VERSION 5.8 ;
BUSBITCHARS "[]" ;
DIVIDERCHAR "/" ;
UNITS
    DATABASE MICRONS 1000 ;
END UNITS

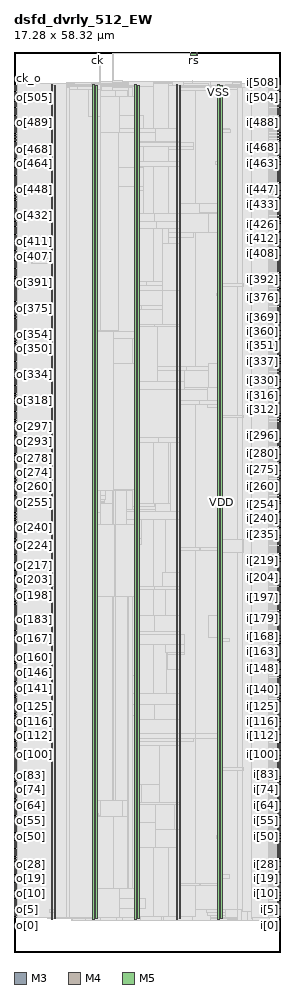
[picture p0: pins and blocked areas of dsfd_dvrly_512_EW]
MACRO dsfd_dvrly_512_EW
  FOREIGN dsfd_dvrly_512_EW 0 0 ;
  CLASS BLOCK ;
  SIZE 17.28 BY 58.32 ;
  PIN ck
    DIRECTION INPUT ;
    USE SIGNAL ;
    PORT
      LAYER M3 ;
        RECT  5.4 58.176 5.418 58.32 ;
    END
    PORT
      LAYER M3 ;
        RECT  5.4 57.595 5.418 58.188 ;
    END
  END ck
  PIN ck_o
    DIRECTION OUTPUT ;
    USE SIGNAL ;
    PORT
      LAYER M4 ;
        RECT  0 56.112 0.192 56.136 ;
    END
  END ck_o
  PIN i[0]
    DIRECTION INPUT ;
    USE SIGNAL ;
    PORT
      LAYER M4 ;
        RECT  17.088 2.208 17.28 2.232 ;
    END
  END i[0]
  PIN i[100]
    DIRECTION INPUT ;
    USE SIGNAL ;
    PORT
      LAYER M4 ;
        RECT  17.088 12.768 17.28 12.792 ;
    END
  END i[100]
  PIN i[101]
    DIRECTION INPUT ;
    USE SIGNAL ;
    PORT
      LAYER M4 ;
        RECT  17.088 12.864 17.28 12.888 ;
    END
  END i[101]
  PIN i[102]
    DIRECTION INPUT ;
    USE SIGNAL ;
    PORT
      LAYER M4 ;
        RECT  17.088 12.96 17.28 12.984 ;
    END
  END i[102]
  PIN i[103]
    DIRECTION INPUT ;
    USE SIGNAL ;
    PORT
      LAYER M4 ;
        RECT  17.088 13.104 17.28 13.128 ;
    END
  END i[103]
  PIN i[104]
    DIRECTION INPUT ;
    USE SIGNAL ;
    PORT
      LAYER M4 ;
        RECT  17.088 13.2 17.28 13.224 ;
    END
  END i[104]
  PIN i[105]
    DIRECTION INPUT ;
    USE SIGNAL ;
    PORT
      LAYER M4 ;
        RECT  17.088 13.296 17.28 13.32 ;
    END
  END i[105]
  PIN i[106]
    DIRECTION INPUT ;
    USE SIGNAL ;
    PORT
      LAYER M4 ;
        RECT  17.088 13.392 17.28 13.416 ;
    END
  END i[106]
  PIN i[107]
    DIRECTION INPUT ;
    USE SIGNAL ;
    PORT
      LAYER M4 ;
        RECT  17.088 13.488 17.28 13.512 ;
    END
  END i[107]
  PIN i[108]
    DIRECTION INPUT ;
    USE SIGNAL ;
    PORT
      LAYER M4 ;
        RECT  17.088 13.632 17.28 13.656 ;
    END
  END i[108]
  PIN i[109]
    DIRECTION INPUT ;
    USE SIGNAL ;
    PORT
      LAYER M4 ;
        RECT  17.088 13.728 17.28 13.752 ;
    END
  END i[109]
  PIN i[10]
    DIRECTION INPUT ;
    USE SIGNAL ;
    PORT
      LAYER M4 ;
        RECT  17.088 3.264 17.28 3.288 ;
    END
  END i[10]
  PIN i[110]
    DIRECTION INPUT ;
    USE SIGNAL ;
    PORT
      LAYER M4 ;
        RECT  17.088 13.824 17.28 13.848 ;
    END
  END i[110]
  PIN i[111]
    DIRECTION INPUT ;
    USE SIGNAL ;
    PORT
      LAYER M4 ;
        RECT  17.088 13.92 17.28 13.944 ;
    END
  END i[111]
  PIN i[112]
    DIRECTION INPUT ;
    USE SIGNAL ;
    PORT
      LAYER M4 ;
        RECT  17.088 14.016 17.28 14.04 ;
    END
  END i[112]
  PIN i[113]
    DIRECTION INPUT ;
    USE SIGNAL ;
    PORT
      LAYER M4 ;
        RECT  17.088 14.16 17.28 14.184 ;
    END
  END i[113]
  PIN i[114]
    DIRECTION INPUT ;
    USE SIGNAL ;
    PORT
      LAYER M4 ;
        RECT  17.088 14.256 17.28 14.28 ;
    END
  END i[114]
  PIN i[115]
    DIRECTION INPUT ;
    USE SIGNAL ;
    PORT
      LAYER M4 ;
        RECT  17.088 14.352 17.28 14.376 ;
    END
  END i[115]
  PIN i[116]
    DIRECTION INPUT ;
    USE SIGNAL ;
    PORT
      LAYER M4 ;
        RECT  17.088 14.448 17.28 14.472 ;
    END
  END i[116]
  PIN i[117]
    DIRECTION INPUT ;
    USE SIGNAL ;
    PORT
      LAYER M4 ;
        RECT  17.088 14.544 17.28 14.568 ;
    END
  END i[117]
  PIN i[118]
    DIRECTION INPUT ;
    USE SIGNAL ;
    PORT
      LAYER M4 ;
        RECT  17.088 14.688 17.28 14.712 ;
    END
  END i[118]
  PIN i[119]
    DIRECTION INPUT ;
    USE SIGNAL ;
    PORT
      LAYER M4 ;
        RECT  17.088 14.784 17.28 14.808 ;
    END
  END i[119]
  PIN i[11]
    DIRECTION INPUT ;
    USE SIGNAL ;
    PORT
      LAYER M4 ;
        RECT  17.088 3.408 17.28 3.432 ;
    END
  END i[11]
  PIN i[120]
    DIRECTION INPUT ;
    USE SIGNAL ;
    PORT
      LAYER M4 ;
        RECT  17.088 14.88 17.28 14.904 ;
    END
  END i[120]
  PIN i[121]
    DIRECTION INPUT ;
    USE SIGNAL ;
    PORT
      LAYER M4 ;
        RECT  17.088 14.976 17.28 15 ;
    END
  END i[121]
  PIN i[122]
    DIRECTION INPUT ;
    USE SIGNAL ;
    PORT
      LAYER M4 ;
        RECT  17.088 15.072 17.28 15.096 ;
    END
  END i[122]
  PIN i[123]
    DIRECTION INPUT ;
    USE SIGNAL ;
    PORT
      LAYER M4 ;
        RECT  17.088 15.216 17.28 15.24 ;
    END
  END i[123]
  PIN i[124]
    DIRECTION INPUT ;
    USE SIGNAL ;
    PORT
      LAYER M4 ;
        RECT  17.088 15.312 17.28 15.336 ;
    END
  END i[124]
  PIN i[125]
    DIRECTION INPUT ;
    USE SIGNAL ;
    PORT
      LAYER M4 ;
        RECT  17.088 15.408 17.28 15.432 ;
    END
  END i[125]
  PIN i[126]
    DIRECTION INPUT ;
    USE SIGNAL ;
    PORT
      LAYER M4 ;
        RECT  17.088 15.504 17.28 15.528 ;
    END
  END i[126]
  PIN i[127]
    DIRECTION INPUT ;
    USE SIGNAL ;
    PORT
      LAYER M4 ;
        RECT  17.088 15.6 17.28 15.624 ;
    END
  END i[127]
  PIN i[128]
    DIRECTION INPUT ;
    USE SIGNAL ;
    PORT
      LAYER M4 ;
        RECT  17.088 15.744 17.28 15.768 ;
    END
  END i[128]
  PIN i[129]
    DIRECTION INPUT ;
    USE SIGNAL ;
    PORT
      LAYER M4 ;
        RECT  17.088 15.84 17.28 15.864 ;
    END
  END i[129]
  PIN i[12]
    DIRECTION INPUT ;
    USE SIGNAL ;
    PORT
      LAYER M4 ;
        RECT  17.088 3.504 17.28 3.528 ;
    END
  END i[12]
  PIN i[130]
    DIRECTION INPUT ;
    USE SIGNAL ;
    PORT
      LAYER M4 ;
        RECT  17.088 15.936 17.28 15.96 ;
    END
  END i[130]
  PIN i[131]
    DIRECTION INPUT ;
    USE SIGNAL ;
    PORT
      LAYER M4 ;
        RECT  17.088 16.032 17.28 16.056 ;
    END
  END i[131]
  PIN i[132]
    DIRECTION INPUT ;
    USE SIGNAL ;
    PORT
      LAYER M4 ;
        RECT  17.088 16.128 17.28 16.152 ;
    END
  END i[132]
  PIN i[133]
    DIRECTION INPUT ;
    USE SIGNAL ;
    PORT
      LAYER M4 ;
        RECT  17.088 16.272 17.28 16.296 ;
    END
  END i[133]
  PIN i[134]
    DIRECTION INPUT ;
    USE SIGNAL ;
    PORT
      LAYER M4 ;
        RECT  17.088 16.368 17.28 16.392 ;
    END
  END i[134]
  PIN i[135]
    DIRECTION INPUT ;
    USE SIGNAL ;
    PORT
      LAYER M4 ;
        RECT  17.088 16.464 17.28 16.488 ;
    END
  END i[135]
  PIN i[136]
    DIRECTION INPUT ;
    USE SIGNAL ;
    PORT
      LAYER M4 ;
        RECT  17.088 16.56 17.28 16.584 ;
    END
  END i[136]
  PIN i[137]
    DIRECTION INPUT ;
    USE SIGNAL ;
    PORT
      LAYER M4 ;
        RECT  17.088 16.656 17.28 16.68 ;
    END
  END i[137]
  PIN i[138]
    DIRECTION INPUT ;
    USE SIGNAL ;
    PORT
      LAYER M4 ;
        RECT  17.088 16.8 17.28 16.824 ;
    END
  END i[138]
  PIN i[139]
    DIRECTION INPUT ;
    USE SIGNAL ;
    PORT
      LAYER M4 ;
        RECT  17.088 16.896 17.28 16.92 ;
    END
  END i[139]
  PIN i[13]
    DIRECTION INPUT ;
    USE SIGNAL ;
    PORT
      LAYER M4 ;
        RECT  17.088 3.6 17.28 3.624 ;
    END
  END i[13]
  PIN i[140]
    DIRECTION INPUT ;
    USE SIGNAL ;
    PORT
      LAYER M4 ;
        RECT  17.088 16.992 17.28 17.016 ;
    END
  END i[140]
  PIN i[141]
    DIRECTION INPUT ;
    USE SIGNAL ;
    PORT
      LAYER M4 ;
        RECT  17.088 17.088 17.28 17.112 ;
    END
  END i[141]
  PIN i[142]
    DIRECTION INPUT ;
    USE SIGNAL ;
    PORT
      LAYER M4 ;
        RECT  17.088 17.184 17.28 17.208 ;
    END
  END i[142]
  PIN i[143]
    DIRECTION INPUT ;
    USE SIGNAL ;
    PORT
      LAYER M4 ;
        RECT  17.088 17.328 17.28 17.352 ;
    END
  END i[143]
  PIN i[144]
    DIRECTION INPUT ;
    USE SIGNAL ;
    PORT
      LAYER M4 ;
        RECT  17.088 17.424 17.28 17.448 ;
    END
  END i[144]
  PIN i[145]
    DIRECTION INPUT ;
    USE SIGNAL ;
    PORT
      LAYER M4 ;
        RECT  17.088 17.52 17.28 17.544 ;
    END
  END i[145]
  PIN i[146]
    DIRECTION INPUT ;
    USE SIGNAL ;
    PORT
      LAYER M4 ;
        RECT  17.088 17.616 17.28 17.64 ;
    END
  END i[146]
  PIN i[147]
    DIRECTION INPUT ;
    USE SIGNAL ;
    PORT
      LAYER M4 ;
        RECT  17.088 17.712 17.28 17.736 ;
    END
  END i[147]
  PIN i[148]
    DIRECTION INPUT ;
    USE SIGNAL ;
    PORT
      LAYER M4 ;
        RECT  17.088 17.856 17.28 17.88 ;
    END
  END i[148]
  PIN i[149]
    DIRECTION INPUT ;
    USE SIGNAL ;
    PORT
      LAYER M4 ;
        RECT  17.088 17.952 17.28 17.976 ;
    END
  END i[149]
  PIN i[14]
    DIRECTION INPUT ;
    USE SIGNAL ;
    PORT
      LAYER M4 ;
        RECT  17.088 3.696 17.28 3.72 ;
    END
  END i[14]
  PIN i[150]
    DIRECTION INPUT ;
    USE SIGNAL ;
    PORT
      LAYER M4 ;
        RECT  17.088 18.048 17.28 18.072 ;
    END
  END i[150]
  PIN i[151]
    DIRECTION INPUT ;
    USE SIGNAL ;
    PORT
      LAYER M4 ;
        RECT  17.088 18.144 17.28 18.168 ;
    END
  END i[151]
  PIN i[152]
    DIRECTION INPUT ;
    USE SIGNAL ;
    PORT
      LAYER M4 ;
        RECT  17.088 18.24 17.28 18.264 ;
    END
  END i[152]
  PIN i[153]
    DIRECTION INPUT ;
    USE SIGNAL ;
    PORT
      LAYER M4 ;
        RECT  17.088 18.384 17.28 18.408 ;
    END
  END i[153]
  PIN i[154]
    DIRECTION INPUT ;
    USE SIGNAL ;
    PORT
      LAYER M4 ;
        RECT  17.088 18.48 17.28 18.504 ;
    END
  END i[154]
  PIN i[155]
    DIRECTION INPUT ;
    USE SIGNAL ;
    PORT
      LAYER M4 ;
        RECT  17.088 18.576 17.28 18.6 ;
    END
  END i[155]
  PIN i[156]
    DIRECTION INPUT ;
    USE SIGNAL ;
    PORT
      LAYER M4 ;
        RECT  17.088 18.672 17.28 18.696 ;
    END
  END i[156]
  PIN i[157]
    DIRECTION INPUT ;
    USE SIGNAL ;
    PORT
      LAYER M4 ;
        RECT  17.088 18.768 17.28 18.792 ;
    END
  END i[157]
  PIN i[158]
    DIRECTION INPUT ;
    USE SIGNAL ;
    PORT
      LAYER M4 ;
        RECT  17.088 18.912 17.28 18.936 ;
    END
  END i[158]
  PIN i[159]
    DIRECTION INPUT ;
    USE SIGNAL ;
    PORT
      LAYER M4 ;
        RECT  17.088 19.008 17.28 19.032 ;
    END
  END i[159]
  PIN i[15]
    DIRECTION INPUT ;
    USE SIGNAL ;
    PORT
      LAYER M4 ;
        RECT  17.088 3.792 17.28 3.816 ;
    END
  END i[15]
  PIN i[160]
    DIRECTION INPUT ;
    USE SIGNAL ;
    PORT
      LAYER M4 ;
        RECT  17.088 19.104 17.28 19.128 ;
    END
  END i[160]
  PIN i[161]
    DIRECTION INPUT ;
    USE SIGNAL ;
    PORT
      LAYER M4 ;
        RECT  17.088 19.2 17.28 19.224 ;
    END
  END i[161]
  PIN i[162]
    DIRECTION INPUT ;
    USE SIGNAL ;
    PORT
      LAYER M4 ;
        RECT  17.088 19.296 17.28 19.32 ;
    END
  END i[162]
  PIN i[163]
    DIRECTION INPUT ;
    USE SIGNAL ;
    PORT
      LAYER M4 ;
        RECT  17.088 19.44 17.28 19.464 ;
    END
  END i[163]
  PIN i[164]
    DIRECTION INPUT ;
    USE SIGNAL ;
    PORT
      LAYER M4 ;
        RECT  17.088 19.536 17.28 19.56 ;
    END
  END i[164]
  PIN i[165]
    DIRECTION INPUT ;
    USE SIGNAL ;
    PORT
      LAYER M4 ;
        RECT  17.088 19.632 17.28 19.656 ;
    END
  END i[165]
  PIN i[166]
    DIRECTION INPUT ;
    USE SIGNAL ;
    PORT
      LAYER M4 ;
        RECT  17.088 19.728 17.28 19.752 ;
    END
  END i[166]
  PIN i[167]
    DIRECTION INPUT ;
    USE SIGNAL ;
    PORT
      LAYER M4 ;
        RECT  17.088 19.824 17.28 19.848 ;
    END
  END i[167]
  PIN i[168]
    DIRECTION INPUT ;
    USE SIGNAL ;
    PORT
      LAYER M4 ;
        RECT  17.088 19.92 17.28 19.944 ;
    END
  END i[168]
  PIN i[169]
    DIRECTION INPUT ;
    USE SIGNAL ;
    PORT
      LAYER M4 ;
        RECT  17.088 20.064 17.28 20.088 ;
    END
  END i[169]
  PIN i[16]
    DIRECTION INPUT ;
    USE SIGNAL ;
    PORT
      LAYER M4 ;
        RECT  17.088 3.936 17.28 3.96 ;
    END
  END i[16]
  PIN i[170]
    DIRECTION INPUT ;
    USE SIGNAL ;
    PORT
      LAYER M4 ;
        RECT  17.088 20.16 17.28 20.184 ;
    END
  END i[170]
  PIN i[171]
    DIRECTION INPUT ;
    USE SIGNAL ;
    PORT
      LAYER M4 ;
        RECT  17.088 20.256 17.28 20.28 ;
    END
  END i[171]
  PIN i[172]
    DIRECTION INPUT ;
    USE SIGNAL ;
    PORT
      LAYER M4 ;
        RECT  17.088 20.352 17.28 20.376 ;
    END
  END i[172]
  PIN i[173]
    DIRECTION INPUT ;
    USE SIGNAL ;
    PORT
      LAYER M4 ;
        RECT  17.088 20.448 17.28 20.472 ;
    END
  END i[173]
  PIN i[174]
    DIRECTION INPUT ;
    USE SIGNAL ;
    PORT
      LAYER M4 ;
        RECT  17.088 20.592 17.28 20.616 ;
    END
  END i[174]
  PIN i[175]
    DIRECTION INPUT ;
    USE SIGNAL ;
    PORT
      LAYER M4 ;
        RECT  17.088 20.688 17.28 20.712 ;
    END
  END i[175]
  PIN i[176]
    DIRECTION INPUT ;
    USE SIGNAL ;
    PORT
      LAYER M4 ;
        RECT  17.088 20.784 17.28 20.808 ;
    END
  END i[176]
  PIN i[177]
    DIRECTION INPUT ;
    USE SIGNAL ;
    PORT
      LAYER M4 ;
        RECT  17.088 20.88 17.28 20.904 ;
    END
  END i[177]
  PIN i[178]
    DIRECTION INPUT ;
    USE SIGNAL ;
    PORT
      LAYER M4 ;
        RECT  17.088 20.976 17.28 21 ;
    END
  END i[178]
  PIN i[179]
    DIRECTION INPUT ;
    USE SIGNAL ;
    PORT
      LAYER M4 ;
        RECT  17.088 21.12 17.28 21.144 ;
    END
  END i[179]
  PIN i[17]
    DIRECTION INPUT ;
    USE SIGNAL ;
    PORT
      LAYER M4 ;
        RECT  17.088 4.032 17.28 4.056 ;
    END
  END i[17]
  PIN i[180]
    DIRECTION INPUT ;
    USE SIGNAL ;
    PORT
      LAYER M4 ;
        RECT  17.088 21.216 17.28 21.24 ;
    END
  END i[180]
  PIN i[181]
    DIRECTION INPUT ;
    USE SIGNAL ;
    PORT
      LAYER M4 ;
        RECT  17.088 21.312 17.28 21.336 ;
    END
  END i[181]
  PIN i[182]
    DIRECTION INPUT ;
    USE SIGNAL ;
    PORT
      LAYER M4 ;
        RECT  17.088 21.408 17.28 21.432 ;
    END
  END i[182]
  PIN i[183]
    DIRECTION INPUT ;
    USE SIGNAL ;
    PORT
      LAYER M4 ;
        RECT  17.088 21.504 17.28 21.528 ;
    END
  END i[183]
  PIN i[184]
    DIRECTION INPUT ;
    USE SIGNAL ;
    PORT
      LAYER M4 ;
        RECT  17.088 21.648 17.28 21.672 ;
    END
  END i[184]
  PIN i[185]
    DIRECTION INPUT ;
    USE SIGNAL ;
    PORT
      LAYER M4 ;
        RECT  17.088 21.744 17.28 21.768 ;
    END
  END i[185]
  PIN i[186]
    DIRECTION INPUT ;
    USE SIGNAL ;
    PORT
      LAYER M4 ;
        RECT  17.088 21.84 17.28 21.864 ;
    END
  END i[186]
  PIN i[187]
    DIRECTION INPUT ;
    USE SIGNAL ;
    PORT
      LAYER M4 ;
        RECT  17.088 21.936 17.28 21.96 ;
    END
  END i[187]
  PIN i[188]
    DIRECTION INPUT ;
    USE SIGNAL ;
    PORT
      LAYER M4 ;
        RECT  17.088 22.032 17.28 22.056 ;
    END
  END i[188]
  PIN i[189]
    DIRECTION INPUT ;
    USE SIGNAL ;
    PORT
      LAYER M4 ;
        RECT  17.088 22.176 17.28 22.2 ;
    END
  END i[189]
  PIN i[18]
    DIRECTION INPUT ;
    USE SIGNAL ;
    PORT
      LAYER M4 ;
        RECT  17.088 4.128 17.28 4.152 ;
    END
  END i[18]
  PIN i[190]
    DIRECTION INPUT ;
    USE SIGNAL ;
    PORT
      LAYER M4 ;
        RECT  17.088 22.272 17.28 22.296 ;
    END
  END i[190]
  PIN i[191]
    DIRECTION INPUT ;
    USE SIGNAL ;
    PORT
      LAYER M4 ;
        RECT  17.088 22.368 17.28 22.392 ;
    END
  END i[191]
  PIN i[192]
    DIRECTION INPUT ;
    USE SIGNAL ;
    PORT
      LAYER M4 ;
        RECT  17.088 22.464 17.28 22.488 ;
    END
  END i[192]
  PIN i[193]
    DIRECTION INPUT ;
    USE SIGNAL ;
    PORT
      LAYER M4 ;
        RECT  17.088 22.56 17.28 22.584 ;
    END
  END i[193]
  PIN i[194]
    DIRECTION INPUT ;
    USE SIGNAL ;
    PORT
      LAYER M4 ;
        RECT  17.088 22.704 17.28 22.728 ;
    END
  END i[194]
  PIN i[195]
    DIRECTION INPUT ;
    USE SIGNAL ;
    PORT
      LAYER M4 ;
        RECT  17.088 22.8 17.28 22.824 ;
    END
  END i[195]
  PIN i[196]
    DIRECTION INPUT ;
    USE SIGNAL ;
    PORT
      LAYER M4 ;
        RECT  17.088 22.896 17.28 22.92 ;
    END
  END i[196]
  PIN i[197]
    DIRECTION INPUT ;
    USE SIGNAL ;
    PORT
      LAYER M4 ;
        RECT  17.088 22.992 17.28 23.016 ;
    END
  END i[197]
  PIN i[198]
    DIRECTION INPUT ;
    USE SIGNAL ;
    PORT
      LAYER M4 ;
        RECT  17.088 23.088 17.28 23.112 ;
    END
  END i[198]
  PIN i[199]
    DIRECTION INPUT ;
    USE SIGNAL ;
    PORT
      LAYER M4 ;
        RECT  17.088 23.232 17.28 23.256 ;
    END
  END i[199]
  PIN i[19]
    DIRECTION INPUT ;
    USE SIGNAL ;
    PORT
      LAYER M4 ;
        RECT  17.088 4.224 17.28 4.248 ;
    END
  END i[19]
  PIN i[1]
    DIRECTION INPUT ;
    USE SIGNAL ;
    PORT
      LAYER M4 ;
        RECT  17.088 2.352 17.28 2.376 ;
    END
  END i[1]
  PIN i[200]
    DIRECTION INPUT ;
    USE SIGNAL ;
    PORT
      LAYER M4 ;
        RECT  17.088 23.328 17.28 23.352 ;
    END
  END i[200]
  PIN i[201]
    DIRECTION INPUT ;
    USE SIGNAL ;
    PORT
      LAYER M4 ;
        RECT  17.088 23.424 17.28 23.448 ;
    END
  END i[201]
  PIN i[202]
    DIRECTION INPUT ;
    USE SIGNAL ;
    PORT
      LAYER M4 ;
        RECT  17.088 23.52 17.28 23.544 ;
    END
  END i[202]
  PIN i[203]
    DIRECTION INPUT ;
    USE SIGNAL ;
    PORT
      LAYER M4 ;
        RECT  17.088 23.616 17.28 23.64 ;
    END
  END i[203]
  PIN i[204]
    DIRECTION INPUT ;
    USE SIGNAL ;
    PORT
      LAYER M4 ;
        RECT  17.088 23.76 17.28 23.784 ;
    END
  END i[204]
  PIN i[205]
    DIRECTION INPUT ;
    USE SIGNAL ;
    PORT
      LAYER M4 ;
        RECT  17.088 23.856 17.28 23.88 ;
    END
  END i[205]
  PIN i[206]
    DIRECTION INPUT ;
    USE SIGNAL ;
    PORT
      LAYER M4 ;
        RECT  17.088 23.952 17.28 23.976 ;
    END
  END i[206]
  PIN i[207]
    DIRECTION INPUT ;
    USE SIGNAL ;
    PORT
      LAYER M4 ;
        RECT  17.088 24.048 17.28 24.072 ;
    END
  END i[207]
  PIN i[208]
    DIRECTION INPUT ;
    USE SIGNAL ;
    PORT
      LAYER M4 ;
        RECT  17.088 24.144 17.28 24.168 ;
    END
  END i[208]
  PIN i[209]
    DIRECTION INPUT ;
    USE SIGNAL ;
    PORT
      LAYER M4 ;
        RECT  17.088 24.288 17.28 24.312 ;
    END
  END i[209]
  PIN i[20]
    DIRECTION INPUT ;
    USE SIGNAL ;
    PORT
      LAYER M4 ;
        RECT  17.088 4.32 17.28 4.344 ;
    END
  END i[20]
  PIN i[210]
    DIRECTION INPUT ;
    USE SIGNAL ;
    PORT
      LAYER M4 ;
        RECT  17.088 24.384 17.28 24.408 ;
    END
  END i[210]
  PIN i[211]
    DIRECTION INPUT ;
    USE SIGNAL ;
    PORT
      LAYER M4 ;
        RECT  17.088 24.48 17.28 24.504 ;
    END
  END i[211]
  PIN i[212]
    DIRECTION INPUT ;
    USE SIGNAL ;
    PORT
      LAYER M4 ;
        RECT  17.088 24.576 17.28 24.6 ;
    END
  END i[212]
  PIN i[213]
    DIRECTION INPUT ;
    USE SIGNAL ;
    PORT
      LAYER M4 ;
        RECT  17.088 24.672 17.28 24.696 ;
    END
  END i[213]
  PIN i[214]
    DIRECTION INPUT ;
    USE SIGNAL ;
    PORT
      LAYER M4 ;
        RECT  17.088 24.816 17.28 24.84 ;
    END
  END i[214]
  PIN i[215]
    DIRECTION INPUT ;
    USE SIGNAL ;
    PORT
      LAYER M4 ;
        RECT  17.088 24.912 17.28 24.936 ;
    END
  END i[215]
  PIN i[216]
    DIRECTION INPUT ;
    USE SIGNAL ;
    PORT
      LAYER M4 ;
        RECT  17.088 25.008 17.28 25.032 ;
    END
  END i[216]
  PIN i[217]
    DIRECTION INPUT ;
    USE SIGNAL ;
    PORT
      LAYER M4 ;
        RECT  17.088 25.104 17.28 25.128 ;
    END
  END i[217]
  PIN i[218]
    DIRECTION INPUT ;
    USE SIGNAL ;
    PORT
      LAYER M4 ;
        RECT  17.088 25.2 17.28 25.224 ;
    END
  END i[218]
  PIN i[219]
    DIRECTION INPUT ;
    USE SIGNAL ;
    PORT
      LAYER M4 ;
        RECT  17.088 25.344 17.28 25.368 ;
    END
  END i[219]
  PIN i[21]
    DIRECTION INPUT ;
    USE SIGNAL ;
    PORT
      LAYER M4 ;
        RECT  17.088 4.416 17.28 4.44 ;
    END
  END i[21]
  PIN i[220]
    DIRECTION INPUT ;
    USE SIGNAL ;
    PORT
      LAYER M4 ;
        RECT  17.088 25.44 17.28 25.464 ;
    END
  END i[220]
  PIN i[221]
    DIRECTION INPUT ;
    USE SIGNAL ;
    PORT
      LAYER M4 ;
        RECT  17.088 25.536 17.28 25.56 ;
    END
  END i[221]
  PIN i[222]
    DIRECTION INPUT ;
    USE SIGNAL ;
    PORT
      LAYER M4 ;
        RECT  17.088 25.632 17.28 25.656 ;
    END
  END i[222]
  PIN i[223]
    DIRECTION INPUT ;
    USE SIGNAL ;
    PORT
      LAYER M4 ;
        RECT  17.088 25.728 17.28 25.752 ;
    END
  END i[223]
  PIN i[224]
    DIRECTION INPUT ;
    USE SIGNAL ;
    PORT
      LAYER M4 ;
        RECT  17.088 25.872 17.28 25.896 ;
    END
  END i[224]
  PIN i[225]
    DIRECTION INPUT ;
    USE SIGNAL ;
    PORT
      LAYER M4 ;
        RECT  17.088 25.968 17.28 25.992 ;
    END
  END i[225]
  PIN i[226]
    DIRECTION INPUT ;
    USE SIGNAL ;
    PORT
      LAYER M4 ;
        RECT  17.088 26.064 17.28 26.088 ;
    END
  END i[226]
  PIN i[227]
    DIRECTION INPUT ;
    USE SIGNAL ;
    PORT
      LAYER M4 ;
        RECT  17.088 26.16 17.28 26.184 ;
    END
  END i[227]
  PIN i[228]
    DIRECTION INPUT ;
    USE SIGNAL ;
    PORT
      LAYER M4 ;
        RECT  17.088 26.256 17.28 26.28 ;
    END
  END i[228]
  PIN i[229]
    DIRECTION INPUT ;
    USE SIGNAL ;
    PORT
      LAYER M4 ;
        RECT  17.088 26.4 17.28 26.424 ;
    END
  END i[229]
  PIN i[22]
    DIRECTION INPUT ;
    USE SIGNAL ;
    PORT
      LAYER M4 ;
        RECT  17.088 4.56 17.28 4.584 ;
    END
  END i[22]
  PIN i[230]
    DIRECTION INPUT ;
    USE SIGNAL ;
    PORT
      LAYER M4 ;
        RECT  17.088 26.496 17.28 26.52 ;
    END
  END i[230]
  PIN i[231]
    DIRECTION INPUT ;
    USE SIGNAL ;
    PORT
      LAYER M4 ;
        RECT  17.088 26.592 17.28 26.616 ;
    END
  END i[231]
  PIN i[232]
    DIRECTION INPUT ;
    USE SIGNAL ;
    PORT
      LAYER M4 ;
        RECT  17.088 26.688 17.28 26.712 ;
    END
  END i[232]
  PIN i[233]
    DIRECTION INPUT ;
    USE SIGNAL ;
    PORT
      LAYER M4 ;
        RECT  17.088 26.784 17.28 26.808 ;
    END
  END i[233]
  PIN i[234]
    DIRECTION INPUT ;
    USE SIGNAL ;
    PORT
      LAYER M4 ;
        RECT  17.088 26.928 17.28 26.952 ;
    END
  END i[234]
  PIN i[235]
    DIRECTION INPUT ;
    USE SIGNAL ;
    PORT
      LAYER M4 ;
        RECT  17.088 27.024 17.28 27.048 ;
    END
  END i[235]
  PIN i[236]
    DIRECTION INPUT ;
    USE SIGNAL ;
    PORT
      LAYER M4 ;
        RECT  17.088 27.12 17.28 27.144 ;
    END
  END i[236]
  PIN i[237]
    DIRECTION INPUT ;
    USE SIGNAL ;
    PORT
      LAYER M4 ;
        RECT  17.088 27.216 17.28 27.24 ;
    END
  END i[237]
  PIN i[238]
    DIRECTION INPUT ;
    USE SIGNAL ;
    PORT
      LAYER M4 ;
        RECT  17.088 27.312 17.28 27.336 ;
    END
  END i[238]
  PIN i[239]
    DIRECTION INPUT ;
    USE SIGNAL ;
    PORT
      LAYER M4 ;
        RECT  17.088 27.408 17.28 27.432 ;
    END
  END i[239]
  PIN i[23]
    DIRECTION INPUT ;
    USE SIGNAL ;
    PORT
      LAYER M4 ;
        RECT  17.088 4.656 17.28 4.68 ;
    END
  END i[23]
  PIN i[240]
    DIRECTION INPUT ;
    USE SIGNAL ;
    PORT
      LAYER M4 ;
        RECT  17.088 27.552 17.28 27.576 ;
    END
  END i[240]
  PIN i[241]
    DIRECTION INPUT ;
    USE SIGNAL ;
    PORT
      LAYER M4 ;
        RECT  17.088 27.648 17.28 27.672 ;
    END
  END i[241]
  PIN i[242]
    DIRECTION INPUT ;
    USE SIGNAL ;
    PORT
      LAYER M4 ;
        RECT  17.088 27.744 17.28 27.768 ;
    END
  END i[242]
  PIN i[243]
    DIRECTION INPUT ;
    USE SIGNAL ;
    PORT
      LAYER M4 ;
        RECT  17.088 27.84 17.28 27.864 ;
    END
  END i[243]
  PIN i[244]
    DIRECTION INPUT ;
    USE SIGNAL ;
    PORT
      LAYER M4 ;
        RECT  17.088 27.936 17.28 27.96 ;
    END
  END i[244]
  PIN i[245]
    DIRECTION INPUT ;
    USE SIGNAL ;
    PORT
      LAYER M4 ;
        RECT  17.088 28.08 17.28 28.104 ;
    END
  END i[245]
  PIN i[246]
    DIRECTION INPUT ;
    USE SIGNAL ;
    PORT
      LAYER M4 ;
        RECT  17.088 28.176 17.28 28.2 ;
    END
  END i[246]
  PIN i[247]
    DIRECTION INPUT ;
    USE SIGNAL ;
    PORT
      LAYER M4 ;
        RECT  17.088 28.272 17.28 28.296 ;
    END
  END i[247]
  PIN i[248]
    DIRECTION INPUT ;
    USE SIGNAL ;
    PORT
      LAYER M4 ;
        RECT  17.088 28.368 17.28 28.392 ;
    END
  END i[248]
  PIN i[249]
    DIRECTION INPUT ;
    USE SIGNAL ;
    PORT
      LAYER M4 ;
        RECT  17.088 28.464 17.28 28.488 ;
    END
  END i[249]
  PIN i[24]
    DIRECTION INPUT ;
    USE SIGNAL ;
    PORT
      LAYER M4 ;
        RECT  17.088 4.752 17.28 4.776 ;
    END
  END i[24]
  PIN i[250]
    DIRECTION INPUT ;
    USE SIGNAL ;
    PORT
      LAYER M4 ;
        RECT  17.088 28.608 17.28 28.632 ;
    END
  END i[250]
  PIN i[251]
    DIRECTION INPUT ;
    USE SIGNAL ;
    PORT
      LAYER M4 ;
        RECT  17.088 28.704 17.28 28.728 ;
    END
  END i[251]
  PIN i[252]
    DIRECTION INPUT ;
    USE SIGNAL ;
    PORT
      LAYER M4 ;
        RECT  17.088 28.8 17.28 28.824 ;
    END
  END i[252]
  PIN i[253]
    DIRECTION INPUT ;
    USE SIGNAL ;
    PORT
      LAYER M4 ;
        RECT  17.088 28.896 17.28 28.92 ;
    END
  END i[253]
  PIN i[254]
    DIRECTION INPUT ;
    USE SIGNAL ;
    PORT
      LAYER M4 ;
        RECT  17.088 28.992 17.28 29.016 ;
    END
  END i[254]
  PIN i[255]
    DIRECTION INPUT ;
    USE SIGNAL ;
    PORT
      LAYER M4 ;
        RECT  17.088 29.136 17.28 29.16 ;
    END
  END i[255]
  PIN i[256]
    DIRECTION INPUT ;
    USE SIGNAL ;
    PORT
      LAYER M4 ;
        RECT  17.088 29.232 17.28 29.256 ;
    END
  END i[256]
  PIN i[257]
    DIRECTION INPUT ;
    USE SIGNAL ;
    PORT
      LAYER M4 ;
        RECT  17.088 29.328 17.28 29.352 ;
    END
  END i[257]
  PIN i[258]
    DIRECTION INPUT ;
    USE SIGNAL ;
    PORT
      LAYER M4 ;
        RECT  17.088 29.424 17.28 29.448 ;
    END
  END i[258]
  PIN i[259]
    DIRECTION INPUT ;
    USE SIGNAL ;
    PORT
      LAYER M4 ;
        RECT  17.088 29.52 17.28 29.544 ;
    END
  END i[259]
  PIN i[25]
    DIRECTION INPUT ;
    USE SIGNAL ;
    PORT
      LAYER M4 ;
        RECT  17.088 4.848 17.28 4.872 ;
    END
  END i[25]
  PIN i[260]
    DIRECTION INPUT ;
    USE SIGNAL ;
    PORT
      LAYER M4 ;
        RECT  17.088 29.664 17.28 29.688 ;
    END
  END i[260]
  PIN i[261]
    DIRECTION INPUT ;
    USE SIGNAL ;
    PORT
      LAYER M4 ;
        RECT  17.088 29.76 17.28 29.784 ;
    END
  END i[261]
  PIN i[262]
    DIRECTION INPUT ;
    USE SIGNAL ;
    PORT
      LAYER M4 ;
        RECT  17.088 29.856 17.28 29.88 ;
    END
  END i[262]
  PIN i[263]
    DIRECTION INPUT ;
    USE SIGNAL ;
    PORT
      LAYER M4 ;
        RECT  17.088 29.952 17.28 29.976 ;
    END
  END i[263]
  PIN i[264]
    DIRECTION INPUT ;
    USE SIGNAL ;
    PORT
      LAYER M4 ;
        RECT  17.088 30.048 17.28 30.072 ;
    END
  END i[264]
  PIN i[265]
    DIRECTION INPUT ;
    USE SIGNAL ;
    PORT
      LAYER M4 ;
        RECT  17.088 30.192 17.28 30.216 ;
    END
  END i[265]
  PIN i[266]
    DIRECTION INPUT ;
    USE SIGNAL ;
    PORT
      LAYER M4 ;
        RECT  17.088 30.288 17.28 30.312 ;
    END
  END i[266]
  PIN i[267]
    DIRECTION INPUT ;
    USE SIGNAL ;
    PORT
      LAYER M4 ;
        RECT  17.088 30.384 17.28 30.408 ;
    END
  END i[267]
  PIN i[268]
    DIRECTION INPUT ;
    USE SIGNAL ;
    PORT
      LAYER M4 ;
        RECT  17.088 30.48 17.28 30.504 ;
    END
  END i[268]
  PIN i[269]
    DIRECTION INPUT ;
    USE SIGNAL ;
    PORT
      LAYER M4 ;
        RECT  17.088 30.576 17.28 30.6 ;
    END
  END i[269]
  PIN i[26]
    DIRECTION INPUT ;
    USE SIGNAL ;
    PORT
      LAYER M4 ;
        RECT  17.088 4.944 17.28 4.968 ;
    END
  END i[26]
  PIN i[270]
    DIRECTION INPUT ;
    USE SIGNAL ;
    PORT
      LAYER M4 ;
        RECT  17.088 30.72 17.28 30.744 ;
    END
  END i[270]
  PIN i[271]
    DIRECTION INPUT ;
    USE SIGNAL ;
    PORT
      LAYER M4 ;
        RECT  17.088 30.816 17.28 30.84 ;
    END
  END i[271]
  PIN i[272]
    DIRECTION INPUT ;
    USE SIGNAL ;
    PORT
      LAYER M4 ;
        RECT  17.088 30.912 17.28 30.936 ;
    END
  END i[272]
  PIN i[273]
    DIRECTION INPUT ;
    USE SIGNAL ;
    PORT
      LAYER M4 ;
        RECT  17.088 31.008 17.28 31.032 ;
    END
  END i[273]
  PIN i[274]
    DIRECTION INPUT ;
    USE SIGNAL ;
    PORT
      LAYER M4 ;
        RECT  17.088 31.104 17.28 31.128 ;
    END
  END i[274]
  PIN i[275]
    DIRECTION INPUT ;
    USE SIGNAL ;
    PORT
      LAYER M4 ;
        RECT  17.088 31.248 17.28 31.272 ;
    END
  END i[275]
  PIN i[276]
    DIRECTION INPUT ;
    USE SIGNAL ;
    PORT
      LAYER M4 ;
        RECT  17.088 31.344 17.28 31.368 ;
    END
  END i[276]
  PIN i[277]
    DIRECTION INPUT ;
    USE SIGNAL ;
    PORT
      LAYER M4 ;
        RECT  17.088 31.44 17.28 31.464 ;
    END
  END i[277]
  PIN i[278]
    DIRECTION INPUT ;
    USE SIGNAL ;
    PORT
      LAYER M4 ;
        RECT  17.088 31.536 17.28 31.56 ;
    END
  END i[278]
  PIN i[279]
    DIRECTION INPUT ;
    USE SIGNAL ;
    PORT
      LAYER M4 ;
        RECT  17.088 31.632 17.28 31.656 ;
    END
  END i[279]
  PIN i[27]
    DIRECTION INPUT ;
    USE SIGNAL ;
    PORT
      LAYER M4 ;
        RECT  17.088 5.088 17.28 5.112 ;
    END
  END i[27]
  PIN i[280]
    DIRECTION INPUT ;
    USE SIGNAL ;
    PORT
      LAYER M4 ;
        RECT  17.088 31.776 17.28 31.8 ;
    END
  END i[280]
  PIN i[281]
    DIRECTION INPUT ;
    USE SIGNAL ;
    PORT
      LAYER M4 ;
        RECT  17.088 31.872 17.28 31.896 ;
    END
  END i[281]
  PIN i[282]
    DIRECTION INPUT ;
    USE SIGNAL ;
    PORT
      LAYER M4 ;
        RECT  17.088 31.968 17.28 31.992 ;
    END
  END i[282]
  PIN i[283]
    DIRECTION INPUT ;
    USE SIGNAL ;
    PORT
      LAYER M4 ;
        RECT  17.088 32.064 17.28 32.088 ;
    END
  END i[283]
  PIN i[284]
    DIRECTION INPUT ;
    USE SIGNAL ;
    PORT
      LAYER M4 ;
        RECT  17.088 32.16 17.28 32.184 ;
    END
  END i[284]
  PIN i[285]
    DIRECTION INPUT ;
    USE SIGNAL ;
    PORT
      LAYER M4 ;
        RECT  17.088 32.304 17.28 32.328 ;
    END
  END i[285]
  PIN i[286]
    DIRECTION INPUT ;
    USE SIGNAL ;
    PORT
      LAYER M4 ;
        RECT  17.088 32.4 17.28 32.424 ;
    END
  END i[286]
  PIN i[287]
    DIRECTION INPUT ;
    USE SIGNAL ;
    PORT
      LAYER M4 ;
        RECT  17.088 32.496 17.28 32.52 ;
    END
  END i[287]
  PIN i[288]
    DIRECTION INPUT ;
    USE SIGNAL ;
    PORT
      LAYER M4 ;
        RECT  17.088 32.592 17.28 32.616 ;
    END
  END i[288]
  PIN i[289]
    DIRECTION INPUT ;
    USE SIGNAL ;
    PORT
      LAYER M4 ;
        RECT  17.088 32.688 17.28 32.712 ;
    END
  END i[289]
  PIN i[28]
    DIRECTION INPUT ;
    USE SIGNAL ;
    PORT
      LAYER M4 ;
        RECT  17.088 5.184 17.28 5.208 ;
    END
  END i[28]
  PIN i[290]
    DIRECTION INPUT ;
    USE SIGNAL ;
    PORT
      LAYER M4 ;
        RECT  17.088 32.832 17.28 32.856 ;
    END
  END i[290]
  PIN i[291]
    DIRECTION INPUT ;
    USE SIGNAL ;
    PORT
      LAYER M4 ;
        RECT  17.088 32.928 17.28 32.952 ;
    END
  END i[291]
  PIN i[292]
    DIRECTION INPUT ;
    USE SIGNAL ;
    PORT
      LAYER M4 ;
        RECT  17.088 33.024 17.28 33.048 ;
    END
  END i[292]
  PIN i[293]
    DIRECTION INPUT ;
    USE SIGNAL ;
    PORT
      LAYER M4 ;
        RECT  17.088 33.12 17.28 33.144 ;
    END
  END i[293]
  PIN i[294]
    DIRECTION INPUT ;
    USE SIGNAL ;
    PORT
      LAYER M4 ;
        RECT  17.088 33.216 17.28 33.24 ;
    END
  END i[294]
  PIN i[295]
    DIRECTION INPUT ;
    USE SIGNAL ;
    PORT
      LAYER M4 ;
        RECT  17.088 33.36 17.28 33.384 ;
    END
  END i[295]
  PIN i[296]
    DIRECTION INPUT ;
    USE SIGNAL ;
    PORT
      LAYER M4 ;
        RECT  17.088 33.456 17.28 33.48 ;
    END
  END i[296]
  PIN i[297]
    DIRECTION INPUT ;
    USE SIGNAL ;
    PORT
      LAYER M4 ;
        RECT  17.088 33.552 17.28 33.576 ;
    END
  END i[297]
  PIN i[298]
    DIRECTION INPUT ;
    USE SIGNAL ;
    PORT
      LAYER M4 ;
        RECT  17.088 33.648 17.28 33.672 ;
    END
  END i[298]
  PIN i[299]
    DIRECTION INPUT ;
    USE SIGNAL ;
    PORT
      LAYER M4 ;
        RECT  17.088 33.744 17.28 33.768 ;
    END
  END i[299]
  PIN i[29]
    DIRECTION INPUT ;
    USE SIGNAL ;
    PORT
      LAYER M4 ;
        RECT  17.088 5.28 17.28 5.304 ;
    END
  END i[29]
  PIN i[2]
    DIRECTION INPUT ;
    USE SIGNAL ;
    PORT
      LAYER M4 ;
        RECT  17.088 2.448 17.28 2.472 ;
    END
  END i[2]
  PIN i[300]
    DIRECTION INPUT ;
    USE SIGNAL ;
    PORT
      LAYER M4 ;
        RECT  17.088 33.888 17.28 33.912 ;
    END
  END i[300]
  PIN i[301]
    DIRECTION INPUT ;
    USE SIGNAL ;
    PORT
      LAYER M4 ;
        RECT  17.088 33.984 17.28 34.008 ;
    END
  END i[301]
  PIN i[302]
    DIRECTION INPUT ;
    USE SIGNAL ;
    PORT
      LAYER M4 ;
        RECT  17.088 34.08 17.28 34.104 ;
    END
  END i[302]
  PIN i[303]
    DIRECTION INPUT ;
    USE SIGNAL ;
    PORT
      LAYER M4 ;
        RECT  17.088 34.176 17.28 34.2 ;
    END
  END i[303]
  PIN i[304]
    DIRECTION INPUT ;
    USE SIGNAL ;
    PORT
      LAYER M4 ;
        RECT  17.088 34.272 17.28 34.296 ;
    END
  END i[304]
  PIN i[305]
    DIRECTION INPUT ;
    USE SIGNAL ;
    PORT
      LAYER M4 ;
        RECT  17.088 34.416 17.28 34.44 ;
    END
  END i[305]
  PIN i[306]
    DIRECTION INPUT ;
    USE SIGNAL ;
    PORT
      LAYER M4 ;
        RECT  17.088 34.512 17.28 34.536 ;
    END
  END i[306]
  PIN i[307]
    DIRECTION INPUT ;
    USE SIGNAL ;
    PORT
      LAYER M4 ;
        RECT  17.088 34.608 17.28 34.632 ;
    END
  END i[307]
  PIN i[308]
    DIRECTION INPUT ;
    USE SIGNAL ;
    PORT
      LAYER M4 ;
        RECT  17.088 34.704 17.28 34.728 ;
    END
  END i[308]
  PIN i[309]
    DIRECTION INPUT ;
    USE SIGNAL ;
    PORT
      LAYER M4 ;
        RECT  17.088 34.8 17.28 34.824 ;
    END
  END i[309]
  PIN i[30]
    DIRECTION INPUT ;
    USE SIGNAL ;
    PORT
      LAYER M4 ;
        RECT  17.088 5.376 17.28 5.4 ;
    END
  END i[30]
  PIN i[310]
    DIRECTION INPUT ;
    USE SIGNAL ;
    PORT
      LAYER M4 ;
        RECT  17.088 34.944 17.28 34.968 ;
    END
  END i[310]
  PIN i[311]
    DIRECTION INPUT ;
    USE SIGNAL ;
    PORT
      LAYER M4 ;
        RECT  17.088 35.04 17.28 35.064 ;
    END
  END i[311]
  PIN i[312]
    DIRECTION INPUT ;
    USE SIGNAL ;
    PORT
      LAYER M4 ;
        RECT  17.088 35.136 17.28 35.16 ;
    END
  END i[312]
  PIN i[313]
    DIRECTION INPUT ;
    USE SIGNAL ;
    PORT
      LAYER M4 ;
        RECT  17.088 35.232 17.28 35.256 ;
    END
  END i[313]
  PIN i[314]
    DIRECTION INPUT ;
    USE SIGNAL ;
    PORT
      LAYER M4 ;
        RECT  17.088 35.328 17.28 35.352 ;
    END
  END i[314]
  PIN i[315]
    DIRECTION INPUT ;
    USE SIGNAL ;
    PORT
      LAYER M4 ;
        RECT  17.088 35.424 17.28 35.448 ;
    END
  END i[315]
  PIN i[316]
    DIRECTION INPUT ;
    USE SIGNAL ;
    PORT
      LAYER M4 ;
        RECT  17.088 35.568 17.28 35.592 ;
    END
  END i[316]
  PIN i[317]
    DIRECTION INPUT ;
    USE SIGNAL ;
    PORT
      LAYER M4 ;
        RECT  17.088 35.664 17.28 35.688 ;
    END
  END i[317]
  PIN i[318]
    DIRECTION INPUT ;
    USE SIGNAL ;
    PORT
      LAYER M4 ;
        RECT  17.088 35.76 17.28 35.784 ;
    END
  END i[318]
  PIN i[319]
    DIRECTION INPUT ;
    USE SIGNAL ;
    PORT
      LAYER M4 ;
        RECT  17.088 35.856 17.28 35.88 ;
    END
  END i[319]
  PIN i[31]
    DIRECTION INPUT ;
    USE SIGNAL ;
    PORT
      LAYER M4 ;
        RECT  17.088 5.472 17.28 5.496 ;
    END
  END i[31]
  PIN i[320]
    DIRECTION INPUT ;
    USE SIGNAL ;
    PORT
      LAYER M4 ;
        RECT  17.088 35.952 17.28 35.976 ;
    END
  END i[320]
  PIN i[321]
    DIRECTION INPUT ;
    USE SIGNAL ;
    PORT
      LAYER M4 ;
        RECT  17.088 36.096 17.28 36.12 ;
    END
  END i[321]
  PIN i[322]
    DIRECTION INPUT ;
    USE SIGNAL ;
    PORT
      LAYER M4 ;
        RECT  17.088 36.192 17.28 36.216 ;
    END
  END i[322]
  PIN i[323]
    DIRECTION INPUT ;
    USE SIGNAL ;
    PORT
      LAYER M4 ;
        RECT  17.088 36.288 17.28 36.312 ;
    END
  END i[323]
  PIN i[324]
    DIRECTION INPUT ;
    USE SIGNAL ;
    PORT
      LAYER M4 ;
        RECT  17.088 36.384 17.28 36.408 ;
    END
  END i[324]
  PIN i[325]
    DIRECTION INPUT ;
    USE SIGNAL ;
    PORT
      LAYER M4 ;
        RECT  17.088 36.48 17.28 36.504 ;
    END
  END i[325]
  PIN i[326]
    DIRECTION INPUT ;
    USE SIGNAL ;
    PORT
      LAYER M4 ;
        RECT  17.088 36.624 17.28 36.648 ;
    END
  END i[326]
  PIN i[327]
    DIRECTION INPUT ;
    USE SIGNAL ;
    PORT
      LAYER M4 ;
        RECT  17.088 36.72 17.28 36.744 ;
    END
  END i[327]
  PIN i[328]
    DIRECTION INPUT ;
    USE SIGNAL ;
    PORT
      LAYER M4 ;
        RECT  17.088 36.816 17.28 36.84 ;
    END
  END i[328]
  PIN i[329]
    DIRECTION INPUT ;
    USE SIGNAL ;
    PORT
      LAYER M4 ;
        RECT  17.088 36.912 17.28 36.936 ;
    END
  END i[329]
  PIN i[32]
    DIRECTION INPUT ;
    USE SIGNAL ;
    PORT
      LAYER M4 ;
        RECT  17.088 5.616 17.28 5.64 ;
    END
  END i[32]
  PIN i[330]
    DIRECTION INPUT ;
    USE SIGNAL ;
    PORT
      LAYER M4 ;
        RECT  17.088 37.008 17.28 37.032 ;
    END
  END i[330]
  PIN i[331]
    DIRECTION INPUT ;
    USE SIGNAL ;
    PORT
      LAYER M4 ;
        RECT  17.088 37.152 17.28 37.176 ;
    END
  END i[331]
  PIN i[332]
    DIRECTION INPUT ;
    USE SIGNAL ;
    PORT
      LAYER M4 ;
        RECT  17.088 37.248 17.28 37.272 ;
    END
  END i[332]
  PIN i[333]
    DIRECTION INPUT ;
    USE SIGNAL ;
    PORT
      LAYER M4 ;
        RECT  17.088 37.344 17.28 37.368 ;
    END
  END i[333]
  PIN i[334]
    DIRECTION INPUT ;
    USE SIGNAL ;
    PORT
      LAYER M4 ;
        RECT  17.088 37.44 17.28 37.464 ;
    END
  END i[334]
  PIN i[335]
    DIRECTION INPUT ;
    USE SIGNAL ;
    PORT
      LAYER M4 ;
        RECT  17.088 37.536 17.28 37.56 ;
    END
  END i[335]
  PIN i[336]
    DIRECTION INPUT ;
    USE SIGNAL ;
    PORT
      LAYER M4 ;
        RECT  17.088 37.68 17.28 37.704 ;
    END
  END i[336]
  PIN i[337]
    DIRECTION INPUT ;
    USE SIGNAL ;
    PORT
      LAYER M4 ;
        RECT  17.088 37.776 17.28 37.8 ;
    END
  END i[337]
  PIN i[338]
    DIRECTION INPUT ;
    USE SIGNAL ;
    PORT
      LAYER M4 ;
        RECT  17.088 37.872 17.28 37.896 ;
    END
  END i[338]
  PIN i[339]
    DIRECTION INPUT ;
    USE SIGNAL ;
    PORT
      LAYER M4 ;
        RECT  17.088 37.968 17.28 37.992 ;
    END
  END i[339]
  PIN i[33]
    DIRECTION INPUT ;
    USE SIGNAL ;
    PORT
      LAYER M4 ;
        RECT  17.088 5.712 17.28 5.736 ;
    END
  END i[33]
  PIN i[340]
    DIRECTION INPUT ;
    USE SIGNAL ;
    PORT
      LAYER M4 ;
        RECT  17.088 38.064 17.28 38.088 ;
    END
  END i[340]
  PIN i[341]
    DIRECTION INPUT ;
    USE SIGNAL ;
    PORT
      LAYER M4 ;
        RECT  17.088 38.208 17.28 38.232 ;
    END
  END i[341]
  PIN i[342]
    DIRECTION INPUT ;
    USE SIGNAL ;
    PORT
      LAYER M4 ;
        RECT  17.088 38.304 17.28 38.328 ;
    END
  END i[342]
  PIN i[343]
    DIRECTION INPUT ;
    USE SIGNAL ;
    PORT
      LAYER M4 ;
        RECT  17.088 38.4 17.28 38.424 ;
    END
  END i[343]
  PIN i[344]
    DIRECTION INPUT ;
    USE SIGNAL ;
    PORT
      LAYER M4 ;
        RECT  17.088 38.496 17.28 38.52 ;
    END
  END i[344]
  PIN i[345]
    DIRECTION INPUT ;
    USE SIGNAL ;
    PORT
      LAYER M4 ;
        RECT  17.088 38.592 17.28 38.616 ;
    END
  END i[345]
  PIN i[346]
    DIRECTION INPUT ;
    USE SIGNAL ;
    PORT
      LAYER M4 ;
        RECT  17.088 38.736 17.28 38.76 ;
    END
  END i[346]
  PIN i[347]
    DIRECTION INPUT ;
    USE SIGNAL ;
    PORT
      LAYER M4 ;
        RECT  17.088 38.832 17.28 38.856 ;
    END
  END i[347]
  PIN i[348]
    DIRECTION INPUT ;
    USE SIGNAL ;
    PORT
      LAYER M4 ;
        RECT  17.088 38.928 17.28 38.952 ;
    END
  END i[348]
  PIN i[349]
    DIRECTION INPUT ;
    USE SIGNAL ;
    PORT
      LAYER M4 ;
        RECT  17.088 39.024 17.28 39.048 ;
    END
  END i[349]
  PIN i[34]
    DIRECTION INPUT ;
    USE SIGNAL ;
    PORT
      LAYER M4 ;
        RECT  17.088 5.808 17.28 5.832 ;
    END
  END i[34]
  PIN i[350]
    DIRECTION INPUT ;
    USE SIGNAL ;
    PORT
      LAYER M4 ;
        RECT  17.088 39.12 17.28 39.144 ;
    END
  END i[350]
  PIN i[351]
    DIRECTION INPUT ;
    USE SIGNAL ;
    PORT
      LAYER M4 ;
        RECT  17.088 39.264 17.28 39.288 ;
    END
  END i[351]
  PIN i[352]
    DIRECTION INPUT ;
    USE SIGNAL ;
    PORT
      LAYER M4 ;
        RECT  17.088 39.36 17.28 39.384 ;
    END
  END i[352]
  PIN i[353]
    DIRECTION INPUT ;
    USE SIGNAL ;
    PORT
      LAYER M4 ;
        RECT  17.088 39.456 17.28 39.48 ;
    END
  END i[353]
  PIN i[354]
    DIRECTION INPUT ;
    USE SIGNAL ;
    PORT
      LAYER M4 ;
        RECT  17.088 39.552 17.28 39.576 ;
    END
  END i[354]
  PIN i[355]
    DIRECTION INPUT ;
    USE SIGNAL ;
    PORT
      LAYER M4 ;
        RECT  17.088 39.648 17.28 39.672 ;
    END
  END i[355]
  PIN i[356]
    DIRECTION INPUT ;
    USE SIGNAL ;
    PORT
      LAYER M4 ;
        RECT  17.088 39.792 17.28 39.816 ;
    END
  END i[356]
  PIN i[357]
    DIRECTION INPUT ;
    USE SIGNAL ;
    PORT
      LAYER M4 ;
        RECT  17.088 39.888 17.28 39.912 ;
    END
  END i[357]
  PIN i[358]
    DIRECTION INPUT ;
    USE SIGNAL ;
    PORT
      LAYER M4 ;
        RECT  17.088 39.984 17.28 40.008 ;
    END
  END i[358]
  PIN i[359]
    DIRECTION INPUT ;
    USE SIGNAL ;
    PORT
      LAYER M4 ;
        RECT  17.088 40.08 17.28 40.104 ;
    END
  END i[359]
  PIN i[35]
    DIRECTION INPUT ;
    USE SIGNAL ;
    PORT
      LAYER M4 ;
        RECT  17.088 5.904 17.28 5.928 ;
    END
  END i[35]
  PIN i[360]
    DIRECTION INPUT ;
    USE SIGNAL ;
    PORT
      LAYER M4 ;
        RECT  17.088 40.176 17.28 40.2 ;
    END
  END i[360]
  PIN i[361]
    DIRECTION INPUT ;
    USE SIGNAL ;
    PORT
      LAYER M4 ;
        RECT  17.088 40.32 17.28 40.344 ;
    END
  END i[361]
  PIN i[362]
    DIRECTION INPUT ;
    USE SIGNAL ;
    PORT
      LAYER M4 ;
        RECT  17.088 40.416 17.28 40.44 ;
    END
  END i[362]
  PIN i[363]
    DIRECTION INPUT ;
    USE SIGNAL ;
    PORT
      LAYER M4 ;
        RECT  17.088 40.512 17.28 40.536 ;
    END
  END i[363]
  PIN i[364]
    DIRECTION INPUT ;
    USE SIGNAL ;
    PORT
      LAYER M4 ;
        RECT  17.088 40.608 17.28 40.632 ;
    END
  END i[364]
  PIN i[365]
    DIRECTION INPUT ;
    USE SIGNAL ;
    PORT
      LAYER M4 ;
        RECT  17.088 40.704 17.28 40.728 ;
    END
  END i[365]
  PIN i[366]
    DIRECTION INPUT ;
    USE SIGNAL ;
    PORT
      LAYER M4 ;
        RECT  17.088 40.848 17.28 40.872 ;
    END
  END i[366]
  PIN i[367]
    DIRECTION INPUT ;
    USE SIGNAL ;
    PORT
      LAYER M4 ;
        RECT  17.088 40.944 17.28 40.968 ;
    END
  END i[367]
  PIN i[368]
    DIRECTION INPUT ;
    USE SIGNAL ;
    PORT
      LAYER M4 ;
        RECT  17.088 41.04 17.28 41.064 ;
    END
  END i[368]
  PIN i[369]
    DIRECTION INPUT ;
    USE SIGNAL ;
    PORT
      LAYER M4 ;
        RECT  17.088 41.136 17.28 41.16 ;
    END
  END i[369]
  PIN i[36]
    DIRECTION INPUT ;
    USE SIGNAL ;
    PORT
      LAYER M4 ;
        RECT  17.088 6 17.28 6.024 ;
    END
  END i[36]
  PIN i[370]
    DIRECTION INPUT ;
    USE SIGNAL ;
    PORT
      LAYER M4 ;
        RECT  17.088 41.232 17.28 41.256 ;
    END
  END i[370]
  PIN i[371]
    DIRECTION INPUT ;
    USE SIGNAL ;
    PORT
      LAYER M4 ;
        RECT  17.088 41.376 17.28 41.4 ;
    END
  END i[371]
  PIN i[372]
    DIRECTION INPUT ;
    USE SIGNAL ;
    PORT
      LAYER M4 ;
        RECT  17.088 41.472 17.28 41.496 ;
    END
  END i[372]
  PIN i[373]
    DIRECTION INPUT ;
    USE SIGNAL ;
    PORT
      LAYER M4 ;
        RECT  17.088 41.568 17.28 41.592 ;
    END
  END i[373]
  PIN i[374]
    DIRECTION INPUT ;
    USE SIGNAL ;
    PORT
      LAYER M4 ;
        RECT  17.088 41.664 17.28 41.688 ;
    END
  END i[374]
  PIN i[375]
    DIRECTION INPUT ;
    USE SIGNAL ;
    PORT
      LAYER M4 ;
        RECT  17.088 41.76 17.28 41.784 ;
    END
  END i[375]
  PIN i[376]
    DIRECTION INPUT ;
    USE SIGNAL ;
    PORT
      LAYER M4 ;
        RECT  17.088 41.904 17.28 41.928 ;
    END
  END i[376]
  PIN i[377]
    DIRECTION INPUT ;
    USE SIGNAL ;
    PORT
      LAYER M4 ;
        RECT  17.088 42 17.28 42.024 ;
    END
  END i[377]
  PIN i[378]
    DIRECTION INPUT ;
    USE SIGNAL ;
    PORT
      LAYER M4 ;
        RECT  17.088 42.096 17.28 42.12 ;
    END
  END i[378]
  PIN i[379]
    DIRECTION INPUT ;
    USE SIGNAL ;
    PORT
      LAYER M4 ;
        RECT  17.088 42.192 17.28 42.216 ;
    END
  END i[379]
  PIN i[37]
    DIRECTION INPUT ;
    USE SIGNAL ;
    PORT
      LAYER M4 ;
        RECT  17.088 6.144 17.28 6.168 ;
    END
  END i[37]
  PIN i[380]
    DIRECTION INPUT ;
    USE SIGNAL ;
    PORT
      LAYER M4 ;
        RECT  17.088 42.288 17.28 42.312 ;
    END
  END i[380]
  PIN i[381]
    DIRECTION INPUT ;
    USE SIGNAL ;
    PORT
      LAYER M4 ;
        RECT  17.088 42.432 17.28 42.456 ;
    END
  END i[381]
  PIN i[382]
    DIRECTION INPUT ;
    USE SIGNAL ;
    PORT
      LAYER M4 ;
        RECT  17.088 42.528 17.28 42.552 ;
    END
  END i[382]
  PIN i[383]
    DIRECTION INPUT ;
    USE SIGNAL ;
    PORT
      LAYER M4 ;
        RECT  17.088 42.624 17.28 42.648 ;
    END
  END i[383]
  PIN i[384]
    DIRECTION INPUT ;
    USE SIGNAL ;
    PORT
      LAYER M4 ;
        RECT  17.088 42.72 17.28 42.744 ;
    END
  END i[384]
  PIN i[385]
    DIRECTION INPUT ;
    USE SIGNAL ;
    PORT
      LAYER M4 ;
        RECT  17.088 42.816 17.28 42.84 ;
    END
  END i[385]
  PIN i[386]
    DIRECTION INPUT ;
    USE SIGNAL ;
    PORT
      LAYER M4 ;
        RECT  17.088 42.912 17.28 42.936 ;
    END
  END i[386]
  PIN i[387]
    DIRECTION INPUT ;
    USE SIGNAL ;
    PORT
      LAYER M4 ;
        RECT  17.088 43.056 17.28 43.08 ;
    END
  END i[387]
  PIN i[388]
    DIRECTION INPUT ;
    USE SIGNAL ;
    PORT
      LAYER M4 ;
        RECT  17.088 43.152 17.28 43.176 ;
    END
  END i[388]
  PIN i[389]
    DIRECTION INPUT ;
    USE SIGNAL ;
    PORT
      LAYER M4 ;
        RECT  17.088 43.248 17.28 43.272 ;
    END
  END i[389]
  PIN i[38]
    DIRECTION INPUT ;
    USE SIGNAL ;
    PORT
      LAYER M4 ;
        RECT  17.088 6.24 17.28 6.264 ;
    END
  END i[38]
  PIN i[390]
    DIRECTION INPUT ;
    USE SIGNAL ;
    PORT
      LAYER M4 ;
        RECT  17.088 43.344 17.28 43.368 ;
    END
  END i[390]
  PIN i[391]
    DIRECTION INPUT ;
    USE SIGNAL ;
    PORT
      LAYER M4 ;
        RECT  17.088 43.44 17.28 43.464 ;
    END
  END i[391]
  PIN i[392]
    DIRECTION INPUT ;
    USE SIGNAL ;
    PORT
      LAYER M4 ;
        RECT  17.088 43.584 17.28 43.608 ;
    END
  END i[392]
  PIN i[393]
    DIRECTION INPUT ;
    USE SIGNAL ;
    PORT
      LAYER M4 ;
        RECT  17.088 43.68 17.28 43.704 ;
    END
  END i[393]
  PIN i[394]
    DIRECTION INPUT ;
    USE SIGNAL ;
    PORT
      LAYER M4 ;
        RECT  17.088 43.776 17.28 43.8 ;
    END
  END i[394]
  PIN i[395]
    DIRECTION INPUT ;
    USE SIGNAL ;
    PORT
      LAYER M4 ;
        RECT  17.088 43.872 17.28 43.896 ;
    END
  END i[395]
  PIN i[396]
    DIRECTION INPUT ;
    USE SIGNAL ;
    PORT
      LAYER M4 ;
        RECT  17.088 43.968 17.28 43.992 ;
    END
  END i[396]
  PIN i[397]
    DIRECTION INPUT ;
    USE SIGNAL ;
    PORT
      LAYER M4 ;
        RECT  17.088 44.112 17.28 44.136 ;
    END
  END i[397]
  PIN i[398]
    DIRECTION INPUT ;
    USE SIGNAL ;
    PORT
      LAYER M4 ;
        RECT  17.088 44.208 17.28 44.232 ;
    END
  END i[398]
  PIN i[399]
    DIRECTION INPUT ;
    USE SIGNAL ;
    PORT
      LAYER M4 ;
        RECT  17.088 44.304 17.28 44.328 ;
    END
  END i[399]
  PIN i[39]
    DIRECTION INPUT ;
    USE SIGNAL ;
    PORT
      LAYER M4 ;
        RECT  17.088 6.336 17.28 6.36 ;
    END
  END i[39]
  PIN i[3]
    DIRECTION INPUT ;
    USE SIGNAL ;
    PORT
      LAYER M4 ;
        RECT  17.088 2.544 17.28 2.568 ;
    END
  END i[3]
  PIN i[400]
    DIRECTION INPUT ;
    USE SIGNAL ;
    PORT
      LAYER M4 ;
        RECT  17.088 44.4 17.28 44.424 ;
    END
  END i[400]
  PIN i[401]
    DIRECTION INPUT ;
    USE SIGNAL ;
    PORT
      LAYER M4 ;
        RECT  17.088 44.496 17.28 44.52 ;
    END
  END i[401]
  PIN i[402]
    DIRECTION INPUT ;
    USE SIGNAL ;
    PORT
      LAYER M4 ;
        RECT  17.088 44.64 17.28 44.664 ;
    END
  END i[402]
  PIN i[403]
    DIRECTION INPUT ;
    USE SIGNAL ;
    PORT
      LAYER M4 ;
        RECT  17.088 44.736 17.28 44.76 ;
    END
  END i[403]
  PIN i[404]
    DIRECTION INPUT ;
    USE SIGNAL ;
    PORT
      LAYER M4 ;
        RECT  17.088 44.832 17.28 44.856 ;
    END
  END i[404]
  PIN i[405]
    DIRECTION INPUT ;
    USE SIGNAL ;
    PORT
      LAYER M4 ;
        RECT  17.088 44.928 17.28 44.952 ;
    END
  END i[405]
  PIN i[406]
    DIRECTION INPUT ;
    USE SIGNAL ;
    PORT
      LAYER M4 ;
        RECT  17.088 45.024 17.28 45.048 ;
    END
  END i[406]
  PIN i[407]
    DIRECTION INPUT ;
    USE SIGNAL ;
    PORT
      LAYER M4 ;
        RECT  17.088 45.168 17.28 45.192 ;
    END
  END i[407]
  PIN i[408]
    DIRECTION INPUT ;
    USE SIGNAL ;
    PORT
      LAYER M4 ;
        RECT  17.088 45.264 17.28 45.288 ;
    END
  END i[408]
  PIN i[409]
    DIRECTION INPUT ;
    USE SIGNAL ;
    PORT
      LAYER M4 ;
        RECT  17.088 45.36 17.28 45.384 ;
    END
  END i[409]
  PIN i[40]
    DIRECTION INPUT ;
    USE SIGNAL ;
    PORT
      LAYER M4 ;
        RECT  17.088 6.432 17.28 6.456 ;
    END
  END i[40]
  PIN i[410]
    DIRECTION INPUT ;
    USE SIGNAL ;
    PORT
      LAYER M4 ;
        RECT  17.088 45.456 17.28 45.48 ;
    END
  END i[410]
  PIN i[411]
    DIRECTION INPUT ;
    USE SIGNAL ;
    PORT
      LAYER M4 ;
        RECT  17.088 45.552 17.28 45.576 ;
    END
  END i[411]
  PIN i[412]
    DIRECTION INPUT ;
    USE SIGNAL ;
    PORT
      LAYER M4 ;
        RECT  17.088 45.696 17.28 45.72 ;
    END
  END i[412]
  PIN i[413]
    DIRECTION INPUT ;
    USE SIGNAL ;
    PORT
      LAYER M4 ;
        RECT  17.088 45.792 17.28 45.816 ;
    END
  END i[413]
  PIN i[414]
    DIRECTION INPUT ;
    USE SIGNAL ;
    PORT
      LAYER M4 ;
        RECT  17.088 45.888 17.28 45.912 ;
    END
  END i[414]
  PIN i[415]
    DIRECTION INPUT ;
    USE SIGNAL ;
    PORT
      LAYER M4 ;
        RECT  17.088 45.984 17.28 46.008 ;
    END
  END i[415]
  PIN i[416]
    DIRECTION INPUT ;
    USE SIGNAL ;
    PORT
      LAYER M4 ;
        RECT  17.088 46.08 17.28 46.104 ;
    END
  END i[416]
  PIN i[417]
    DIRECTION INPUT ;
    USE SIGNAL ;
    PORT
      LAYER M4 ;
        RECT  17.088 46.224 17.28 46.248 ;
    END
  END i[417]
  PIN i[418]
    DIRECTION INPUT ;
    USE SIGNAL ;
    PORT
      LAYER M4 ;
        RECT  17.088 46.32 17.28 46.344 ;
    END
  END i[418]
  PIN i[419]
    DIRECTION INPUT ;
    USE SIGNAL ;
    PORT
      LAYER M4 ;
        RECT  17.088 46.416 17.28 46.44 ;
    END
  END i[419]
  PIN i[41]
    DIRECTION INPUT ;
    USE SIGNAL ;
    PORT
      LAYER M4 ;
        RECT  17.088 6.528 17.28 6.552 ;
    END
  END i[41]
  PIN i[420]
    DIRECTION INPUT ;
    USE SIGNAL ;
    PORT
      LAYER M4 ;
        RECT  17.088 46.512 17.28 46.536 ;
    END
  END i[420]
  PIN i[421]
    DIRECTION INPUT ;
    USE SIGNAL ;
    PORT
      LAYER M4 ;
        RECT  17.088 46.608 17.28 46.632 ;
    END
  END i[421]
  PIN i[422]
    DIRECTION INPUT ;
    USE SIGNAL ;
    PORT
      LAYER M4 ;
        RECT  17.088 46.752 17.28 46.776 ;
    END
  END i[422]
  PIN i[423]
    DIRECTION INPUT ;
    USE SIGNAL ;
    PORT
      LAYER M4 ;
        RECT  17.088 46.848 17.28 46.872 ;
    END
  END i[423]
  PIN i[424]
    DIRECTION INPUT ;
    USE SIGNAL ;
    PORT
      LAYER M4 ;
        RECT  17.088 46.944 17.28 46.968 ;
    END
  END i[424]
  PIN i[425]
    DIRECTION INPUT ;
    USE SIGNAL ;
    PORT
      LAYER M4 ;
        RECT  17.088 47.04 17.28 47.064 ;
    END
  END i[425]
  PIN i[426]
    DIRECTION INPUT ;
    USE SIGNAL ;
    PORT
      LAYER M4 ;
        RECT  17.088 47.136 17.28 47.16 ;
    END
  END i[426]
  PIN i[427]
    DIRECTION INPUT ;
    USE SIGNAL ;
    PORT
      LAYER M4 ;
        RECT  17.088 47.28 17.28 47.304 ;
    END
  END i[427]
  PIN i[428]
    DIRECTION INPUT ;
    USE SIGNAL ;
    PORT
      LAYER M4 ;
        RECT  17.088 47.376 17.28 47.4 ;
    END
  END i[428]
  PIN i[429]
    DIRECTION INPUT ;
    USE SIGNAL ;
    PORT
      LAYER M4 ;
        RECT  17.088 47.472 17.28 47.496 ;
    END
  END i[429]
  PIN i[42]
    DIRECTION INPUT ;
    USE SIGNAL ;
    PORT
      LAYER M4 ;
        RECT  17.088 6.672 17.28 6.696 ;
    END
  END i[42]
  PIN i[430]
    DIRECTION INPUT ;
    USE SIGNAL ;
    PORT
      LAYER M4 ;
        RECT  17.088 47.568 17.28 47.592 ;
    END
  END i[430]
  PIN i[431]
    DIRECTION INPUT ;
    USE SIGNAL ;
    PORT
      LAYER M4 ;
        RECT  17.088 47.664 17.28 47.688 ;
    END
  END i[431]
  PIN i[432]
    DIRECTION INPUT ;
    USE SIGNAL ;
    PORT
      LAYER M4 ;
        RECT  17.088 47.808 17.28 47.832 ;
    END
  END i[432]
  PIN i[433]
    DIRECTION INPUT ;
    USE SIGNAL ;
    PORT
      LAYER M4 ;
        RECT  17.088 47.904 17.28 47.928 ;
    END
  END i[433]
  PIN i[434]
    DIRECTION INPUT ;
    USE SIGNAL ;
    PORT
      LAYER M4 ;
        RECT  17.088 48 17.28 48.024 ;
    END
  END i[434]
  PIN i[435]
    DIRECTION INPUT ;
    USE SIGNAL ;
    PORT
      LAYER M4 ;
        RECT  17.088 48.096 17.28 48.12 ;
    END
  END i[435]
  PIN i[436]
    DIRECTION INPUT ;
    USE SIGNAL ;
    PORT
      LAYER M4 ;
        RECT  17.088 48.192 17.28 48.216 ;
    END
  END i[436]
  PIN i[437]
    DIRECTION INPUT ;
    USE SIGNAL ;
    PORT
      LAYER M4 ;
        RECT  17.088 48.336 17.28 48.36 ;
    END
  END i[437]
  PIN i[438]
    DIRECTION INPUT ;
    USE SIGNAL ;
    PORT
      LAYER M4 ;
        RECT  17.088 48.432 17.28 48.456 ;
    END
  END i[438]
  PIN i[439]
    DIRECTION INPUT ;
    USE SIGNAL ;
    PORT
      LAYER M4 ;
        RECT  17.088 48.528 17.28 48.552 ;
    END
  END i[439]
  PIN i[43]
    DIRECTION INPUT ;
    USE SIGNAL ;
    PORT
      LAYER M4 ;
        RECT  17.088 6.768 17.28 6.792 ;
    END
  END i[43]
  PIN i[440]
    DIRECTION INPUT ;
    USE SIGNAL ;
    PORT
      LAYER M4 ;
        RECT  17.088 48.624 17.28 48.648 ;
    END
  END i[440]
  PIN i[441]
    DIRECTION INPUT ;
    USE SIGNAL ;
    PORT
      LAYER M4 ;
        RECT  17.088 48.72 17.28 48.744 ;
    END
  END i[441]
  PIN i[442]
    DIRECTION INPUT ;
    USE SIGNAL ;
    PORT
      LAYER M4 ;
        RECT  17.088 48.864 17.28 48.888 ;
    END
  END i[442]
  PIN i[443]
    DIRECTION INPUT ;
    USE SIGNAL ;
    PORT
      LAYER M4 ;
        RECT  17.088 48.96 17.28 48.984 ;
    END
  END i[443]
  PIN i[444]
    DIRECTION INPUT ;
    USE SIGNAL ;
    PORT
      LAYER M4 ;
        RECT  17.088 49.056 17.28 49.08 ;
    END
  END i[444]
  PIN i[445]
    DIRECTION INPUT ;
    USE SIGNAL ;
    PORT
      LAYER M4 ;
        RECT  17.088 49.152 17.28 49.176 ;
    END
  END i[445]
  PIN i[446]
    DIRECTION INPUT ;
    USE SIGNAL ;
    PORT
      LAYER M4 ;
        RECT  17.088 49.248 17.28 49.272 ;
    END
  END i[446]
  PIN i[447]
    DIRECTION INPUT ;
    USE SIGNAL ;
    PORT
      LAYER M4 ;
        RECT  17.088 49.392 17.28 49.416 ;
    END
  END i[447]
  PIN i[448]
    DIRECTION INPUT ;
    USE SIGNAL ;
    PORT
      LAYER M4 ;
        RECT  17.088 49.488 17.28 49.512 ;
    END
  END i[448]
  PIN i[449]
    DIRECTION INPUT ;
    USE SIGNAL ;
    PORT
      LAYER M4 ;
        RECT  17.088 49.584 17.28 49.608 ;
    END
  END i[449]
  PIN i[44]
    DIRECTION INPUT ;
    USE SIGNAL ;
    PORT
      LAYER M4 ;
        RECT  17.088 6.864 17.28 6.888 ;
    END
  END i[44]
  PIN i[450]
    DIRECTION INPUT ;
    USE SIGNAL ;
    PORT
      LAYER M4 ;
        RECT  17.088 49.68 17.28 49.704 ;
    END
  END i[450]
  PIN i[451]
    DIRECTION INPUT ;
    USE SIGNAL ;
    PORT
      LAYER M4 ;
        RECT  17.088 49.776 17.28 49.8 ;
    END
  END i[451]
  PIN i[452]
    DIRECTION INPUT ;
    USE SIGNAL ;
    PORT
      LAYER M4 ;
        RECT  17.088 49.92 17.28 49.944 ;
    END
  END i[452]
  PIN i[453]
    DIRECTION INPUT ;
    USE SIGNAL ;
    PORT
      LAYER M4 ;
        RECT  17.088 50.016 17.28 50.04 ;
    END
  END i[453]
  PIN i[454]
    DIRECTION INPUT ;
    USE SIGNAL ;
    PORT
      LAYER M4 ;
        RECT  17.088 50.112 17.28 50.136 ;
    END
  END i[454]
  PIN i[455]
    DIRECTION INPUT ;
    USE SIGNAL ;
    PORT
      LAYER M4 ;
        RECT  17.088 50.208 17.28 50.232 ;
    END
  END i[455]
  PIN i[456]
    DIRECTION INPUT ;
    USE SIGNAL ;
    PORT
      LAYER M4 ;
        RECT  17.088 50.304 17.28 50.328 ;
    END
  END i[456]
  PIN i[457]
    DIRECTION INPUT ;
    USE SIGNAL ;
    PORT
      LAYER M4 ;
        RECT  17.088 50.4 17.28 50.424 ;
    END
  END i[457]
  PIN i[458]
    DIRECTION INPUT ;
    USE SIGNAL ;
    PORT
      LAYER M4 ;
        RECT  17.088 50.544 17.28 50.568 ;
    END
  END i[458]
  PIN i[459]
    DIRECTION INPUT ;
    USE SIGNAL ;
    PORT
      LAYER M4 ;
        RECT  17.088 50.64 17.28 50.664 ;
    END
  END i[459]
  PIN i[45]
    DIRECTION INPUT ;
    USE SIGNAL ;
    PORT
      LAYER M4 ;
        RECT  17.088 6.96 17.28 6.984 ;
    END
  END i[45]
  PIN i[460]
    DIRECTION INPUT ;
    USE SIGNAL ;
    PORT
      LAYER M4 ;
        RECT  17.088 50.736 17.28 50.76 ;
    END
  END i[460]
  PIN i[461]
    DIRECTION INPUT ;
    USE SIGNAL ;
    PORT
      LAYER M4 ;
        RECT  17.088 50.832 17.28 50.856 ;
    END
  END i[461]
  PIN i[462]
    DIRECTION INPUT ;
    USE SIGNAL ;
    PORT
      LAYER M4 ;
        RECT  17.088 50.928 17.28 50.952 ;
    END
  END i[462]
  PIN i[463]
    DIRECTION INPUT ;
    USE SIGNAL ;
    PORT
      LAYER M4 ;
        RECT  17.088 51.072 17.28 51.096 ;
    END
  END i[463]
  PIN i[464]
    DIRECTION INPUT ;
    USE SIGNAL ;
    PORT
      LAYER M4 ;
        RECT  17.088 51.168 17.28 51.192 ;
    END
  END i[464]
  PIN i[465]
    DIRECTION INPUT ;
    USE SIGNAL ;
    PORT
      LAYER M4 ;
        RECT  17.088 51.264 17.28 51.288 ;
    END
  END i[465]
  PIN i[466]
    DIRECTION INPUT ;
    USE SIGNAL ;
    PORT
      LAYER M4 ;
        RECT  17.088 51.36 17.28 51.384 ;
    END
  END i[466]
  PIN i[467]
    DIRECTION INPUT ;
    USE SIGNAL ;
    PORT
      LAYER M4 ;
        RECT  17.088 51.456 17.28 51.48 ;
    END
  END i[467]
  PIN i[468]
    DIRECTION INPUT ;
    USE SIGNAL ;
    PORT
      LAYER M4 ;
        RECT  17.088 51.6 17.28 51.624 ;
    END
  END i[468]
  PIN i[469]
    DIRECTION INPUT ;
    USE SIGNAL ;
    PORT
      LAYER M4 ;
        RECT  17.088 51.696 17.28 51.72 ;
    END
  END i[469]
  PIN i[46]
    DIRECTION INPUT ;
    USE SIGNAL ;
    PORT
      LAYER M4 ;
        RECT  17.088 7.056 17.28 7.08 ;
    END
  END i[46]
  PIN i[470]
    DIRECTION INPUT ;
    USE SIGNAL ;
    PORT
      LAYER M4 ;
        RECT  17.088 51.792 17.28 51.816 ;
    END
  END i[470]
  PIN i[471]
    DIRECTION INPUT ;
    USE SIGNAL ;
    PORT
      LAYER M4 ;
        RECT  17.088 51.888 17.28 51.912 ;
    END
  END i[471]
  PIN i[472]
    DIRECTION INPUT ;
    USE SIGNAL ;
    PORT
      LAYER M4 ;
        RECT  17.088 51.984 17.28 52.008 ;
    END
  END i[472]
  PIN i[473]
    DIRECTION INPUT ;
    USE SIGNAL ;
    PORT
      LAYER M4 ;
        RECT  17.088 52.128 17.28 52.152 ;
    END
  END i[473]
  PIN i[474]
    DIRECTION INPUT ;
    USE SIGNAL ;
    PORT
      LAYER M4 ;
        RECT  17.088 52.224 17.28 52.248 ;
    END
  END i[474]
  PIN i[475]
    DIRECTION INPUT ;
    USE SIGNAL ;
    PORT
      LAYER M4 ;
        RECT  17.088 52.32 17.28 52.344 ;
    END
  END i[475]
  PIN i[476]
    DIRECTION INPUT ;
    USE SIGNAL ;
    PORT
      LAYER M4 ;
        RECT  17.088 52.416 17.28 52.44 ;
    END
  END i[476]
  PIN i[477]
    DIRECTION INPUT ;
    USE SIGNAL ;
    PORT
      LAYER M4 ;
        RECT  17.088 52.512 17.28 52.536 ;
    END
  END i[477]
  PIN i[478]
    DIRECTION INPUT ;
    USE SIGNAL ;
    PORT
      LAYER M4 ;
        RECT  17.088 52.656 17.28 52.68 ;
    END
  END i[478]
  PIN i[479]
    DIRECTION INPUT ;
    USE SIGNAL ;
    PORT
      LAYER M4 ;
        RECT  17.088 52.752 17.28 52.776 ;
    END
  END i[479]
  PIN i[47]
    DIRECTION INPUT ;
    USE SIGNAL ;
    PORT
      LAYER M4 ;
        RECT  17.088 7.2 17.28 7.224 ;
    END
  END i[47]
  PIN i[480]
    DIRECTION INPUT ;
    USE SIGNAL ;
    PORT
      LAYER M4 ;
        RECT  17.088 52.848 17.28 52.872 ;
    END
  END i[480]
  PIN i[481]
    DIRECTION INPUT ;
    USE SIGNAL ;
    PORT
      LAYER M4 ;
        RECT  17.088 52.944 17.28 52.968 ;
    END
  END i[481]
  PIN i[482]
    DIRECTION INPUT ;
    USE SIGNAL ;
    PORT
      LAYER M4 ;
        RECT  17.088 53.04 17.28 53.064 ;
    END
  END i[482]
  PIN i[483]
    DIRECTION INPUT ;
    USE SIGNAL ;
    PORT
      LAYER M4 ;
        RECT  17.088 53.184 17.28 53.208 ;
    END
  END i[483]
  PIN i[484]
    DIRECTION INPUT ;
    USE SIGNAL ;
    PORT
      LAYER M4 ;
        RECT  17.088 53.28 17.28 53.304 ;
    END
  END i[484]
  PIN i[485]
    DIRECTION INPUT ;
    USE SIGNAL ;
    PORT
      LAYER M4 ;
        RECT  17.088 53.376 17.28 53.4 ;
    END
  END i[485]
  PIN i[486]
    DIRECTION INPUT ;
    USE SIGNAL ;
    PORT
      LAYER M4 ;
        RECT  17.088 53.472 17.28 53.496 ;
    END
  END i[486]
  PIN i[487]
    DIRECTION INPUT ;
    USE SIGNAL ;
    PORT
      LAYER M4 ;
        RECT  17.088 53.568 17.28 53.592 ;
    END
  END i[487]
  PIN i[488]
    DIRECTION INPUT ;
    USE SIGNAL ;
    PORT
      LAYER M4 ;
        RECT  17.088 53.712 17.28 53.736 ;
    END
  END i[488]
  PIN i[489]
    DIRECTION INPUT ;
    USE SIGNAL ;
    PORT
      LAYER M4 ;
        RECT  17.088 53.808 17.28 53.832 ;
    END
  END i[489]
  PIN i[48]
    DIRECTION INPUT ;
    USE SIGNAL ;
    PORT
      LAYER M4 ;
        RECT  17.088 7.296 17.28 7.32 ;
    END
  END i[48]
  PIN i[490]
    DIRECTION INPUT ;
    USE SIGNAL ;
    PORT
      LAYER M4 ;
        RECT  17.088 53.904 17.28 53.928 ;
    END
  END i[490]
  PIN i[491]
    DIRECTION INPUT ;
    USE SIGNAL ;
    PORT
      LAYER M4 ;
        RECT  17.088 54 17.28 54.024 ;
    END
  END i[491]
  PIN i[492]
    DIRECTION INPUT ;
    USE SIGNAL ;
    PORT
      LAYER M4 ;
        RECT  17.088 54.096 17.28 54.12 ;
    END
  END i[492]
  PIN i[493]
    DIRECTION INPUT ;
    USE SIGNAL ;
    PORT
      LAYER M4 ;
        RECT  17.088 54.24 17.28 54.264 ;
    END
  END i[493]
  PIN i[494]
    DIRECTION INPUT ;
    USE SIGNAL ;
    PORT
      LAYER M4 ;
        RECT  17.088 54.336 17.28 54.36 ;
    END
  END i[494]
  PIN i[495]
    DIRECTION INPUT ;
    USE SIGNAL ;
    PORT
      LAYER M4 ;
        RECT  17.088 54.432 17.28 54.456 ;
    END
  END i[495]
  PIN i[496]
    DIRECTION INPUT ;
    USE SIGNAL ;
    PORT
      LAYER M4 ;
        RECT  17.088 54.528 17.28 54.552 ;
    END
  END i[496]
  PIN i[497]
    DIRECTION INPUT ;
    USE SIGNAL ;
    PORT
      LAYER M4 ;
        RECT  17.088 54.624 17.28 54.648 ;
    END
  END i[497]
  PIN i[498]
    DIRECTION INPUT ;
    USE SIGNAL ;
    PORT
      LAYER M4 ;
        RECT  17.088 54.768 17.28 54.792 ;
    END
  END i[498]
  PIN i[499]
    DIRECTION INPUT ;
    USE SIGNAL ;
    PORT
      LAYER M4 ;
        RECT  17.088 54.864 17.28 54.888 ;
    END
  END i[499]
  PIN i[49]
    DIRECTION INPUT ;
    USE SIGNAL ;
    PORT
      LAYER M4 ;
        RECT  17.088 7.392 17.28 7.416 ;
    END
  END i[49]
  PIN i[4]
    DIRECTION INPUT ;
    USE SIGNAL ;
    PORT
      LAYER M4 ;
        RECT  17.088 2.64 17.28 2.664 ;
    END
  END i[4]
  PIN i[500]
    DIRECTION INPUT ;
    USE SIGNAL ;
    PORT
      LAYER M4 ;
        RECT  17.088 54.96 17.28 54.984 ;
    END
  END i[500]
  PIN i[501]
    DIRECTION INPUT ;
    USE SIGNAL ;
    PORT
      LAYER M4 ;
        RECT  17.088 55.056 17.28 55.08 ;
    END
  END i[501]
  PIN i[502]
    DIRECTION INPUT ;
    USE SIGNAL ;
    PORT
      LAYER M4 ;
        RECT  17.088 55.152 17.28 55.176 ;
    END
  END i[502]
  PIN i[503]
    DIRECTION INPUT ;
    USE SIGNAL ;
    PORT
      LAYER M4 ;
        RECT  17.088 55.296 17.28 55.32 ;
    END
  END i[503]
  PIN i[504]
    DIRECTION INPUT ;
    USE SIGNAL ;
    PORT
      LAYER M4 ;
        RECT  17.088 55.392 17.28 55.416 ;
    END
  END i[504]
  PIN i[505]
    DIRECTION INPUT ;
    USE SIGNAL ;
    PORT
      LAYER M4 ;
        RECT  17.088 55.488 17.28 55.512 ;
    END
  END i[505]
  PIN i[506]
    DIRECTION INPUT ;
    USE SIGNAL ;
    PORT
      LAYER M4 ;
        RECT  17.088 55.584 17.28 55.608 ;
    END
  END i[506]
  PIN i[507]
    DIRECTION INPUT ;
    USE SIGNAL ;
    PORT
      LAYER M4 ;
        RECT  17.088 55.68 17.28 55.704 ;
    END
  END i[507]
  PIN i[508]
    DIRECTION INPUT ;
    USE SIGNAL ;
    PORT
      LAYER M4 ;
        RECT  17.088 55.824 17.28 55.848 ;
    END
  END i[508]
  PIN i[509]
    DIRECTION INPUT ;
    USE SIGNAL ;
    PORT
      LAYER M4 ;
        RECT  17.088 55.92 17.28 55.944 ;
    END
  END i[509]
  PIN i[50]
    DIRECTION INPUT ;
    USE SIGNAL ;
    PORT
      LAYER M4 ;
        RECT  17.088 7.488 17.28 7.512 ;
    END
  END i[50]
  PIN i[510]
    DIRECTION INPUT ;
    USE SIGNAL ;
    PORT
      LAYER M4 ;
        RECT  17.088 56.016 17.28 56.04 ;
    END
  END i[510]
  PIN i[511]
    DIRECTION INPUT ;
    USE SIGNAL ;
    PORT
      LAYER M4 ;
        RECT  17.088 56.112 17.28 56.136 ;
    END
  END i[511]
  PIN i[51]
    DIRECTION INPUT ;
    USE SIGNAL ;
    PORT
      LAYER M4 ;
        RECT  17.088 7.584 17.28 7.608 ;
    END
  END i[51]
  PIN i[52]
    DIRECTION INPUT ;
    USE SIGNAL ;
    PORT
      LAYER M4 ;
        RECT  17.088 7.728 17.28 7.752 ;
    END
  END i[52]
  PIN i[53]
    DIRECTION INPUT ;
    USE SIGNAL ;
    PORT
      LAYER M4 ;
        RECT  17.088 7.824 17.28 7.848 ;
    END
  END i[53]
  PIN i[54]
    DIRECTION INPUT ;
    USE SIGNAL ;
    PORT
      LAYER M4 ;
        RECT  17.088 7.92 17.28 7.944 ;
    END
  END i[54]
  PIN i[55]
    DIRECTION INPUT ;
    USE SIGNAL ;
    PORT
      LAYER M4 ;
        RECT  17.088 8.016 17.28 8.04 ;
    END
  END i[55]
  PIN i[56]
    DIRECTION INPUT ;
    USE SIGNAL ;
    PORT
      LAYER M4 ;
        RECT  17.088 8.112 17.28 8.136 ;
    END
  END i[56]
  PIN i[57]
    DIRECTION INPUT ;
    USE SIGNAL ;
    PORT
      LAYER M4 ;
        RECT  17.088 8.256 17.28 8.28 ;
    END
  END i[57]
  PIN i[58]
    DIRECTION INPUT ;
    USE SIGNAL ;
    PORT
      LAYER M4 ;
        RECT  17.088 8.352 17.28 8.376 ;
    END
  END i[58]
  PIN i[59]
    DIRECTION INPUT ;
    USE SIGNAL ;
    PORT
      LAYER M4 ;
        RECT  17.088 8.448 17.28 8.472 ;
    END
  END i[59]
  PIN i[5]
    DIRECTION INPUT ;
    USE SIGNAL ;
    PORT
      LAYER M4 ;
        RECT  17.088 2.736 17.28 2.76 ;
    END
  END i[5]
  PIN i[60]
    DIRECTION INPUT ;
    USE SIGNAL ;
    PORT
      LAYER M4 ;
        RECT  17.088 8.544 17.28 8.568 ;
    END
  END i[60]
  PIN i[61]
    DIRECTION INPUT ;
    USE SIGNAL ;
    PORT
      LAYER M4 ;
        RECT  17.088 8.64 17.28 8.664 ;
    END
  END i[61]
  PIN i[62]
    DIRECTION INPUT ;
    USE SIGNAL ;
    PORT
      LAYER M4 ;
        RECT  17.088 8.784 17.28 8.808 ;
    END
  END i[62]
  PIN i[63]
    DIRECTION INPUT ;
    USE SIGNAL ;
    PORT
      LAYER M4 ;
        RECT  17.088 8.88 17.28 8.904 ;
    END
  END i[63]
  PIN i[64]
    DIRECTION INPUT ;
    USE SIGNAL ;
    PORT
      LAYER M4 ;
        RECT  17.088 8.976 17.28 9 ;
    END
  END i[64]
  PIN i[65]
    DIRECTION INPUT ;
    USE SIGNAL ;
    PORT
      LAYER M4 ;
        RECT  17.088 9.072 17.28 9.096 ;
    END
  END i[65]
  PIN i[66]
    DIRECTION INPUT ;
    USE SIGNAL ;
    PORT
      LAYER M4 ;
        RECT  17.088 9.168 17.28 9.192 ;
    END
  END i[66]
  PIN i[67]
    DIRECTION INPUT ;
    USE SIGNAL ;
    PORT
      LAYER M4 ;
        RECT  17.088 9.312 17.28 9.336 ;
    END
  END i[67]
  PIN i[68]
    DIRECTION INPUT ;
    USE SIGNAL ;
    PORT
      LAYER M4 ;
        RECT  17.088 9.408 17.28 9.432 ;
    END
  END i[68]
  PIN i[69]
    DIRECTION INPUT ;
    USE SIGNAL ;
    PORT
      LAYER M4 ;
        RECT  17.088 9.504 17.28 9.528 ;
    END
  END i[69]
  PIN i[6]
    DIRECTION INPUT ;
    USE SIGNAL ;
    PORT
      LAYER M4 ;
        RECT  17.088 2.88 17.28 2.904 ;
    END
  END i[6]
  PIN i[70]
    DIRECTION INPUT ;
    USE SIGNAL ;
    PORT
      LAYER M4 ;
        RECT  17.088 9.6 17.28 9.624 ;
    END
  END i[70]
  PIN i[71]
    DIRECTION INPUT ;
    USE SIGNAL ;
    PORT
      LAYER M4 ;
        RECT  17.088 9.696 17.28 9.72 ;
    END
  END i[71]
  PIN i[72]
    DIRECTION INPUT ;
    USE SIGNAL ;
    PORT
      LAYER M4 ;
        RECT  17.088 9.84 17.28 9.864 ;
    END
  END i[72]
  PIN i[73]
    DIRECTION INPUT ;
    USE SIGNAL ;
    PORT
      LAYER M4 ;
        RECT  17.088 9.936 17.28 9.96 ;
    END
  END i[73]
  PIN i[74]
    DIRECTION INPUT ;
    USE SIGNAL ;
    PORT
      LAYER M4 ;
        RECT  17.088 10.032 17.28 10.056 ;
    END
  END i[74]
  PIN i[75]
    DIRECTION INPUT ;
    USE SIGNAL ;
    PORT
      LAYER M4 ;
        RECT  17.088 10.128 17.28 10.152 ;
    END
  END i[75]
  PIN i[76]
    DIRECTION INPUT ;
    USE SIGNAL ;
    PORT
      LAYER M4 ;
        RECT  17.088 10.224 17.28 10.248 ;
    END
  END i[76]
  PIN i[77]
    DIRECTION INPUT ;
    USE SIGNAL ;
    PORT
      LAYER M4 ;
        RECT  17.088 10.368 17.28 10.392 ;
    END
  END i[77]
  PIN i[78]
    DIRECTION INPUT ;
    USE SIGNAL ;
    PORT
      LAYER M4 ;
        RECT  17.088 10.464 17.28 10.488 ;
    END
  END i[78]
  PIN i[79]
    DIRECTION INPUT ;
    USE SIGNAL ;
    PORT
      LAYER M4 ;
        RECT  17.088 10.56 17.28 10.584 ;
    END
  END i[79]
  PIN i[7]
    DIRECTION INPUT ;
    USE SIGNAL ;
    PORT
      LAYER M4 ;
        RECT  17.088 2.976 17.28 3 ;
    END
  END i[7]
  PIN i[80]
    DIRECTION INPUT ;
    USE SIGNAL ;
    PORT
      LAYER M4 ;
        RECT  17.088 10.656 17.28 10.68 ;
    END
  END i[80]
  PIN i[81]
    DIRECTION INPUT ;
    USE SIGNAL ;
    PORT
      LAYER M4 ;
        RECT  17.088 10.752 17.28 10.776 ;
    END
  END i[81]
  PIN i[82]
    DIRECTION INPUT ;
    USE SIGNAL ;
    PORT
      LAYER M4 ;
        RECT  17.088 10.896 17.28 10.92 ;
    END
  END i[82]
  PIN i[83]
    DIRECTION INPUT ;
    USE SIGNAL ;
    PORT
      LAYER M4 ;
        RECT  17.088 10.992 17.28 11.016 ;
    END
  END i[83]
  PIN i[84]
    DIRECTION INPUT ;
    USE SIGNAL ;
    PORT
      LAYER M4 ;
        RECT  17.088 11.088 17.28 11.112 ;
    END
  END i[84]
  PIN i[85]
    DIRECTION INPUT ;
    USE SIGNAL ;
    PORT
      LAYER M4 ;
        RECT  17.088 11.184 17.28 11.208 ;
    END
  END i[85]
  PIN i[86]
    DIRECTION INPUT ;
    USE SIGNAL ;
    PORT
      LAYER M4 ;
        RECT  17.088 11.28 17.28 11.304 ;
    END
  END i[86]
  PIN i[87]
    DIRECTION INPUT ;
    USE SIGNAL ;
    PORT
      LAYER M4 ;
        RECT  17.088 11.424 17.28 11.448 ;
    END
  END i[87]
  PIN i[88]
    DIRECTION INPUT ;
    USE SIGNAL ;
    PORT
      LAYER M4 ;
        RECT  17.088 11.52 17.28 11.544 ;
    END
  END i[88]
  PIN i[89]
    DIRECTION INPUT ;
    USE SIGNAL ;
    PORT
      LAYER M4 ;
        RECT  17.088 11.616 17.28 11.64 ;
    END
  END i[89]
  PIN i[8]
    DIRECTION INPUT ;
    USE SIGNAL ;
    PORT
      LAYER M4 ;
        RECT  17.088 3.072 17.28 3.096 ;
    END
  END i[8]
  PIN i[90]
    DIRECTION INPUT ;
    USE SIGNAL ;
    PORT
      LAYER M4 ;
        RECT  17.088 11.712 17.28 11.736 ;
    END
  END i[90]
  PIN i[91]
    DIRECTION INPUT ;
    USE SIGNAL ;
    PORT
      LAYER M4 ;
        RECT  17.088 11.808 17.28 11.832 ;
    END
  END i[91]
  PIN i[92]
    DIRECTION INPUT ;
    USE SIGNAL ;
    PORT
      LAYER M4 ;
        RECT  17.088 11.904 17.28 11.928 ;
    END
  END i[92]
  PIN i[93]
    DIRECTION INPUT ;
    USE SIGNAL ;
    PORT
      LAYER M4 ;
        RECT  17.088 12.048 17.28 12.072 ;
    END
  END i[93]
  PIN i[94]
    DIRECTION INPUT ;
    USE SIGNAL ;
    PORT
      LAYER M4 ;
        RECT  17.088 12.144 17.28 12.168 ;
    END
  END i[94]
  PIN i[95]
    DIRECTION INPUT ;
    USE SIGNAL ;
    PORT
      LAYER M4 ;
        RECT  17.088 12.24 17.28 12.264 ;
    END
  END i[95]
  PIN i[96]
    DIRECTION INPUT ;
    USE SIGNAL ;
    PORT
      LAYER M4 ;
        RECT  17.088 12.336 17.28 12.36 ;
    END
  END i[96]
  PIN i[97]
    DIRECTION INPUT ;
    USE SIGNAL ;
    PORT
      LAYER M4 ;
        RECT  17.088 12.432 17.28 12.456 ;
    END
  END i[97]
  PIN i[98]
    DIRECTION INPUT ;
    USE SIGNAL ;
    PORT
      LAYER M4 ;
        RECT  17.088 12.576 17.28 12.6 ;
    END
  END i[98]
  PIN i[99]
    DIRECTION INPUT ;
    USE SIGNAL ;
    PORT
      LAYER M4 ;
        RECT  17.088 12.672 17.28 12.696 ;
    END
  END i[99]
  PIN i[9]
    DIRECTION INPUT ;
    USE SIGNAL ;
    PORT
      LAYER M4 ;
        RECT  17.088 3.168 17.28 3.192 ;
    END
  END i[9]
  PIN o[0]
    DIRECTION OUTPUT ;
    USE SIGNAL ;
    PORT
      LAYER M4 ;
        RECT  0 2.208 0.192 2.232 ;
    END
  END o[0]
  PIN o[100]
    DIRECTION OUTPUT ;
    USE SIGNAL ;
    PORT
      LAYER M4 ;
        RECT  0 12.768 0.192 12.792 ;
    END
  END o[100]
  PIN o[101]
    DIRECTION OUTPUT ;
    USE SIGNAL ;
    PORT
      LAYER M4 ;
        RECT  0 12.864 0.192 12.888 ;
    END
  END o[101]
  PIN o[102]
    DIRECTION OUTPUT ;
    USE SIGNAL ;
    PORT
      LAYER M4 ;
        RECT  0 12.96 0.192 12.984 ;
    END
  END o[102]
  PIN o[103]
    DIRECTION OUTPUT ;
    USE SIGNAL ;
    PORT
      LAYER M4 ;
        RECT  0 13.056 0.192 13.08 ;
    END
  END o[103]
  PIN o[104]
    DIRECTION OUTPUT ;
    USE SIGNAL ;
    PORT
      LAYER M4 ;
        RECT  0 13.152 0.192 13.176 ;
    END
  END o[104]
  PIN o[105]
    DIRECTION OUTPUT ;
    USE SIGNAL ;
    PORT
      LAYER M4 ;
        RECT  0 13.296 0.192 13.32 ;
    END
  END o[105]
  PIN o[106]
    DIRECTION OUTPUT ;
    USE SIGNAL ;
    PORT
      LAYER M4 ;
        RECT  0 13.392 0.192 13.416 ;
    END
  END o[106]
  PIN o[107]
    DIRECTION OUTPUT ;
    USE SIGNAL ;
    PORT
      LAYER M4 ;
        RECT  0 13.488 0.192 13.512 ;
    END
  END o[107]
  PIN o[108]
    DIRECTION OUTPUT ;
    USE SIGNAL ;
    PORT
      LAYER M4 ;
        RECT  0 13.584 0.192 13.608 ;
    END
  END o[108]
  PIN o[109]
    DIRECTION OUTPUT ;
    USE SIGNAL ;
    PORT
      LAYER M4 ;
        RECT  0 13.68 0.192 13.704 ;
    END
  END o[109]
  PIN o[10]
    DIRECTION OUTPUT ;
    USE SIGNAL ;
    PORT
      LAYER M4 ;
        RECT  0 3.264 0.192 3.288 ;
    END
  END o[10]
  PIN o[110]
    DIRECTION OUTPUT ;
    USE SIGNAL ;
    PORT
      LAYER M4 ;
        RECT  0 13.824 0.192 13.848 ;
    END
  END o[110]
  PIN o[111]
    DIRECTION OUTPUT ;
    USE SIGNAL ;
    PORT
      LAYER M4 ;
        RECT  0 13.92 0.192 13.944 ;
    END
  END o[111]
  PIN o[112]
    DIRECTION OUTPUT ;
    USE SIGNAL ;
    PORT
      LAYER M4 ;
        RECT  0 14.016 0.192 14.04 ;
    END
  END o[112]
  PIN o[113]
    DIRECTION OUTPUT ;
    USE SIGNAL ;
    PORT
      LAYER M4 ;
        RECT  0 14.112 0.192 14.136 ;
    END
  END o[113]
  PIN o[114]
    DIRECTION OUTPUT ;
    USE SIGNAL ;
    PORT
      LAYER M4 ;
        RECT  0 14.208 0.192 14.232 ;
    END
  END o[114]
  PIN o[115]
    DIRECTION OUTPUT ;
    USE SIGNAL ;
    PORT
      LAYER M4 ;
        RECT  0 14.352 0.192 14.376 ;
    END
  END o[115]
  PIN o[116]
    DIRECTION OUTPUT ;
    USE SIGNAL ;
    PORT
      LAYER M4 ;
        RECT  0 14.448 0.192 14.472 ;
    END
  END o[116]
  PIN o[117]
    DIRECTION OUTPUT ;
    USE SIGNAL ;
    PORT
      LAYER M4 ;
        RECT  0 14.544 0.192 14.568 ;
    END
  END o[117]
  PIN o[118]
    DIRECTION OUTPUT ;
    USE SIGNAL ;
    PORT
      LAYER M4 ;
        RECT  0 14.64 0.192 14.664 ;
    END
  END o[118]
  PIN o[119]
    DIRECTION OUTPUT ;
    USE SIGNAL ;
    PORT
      LAYER M4 ;
        RECT  0 14.736 0.192 14.76 ;
    END
  END o[119]
  PIN o[11]
    DIRECTION OUTPUT ;
    USE SIGNAL ;
    PORT
      LAYER M4 ;
        RECT  0 3.36 0.192 3.384 ;
    END
  END o[11]
  PIN o[120]
    DIRECTION OUTPUT ;
    USE SIGNAL ;
    PORT
      LAYER M4 ;
        RECT  0 14.88 0.192 14.904 ;
    END
  END o[120]
  PIN o[121]
    DIRECTION OUTPUT ;
    USE SIGNAL ;
    PORT
      LAYER M4 ;
        RECT  0 14.976 0.192 15 ;
    END
  END o[121]
  PIN o[122]
    DIRECTION OUTPUT ;
    USE SIGNAL ;
    PORT
      LAYER M4 ;
        RECT  0 15.072 0.192 15.096 ;
    END
  END o[122]
  PIN o[123]
    DIRECTION OUTPUT ;
    USE SIGNAL ;
    PORT
      LAYER M4 ;
        RECT  0 15.168 0.192 15.192 ;
    END
  END o[123]
  PIN o[124]
    DIRECTION OUTPUT ;
    USE SIGNAL ;
    PORT
      LAYER M4 ;
        RECT  0 15.264 0.192 15.288 ;
    END
  END o[124]
  PIN o[125]
    DIRECTION OUTPUT ;
    USE SIGNAL ;
    PORT
      LAYER M4 ;
        RECT  0 15.36 0.192 15.384 ;
    END
  END o[125]
  PIN o[126]
    DIRECTION OUTPUT ;
    USE SIGNAL ;
    PORT
      LAYER M4 ;
        RECT  0 15.504 0.192 15.528 ;
    END
  END o[126]
  PIN o[127]
    DIRECTION OUTPUT ;
    USE SIGNAL ;
    PORT
      LAYER M4 ;
        RECT  0 15.6 0.192 15.624 ;
    END
  END o[127]
  PIN o[128]
    DIRECTION OUTPUT ;
    USE SIGNAL ;
    PORT
      LAYER M4 ;
        RECT  0 15.696 0.192 15.72 ;
    END
  END o[128]
  PIN o[129]
    DIRECTION OUTPUT ;
    USE SIGNAL ;
    PORT
      LAYER M4 ;
        RECT  0 15.792 0.192 15.816 ;
    END
  END o[129]
  PIN o[12]
    DIRECTION OUTPUT ;
    USE SIGNAL ;
    PORT
      LAYER M4 ;
        RECT  0 3.504 0.192 3.528 ;
    END
  END o[12]
  PIN o[130]
    DIRECTION OUTPUT ;
    USE SIGNAL ;
    PORT
      LAYER M4 ;
        RECT  0 15.888 0.192 15.912 ;
    END
  END o[130]
  PIN o[131]
    DIRECTION OUTPUT ;
    USE SIGNAL ;
    PORT
      LAYER M4 ;
        RECT  0 16.032 0.192 16.056 ;
    END
  END o[131]
  PIN o[132]
    DIRECTION OUTPUT ;
    USE SIGNAL ;
    PORT
      LAYER M4 ;
        RECT  0 16.128 0.192 16.152 ;
    END
  END o[132]
  PIN o[133]
    DIRECTION OUTPUT ;
    USE SIGNAL ;
    PORT
      LAYER M4 ;
        RECT  0 16.224 0.192 16.248 ;
    END
  END o[133]
  PIN o[134]
    DIRECTION OUTPUT ;
    USE SIGNAL ;
    PORT
      LAYER M4 ;
        RECT  0 16.32 0.192 16.344 ;
    END
  END o[134]
  PIN o[135]
    DIRECTION OUTPUT ;
    USE SIGNAL ;
    PORT
      LAYER M4 ;
        RECT  0 16.416 0.192 16.44 ;
    END
  END o[135]
  PIN o[136]
    DIRECTION OUTPUT ;
    USE SIGNAL ;
    PORT
      LAYER M4 ;
        RECT  0 16.56 0.192 16.584 ;
    END
  END o[136]
  PIN o[137]
    DIRECTION OUTPUT ;
    USE SIGNAL ;
    PORT
      LAYER M4 ;
        RECT  0 16.656 0.192 16.68 ;
    END
  END o[137]
  PIN o[138]
    DIRECTION OUTPUT ;
    USE SIGNAL ;
    PORT
      LAYER M4 ;
        RECT  0 16.752 0.192 16.776 ;
    END
  END o[138]
  PIN o[139]
    DIRECTION OUTPUT ;
    USE SIGNAL ;
    PORT
      LAYER M4 ;
        RECT  0 16.848 0.192 16.872 ;
    END
  END o[139]
  PIN o[13]
    DIRECTION OUTPUT ;
    USE SIGNAL ;
    PORT
      LAYER M4 ;
        RECT  0 3.6 0.192 3.624 ;
    END
  END o[13]
  PIN o[140]
    DIRECTION OUTPUT ;
    USE SIGNAL ;
    PORT
      LAYER M4 ;
        RECT  0 16.944 0.192 16.968 ;
    END
  END o[140]
  PIN o[141]
    DIRECTION OUTPUT ;
    USE SIGNAL ;
    PORT
      LAYER M4 ;
        RECT  0 17.088 0.192 17.112 ;
    END
  END o[141]
  PIN o[142]
    DIRECTION OUTPUT ;
    USE SIGNAL ;
    PORT
      LAYER M4 ;
        RECT  0 17.184 0.192 17.208 ;
    END
  END o[142]
  PIN o[143]
    DIRECTION OUTPUT ;
    USE SIGNAL ;
    PORT
      LAYER M4 ;
        RECT  0 17.28 0.192 17.304 ;
    END
  END o[143]
  PIN o[144]
    DIRECTION OUTPUT ;
    USE SIGNAL ;
    PORT
      LAYER M4 ;
        RECT  0 17.376 0.192 17.4 ;
    END
  END o[144]
  PIN o[145]
    DIRECTION OUTPUT ;
    USE SIGNAL ;
    PORT
      LAYER M4 ;
        RECT  0 17.472 0.192 17.496 ;
    END
  END o[145]
  PIN o[146]
    DIRECTION OUTPUT ;
    USE SIGNAL ;
    PORT
      LAYER M4 ;
        RECT  0 17.616 0.192 17.64 ;
    END
  END o[146]
  PIN o[147]
    DIRECTION OUTPUT ;
    USE SIGNAL ;
    PORT
      LAYER M4 ;
        RECT  0 17.712 0.192 17.736 ;
    END
  END o[147]
  PIN o[148]
    DIRECTION OUTPUT ;
    USE SIGNAL ;
    PORT
      LAYER M4 ;
        RECT  0 17.808 0.192 17.832 ;
    END
  END o[148]
  PIN o[149]
    DIRECTION OUTPUT ;
    USE SIGNAL ;
    PORT
      LAYER M4 ;
        RECT  0 17.904 0.192 17.928 ;
    END
  END o[149]
  PIN o[14]
    DIRECTION OUTPUT ;
    USE SIGNAL ;
    PORT
      LAYER M4 ;
        RECT  0 3.696 0.192 3.72 ;
    END
  END o[14]
  PIN o[150]
    DIRECTION OUTPUT ;
    USE SIGNAL ;
    PORT
      LAYER M4 ;
        RECT  0 18 0.192 18.024 ;
    END
  END o[150]
  PIN o[151]
    DIRECTION OUTPUT ;
    USE SIGNAL ;
    PORT
      LAYER M4 ;
        RECT  0 18.096 0.192 18.12 ;
    END
  END o[151]
  PIN o[152]
    DIRECTION OUTPUT ;
    USE SIGNAL ;
    PORT
      LAYER M4 ;
        RECT  0 18.24 0.192 18.264 ;
    END
  END o[152]
  PIN o[153]
    DIRECTION OUTPUT ;
    USE SIGNAL ;
    PORT
      LAYER M4 ;
        RECT  0 18.336 0.192 18.36 ;
    END
  END o[153]
  PIN o[154]
    DIRECTION OUTPUT ;
    USE SIGNAL ;
    PORT
      LAYER M4 ;
        RECT  0 18.432 0.192 18.456 ;
    END
  END o[154]
  PIN o[155]
    DIRECTION OUTPUT ;
    USE SIGNAL ;
    PORT
      LAYER M4 ;
        RECT  0 18.528 0.192 18.552 ;
    END
  END o[155]
  PIN o[156]
    DIRECTION OUTPUT ;
    USE SIGNAL ;
    PORT
      LAYER M4 ;
        RECT  0 18.624 0.192 18.648 ;
    END
  END o[156]
  PIN o[157]
    DIRECTION OUTPUT ;
    USE SIGNAL ;
    PORT
      LAYER M4 ;
        RECT  0 18.768 0.192 18.792 ;
    END
  END o[157]
  PIN o[158]
    DIRECTION OUTPUT ;
    USE SIGNAL ;
    PORT
      LAYER M4 ;
        RECT  0 18.864 0.192 18.888 ;
    END
  END o[158]
  PIN o[159]
    DIRECTION OUTPUT ;
    USE SIGNAL ;
    PORT
      LAYER M4 ;
        RECT  0 18.96 0.192 18.984 ;
    END
  END o[159]
  PIN o[15]
    DIRECTION OUTPUT ;
    USE SIGNAL ;
    PORT
      LAYER M4 ;
        RECT  0 3.792 0.192 3.816 ;
    END
  END o[15]
  PIN o[160]
    DIRECTION OUTPUT ;
    USE SIGNAL ;
    PORT
      LAYER M4 ;
        RECT  0 19.056 0.192 19.08 ;
    END
  END o[160]
  PIN o[161]
    DIRECTION OUTPUT ;
    USE SIGNAL ;
    PORT
      LAYER M4 ;
        RECT  0 19.152 0.192 19.176 ;
    END
  END o[161]
  PIN o[162]
    DIRECTION OUTPUT ;
    USE SIGNAL ;
    PORT
      LAYER M4 ;
        RECT  0 19.296 0.192 19.32 ;
    END
  END o[162]
  PIN o[163]
    DIRECTION OUTPUT ;
    USE SIGNAL ;
    PORT
      LAYER M4 ;
        RECT  0 19.392 0.192 19.416 ;
    END
  END o[163]
  PIN o[164]
    DIRECTION OUTPUT ;
    USE SIGNAL ;
    PORT
      LAYER M4 ;
        RECT  0 19.488 0.192 19.512 ;
    END
  END o[164]
  PIN o[165]
    DIRECTION OUTPUT ;
    USE SIGNAL ;
    PORT
      LAYER M4 ;
        RECT  0 19.584 0.192 19.608 ;
    END
  END o[165]
  PIN o[166]
    DIRECTION OUTPUT ;
    USE SIGNAL ;
    PORT
      LAYER M4 ;
        RECT  0 19.68 0.192 19.704 ;
    END
  END o[166]
  PIN o[167]
    DIRECTION OUTPUT ;
    USE SIGNAL ;
    PORT
      LAYER M4 ;
        RECT  0 19.824 0.192 19.848 ;
    END
  END o[167]
  PIN o[168]
    DIRECTION OUTPUT ;
    USE SIGNAL ;
    PORT
      LAYER M4 ;
        RECT  0 19.92 0.192 19.944 ;
    END
  END o[168]
  PIN o[169]
    DIRECTION OUTPUT ;
    USE SIGNAL ;
    PORT
      LAYER M4 ;
        RECT  0 20.016 0.192 20.04 ;
    END
  END o[169]
  PIN o[16]
    DIRECTION OUTPUT ;
    USE SIGNAL ;
    PORT
      LAYER M4 ;
        RECT  0 3.888 0.192 3.912 ;
    END
  END o[16]
  PIN o[170]
    DIRECTION OUTPUT ;
    USE SIGNAL ;
    PORT
      LAYER M4 ;
        RECT  0 20.112 0.192 20.136 ;
    END
  END o[170]
  PIN o[171]
    DIRECTION OUTPUT ;
    USE SIGNAL ;
    PORT
      LAYER M4 ;
        RECT  0 20.208 0.192 20.232 ;
    END
  END o[171]
  PIN o[172]
    DIRECTION OUTPUT ;
    USE SIGNAL ;
    PORT
      LAYER M4 ;
        RECT  0 20.352 0.192 20.376 ;
    END
  END o[172]
  PIN o[173]
    DIRECTION OUTPUT ;
    USE SIGNAL ;
    PORT
      LAYER M4 ;
        RECT  0 20.448 0.192 20.472 ;
    END
  END o[173]
  PIN o[174]
    DIRECTION OUTPUT ;
    USE SIGNAL ;
    PORT
      LAYER M4 ;
        RECT  0 20.544 0.192 20.568 ;
    END
  END o[174]
  PIN o[175]
    DIRECTION OUTPUT ;
    USE SIGNAL ;
    PORT
      LAYER M4 ;
        RECT  0 20.64 0.192 20.664 ;
    END
  END o[175]
  PIN o[176]
    DIRECTION OUTPUT ;
    USE SIGNAL ;
    PORT
      LAYER M4 ;
        RECT  0 20.736 0.192 20.76 ;
    END
  END o[176]
  PIN o[177]
    DIRECTION OUTPUT ;
    USE SIGNAL ;
    PORT
      LAYER M4 ;
        RECT  0 20.88 0.192 20.904 ;
    END
  END o[177]
  PIN o[178]
    DIRECTION OUTPUT ;
    USE SIGNAL ;
    PORT
      LAYER M4 ;
        RECT  0 20.976 0.192 21 ;
    END
  END o[178]
  PIN o[179]
    DIRECTION OUTPUT ;
    USE SIGNAL ;
    PORT
      LAYER M4 ;
        RECT  0 21.072 0.192 21.096 ;
    END
  END o[179]
  PIN o[17]
    DIRECTION OUTPUT ;
    USE SIGNAL ;
    PORT
      LAYER M4 ;
        RECT  0 4.032 0.192 4.056 ;
    END
  END o[17]
  PIN o[180]
    DIRECTION OUTPUT ;
    USE SIGNAL ;
    PORT
      LAYER M4 ;
        RECT  0 21.168 0.192 21.192 ;
    END
  END o[180]
  PIN o[181]
    DIRECTION OUTPUT ;
    USE SIGNAL ;
    PORT
      LAYER M4 ;
        RECT  0 21.264 0.192 21.288 ;
    END
  END o[181]
  PIN o[182]
    DIRECTION OUTPUT ;
    USE SIGNAL ;
    PORT
      LAYER M4 ;
        RECT  0 21.36 0.192 21.384 ;
    END
  END o[182]
  PIN o[183]
    DIRECTION OUTPUT ;
    USE SIGNAL ;
    PORT
      LAYER M4 ;
        RECT  0 21.504 0.192 21.528 ;
    END
  END o[183]
  PIN o[184]
    DIRECTION OUTPUT ;
    USE SIGNAL ;
    PORT
      LAYER M4 ;
        RECT  0 21.6 0.192 21.624 ;
    END
  END o[184]
  PIN o[185]
    DIRECTION OUTPUT ;
    USE SIGNAL ;
    PORT
      LAYER M4 ;
        RECT  0 21.696 0.192 21.72 ;
    END
  END o[185]
  PIN o[186]
    DIRECTION OUTPUT ;
    USE SIGNAL ;
    PORT
      LAYER M4 ;
        RECT  0 21.792 0.192 21.816 ;
    END
  END o[186]
  PIN o[187]
    DIRECTION OUTPUT ;
    USE SIGNAL ;
    PORT
      LAYER M4 ;
        RECT  0 21.888 0.192 21.912 ;
    END
  END o[187]
  PIN o[188]
    DIRECTION OUTPUT ;
    USE SIGNAL ;
    PORT
      LAYER M4 ;
        RECT  0 22.032 0.192 22.056 ;
    END
  END o[188]
  PIN o[189]
    DIRECTION OUTPUT ;
    USE SIGNAL ;
    PORT
      LAYER M4 ;
        RECT  0 22.128 0.192 22.152 ;
    END
  END o[189]
  PIN o[18]
    DIRECTION OUTPUT ;
    USE SIGNAL ;
    PORT
      LAYER M4 ;
        RECT  0 4.128 0.192 4.152 ;
    END
  END o[18]
  PIN o[190]
    DIRECTION OUTPUT ;
    USE SIGNAL ;
    PORT
      LAYER M4 ;
        RECT  0 22.224 0.192 22.248 ;
    END
  END o[190]
  PIN o[191]
    DIRECTION OUTPUT ;
    USE SIGNAL ;
    PORT
      LAYER M4 ;
        RECT  0 22.32 0.192 22.344 ;
    END
  END o[191]
  PIN o[192]
    DIRECTION OUTPUT ;
    USE SIGNAL ;
    PORT
      LAYER M4 ;
        RECT  0 22.416 0.192 22.44 ;
    END
  END o[192]
  PIN o[193]
    DIRECTION OUTPUT ;
    USE SIGNAL ;
    PORT
      LAYER M4 ;
        RECT  0 22.56 0.192 22.584 ;
    END
  END o[193]
  PIN o[194]
    DIRECTION OUTPUT ;
    USE SIGNAL ;
    PORT
      LAYER M4 ;
        RECT  0 22.656 0.192 22.68 ;
    END
  END o[194]
  PIN o[195]
    DIRECTION OUTPUT ;
    USE SIGNAL ;
    PORT
      LAYER M4 ;
        RECT  0 22.752 0.192 22.776 ;
    END
  END o[195]
  PIN o[196]
    DIRECTION OUTPUT ;
    USE SIGNAL ;
    PORT
      LAYER M4 ;
        RECT  0 22.848 0.192 22.872 ;
    END
  END o[196]
  PIN o[197]
    DIRECTION OUTPUT ;
    USE SIGNAL ;
    PORT
      LAYER M4 ;
        RECT  0 22.944 0.192 22.968 ;
    END
  END o[197]
  PIN o[198]
    DIRECTION OUTPUT ;
    USE SIGNAL ;
    PORT
      LAYER M4 ;
        RECT  0 23.088 0.192 23.112 ;
    END
  END o[198]
  PIN o[199]
    DIRECTION OUTPUT ;
    USE SIGNAL ;
    PORT
      LAYER M4 ;
        RECT  0 23.184 0.192 23.208 ;
    END
  END o[199]
  PIN o[19]
    DIRECTION OUTPUT ;
    USE SIGNAL ;
    PORT
      LAYER M4 ;
        RECT  0 4.224 0.192 4.248 ;
    END
  END o[19]
  PIN o[1]
    DIRECTION OUTPUT ;
    USE SIGNAL ;
    PORT
      LAYER M4 ;
        RECT  0 2.352 0.192 2.376 ;
    END
  END o[1]
  PIN o[200]
    DIRECTION OUTPUT ;
    USE SIGNAL ;
    PORT
      LAYER M4 ;
        RECT  0 23.28 0.192 23.304 ;
    END
  END o[200]
  PIN o[201]
    DIRECTION OUTPUT ;
    USE SIGNAL ;
    PORT
      LAYER M4 ;
        RECT  0 23.376 0.192 23.4 ;
    END
  END o[201]
  PIN o[202]
    DIRECTION OUTPUT ;
    USE SIGNAL ;
    PORT
      LAYER M4 ;
        RECT  0 23.472 0.192 23.496 ;
    END
  END o[202]
  PIN o[203]
    DIRECTION OUTPUT ;
    USE SIGNAL ;
    PORT
      LAYER M4 ;
        RECT  0 23.616 0.192 23.64 ;
    END
  END o[203]
  PIN o[204]
    DIRECTION OUTPUT ;
    USE SIGNAL ;
    PORT
      LAYER M4 ;
        RECT  0 23.712 0.192 23.736 ;
    END
  END o[204]
  PIN o[205]
    DIRECTION OUTPUT ;
    USE SIGNAL ;
    PORT
      LAYER M4 ;
        RECT  0 23.808 0.192 23.832 ;
    END
  END o[205]
  PIN o[206]
    DIRECTION OUTPUT ;
    USE SIGNAL ;
    PORT
      LAYER M4 ;
        RECT  0 23.904 0.192 23.928 ;
    END
  END o[206]
  PIN o[207]
    DIRECTION OUTPUT ;
    USE SIGNAL ;
    PORT
      LAYER M4 ;
        RECT  0 24 0.192 24.024 ;
    END
  END o[207]
  PIN o[208]
    DIRECTION OUTPUT ;
    USE SIGNAL ;
    PORT
      LAYER M4 ;
        RECT  0 24.096 0.192 24.12 ;
    END
  END o[208]
  PIN o[209]
    DIRECTION OUTPUT ;
    USE SIGNAL ;
    PORT
      LAYER M4 ;
        RECT  0 24.24 0.192 24.264 ;
    END
  END o[209]
  PIN o[20]
    DIRECTION OUTPUT ;
    USE SIGNAL ;
    PORT
      LAYER M4 ;
        RECT  0 4.32 0.192 4.344 ;
    END
  END o[20]
  PIN o[210]
    DIRECTION OUTPUT ;
    USE SIGNAL ;
    PORT
      LAYER M4 ;
        RECT  0 24.336 0.192 24.36 ;
    END
  END o[210]
  PIN o[211]
    DIRECTION OUTPUT ;
    USE SIGNAL ;
    PORT
      LAYER M4 ;
        RECT  0 24.432 0.192 24.456 ;
    END
  END o[211]
  PIN o[212]
    DIRECTION OUTPUT ;
    USE SIGNAL ;
    PORT
      LAYER M4 ;
        RECT  0 24.528 0.192 24.552 ;
    END
  END o[212]
  PIN o[213]
    DIRECTION OUTPUT ;
    USE SIGNAL ;
    PORT
      LAYER M4 ;
        RECT  0 24.624 0.192 24.648 ;
    END
  END o[213]
  PIN o[214]
    DIRECTION OUTPUT ;
    USE SIGNAL ;
    PORT
      LAYER M4 ;
        RECT  0 24.768 0.192 24.792 ;
    END
  END o[214]
  PIN o[215]
    DIRECTION OUTPUT ;
    USE SIGNAL ;
    PORT
      LAYER M4 ;
        RECT  0 24.864 0.192 24.888 ;
    END
  END o[215]
  PIN o[216]
    DIRECTION OUTPUT ;
    USE SIGNAL ;
    PORT
      LAYER M4 ;
        RECT  0 24.96 0.192 24.984 ;
    END
  END o[216]
  PIN o[217]
    DIRECTION OUTPUT ;
    USE SIGNAL ;
    PORT
      LAYER M4 ;
        RECT  0 25.056 0.192 25.08 ;
    END
  END o[217]
  PIN o[218]
    DIRECTION OUTPUT ;
    USE SIGNAL ;
    PORT
      LAYER M4 ;
        RECT  0 25.152 0.192 25.176 ;
    END
  END o[218]
  PIN o[219]
    DIRECTION OUTPUT ;
    USE SIGNAL ;
    PORT
      LAYER M4 ;
        RECT  0 25.296 0.192 25.32 ;
    END
  END o[219]
  PIN o[21]
    DIRECTION OUTPUT ;
    USE SIGNAL ;
    PORT
      LAYER M4 ;
        RECT  0 4.416 0.192 4.44 ;
    END
  END o[21]
  PIN o[220]
    DIRECTION OUTPUT ;
    USE SIGNAL ;
    PORT
      LAYER M4 ;
        RECT  0 25.392 0.192 25.416 ;
    END
  END o[220]
  PIN o[221]
    DIRECTION OUTPUT ;
    USE SIGNAL ;
    PORT
      LAYER M4 ;
        RECT  0 25.488 0.192 25.512 ;
    END
  END o[221]
  PIN o[222]
    DIRECTION OUTPUT ;
    USE SIGNAL ;
    PORT
      LAYER M4 ;
        RECT  0 25.584 0.192 25.608 ;
    END
  END o[222]
  PIN o[223]
    DIRECTION OUTPUT ;
    USE SIGNAL ;
    PORT
      LAYER M4 ;
        RECT  0 25.68 0.192 25.704 ;
    END
  END o[223]
  PIN o[224]
    DIRECTION OUTPUT ;
    USE SIGNAL ;
    PORT
      LAYER M4 ;
        RECT  0 25.824 0.192 25.848 ;
    END
  END o[224]
  PIN o[225]
    DIRECTION OUTPUT ;
    USE SIGNAL ;
    PORT
      LAYER M4 ;
        RECT  0 25.92 0.192 25.944 ;
    END
  END o[225]
  PIN o[226]
    DIRECTION OUTPUT ;
    USE SIGNAL ;
    PORT
      LAYER M4 ;
        RECT  0 26.016 0.192 26.04 ;
    END
  END o[226]
  PIN o[227]
    DIRECTION OUTPUT ;
    USE SIGNAL ;
    PORT
      LAYER M4 ;
        RECT  0 26.112 0.192 26.136 ;
    END
  END o[227]
  PIN o[228]
    DIRECTION OUTPUT ;
    USE SIGNAL ;
    PORT
      LAYER M4 ;
        RECT  0 26.208 0.192 26.232 ;
    END
  END o[228]
  PIN o[229]
    DIRECTION OUTPUT ;
    USE SIGNAL ;
    PORT
      LAYER M4 ;
        RECT  0 26.352 0.192 26.376 ;
    END
  END o[229]
  PIN o[22]
    DIRECTION OUTPUT ;
    USE SIGNAL ;
    PORT
      LAYER M4 ;
        RECT  0 4.56 0.192 4.584 ;
    END
  END o[22]
  PIN o[230]
    DIRECTION OUTPUT ;
    USE SIGNAL ;
    PORT
      LAYER M4 ;
        RECT  0 26.448 0.192 26.472 ;
    END
  END o[230]
  PIN o[231]
    DIRECTION OUTPUT ;
    USE SIGNAL ;
    PORT
      LAYER M4 ;
        RECT  0 26.544 0.192 26.568 ;
    END
  END o[231]
  PIN o[232]
    DIRECTION OUTPUT ;
    USE SIGNAL ;
    PORT
      LAYER M4 ;
        RECT  0 26.64 0.192 26.664 ;
    END
  END o[232]
  PIN o[233]
    DIRECTION OUTPUT ;
    USE SIGNAL ;
    PORT
      LAYER M4 ;
        RECT  0 26.736 0.192 26.76 ;
    END
  END o[233]
  PIN o[234]
    DIRECTION OUTPUT ;
    USE SIGNAL ;
    PORT
      LAYER M4 ;
        RECT  0 26.88 0.192 26.904 ;
    END
  END o[234]
  PIN o[235]
    DIRECTION OUTPUT ;
    USE SIGNAL ;
    PORT
      LAYER M4 ;
        RECT  0 26.976 0.192 27 ;
    END
  END o[235]
  PIN o[236]
    DIRECTION OUTPUT ;
    USE SIGNAL ;
    PORT
      LAYER M4 ;
        RECT  0 27.072 0.192 27.096 ;
    END
  END o[236]
  PIN o[237]
    DIRECTION OUTPUT ;
    USE SIGNAL ;
    PORT
      LAYER M4 ;
        RECT  0 27.168 0.192 27.192 ;
    END
  END o[237]
  PIN o[238]
    DIRECTION OUTPUT ;
    USE SIGNAL ;
    PORT
      LAYER M4 ;
        RECT  0 27.264 0.192 27.288 ;
    END
  END o[238]
  PIN o[239]
    DIRECTION OUTPUT ;
    USE SIGNAL ;
    PORT
      LAYER M4 ;
        RECT  0 27.36 0.192 27.384 ;
    END
  END o[239]
  PIN o[23]
    DIRECTION OUTPUT ;
    USE SIGNAL ;
    PORT
      LAYER M4 ;
        RECT  0 4.656 0.192 4.68 ;
    END
  END o[23]
  PIN o[240]
    DIRECTION OUTPUT ;
    USE SIGNAL ;
    PORT
      LAYER M4 ;
        RECT  0 27.504 0.192 27.528 ;
    END
  END o[240]
  PIN o[241]
    DIRECTION OUTPUT ;
    USE SIGNAL ;
    PORT
      LAYER M4 ;
        RECT  0 27.6 0.192 27.624 ;
    END
  END o[241]
  PIN o[242]
    DIRECTION OUTPUT ;
    USE SIGNAL ;
    PORT
      LAYER M4 ;
        RECT  0 27.696 0.192 27.72 ;
    END
  END o[242]
  PIN o[243]
    DIRECTION OUTPUT ;
    USE SIGNAL ;
    PORT
      LAYER M4 ;
        RECT  0 27.792 0.192 27.816 ;
    END
  END o[243]
  PIN o[244]
    DIRECTION OUTPUT ;
    USE SIGNAL ;
    PORT
      LAYER M4 ;
        RECT  0 27.888 0.192 27.912 ;
    END
  END o[244]
  PIN o[245]
    DIRECTION OUTPUT ;
    USE SIGNAL ;
    PORT
      LAYER M4 ;
        RECT  0 28.032 0.192 28.056 ;
    END
  END o[245]
  PIN o[246]
    DIRECTION OUTPUT ;
    USE SIGNAL ;
    PORT
      LAYER M4 ;
        RECT  0 28.128 0.192 28.152 ;
    END
  END o[246]
  PIN o[247]
    DIRECTION OUTPUT ;
    USE SIGNAL ;
    PORT
      LAYER M4 ;
        RECT  0 28.224 0.192 28.248 ;
    END
  END o[247]
  PIN o[248]
    DIRECTION OUTPUT ;
    USE SIGNAL ;
    PORT
      LAYER M4 ;
        RECT  0 28.32 0.192 28.344 ;
    END
  END o[248]
  PIN o[249]
    DIRECTION OUTPUT ;
    USE SIGNAL ;
    PORT
      LAYER M4 ;
        RECT  0 28.416 0.192 28.44 ;
    END
  END o[249]
  PIN o[24]
    DIRECTION OUTPUT ;
    USE SIGNAL ;
    PORT
      LAYER M4 ;
        RECT  0 4.752 0.192 4.776 ;
    END
  END o[24]
  PIN o[250]
    DIRECTION OUTPUT ;
    USE SIGNAL ;
    PORT
      LAYER M4 ;
        RECT  0 28.56 0.192 28.584 ;
    END
  END o[250]
  PIN o[251]
    DIRECTION OUTPUT ;
    USE SIGNAL ;
    PORT
      LAYER M4 ;
        RECT  0 28.656 0.192 28.68 ;
    END
  END o[251]
  PIN o[252]
    DIRECTION OUTPUT ;
    USE SIGNAL ;
    PORT
      LAYER M4 ;
        RECT  0 28.752 0.192 28.776 ;
    END
  END o[252]
  PIN o[253]
    DIRECTION OUTPUT ;
    USE SIGNAL ;
    PORT
      LAYER M4 ;
        RECT  0 28.848 0.192 28.872 ;
    END
  END o[253]
  PIN o[254]
    DIRECTION OUTPUT ;
    USE SIGNAL ;
    PORT
      LAYER M4 ;
        RECT  0 28.944 0.192 28.968 ;
    END
  END o[254]
  PIN o[255]
    DIRECTION OUTPUT ;
    USE SIGNAL ;
    PORT
      LAYER M4 ;
        RECT  0 29.088 0.192 29.112 ;
    END
  END o[255]
  PIN o[256]
    DIRECTION OUTPUT ;
    USE SIGNAL ;
    PORT
      LAYER M4 ;
        RECT  0 29.184 0.192 29.208 ;
    END
  END o[256]
  PIN o[257]
    DIRECTION OUTPUT ;
    USE SIGNAL ;
    PORT
      LAYER M4 ;
        RECT  0 29.28 0.192 29.304 ;
    END
  END o[257]
  PIN o[258]
    DIRECTION OUTPUT ;
    USE SIGNAL ;
    PORT
      LAYER M4 ;
        RECT  0 29.376 0.192 29.4 ;
    END
  END o[258]
  PIN o[259]
    DIRECTION OUTPUT ;
    USE SIGNAL ;
    PORT
      LAYER M4 ;
        RECT  0 29.472 0.192 29.496 ;
    END
  END o[259]
  PIN o[25]
    DIRECTION OUTPUT ;
    USE SIGNAL ;
    PORT
      LAYER M4 ;
        RECT  0 4.848 0.192 4.872 ;
    END
  END o[25]
  PIN o[260]
    DIRECTION OUTPUT ;
    USE SIGNAL ;
    PORT
      LAYER M4 ;
        RECT  0 29.616 0.192 29.64 ;
    END
  END o[260]
  PIN o[261]
    DIRECTION OUTPUT ;
    USE SIGNAL ;
    PORT
      LAYER M4 ;
        RECT  0 29.712 0.192 29.736 ;
    END
  END o[261]
  PIN o[262]
    DIRECTION OUTPUT ;
    USE SIGNAL ;
    PORT
      LAYER M4 ;
        RECT  0 29.808 0.192 29.832 ;
    END
  END o[262]
  PIN o[263]
    DIRECTION OUTPUT ;
    USE SIGNAL ;
    PORT
      LAYER M4 ;
        RECT  0 29.904 0.192 29.928 ;
    END
  END o[263]
  PIN o[264]
    DIRECTION OUTPUT ;
    USE SIGNAL ;
    PORT
      LAYER M4 ;
        RECT  0 30 0.192 30.024 ;
    END
  END o[264]
  PIN o[265]
    DIRECTION OUTPUT ;
    USE SIGNAL ;
    PORT
      LAYER M4 ;
        RECT  0 30.096 0.192 30.12 ;
    END
  END o[265]
  PIN o[266]
    DIRECTION OUTPUT ;
    USE SIGNAL ;
    PORT
      LAYER M4 ;
        RECT  0 30.24 0.192 30.264 ;
    END
  END o[266]
  PIN o[267]
    DIRECTION OUTPUT ;
    USE SIGNAL ;
    PORT
      LAYER M4 ;
        RECT  0 30.336 0.192 30.36 ;
    END
  END o[267]
  PIN o[268]
    DIRECTION OUTPUT ;
    USE SIGNAL ;
    PORT
      LAYER M4 ;
        RECT  0 30.432 0.192 30.456 ;
    END
  END o[268]
  PIN o[269]
    DIRECTION OUTPUT ;
    USE SIGNAL ;
    PORT
      LAYER M4 ;
        RECT  0 30.528 0.192 30.552 ;
    END
  END o[269]
  PIN o[26]
    DIRECTION OUTPUT ;
    USE SIGNAL ;
    PORT
      LAYER M4 ;
        RECT  0 4.944 0.192 4.968 ;
    END
  END o[26]
  PIN o[270]
    DIRECTION OUTPUT ;
    USE SIGNAL ;
    PORT
      LAYER M4 ;
        RECT  0 30.624 0.192 30.648 ;
    END
  END o[270]
  PIN o[271]
    DIRECTION OUTPUT ;
    USE SIGNAL ;
    PORT
      LAYER M4 ;
        RECT  0 30.768 0.192 30.792 ;
    END
  END o[271]
  PIN o[272]
    DIRECTION OUTPUT ;
    USE SIGNAL ;
    PORT
      LAYER M4 ;
        RECT  0 30.864 0.192 30.888 ;
    END
  END o[272]
  PIN o[273]
    DIRECTION OUTPUT ;
    USE SIGNAL ;
    PORT
      LAYER M4 ;
        RECT  0 30.96 0.192 30.984 ;
    END
  END o[273]
  PIN o[274]
    DIRECTION OUTPUT ;
    USE SIGNAL ;
    PORT
      LAYER M4 ;
        RECT  0 31.056 0.192 31.08 ;
    END
  END o[274]
  PIN o[275]
    DIRECTION OUTPUT ;
    USE SIGNAL ;
    PORT
      LAYER M4 ;
        RECT  0 31.152 0.192 31.176 ;
    END
  END o[275]
  PIN o[276]
    DIRECTION OUTPUT ;
    USE SIGNAL ;
    PORT
      LAYER M4 ;
        RECT  0 31.296 0.192 31.32 ;
    END
  END o[276]
  PIN o[277]
    DIRECTION OUTPUT ;
    USE SIGNAL ;
    PORT
      LAYER M4 ;
        RECT  0 31.392 0.192 31.416 ;
    END
  END o[277]
  PIN o[278]
    DIRECTION OUTPUT ;
    USE SIGNAL ;
    PORT
      LAYER M4 ;
        RECT  0 31.488 0.192 31.512 ;
    END
  END o[278]
  PIN o[279]
    DIRECTION OUTPUT ;
    USE SIGNAL ;
    PORT
      LAYER M4 ;
        RECT  0 31.584 0.192 31.608 ;
    END
  END o[279]
  PIN o[27]
    DIRECTION OUTPUT ;
    USE SIGNAL ;
    PORT
      LAYER M4 ;
        RECT  0 5.088 0.192 5.112 ;
    END
  END o[27]
  PIN o[280]
    DIRECTION OUTPUT ;
    USE SIGNAL ;
    PORT
      LAYER M4 ;
        RECT  0 31.68 0.192 31.704 ;
    END
  END o[280]
  PIN o[281]
    DIRECTION OUTPUT ;
    USE SIGNAL ;
    PORT
      LAYER M4 ;
        RECT  0 31.824 0.192 31.848 ;
    END
  END o[281]
  PIN o[282]
    DIRECTION OUTPUT ;
    USE SIGNAL ;
    PORT
      LAYER M4 ;
        RECT  0 31.92 0.192 31.944 ;
    END
  END o[282]
  PIN o[283]
    DIRECTION OUTPUT ;
    USE SIGNAL ;
    PORT
      LAYER M4 ;
        RECT  0 32.016 0.192 32.04 ;
    END
  END o[283]
  PIN o[284]
    DIRECTION OUTPUT ;
    USE SIGNAL ;
    PORT
      LAYER M4 ;
        RECT  0 32.112 0.192 32.136 ;
    END
  END o[284]
  PIN o[285]
    DIRECTION OUTPUT ;
    USE SIGNAL ;
    PORT
      LAYER M4 ;
        RECT  0 32.208 0.192 32.232 ;
    END
  END o[285]
  PIN o[286]
    DIRECTION OUTPUT ;
    USE SIGNAL ;
    PORT
      LAYER M4 ;
        RECT  0 32.352 0.192 32.376 ;
    END
  END o[286]
  PIN o[287]
    DIRECTION OUTPUT ;
    USE SIGNAL ;
    PORT
      LAYER M4 ;
        RECT  0 32.448 0.192 32.472 ;
    END
  END o[287]
  PIN o[288]
    DIRECTION OUTPUT ;
    USE SIGNAL ;
    PORT
      LAYER M4 ;
        RECT  0 32.544 0.192 32.568 ;
    END
  END o[288]
  PIN o[289]
    DIRECTION OUTPUT ;
    USE SIGNAL ;
    PORT
      LAYER M4 ;
        RECT  0 32.64 0.192 32.664 ;
    END
  END o[289]
  PIN o[28]
    DIRECTION OUTPUT ;
    USE SIGNAL ;
    PORT
      LAYER M4 ;
        RECT  0 5.184 0.192 5.208 ;
    END
  END o[28]
  PIN o[290]
    DIRECTION OUTPUT ;
    USE SIGNAL ;
    PORT
      LAYER M4 ;
        RECT  0 32.736 0.192 32.76 ;
    END
  END o[290]
  PIN o[291]
    DIRECTION OUTPUT ;
    USE SIGNAL ;
    PORT
      LAYER M4 ;
        RECT  0 32.88 0.192 32.904 ;
    END
  END o[291]
  PIN o[292]
    DIRECTION OUTPUT ;
    USE SIGNAL ;
    PORT
      LAYER M4 ;
        RECT  0 32.976 0.192 33 ;
    END
  END o[292]
  PIN o[293]
    DIRECTION OUTPUT ;
    USE SIGNAL ;
    PORT
      LAYER M4 ;
        RECT  0 33.072 0.192 33.096 ;
    END
  END o[293]
  PIN o[294]
    DIRECTION OUTPUT ;
    USE SIGNAL ;
    PORT
      LAYER M4 ;
        RECT  0 33.168 0.192 33.192 ;
    END
  END o[294]
  PIN o[295]
    DIRECTION OUTPUT ;
    USE SIGNAL ;
    PORT
      LAYER M4 ;
        RECT  0 33.264 0.192 33.288 ;
    END
  END o[295]
  PIN o[296]
    DIRECTION OUTPUT ;
    USE SIGNAL ;
    PORT
      LAYER M4 ;
        RECT  0 33.36 0.192 33.384 ;
    END
  END o[296]
  PIN o[297]
    DIRECTION OUTPUT ;
    USE SIGNAL ;
    PORT
      LAYER M4 ;
        RECT  0 33.504 0.192 33.528 ;
    END
  END o[297]
  PIN o[298]
    DIRECTION OUTPUT ;
    USE SIGNAL ;
    PORT
      LAYER M4 ;
        RECT  0 33.6 0.192 33.624 ;
    END
  END o[298]
  PIN o[299]
    DIRECTION OUTPUT ;
    USE SIGNAL ;
    PORT
      LAYER M4 ;
        RECT  0 33.696 0.192 33.72 ;
    END
  END o[299]
  PIN o[29]
    DIRECTION OUTPUT ;
    USE SIGNAL ;
    PORT
      LAYER M4 ;
        RECT  0 5.28 0.192 5.304 ;
    END
  END o[29]
  PIN o[2]
    DIRECTION OUTPUT ;
    USE SIGNAL ;
    PORT
      LAYER M4 ;
        RECT  0 2.448 0.192 2.472 ;
    END
  END o[2]
  PIN o[300]
    DIRECTION OUTPUT ;
    USE SIGNAL ;
    PORT
      LAYER M4 ;
        RECT  0 33.792 0.192 33.816 ;
    END
  END o[300]
  PIN o[301]
    DIRECTION OUTPUT ;
    USE SIGNAL ;
    PORT
      LAYER M4 ;
        RECT  0 33.888 0.192 33.912 ;
    END
  END o[301]
  PIN o[302]
    DIRECTION OUTPUT ;
    USE SIGNAL ;
    PORT
      LAYER M4 ;
        RECT  0 34.032 0.192 34.056 ;
    END
  END o[302]
  PIN o[303]
    DIRECTION OUTPUT ;
    USE SIGNAL ;
    PORT
      LAYER M4 ;
        RECT  0 34.128 0.192 34.152 ;
    END
  END o[303]
  PIN o[304]
    DIRECTION OUTPUT ;
    USE SIGNAL ;
    PORT
      LAYER M4 ;
        RECT  0 34.224 0.192 34.248 ;
    END
  END o[304]
  PIN o[305]
    DIRECTION OUTPUT ;
    USE SIGNAL ;
    PORT
      LAYER M4 ;
        RECT  0 34.32 0.192 34.344 ;
    END
  END o[305]
  PIN o[306]
    DIRECTION OUTPUT ;
    USE SIGNAL ;
    PORT
      LAYER M4 ;
        RECT  0 34.416 0.192 34.44 ;
    END
  END o[306]
  PIN o[307]
    DIRECTION OUTPUT ;
    USE SIGNAL ;
    PORT
      LAYER M4 ;
        RECT  0 34.56 0.192 34.584 ;
    END
  END o[307]
  PIN o[308]
    DIRECTION OUTPUT ;
    USE SIGNAL ;
    PORT
      LAYER M4 ;
        RECT  0 34.656 0.192 34.68 ;
    END
  END o[308]
  PIN o[309]
    DIRECTION OUTPUT ;
    USE SIGNAL ;
    PORT
      LAYER M4 ;
        RECT  0 34.752 0.192 34.776 ;
    END
  END o[309]
  PIN o[30]
    DIRECTION OUTPUT ;
    USE SIGNAL ;
    PORT
      LAYER M4 ;
        RECT  0 5.376 0.192 5.4 ;
    END
  END o[30]
  PIN o[310]
    DIRECTION OUTPUT ;
    USE SIGNAL ;
    PORT
      LAYER M4 ;
        RECT  0 34.848 0.192 34.872 ;
    END
  END o[310]
  PIN o[311]
    DIRECTION OUTPUT ;
    USE SIGNAL ;
    PORT
      LAYER M4 ;
        RECT  0 34.944 0.192 34.968 ;
    END
  END o[311]
  PIN o[312]
    DIRECTION OUTPUT ;
    USE SIGNAL ;
    PORT
      LAYER M4 ;
        RECT  0 35.088 0.192 35.112 ;
    END
  END o[312]
  PIN o[313]
    DIRECTION OUTPUT ;
    USE SIGNAL ;
    PORT
      LAYER M4 ;
        RECT  0 35.184 0.192 35.208 ;
    END
  END o[313]
  PIN o[314]
    DIRECTION OUTPUT ;
    USE SIGNAL ;
    PORT
      LAYER M4 ;
        RECT  0 35.28 0.192 35.304 ;
    END
  END o[314]
  PIN o[315]
    DIRECTION OUTPUT ;
    USE SIGNAL ;
    PORT
      LAYER M4 ;
        RECT  0 35.376 0.192 35.4 ;
    END
  END o[315]
  PIN o[316]
    DIRECTION OUTPUT ;
    USE SIGNAL ;
    PORT
      LAYER M4 ;
        RECT  0 35.472 0.192 35.496 ;
    END
  END o[316]
  PIN o[317]
    DIRECTION OUTPUT ;
    USE SIGNAL ;
    PORT
      LAYER M4 ;
        RECT  0 35.616 0.192 35.64 ;
    END
  END o[317]
  PIN o[318]
    DIRECTION OUTPUT ;
    USE SIGNAL ;
    PORT
      LAYER M4 ;
        RECT  0 35.712 0.192 35.736 ;
    END
  END o[318]
  PIN o[319]
    DIRECTION OUTPUT ;
    USE SIGNAL ;
    PORT
      LAYER M4 ;
        RECT  0 35.808 0.192 35.832 ;
    END
  END o[319]
  PIN o[31]
    DIRECTION OUTPUT ;
    USE SIGNAL ;
    PORT
      LAYER M4 ;
        RECT  0 5.472 0.192 5.496 ;
    END
  END o[31]
  PIN o[320]
    DIRECTION OUTPUT ;
    USE SIGNAL ;
    PORT
      LAYER M4 ;
        RECT  0 35.904 0.192 35.928 ;
    END
  END o[320]
  PIN o[321]
    DIRECTION OUTPUT ;
    USE SIGNAL ;
    PORT
      LAYER M4 ;
        RECT  0 36 0.192 36.024 ;
    END
  END o[321]
  PIN o[322]
    DIRECTION OUTPUT ;
    USE SIGNAL ;
    PORT
      LAYER M4 ;
        RECT  0 36.096 0.192 36.12 ;
    END
  END o[322]
  PIN o[323]
    DIRECTION OUTPUT ;
    USE SIGNAL ;
    PORT
      LAYER M4 ;
        RECT  0 36.24 0.192 36.264 ;
    END
  END o[323]
  PIN o[324]
    DIRECTION OUTPUT ;
    USE SIGNAL ;
    PORT
      LAYER M4 ;
        RECT  0 36.336 0.192 36.36 ;
    END
  END o[324]
  PIN o[325]
    DIRECTION OUTPUT ;
    USE SIGNAL ;
    PORT
      LAYER M4 ;
        RECT  0 36.432 0.192 36.456 ;
    END
  END o[325]
  PIN o[326]
    DIRECTION OUTPUT ;
    USE SIGNAL ;
    PORT
      LAYER M4 ;
        RECT  0 36.528 0.192 36.552 ;
    END
  END o[326]
  PIN o[327]
    DIRECTION OUTPUT ;
    USE SIGNAL ;
    PORT
      LAYER M4 ;
        RECT  0 36.624 0.192 36.648 ;
    END
  END o[327]
  PIN o[328]
    DIRECTION OUTPUT ;
    USE SIGNAL ;
    PORT
      LAYER M4 ;
        RECT  0 36.768 0.192 36.792 ;
    END
  END o[328]
  PIN o[329]
    DIRECTION OUTPUT ;
    USE SIGNAL ;
    PORT
      LAYER M4 ;
        RECT  0 36.864 0.192 36.888 ;
    END
  END o[329]
  PIN o[32]
    DIRECTION OUTPUT ;
    USE SIGNAL ;
    PORT
      LAYER M4 ;
        RECT  0 5.616 0.192 5.64 ;
    END
  END o[32]
  PIN o[330]
    DIRECTION OUTPUT ;
    USE SIGNAL ;
    PORT
      LAYER M4 ;
        RECT  0 36.96 0.192 36.984 ;
    END
  END o[330]
  PIN o[331]
    DIRECTION OUTPUT ;
    USE SIGNAL ;
    PORT
      LAYER M4 ;
        RECT  0 37.056 0.192 37.08 ;
    END
  END o[331]
  PIN o[332]
    DIRECTION OUTPUT ;
    USE SIGNAL ;
    PORT
      LAYER M4 ;
        RECT  0 37.152 0.192 37.176 ;
    END
  END o[332]
  PIN o[333]
    DIRECTION OUTPUT ;
    USE SIGNAL ;
    PORT
      LAYER M4 ;
        RECT  0 37.296 0.192 37.32 ;
    END
  END o[333]
  PIN o[334]
    DIRECTION OUTPUT ;
    USE SIGNAL ;
    PORT
      LAYER M4 ;
        RECT  0 37.392 0.192 37.416 ;
    END
  END o[334]
  PIN o[335]
    DIRECTION OUTPUT ;
    USE SIGNAL ;
    PORT
      LAYER M4 ;
        RECT  0 37.488 0.192 37.512 ;
    END
  END o[335]
  PIN o[336]
    DIRECTION OUTPUT ;
    USE SIGNAL ;
    PORT
      LAYER M4 ;
        RECT  0 37.584 0.192 37.608 ;
    END
  END o[336]
  PIN o[337]
    DIRECTION OUTPUT ;
    USE SIGNAL ;
    PORT
      LAYER M4 ;
        RECT  0 37.68 0.192 37.704 ;
    END
  END o[337]
  PIN o[338]
    DIRECTION OUTPUT ;
    USE SIGNAL ;
    PORT
      LAYER M4 ;
        RECT  0 37.824 0.192 37.848 ;
    END
  END o[338]
  PIN o[339]
    DIRECTION OUTPUT ;
    USE SIGNAL ;
    PORT
      LAYER M4 ;
        RECT  0 37.92 0.192 37.944 ;
    END
  END o[339]
  PIN o[33]
    DIRECTION OUTPUT ;
    USE SIGNAL ;
    PORT
      LAYER M4 ;
        RECT  0 5.712 0.192 5.736 ;
    END
  END o[33]
  PIN o[340]
    DIRECTION OUTPUT ;
    USE SIGNAL ;
    PORT
      LAYER M4 ;
        RECT  0 38.016 0.192 38.04 ;
    END
  END o[340]
  PIN o[341]
    DIRECTION OUTPUT ;
    USE SIGNAL ;
    PORT
      LAYER M4 ;
        RECT  0 38.112 0.192 38.136 ;
    END
  END o[341]
  PIN o[342]
    DIRECTION OUTPUT ;
    USE SIGNAL ;
    PORT
      LAYER M4 ;
        RECT  0 38.208 0.192 38.232 ;
    END
  END o[342]
  PIN o[343]
    DIRECTION OUTPUT ;
    USE SIGNAL ;
    PORT
      LAYER M4 ;
        RECT  0 38.352 0.192 38.376 ;
    END
  END o[343]
  PIN o[344]
    DIRECTION OUTPUT ;
    USE SIGNAL ;
    PORT
      LAYER M4 ;
        RECT  0 38.448 0.192 38.472 ;
    END
  END o[344]
  PIN o[345]
    DIRECTION OUTPUT ;
    USE SIGNAL ;
    PORT
      LAYER M4 ;
        RECT  0 38.544 0.192 38.568 ;
    END
  END o[345]
  PIN o[346]
    DIRECTION OUTPUT ;
    USE SIGNAL ;
    PORT
      LAYER M4 ;
        RECT  0 38.64 0.192 38.664 ;
    END
  END o[346]
  PIN o[347]
    DIRECTION OUTPUT ;
    USE SIGNAL ;
    PORT
      LAYER M4 ;
        RECT  0 38.736 0.192 38.76 ;
    END
  END o[347]
  PIN o[348]
    DIRECTION OUTPUT ;
    USE SIGNAL ;
    PORT
      LAYER M4 ;
        RECT  0 38.88 0.192 38.904 ;
    END
  END o[348]
  PIN o[349]
    DIRECTION OUTPUT ;
    USE SIGNAL ;
    PORT
      LAYER M4 ;
        RECT  0 38.976 0.192 39 ;
    END
  END o[349]
  PIN o[34]
    DIRECTION OUTPUT ;
    USE SIGNAL ;
    PORT
      LAYER M4 ;
        RECT  0 5.808 0.192 5.832 ;
    END
  END o[34]
  PIN o[350]
    DIRECTION OUTPUT ;
    USE SIGNAL ;
    PORT
      LAYER M4 ;
        RECT  0 39.072 0.192 39.096 ;
    END
  END o[350]
  PIN o[351]
    DIRECTION OUTPUT ;
    USE SIGNAL ;
    PORT
      LAYER M4 ;
        RECT  0 39.168 0.192 39.192 ;
    END
  END o[351]
  PIN o[352]
    DIRECTION OUTPUT ;
    USE SIGNAL ;
    PORT
      LAYER M4 ;
        RECT  0 39.264 0.192 39.288 ;
    END
  END o[352]
  PIN o[353]
    DIRECTION OUTPUT ;
    USE SIGNAL ;
    PORT
      LAYER M4 ;
        RECT  0 39.36 0.192 39.384 ;
    END
  END o[353]
  PIN o[354]
    DIRECTION OUTPUT ;
    USE SIGNAL ;
    PORT
      LAYER M4 ;
        RECT  0 39.504 0.192 39.528 ;
    END
  END o[354]
  PIN o[355]
    DIRECTION OUTPUT ;
    USE SIGNAL ;
    PORT
      LAYER M4 ;
        RECT  0 39.6 0.192 39.624 ;
    END
  END o[355]
  PIN o[356]
    DIRECTION OUTPUT ;
    USE SIGNAL ;
    PORT
      LAYER M4 ;
        RECT  0 39.696 0.192 39.72 ;
    END
  END o[356]
  PIN o[357]
    DIRECTION OUTPUT ;
    USE SIGNAL ;
    PORT
      LAYER M4 ;
        RECT  0 39.792 0.192 39.816 ;
    END
  END o[357]
  PIN o[358]
    DIRECTION OUTPUT ;
    USE SIGNAL ;
    PORT
      LAYER M4 ;
        RECT  0 39.888 0.192 39.912 ;
    END
  END o[358]
  PIN o[359]
    DIRECTION OUTPUT ;
    USE SIGNAL ;
    PORT
      LAYER M4 ;
        RECT  0 40.032 0.192 40.056 ;
    END
  END o[359]
  PIN o[35]
    DIRECTION OUTPUT ;
    USE SIGNAL ;
    PORT
      LAYER M4 ;
        RECT  0 5.904 0.192 5.928 ;
    END
  END o[35]
  PIN o[360]
    DIRECTION OUTPUT ;
    USE SIGNAL ;
    PORT
      LAYER M4 ;
        RECT  0 40.128 0.192 40.152 ;
    END
  END o[360]
  PIN o[361]
    DIRECTION OUTPUT ;
    USE SIGNAL ;
    PORT
      LAYER M4 ;
        RECT  0 40.224 0.192 40.248 ;
    END
  END o[361]
  PIN o[362]
    DIRECTION OUTPUT ;
    USE SIGNAL ;
    PORT
      LAYER M4 ;
        RECT  0 40.32 0.192 40.344 ;
    END
  END o[362]
  PIN o[363]
    DIRECTION OUTPUT ;
    USE SIGNAL ;
    PORT
      LAYER M4 ;
        RECT  0 40.416 0.192 40.44 ;
    END
  END o[363]
  PIN o[364]
    DIRECTION OUTPUT ;
    USE SIGNAL ;
    PORT
      LAYER M4 ;
        RECT  0 40.56 0.192 40.584 ;
    END
  END o[364]
  PIN o[365]
    DIRECTION OUTPUT ;
    USE SIGNAL ;
    PORT
      LAYER M4 ;
        RECT  0 40.656 0.192 40.68 ;
    END
  END o[365]
  PIN o[366]
    DIRECTION OUTPUT ;
    USE SIGNAL ;
    PORT
      LAYER M4 ;
        RECT  0 40.752 0.192 40.776 ;
    END
  END o[366]
  PIN o[367]
    DIRECTION OUTPUT ;
    USE SIGNAL ;
    PORT
      LAYER M4 ;
        RECT  0 40.848 0.192 40.872 ;
    END
  END o[367]
  PIN o[368]
    DIRECTION OUTPUT ;
    USE SIGNAL ;
    PORT
      LAYER M4 ;
        RECT  0 40.944 0.192 40.968 ;
    END
  END o[368]
  PIN o[369]
    DIRECTION OUTPUT ;
    USE SIGNAL ;
    PORT
      LAYER M4 ;
        RECT  0 41.088 0.192 41.112 ;
    END
  END o[369]
  PIN o[36]
    DIRECTION OUTPUT ;
    USE SIGNAL ;
    PORT
      LAYER M4 ;
        RECT  0 6 0.192 6.024 ;
    END
  END o[36]
  PIN o[370]
    DIRECTION OUTPUT ;
    USE SIGNAL ;
    PORT
      LAYER M4 ;
        RECT  0 41.184 0.192 41.208 ;
    END
  END o[370]
  PIN o[371]
    DIRECTION OUTPUT ;
    USE SIGNAL ;
    PORT
      LAYER M4 ;
        RECT  0 41.28 0.192 41.304 ;
    END
  END o[371]
  PIN o[372]
    DIRECTION OUTPUT ;
    USE SIGNAL ;
    PORT
      LAYER M4 ;
        RECT  0 41.376 0.192 41.4 ;
    END
  END o[372]
  PIN o[373]
    DIRECTION OUTPUT ;
    USE SIGNAL ;
    PORT
      LAYER M4 ;
        RECT  0 41.472 0.192 41.496 ;
    END
  END o[373]
  PIN o[374]
    DIRECTION OUTPUT ;
    USE SIGNAL ;
    PORT
      LAYER M4 ;
        RECT  0 41.616 0.192 41.64 ;
    END
  END o[374]
  PIN o[375]
    DIRECTION OUTPUT ;
    USE SIGNAL ;
    PORT
      LAYER M4 ;
        RECT  0 41.712 0.192 41.736 ;
    END
  END o[375]
  PIN o[376]
    DIRECTION OUTPUT ;
    USE SIGNAL ;
    PORT
      LAYER M4 ;
        RECT  0 41.808 0.192 41.832 ;
    END
  END o[376]
  PIN o[377]
    DIRECTION OUTPUT ;
    USE SIGNAL ;
    PORT
      LAYER M4 ;
        RECT  0 41.904 0.192 41.928 ;
    END
  END o[377]
  PIN o[378]
    DIRECTION OUTPUT ;
    USE SIGNAL ;
    PORT
      LAYER M4 ;
        RECT  0 42 0.192 42.024 ;
    END
  END o[378]
  PIN o[379]
    DIRECTION OUTPUT ;
    USE SIGNAL ;
    PORT
      LAYER M4 ;
        RECT  0 42.096 0.192 42.12 ;
    END
  END o[379]
  PIN o[37]
    DIRECTION OUTPUT ;
    USE SIGNAL ;
    PORT
      LAYER M4 ;
        RECT  0 6.096 0.192 6.12 ;
    END
  END o[37]
  PIN o[380]
    DIRECTION OUTPUT ;
    USE SIGNAL ;
    PORT
      LAYER M4 ;
        RECT  0 42.24 0.192 42.264 ;
    END
  END o[380]
  PIN o[381]
    DIRECTION OUTPUT ;
    USE SIGNAL ;
    PORT
      LAYER M4 ;
        RECT  0 42.336 0.192 42.36 ;
    END
  END o[381]
  PIN o[382]
    DIRECTION OUTPUT ;
    USE SIGNAL ;
    PORT
      LAYER M4 ;
        RECT  0 42.432 0.192 42.456 ;
    END
  END o[382]
  PIN o[383]
    DIRECTION OUTPUT ;
    USE SIGNAL ;
    PORT
      LAYER M4 ;
        RECT  0 42.528 0.192 42.552 ;
    END
  END o[383]
  PIN o[384]
    DIRECTION OUTPUT ;
    USE SIGNAL ;
    PORT
      LAYER M4 ;
        RECT  0 42.624 0.192 42.648 ;
    END
  END o[384]
  PIN o[385]
    DIRECTION OUTPUT ;
    USE SIGNAL ;
    PORT
      LAYER M4 ;
        RECT  0 42.768 0.192 42.792 ;
    END
  END o[385]
  PIN o[386]
    DIRECTION OUTPUT ;
    USE SIGNAL ;
    PORT
      LAYER M4 ;
        RECT  0 42.864 0.192 42.888 ;
    END
  END o[386]
  PIN o[387]
    DIRECTION OUTPUT ;
    USE SIGNAL ;
    PORT
      LAYER M4 ;
        RECT  0 42.96 0.192 42.984 ;
    END
  END o[387]
  PIN o[388]
    DIRECTION OUTPUT ;
    USE SIGNAL ;
    PORT
      LAYER M4 ;
        RECT  0 43.056 0.192 43.08 ;
    END
  END o[388]
  PIN o[389]
    DIRECTION OUTPUT ;
    USE SIGNAL ;
    PORT
      LAYER M4 ;
        RECT  0 43.152 0.192 43.176 ;
    END
  END o[389]
  PIN o[38]
    DIRECTION OUTPUT ;
    USE SIGNAL ;
    PORT
      LAYER M4 ;
        RECT  0 6.24 0.192 6.264 ;
    END
  END o[38]
  PIN o[390]
    DIRECTION OUTPUT ;
    USE SIGNAL ;
    PORT
      LAYER M4 ;
        RECT  0 43.296 0.192 43.32 ;
    END
  END o[390]
  PIN o[391]
    DIRECTION OUTPUT ;
    USE SIGNAL ;
    PORT
      LAYER M4 ;
        RECT  0 43.392 0.192 43.416 ;
    END
  END o[391]
  PIN o[392]
    DIRECTION OUTPUT ;
    USE SIGNAL ;
    PORT
      LAYER M4 ;
        RECT  0 43.488 0.192 43.512 ;
    END
  END o[392]
  PIN o[393]
    DIRECTION OUTPUT ;
    USE SIGNAL ;
    PORT
      LAYER M4 ;
        RECT  0 43.584 0.192 43.608 ;
    END
  END o[393]
  PIN o[394]
    DIRECTION OUTPUT ;
    USE SIGNAL ;
    PORT
      LAYER M4 ;
        RECT  0 43.68 0.192 43.704 ;
    END
  END o[394]
  PIN o[395]
    DIRECTION OUTPUT ;
    USE SIGNAL ;
    PORT
      LAYER M4 ;
        RECT  0 43.824 0.192 43.848 ;
    END
  END o[395]
  PIN o[396]
    DIRECTION OUTPUT ;
    USE SIGNAL ;
    PORT
      LAYER M4 ;
        RECT  0 43.92 0.192 43.944 ;
    END
  END o[396]
  PIN o[397]
    DIRECTION OUTPUT ;
    USE SIGNAL ;
    PORT
      LAYER M4 ;
        RECT  0 44.016 0.192 44.04 ;
    END
  END o[397]
  PIN o[398]
    DIRECTION OUTPUT ;
    USE SIGNAL ;
    PORT
      LAYER M4 ;
        RECT  0 44.112 0.192 44.136 ;
    END
  END o[398]
  PIN o[399]
    DIRECTION OUTPUT ;
    USE SIGNAL ;
    PORT
      LAYER M4 ;
        RECT  0 44.208 0.192 44.232 ;
    END
  END o[399]
  PIN o[39]
    DIRECTION OUTPUT ;
    USE SIGNAL ;
    PORT
      LAYER M4 ;
        RECT  0 6.336 0.192 6.36 ;
    END
  END o[39]
  PIN o[3]
    DIRECTION OUTPUT ;
    USE SIGNAL ;
    PORT
      LAYER M4 ;
        RECT  0 2.544 0.192 2.568 ;
    END
  END o[3]
  PIN o[400]
    DIRECTION OUTPUT ;
    USE SIGNAL ;
    PORT
      LAYER M4 ;
        RECT  0 44.352 0.192 44.376 ;
    END
  END o[400]
  PIN o[401]
    DIRECTION OUTPUT ;
    USE SIGNAL ;
    PORT
      LAYER M4 ;
        RECT  0 44.448 0.192 44.472 ;
    END
  END o[401]
  PIN o[402]
    DIRECTION OUTPUT ;
    USE SIGNAL ;
    PORT
      LAYER M4 ;
        RECT  0 44.544 0.192 44.568 ;
    END
  END o[402]
  PIN o[403]
    DIRECTION OUTPUT ;
    USE SIGNAL ;
    PORT
      LAYER M4 ;
        RECT  0 44.64 0.192 44.664 ;
    END
  END o[403]
  PIN o[404]
    DIRECTION OUTPUT ;
    USE SIGNAL ;
    PORT
      LAYER M4 ;
        RECT  0 44.736 0.192 44.76 ;
    END
  END o[404]
  PIN o[405]
    DIRECTION OUTPUT ;
    USE SIGNAL ;
    PORT
      LAYER M4 ;
        RECT  0 44.88 0.192 44.904 ;
    END
  END o[405]
  PIN o[406]
    DIRECTION OUTPUT ;
    USE SIGNAL ;
    PORT
      LAYER M4 ;
        RECT  0 44.976 0.192 45 ;
    END
  END o[406]
  PIN o[407]
    DIRECTION OUTPUT ;
    USE SIGNAL ;
    PORT
      LAYER M4 ;
        RECT  0 45.072 0.192 45.096 ;
    END
  END o[407]
  PIN o[408]
    DIRECTION OUTPUT ;
    USE SIGNAL ;
    PORT
      LAYER M4 ;
        RECT  0 45.168 0.192 45.192 ;
    END
  END o[408]
  PIN o[409]
    DIRECTION OUTPUT ;
    USE SIGNAL ;
    PORT
      LAYER M4 ;
        RECT  0 45.264 0.192 45.288 ;
    END
  END o[409]
  PIN o[40]
    DIRECTION OUTPUT ;
    USE SIGNAL ;
    PORT
      LAYER M4 ;
        RECT  0 6.432 0.192 6.456 ;
    END
  END o[40]
  PIN o[410]
    DIRECTION OUTPUT ;
    USE SIGNAL ;
    PORT
      LAYER M4 ;
        RECT  0 45.36 0.192 45.384 ;
    END
  END o[410]
  PIN o[411]
    DIRECTION OUTPUT ;
    USE SIGNAL ;
    PORT
      LAYER M4 ;
        RECT  0 45.504 0.192 45.528 ;
    END
  END o[411]
  PIN o[412]
    DIRECTION OUTPUT ;
    USE SIGNAL ;
    PORT
      LAYER M4 ;
        RECT  0 45.6 0.192 45.624 ;
    END
  END o[412]
  PIN o[413]
    DIRECTION OUTPUT ;
    USE SIGNAL ;
    PORT
      LAYER M4 ;
        RECT  0 45.696 0.192 45.72 ;
    END
  END o[413]
  PIN o[414]
    DIRECTION OUTPUT ;
    USE SIGNAL ;
    PORT
      LAYER M4 ;
        RECT  0 45.792 0.192 45.816 ;
    END
  END o[414]
  PIN o[415]
    DIRECTION OUTPUT ;
    USE SIGNAL ;
    PORT
      LAYER M4 ;
        RECT  0 45.888 0.192 45.912 ;
    END
  END o[415]
  PIN o[416]
    DIRECTION OUTPUT ;
    USE SIGNAL ;
    PORT
      LAYER M4 ;
        RECT  0 46.032 0.192 46.056 ;
    END
  END o[416]
  PIN o[417]
    DIRECTION OUTPUT ;
    USE SIGNAL ;
    PORT
      LAYER M4 ;
        RECT  0 46.128 0.192 46.152 ;
    END
  END o[417]
  PIN o[418]
    DIRECTION OUTPUT ;
    USE SIGNAL ;
    PORT
      LAYER M4 ;
        RECT  0 46.224 0.192 46.248 ;
    END
  END o[418]
  PIN o[419]
    DIRECTION OUTPUT ;
    USE SIGNAL ;
    PORT
      LAYER M4 ;
        RECT  0 46.32 0.192 46.344 ;
    END
  END o[419]
  PIN o[41]
    DIRECTION OUTPUT ;
    USE SIGNAL ;
    PORT
      LAYER M4 ;
        RECT  0 6.528 0.192 6.552 ;
    END
  END o[41]
  PIN o[420]
    DIRECTION OUTPUT ;
    USE SIGNAL ;
    PORT
      LAYER M4 ;
        RECT  0 46.416 0.192 46.44 ;
    END
  END o[420]
  PIN o[421]
    DIRECTION OUTPUT ;
    USE SIGNAL ;
    PORT
      LAYER M4 ;
        RECT  0 46.56 0.192 46.584 ;
    END
  END o[421]
  PIN o[422]
    DIRECTION OUTPUT ;
    USE SIGNAL ;
    PORT
      LAYER M4 ;
        RECT  0 46.656 0.192 46.68 ;
    END
  END o[422]
  PIN o[423]
    DIRECTION OUTPUT ;
    USE SIGNAL ;
    PORT
      LAYER M4 ;
        RECT  0 46.752 0.192 46.776 ;
    END
  END o[423]
  PIN o[424]
    DIRECTION OUTPUT ;
    USE SIGNAL ;
    PORT
      LAYER M4 ;
        RECT  0 46.848 0.192 46.872 ;
    END
  END o[424]
  PIN o[425]
    DIRECTION OUTPUT ;
    USE SIGNAL ;
    PORT
      LAYER M4 ;
        RECT  0 46.944 0.192 46.968 ;
    END
  END o[425]
  PIN o[426]
    DIRECTION OUTPUT ;
    USE SIGNAL ;
    PORT
      LAYER M4 ;
        RECT  0 47.088 0.192 47.112 ;
    END
  END o[426]
  PIN o[427]
    DIRECTION OUTPUT ;
    USE SIGNAL ;
    PORT
      LAYER M4 ;
        RECT  0 47.184 0.192 47.208 ;
    END
  END o[427]
  PIN o[428]
    DIRECTION OUTPUT ;
    USE SIGNAL ;
    PORT
      LAYER M4 ;
        RECT  0 47.28 0.192 47.304 ;
    END
  END o[428]
  PIN o[429]
    DIRECTION OUTPUT ;
    USE SIGNAL ;
    PORT
      LAYER M4 ;
        RECT  0 47.376 0.192 47.4 ;
    END
  END o[429]
  PIN o[42]
    DIRECTION OUTPUT ;
    USE SIGNAL ;
    PORT
      LAYER M4 ;
        RECT  0 6.624 0.192 6.648 ;
    END
  END o[42]
  PIN o[430]
    DIRECTION OUTPUT ;
    USE SIGNAL ;
    PORT
      LAYER M4 ;
        RECT  0 47.472 0.192 47.496 ;
    END
  END o[430]
  PIN o[431]
    DIRECTION OUTPUT ;
    USE SIGNAL ;
    PORT
      LAYER M4 ;
        RECT  0 47.616 0.192 47.64 ;
    END
  END o[431]
  PIN o[432]
    DIRECTION OUTPUT ;
    USE SIGNAL ;
    PORT
      LAYER M4 ;
        RECT  0 47.712 0.192 47.736 ;
    END
  END o[432]
  PIN o[433]
    DIRECTION OUTPUT ;
    USE SIGNAL ;
    PORT
      LAYER M4 ;
        RECT  0 47.808 0.192 47.832 ;
    END
  END o[433]
  PIN o[434]
    DIRECTION OUTPUT ;
    USE SIGNAL ;
    PORT
      LAYER M4 ;
        RECT  0 47.904 0.192 47.928 ;
    END
  END o[434]
  PIN o[435]
    DIRECTION OUTPUT ;
    USE SIGNAL ;
    PORT
      LAYER M4 ;
        RECT  0 48 0.192 48.024 ;
    END
  END o[435]
  PIN o[436]
    DIRECTION OUTPUT ;
    USE SIGNAL ;
    PORT
      LAYER M4 ;
        RECT  0 48.096 0.192 48.12 ;
    END
  END o[436]
  PIN o[437]
    DIRECTION OUTPUT ;
    USE SIGNAL ;
    PORT
      LAYER M4 ;
        RECT  0 48.24 0.192 48.264 ;
    END
  END o[437]
  PIN o[438]
    DIRECTION OUTPUT ;
    USE SIGNAL ;
    PORT
      LAYER M4 ;
        RECT  0 48.336 0.192 48.36 ;
    END
  END o[438]
  PIN o[439]
    DIRECTION OUTPUT ;
    USE SIGNAL ;
    PORT
      LAYER M4 ;
        RECT  0 48.432 0.192 48.456 ;
    END
  END o[439]
  PIN o[43]
    DIRECTION OUTPUT ;
    USE SIGNAL ;
    PORT
      LAYER M4 ;
        RECT  0 6.768 0.192 6.792 ;
    END
  END o[43]
  PIN o[440]
    DIRECTION OUTPUT ;
    USE SIGNAL ;
    PORT
      LAYER M4 ;
        RECT  0 48.528 0.192 48.552 ;
    END
  END o[440]
  PIN o[441]
    DIRECTION OUTPUT ;
    USE SIGNAL ;
    PORT
      LAYER M4 ;
        RECT  0 48.624 0.192 48.648 ;
    END
  END o[441]
  PIN o[442]
    DIRECTION OUTPUT ;
    USE SIGNAL ;
    PORT
      LAYER M4 ;
        RECT  0 48.768 0.192 48.792 ;
    END
  END o[442]
  PIN o[443]
    DIRECTION OUTPUT ;
    USE SIGNAL ;
    PORT
      LAYER M4 ;
        RECT  0 48.864 0.192 48.888 ;
    END
  END o[443]
  PIN o[444]
    DIRECTION OUTPUT ;
    USE SIGNAL ;
    PORT
      LAYER M4 ;
        RECT  0 48.96 0.192 48.984 ;
    END
  END o[444]
  PIN o[445]
    DIRECTION OUTPUT ;
    USE SIGNAL ;
    PORT
      LAYER M4 ;
        RECT  0 49.056 0.192 49.08 ;
    END
  END o[445]
  PIN o[446]
    DIRECTION OUTPUT ;
    USE SIGNAL ;
    PORT
      LAYER M4 ;
        RECT  0 49.152 0.192 49.176 ;
    END
  END o[446]
  PIN o[447]
    DIRECTION OUTPUT ;
    USE SIGNAL ;
    PORT
      LAYER M4 ;
        RECT  0 49.296 0.192 49.32 ;
    END
  END o[447]
  PIN o[448]
    DIRECTION OUTPUT ;
    USE SIGNAL ;
    PORT
      LAYER M4 ;
        RECT  0 49.392 0.192 49.416 ;
    END
  END o[448]
  PIN o[449]
    DIRECTION OUTPUT ;
    USE SIGNAL ;
    PORT
      LAYER M4 ;
        RECT  0 49.488 0.192 49.512 ;
    END
  END o[449]
  PIN o[44]
    DIRECTION OUTPUT ;
    USE SIGNAL ;
    PORT
      LAYER M4 ;
        RECT  0 6.864 0.192 6.888 ;
    END
  END o[44]
  PIN o[450]
    DIRECTION OUTPUT ;
    USE SIGNAL ;
    PORT
      LAYER M4 ;
        RECT  0 49.584 0.192 49.608 ;
    END
  END o[450]
  PIN o[451]
    DIRECTION OUTPUT ;
    USE SIGNAL ;
    PORT
      LAYER M4 ;
        RECT  0 49.68 0.192 49.704 ;
    END
  END o[451]
  PIN o[452]
    DIRECTION OUTPUT ;
    USE SIGNAL ;
    PORT
      LAYER M4 ;
        RECT  0 49.824 0.192 49.848 ;
    END
  END o[452]
  PIN o[453]
    DIRECTION OUTPUT ;
    USE SIGNAL ;
    PORT
      LAYER M4 ;
        RECT  0 49.92 0.192 49.944 ;
    END
  END o[453]
  PIN o[454]
    DIRECTION OUTPUT ;
    USE SIGNAL ;
    PORT
      LAYER M4 ;
        RECT  0 50.016 0.192 50.04 ;
    END
  END o[454]
  PIN o[455]
    DIRECTION OUTPUT ;
    USE SIGNAL ;
    PORT
      LAYER M4 ;
        RECT  0 50.112 0.192 50.136 ;
    END
  END o[455]
  PIN o[456]
    DIRECTION OUTPUT ;
    USE SIGNAL ;
    PORT
      LAYER M4 ;
        RECT  0 50.208 0.192 50.232 ;
    END
  END o[456]
  PIN o[457]
    DIRECTION OUTPUT ;
    USE SIGNAL ;
    PORT
      LAYER M4 ;
        RECT  0 50.352 0.192 50.376 ;
    END
  END o[457]
  PIN o[458]
    DIRECTION OUTPUT ;
    USE SIGNAL ;
    PORT
      LAYER M4 ;
        RECT  0 50.448 0.192 50.472 ;
    END
  END o[458]
  PIN o[459]
    DIRECTION OUTPUT ;
    USE SIGNAL ;
    PORT
      LAYER M4 ;
        RECT  0 50.544 0.192 50.568 ;
    END
  END o[459]
  PIN o[45]
    DIRECTION OUTPUT ;
    USE SIGNAL ;
    PORT
      LAYER M4 ;
        RECT  0 6.96 0.192 6.984 ;
    END
  END o[45]
  PIN o[460]
    DIRECTION OUTPUT ;
    USE SIGNAL ;
    PORT
      LAYER M4 ;
        RECT  0 50.64 0.192 50.664 ;
    END
  END o[460]
  PIN o[461]
    DIRECTION OUTPUT ;
    USE SIGNAL ;
    PORT
      LAYER M4 ;
        RECT  0 50.736 0.192 50.76 ;
    END
  END o[461]
  PIN o[462]
    DIRECTION OUTPUT ;
    USE SIGNAL ;
    PORT
      LAYER M4 ;
        RECT  0 50.88 0.192 50.904 ;
    END
  END o[462]
  PIN o[463]
    DIRECTION OUTPUT ;
    USE SIGNAL ;
    PORT
      LAYER M4 ;
        RECT  0 50.976 0.192 51 ;
    END
  END o[463]
  PIN o[464]
    DIRECTION OUTPUT ;
    USE SIGNAL ;
    PORT
      LAYER M4 ;
        RECT  0 51.072 0.192 51.096 ;
    END
  END o[464]
  PIN o[465]
    DIRECTION OUTPUT ;
    USE SIGNAL ;
    PORT
      LAYER M4 ;
        RECT  0 51.168 0.192 51.192 ;
    END
  END o[465]
  PIN o[466]
    DIRECTION OUTPUT ;
    USE SIGNAL ;
    PORT
      LAYER M4 ;
        RECT  0 51.264 0.192 51.288 ;
    END
  END o[466]
  PIN o[467]
    DIRECTION OUTPUT ;
    USE SIGNAL ;
    PORT
      LAYER M4 ;
        RECT  0 51.36 0.192 51.384 ;
    END
  END o[467]
  PIN o[468]
    DIRECTION OUTPUT ;
    USE SIGNAL ;
    PORT
      LAYER M4 ;
        RECT  0 51.504 0.192 51.528 ;
    END
  END o[468]
  PIN o[469]
    DIRECTION OUTPUT ;
    USE SIGNAL ;
    PORT
      LAYER M4 ;
        RECT  0 51.6 0.192 51.624 ;
    END
  END o[469]
  PIN o[46]
    DIRECTION OUTPUT ;
    USE SIGNAL ;
    PORT
      LAYER M4 ;
        RECT  0 7.056 0.192 7.08 ;
    END
  END o[46]
  PIN o[470]
    DIRECTION OUTPUT ;
    USE SIGNAL ;
    PORT
      LAYER M4 ;
        RECT  0 51.696 0.192 51.72 ;
    END
  END o[470]
  PIN o[471]
    DIRECTION OUTPUT ;
    USE SIGNAL ;
    PORT
      LAYER M4 ;
        RECT  0 51.792 0.192 51.816 ;
    END
  END o[471]
  PIN o[472]
    DIRECTION OUTPUT ;
    USE SIGNAL ;
    PORT
      LAYER M4 ;
        RECT  0 51.888 0.192 51.912 ;
    END
  END o[472]
  PIN o[473]
    DIRECTION OUTPUT ;
    USE SIGNAL ;
    PORT
      LAYER M4 ;
        RECT  0 52.032 0.192 52.056 ;
    END
  END o[473]
  PIN o[474]
    DIRECTION OUTPUT ;
    USE SIGNAL ;
    PORT
      LAYER M4 ;
        RECT  0 52.128 0.192 52.152 ;
    END
  END o[474]
  PIN o[475]
    DIRECTION OUTPUT ;
    USE SIGNAL ;
    PORT
      LAYER M4 ;
        RECT  0 52.224 0.192 52.248 ;
    END
  END o[475]
  PIN o[476]
    DIRECTION OUTPUT ;
    USE SIGNAL ;
    PORT
      LAYER M4 ;
        RECT  0 52.32 0.192 52.344 ;
    END
  END o[476]
  PIN o[477]
    DIRECTION OUTPUT ;
    USE SIGNAL ;
    PORT
      LAYER M4 ;
        RECT  0 52.416 0.192 52.44 ;
    END
  END o[477]
  PIN o[478]
    DIRECTION OUTPUT ;
    USE SIGNAL ;
    PORT
      LAYER M4 ;
        RECT  0 52.56 0.192 52.584 ;
    END
  END o[478]
  PIN o[479]
    DIRECTION OUTPUT ;
    USE SIGNAL ;
    PORT
      LAYER M4 ;
        RECT  0 52.656 0.192 52.68 ;
    END
  END o[479]
  PIN o[47]
    DIRECTION OUTPUT ;
    USE SIGNAL ;
    PORT
      LAYER M4 ;
        RECT  0 7.152 0.192 7.176 ;
    END
  END o[47]
  PIN o[480]
    DIRECTION OUTPUT ;
    USE SIGNAL ;
    PORT
      LAYER M4 ;
        RECT  0 52.752 0.192 52.776 ;
    END
  END o[480]
  PIN o[481]
    DIRECTION OUTPUT ;
    USE SIGNAL ;
    PORT
      LAYER M4 ;
        RECT  0 52.848 0.192 52.872 ;
    END
  END o[481]
  PIN o[482]
    DIRECTION OUTPUT ;
    USE SIGNAL ;
    PORT
      LAYER M4 ;
        RECT  0 52.944 0.192 52.968 ;
    END
  END o[482]
  PIN o[483]
    DIRECTION OUTPUT ;
    USE SIGNAL ;
    PORT
      LAYER M4 ;
        RECT  0 53.088 0.192 53.112 ;
    END
  END o[483]
  PIN o[484]
    DIRECTION OUTPUT ;
    USE SIGNAL ;
    PORT
      LAYER M4 ;
        RECT  0 53.184 0.192 53.208 ;
    END
  END o[484]
  PIN o[485]
    DIRECTION OUTPUT ;
    USE SIGNAL ;
    PORT
      LAYER M4 ;
        RECT  0 53.28 0.192 53.304 ;
    END
  END o[485]
  PIN o[486]
    DIRECTION OUTPUT ;
    USE SIGNAL ;
    PORT
      LAYER M4 ;
        RECT  0 53.376 0.192 53.4 ;
    END
  END o[486]
  PIN o[487]
    DIRECTION OUTPUT ;
    USE SIGNAL ;
    PORT
      LAYER M4 ;
        RECT  0 53.472 0.192 53.496 ;
    END
  END o[487]
  PIN o[488]
    DIRECTION OUTPUT ;
    USE SIGNAL ;
    PORT
      LAYER M4 ;
        RECT  0 53.616 0.192 53.64 ;
    END
  END o[488]
  PIN o[489]
    DIRECTION OUTPUT ;
    USE SIGNAL ;
    PORT
      LAYER M4 ;
        RECT  0 53.712 0.192 53.736 ;
    END
  END o[489]
  PIN o[48]
    DIRECTION OUTPUT ;
    USE SIGNAL ;
    PORT
      LAYER M4 ;
        RECT  0 7.296 0.192 7.32 ;
    END
  END o[48]
  PIN o[490]
    DIRECTION OUTPUT ;
    USE SIGNAL ;
    PORT
      LAYER M4 ;
        RECT  0 53.808 0.192 53.832 ;
    END
  END o[490]
  PIN o[491]
    DIRECTION OUTPUT ;
    USE SIGNAL ;
    PORT
      LAYER M4 ;
        RECT  0 53.904 0.192 53.928 ;
    END
  END o[491]
  PIN o[492]
    DIRECTION OUTPUT ;
    USE SIGNAL ;
    PORT
      LAYER M4 ;
        RECT  0 54 0.192 54.024 ;
    END
  END o[492]
  PIN o[493]
    DIRECTION OUTPUT ;
    USE SIGNAL ;
    PORT
      LAYER M4 ;
        RECT  0 54.096 0.192 54.12 ;
    END
  END o[493]
  PIN o[494]
    DIRECTION OUTPUT ;
    USE SIGNAL ;
    PORT
      LAYER M4 ;
        RECT  0 54.24 0.192 54.264 ;
    END
  END o[494]
  PIN o[495]
    DIRECTION OUTPUT ;
    USE SIGNAL ;
    PORT
      LAYER M4 ;
        RECT  0 54.336 0.192 54.36 ;
    END
  END o[495]
  PIN o[496]
    DIRECTION OUTPUT ;
    USE SIGNAL ;
    PORT
      LAYER M4 ;
        RECT  0 54.432 0.192 54.456 ;
    END
  END o[496]
  PIN o[497]
    DIRECTION OUTPUT ;
    USE SIGNAL ;
    PORT
      LAYER M4 ;
        RECT  0 54.528 0.192 54.552 ;
    END
  END o[497]
  PIN o[498]
    DIRECTION OUTPUT ;
    USE SIGNAL ;
    PORT
      LAYER M4 ;
        RECT  0 54.624 0.192 54.648 ;
    END
  END o[498]
  PIN o[499]
    DIRECTION OUTPUT ;
    USE SIGNAL ;
    PORT
      LAYER M4 ;
        RECT  0 54.768 0.192 54.792 ;
    END
  END o[499]
  PIN o[49]
    DIRECTION OUTPUT ;
    USE SIGNAL ;
    PORT
      LAYER M4 ;
        RECT  0 7.392 0.192 7.416 ;
    END
  END o[49]
  PIN o[4]
    DIRECTION OUTPUT ;
    USE SIGNAL ;
    PORT
      LAYER M4 ;
        RECT  0 2.64 0.192 2.664 ;
    END
  END o[4]
  PIN o[500]
    DIRECTION OUTPUT ;
    USE SIGNAL ;
    PORT
      LAYER M4 ;
        RECT  0 54.864 0.192 54.888 ;
    END
  END o[500]
  PIN o[501]
    DIRECTION OUTPUT ;
    USE SIGNAL ;
    PORT
      LAYER M4 ;
        RECT  0 54.96 0.192 54.984 ;
    END
  END o[501]
  PIN o[502]
    DIRECTION OUTPUT ;
    USE SIGNAL ;
    PORT
      LAYER M4 ;
        RECT  0 55.056 0.192 55.08 ;
    END
  END o[502]
  PIN o[503]
    DIRECTION OUTPUT ;
    USE SIGNAL ;
    PORT
      LAYER M4 ;
        RECT  0 55.152 0.192 55.176 ;
    END
  END o[503]
  PIN o[504]
    DIRECTION OUTPUT ;
    USE SIGNAL ;
    PORT
      LAYER M4 ;
        RECT  0 55.296 0.192 55.32 ;
    END
  END o[504]
  PIN o[505]
    DIRECTION OUTPUT ;
    USE SIGNAL ;
    PORT
      LAYER M4 ;
        RECT  0 55.392 0.192 55.416 ;
    END
  END o[505]
  PIN o[506]
    DIRECTION OUTPUT ;
    USE SIGNAL ;
    PORT
      LAYER M4 ;
        RECT  0 55.488 0.192 55.512 ;
    END
  END o[506]
  PIN o[507]
    DIRECTION OUTPUT ;
    USE SIGNAL ;
    PORT
      LAYER M4 ;
        RECT  0 55.584 0.192 55.608 ;
    END
  END o[507]
  PIN o[508]
    DIRECTION OUTPUT ;
    USE SIGNAL ;
    PORT
      LAYER M4 ;
        RECT  0 55.68 0.192 55.704 ;
    END
  END o[508]
  PIN o[509]
    DIRECTION OUTPUT ;
    USE SIGNAL ;
    PORT
      LAYER M4 ;
        RECT  0 55.824 0.192 55.848 ;
    END
  END o[509]
  PIN o[50]
    DIRECTION OUTPUT ;
    USE SIGNAL ;
    PORT
      LAYER M4 ;
        RECT  0 7.488 0.192 7.512 ;
    END
  END o[50]
  PIN o[510]
    DIRECTION OUTPUT ;
    USE SIGNAL ;
    PORT
      LAYER M4 ;
        RECT  0 55.92 0.192 55.944 ;
    END
  END o[510]
  PIN o[511]
    DIRECTION OUTPUT ;
    USE SIGNAL ;
    PORT
      LAYER M4 ;
        RECT  0 56.016 0.192 56.04 ;
    END
  END o[511]
  PIN o[51]
    DIRECTION OUTPUT ;
    USE SIGNAL ;
    PORT
      LAYER M4 ;
        RECT  0 7.584 0.192 7.608 ;
    END
  END o[51]
  PIN o[52]
    DIRECTION OUTPUT ;
    USE SIGNAL ;
    PORT
      LAYER M4 ;
        RECT  0 7.68 0.192 7.704 ;
    END
  END o[52]
  PIN o[53]
    DIRECTION OUTPUT ;
    USE SIGNAL ;
    PORT
      LAYER M4 ;
        RECT  0 7.824 0.192 7.848 ;
    END
  END o[53]
  PIN o[54]
    DIRECTION OUTPUT ;
    USE SIGNAL ;
    PORT
      LAYER M4 ;
        RECT  0 7.92 0.192 7.944 ;
    END
  END o[54]
  PIN o[55]
    DIRECTION OUTPUT ;
    USE SIGNAL ;
    PORT
      LAYER M4 ;
        RECT  0 8.016 0.192 8.04 ;
    END
  END o[55]
  PIN o[56]
    DIRECTION OUTPUT ;
    USE SIGNAL ;
    PORT
      LAYER M4 ;
        RECT  0 8.112 0.192 8.136 ;
    END
  END o[56]
  PIN o[57]
    DIRECTION OUTPUT ;
    USE SIGNAL ;
    PORT
      LAYER M4 ;
        RECT  0 8.208 0.192 8.232 ;
    END
  END o[57]
  PIN o[58]
    DIRECTION OUTPUT ;
    USE SIGNAL ;
    PORT
      LAYER M4 ;
        RECT  0 8.352 0.192 8.376 ;
    END
  END o[58]
  PIN o[59]
    DIRECTION OUTPUT ;
    USE SIGNAL ;
    PORT
      LAYER M4 ;
        RECT  0 8.448 0.192 8.472 ;
    END
  END o[59]
  PIN o[5]
    DIRECTION OUTPUT ;
    USE SIGNAL ;
    PORT
      LAYER M4 ;
        RECT  0 2.736 0.192 2.76 ;
    END
  END o[5]
  PIN o[60]
    DIRECTION OUTPUT ;
    USE SIGNAL ;
    PORT
      LAYER M4 ;
        RECT  0 8.544 0.192 8.568 ;
    END
  END o[60]
  PIN o[61]
    DIRECTION OUTPUT ;
    USE SIGNAL ;
    PORT
      LAYER M4 ;
        RECT  0 8.64 0.192 8.664 ;
    END
  END o[61]
  PIN o[62]
    DIRECTION OUTPUT ;
    USE SIGNAL ;
    PORT
      LAYER M4 ;
        RECT  0 8.736 0.192 8.76 ;
    END
  END o[62]
  PIN o[63]
    DIRECTION OUTPUT ;
    USE SIGNAL ;
    PORT
      LAYER M4 ;
        RECT  0 8.88 0.192 8.904 ;
    END
  END o[63]
  PIN o[64]
    DIRECTION OUTPUT ;
    USE SIGNAL ;
    PORT
      LAYER M4 ;
        RECT  0 8.976 0.192 9 ;
    END
  END o[64]
  PIN o[65]
    DIRECTION OUTPUT ;
    USE SIGNAL ;
    PORT
      LAYER M4 ;
        RECT  0 9.072 0.192 9.096 ;
    END
  END o[65]
  PIN o[66]
    DIRECTION OUTPUT ;
    USE SIGNAL ;
    PORT
      LAYER M4 ;
        RECT  0 9.168 0.192 9.192 ;
    END
  END o[66]
  PIN o[67]
    DIRECTION OUTPUT ;
    USE SIGNAL ;
    PORT
      LAYER M4 ;
        RECT  0 9.264 0.192 9.288 ;
    END
  END o[67]
  PIN o[68]
    DIRECTION OUTPUT ;
    USE SIGNAL ;
    PORT
      LAYER M4 ;
        RECT  0 9.36 0.192 9.384 ;
    END
  END o[68]
  PIN o[69]
    DIRECTION OUTPUT ;
    USE SIGNAL ;
    PORT
      LAYER M4 ;
        RECT  0 9.504 0.192 9.528 ;
    END
  END o[69]
  PIN o[6]
    DIRECTION OUTPUT ;
    USE SIGNAL ;
    PORT
      LAYER M4 ;
        RECT  0 2.88 0.192 2.904 ;
    END
  END o[6]
  PIN o[70]
    DIRECTION OUTPUT ;
    USE SIGNAL ;
    PORT
      LAYER M4 ;
        RECT  0 9.6 0.192 9.624 ;
    END
  END o[70]
  PIN o[71]
    DIRECTION OUTPUT ;
    USE SIGNAL ;
    PORT
      LAYER M4 ;
        RECT  0 9.696 0.192 9.72 ;
    END
  END o[71]
  PIN o[72]
    DIRECTION OUTPUT ;
    USE SIGNAL ;
    PORT
      LAYER M4 ;
        RECT  0 9.792 0.192 9.816 ;
    END
  END o[72]
  PIN o[73]
    DIRECTION OUTPUT ;
    USE SIGNAL ;
    PORT
      LAYER M4 ;
        RECT  0 9.888 0.192 9.912 ;
    END
  END o[73]
  PIN o[74]
    DIRECTION OUTPUT ;
    USE SIGNAL ;
    PORT
      LAYER M4 ;
        RECT  0 10.032 0.192 10.056 ;
    END
  END o[74]
  PIN o[75]
    DIRECTION OUTPUT ;
    USE SIGNAL ;
    PORT
      LAYER M4 ;
        RECT  0 10.128 0.192 10.152 ;
    END
  END o[75]
  PIN o[76]
    DIRECTION OUTPUT ;
    USE SIGNAL ;
    PORT
      LAYER M4 ;
        RECT  0 10.224 0.192 10.248 ;
    END
  END o[76]
  PIN o[77]
    DIRECTION OUTPUT ;
    USE SIGNAL ;
    PORT
      LAYER M4 ;
        RECT  0 10.32 0.192 10.344 ;
    END
  END o[77]
  PIN o[78]
    DIRECTION OUTPUT ;
    USE SIGNAL ;
    PORT
      LAYER M4 ;
        RECT  0 10.416 0.192 10.44 ;
    END
  END o[78]
  PIN o[79]
    DIRECTION OUTPUT ;
    USE SIGNAL ;
    PORT
      LAYER M4 ;
        RECT  0 10.56 0.192 10.584 ;
    END
  END o[79]
  PIN o[7]
    DIRECTION OUTPUT ;
    USE SIGNAL ;
    PORT
      LAYER M4 ;
        RECT  0 2.976 0.192 3 ;
    END
  END o[7]
  PIN o[80]
    DIRECTION OUTPUT ;
    USE SIGNAL ;
    PORT
      LAYER M4 ;
        RECT  0 10.656 0.192 10.68 ;
    END
  END o[80]
  PIN o[81]
    DIRECTION OUTPUT ;
    USE SIGNAL ;
    PORT
      LAYER M4 ;
        RECT  0 10.752 0.192 10.776 ;
    END
  END o[81]
  PIN o[82]
    DIRECTION OUTPUT ;
    USE SIGNAL ;
    PORT
      LAYER M4 ;
        RECT  0 10.848 0.192 10.872 ;
    END
  END o[82]
  PIN o[83]
    DIRECTION OUTPUT ;
    USE SIGNAL ;
    PORT
      LAYER M4 ;
        RECT  0 10.944 0.192 10.968 ;
    END
  END o[83]
  PIN o[84]
    DIRECTION OUTPUT ;
    USE SIGNAL ;
    PORT
      LAYER M4 ;
        RECT  0 11.088 0.192 11.112 ;
    END
  END o[84]
  PIN o[85]
    DIRECTION OUTPUT ;
    USE SIGNAL ;
    PORT
      LAYER M4 ;
        RECT  0 11.184 0.192 11.208 ;
    END
  END o[85]
  PIN o[86]
    DIRECTION OUTPUT ;
    USE SIGNAL ;
    PORT
      LAYER M4 ;
        RECT  0 11.28 0.192 11.304 ;
    END
  END o[86]
  PIN o[87]
    DIRECTION OUTPUT ;
    USE SIGNAL ;
    PORT
      LAYER M4 ;
        RECT  0 11.376 0.192 11.4 ;
    END
  END o[87]
  PIN o[88]
    DIRECTION OUTPUT ;
    USE SIGNAL ;
    PORT
      LAYER M4 ;
        RECT  0 11.472 0.192 11.496 ;
    END
  END o[88]
  PIN o[89]
    DIRECTION OUTPUT ;
    USE SIGNAL ;
    PORT
      LAYER M4 ;
        RECT  0 11.616 0.192 11.64 ;
    END
  END o[89]
  PIN o[8]
    DIRECTION OUTPUT ;
    USE SIGNAL ;
    PORT
      LAYER M4 ;
        RECT  0 3.072 0.192 3.096 ;
    END
  END o[8]
  PIN o[90]
    DIRECTION OUTPUT ;
    USE SIGNAL ;
    PORT
      LAYER M4 ;
        RECT  0 11.712 0.192 11.736 ;
    END
  END o[90]
  PIN o[91]
    DIRECTION OUTPUT ;
    USE SIGNAL ;
    PORT
      LAYER M4 ;
        RECT  0 11.808 0.192 11.832 ;
    END
  END o[91]
  PIN o[92]
    DIRECTION OUTPUT ;
    USE SIGNAL ;
    PORT
      LAYER M4 ;
        RECT  0 11.904 0.192 11.928 ;
    END
  END o[92]
  PIN o[93]
    DIRECTION OUTPUT ;
    USE SIGNAL ;
    PORT
      LAYER M4 ;
        RECT  0 12 0.192 12.024 ;
    END
  END o[93]
  PIN o[94]
    DIRECTION OUTPUT ;
    USE SIGNAL ;
    PORT
      LAYER M4 ;
        RECT  0 12.096 0.192 12.12 ;
    END
  END o[94]
  PIN o[95]
    DIRECTION OUTPUT ;
    USE SIGNAL ;
    PORT
      LAYER M4 ;
        RECT  0 12.24 0.192 12.264 ;
    END
  END o[95]
  PIN o[96]
    DIRECTION OUTPUT ;
    USE SIGNAL ;
    PORT
      LAYER M4 ;
        RECT  0 12.336 0.192 12.36 ;
    END
  END o[96]
  PIN o[97]
    DIRECTION OUTPUT ;
    USE SIGNAL ;
    PORT
      LAYER M4 ;
        RECT  0 12.432 0.192 12.456 ;
    END
  END o[97]
  PIN o[98]
    DIRECTION OUTPUT ;
    USE SIGNAL ;
    PORT
      LAYER M4 ;
        RECT  0 12.528 0.192 12.552 ;
    END
  END o[98]
  PIN o[99]
    DIRECTION OUTPUT ;
    USE SIGNAL ;
    PORT
      LAYER M4 ;
        RECT  0 12.624 0.192 12.648 ;
    END
  END o[99]
  PIN o[9]
    DIRECTION OUTPUT ;
    USE SIGNAL ;
    PORT
      LAYER M4 ;
        RECT  0 3.168 0.192 3.192 ;
    END
  END o[9]
  PIN rs
    DIRECTION INPUT ;
    USE SIGNAL ;
    PORT
      LAYER M5 ;
        RECT  11.856 58.128 11.88 58.32 ;
    END
    PORT
      LAYER M5 ;
        RECT  11.424 58.069 11.88 58.192 ;
    END
  END rs
  PIN VDD
    DIRECTION INOUT ;
    USE POWER ;
    PORT
      LAYER M5 ;
        RECT  13.392 2.151 13.512 56.169 ;
        RECT  10.692 2.151 10.812 56.169 ;
        RECT  7.992 2.151 8.112 56.169 ;
        RECT  5.292 2.151 5.412 56.169 ;
        RECT  2.592 2.151 2.712 56.169 ;
    END
  END VDD
  PIN VSS
    DIRECTION INOUT ;
    USE GROUND ;
    PORT
      LAYER M5 ;
        RECT  13.2 2.137 13.32 56.183 ;
        RECT  10.5 2.137 10.62 56.183 ;
        RECT  7.8 2.137 7.92 56.183 ;
        RECT  5.1 2.137 5.22 56.183 ;
        RECT  2.4 2.137 2.52 56.183 ;
    END
  END VSS
  # OT_OBS_CLOSED layer=M5 d_um=1.536 added=59
  OBS
    LAYER RVTN ;
     RECT  2.16 2.16 15.12 2.295 ;
     RECT  2.16 2.565 15.12 2.835 ;
     RECT  2.16 3.105 15.12 3.375 ;
     RECT  2.16 3.645 15.12 3.915 ;
     RECT  2.16 4.185 15.12 4.455 ;
     RECT  2.16 4.725 15.12 4.995 ;
     RECT  2.16 5.265 15.12 5.535 ;
     RECT  2.16 5.805 15.12 6.075 ;
     RECT  2.16 6.345 15.12 6.615 ;
     RECT  2.16 6.885 15.12 7.155 ;
     RECT  2.16 7.425 15.12 7.695 ;
     RECT  2.16 7.965 15.12 8.235 ;
     RECT  2.16 8.505 15.12 8.775 ;
     RECT  2.16 9.045 15.12 9.315 ;
     RECT  2.16 9.585 15.12 9.855 ;
     RECT  2.16 10.125 15.12 10.395 ;
     RECT  2.16 10.665 15.12 10.935 ;
     RECT  2.16 11.205 15.12 11.475 ;
     RECT  2.16 11.745 15.12 12.015 ;
     RECT  2.16 12.285 15.12 12.555 ;
     RECT  2.16 12.825 15.12 13.095 ;
     RECT  2.16 13.365 15.12 13.635 ;
     RECT  2.16 13.905 15.12 14.175 ;
     RECT  2.16 14.445 15.12 14.715 ;
     RECT  2.16 14.985 15.12 15.255 ;
     RECT  2.16 15.525 15.12 15.795 ;
     RECT  2.16 16.065 15.12 16.335 ;
     RECT  2.16 16.605 15.12 16.875 ;
     RECT  2.16 17.145 15.12 17.415 ;
     RECT  2.16 17.685 15.12 17.955 ;
     RECT  2.16 18.225 15.12 18.495 ;
     RECT  2.16 18.765 15.12 19.035 ;
     RECT  2.16 19.305 15.12 19.575 ;
     RECT  2.16 19.845 15.12 20.115 ;
     RECT  2.16 20.385 15.12 20.655 ;
     RECT  2.16 20.925 15.12 21.195 ;
     RECT  2.16 21.465 15.12 21.735 ;
     RECT  2.16 22.005 15.12 22.275 ;
     RECT  2.16 22.545 15.12 22.815 ;
     RECT  2.16 23.085 15.12 23.355 ;
     RECT  2.16 23.625 15.12 23.895 ;
     RECT  2.16 24.165 15.12 24.435 ;
     RECT  2.16 24.705 15.12 24.975 ;
     RECT  2.16 25.245 15.12 25.515 ;
     RECT  2.16 25.785 15.12 26.055 ;
     RECT  2.16 26.325 15.12 26.595 ;
     RECT  2.16 26.865 15.12 27.135 ;
     RECT  2.16 27.405 15.12 27.675 ;
     RECT  2.16 27.945 15.12 28.215 ;
     RECT  2.16 28.485 15.12 28.755 ;
     RECT  2.16 29.025 15.12 29.295 ;
     RECT  2.16 29.565 15.12 29.835 ;
     RECT  2.16 30.105 15.12 30.375 ;
     RECT  2.16 30.645 15.12 30.915 ;
     RECT  2.16 31.185 15.12 31.455 ;
     RECT  2.16 31.725 15.12 31.995 ;
     RECT  2.16 32.265 15.12 32.535 ;
     RECT  2.16 32.805 15.12 33.075 ;
     RECT  2.16 33.345 15.12 33.615 ;
     RECT  2.16 33.885 15.12 34.155 ;
     RECT  2.16 34.425 15.12 34.695 ;
     RECT  2.16 34.965 15.12 35.235 ;
     RECT  2.16 35.505 15.12 35.775 ;
     RECT  2.16 36.045 15.12 36.315 ;
     RECT  2.16 36.585 15.12 36.855 ;
     RECT  2.16 37.125 15.12 37.395 ;
     RECT  2.16 37.665 15.12 37.935 ;
     RECT  2.16 38.205 15.12 38.475 ;
     RECT  2.16 38.745 15.12 39.015 ;
     RECT  2.16 39.285 15.12 39.555 ;
     RECT  2.16 39.825 15.12 40.095 ;
     RECT  2.16 40.365 15.12 40.635 ;
     RECT  2.16 40.905 15.12 41.175 ;
     RECT  2.16 41.445 15.12 41.715 ;
     RECT  2.16 41.985 15.12 42.255 ;
     RECT  2.16 42.525 15.12 42.795 ;
     RECT  2.16 43.065 15.12 43.335 ;
     RECT  2.16 43.605 15.12 43.875 ;
     RECT  2.16 44.145 15.12 44.415 ;
     RECT  2.16 44.685 15.12 44.955 ;
     RECT  2.16 45.225 15.12 45.495 ;
     RECT  2.16 45.765 15.12 46.035 ;
     RECT  2.16 46.305 15.12 46.575 ;
     RECT  2.16 46.845 15.12 47.115 ;
     RECT  2.16 47.385 15.12 47.655 ;
     RECT  2.16 47.925 15.12 48.195 ;
     RECT  2.16 48.465 15.12 48.735 ;
     RECT  2.16 49.005 15.12 49.275 ;
     RECT  2.16 49.545 15.12 49.815 ;
     RECT  2.16 50.085 15.12 50.355 ;
     RECT  2.16 50.625 15.12 50.895 ;
     RECT  2.16 51.165 15.12 51.435 ;
     RECT  2.16 51.705 15.12 51.975 ;
     RECT  2.16 52.245 15.12 52.515 ;
     RECT  2.16 52.785 15.12 53.055 ;
     RECT  2.16 53.325 15.12 53.595 ;
     RECT  2.16 53.865 15.12 54.135 ;
     RECT  2.16 54.405 15.12 54.675 ;
     RECT  2.16 54.945 15.12 55.215 ;
     RECT  2.16 55.485 15.12 55.755 ;
     RECT  2.16 56.025 15.12 56.16 ;
    LAYER RVTP ;
     RECT  2.16 2.295 15.12 2.565 ;
     RECT  2.16 2.835 15.12 3.105 ;
     RECT  2.16 3.375 15.12 3.645 ;
     RECT  2.16 3.915 15.12 4.185 ;
     RECT  2.16 4.455 15.12 4.725 ;
     RECT  2.16 4.995 15.12 5.265 ;
     RECT  2.16 5.535 15.12 5.805 ;
     RECT  2.16 6.075 15.12 6.345 ;
     RECT  2.16 6.615 15.12 6.885 ;
     RECT  2.16 7.155 15.12 7.425 ;
     RECT  2.16 7.695 15.12 7.965 ;
     RECT  2.16 8.235 15.12 8.505 ;
     RECT  2.16 8.775 15.12 9.045 ;
     RECT  2.16 9.315 15.12 9.585 ;
     RECT  2.16 9.855 15.12 10.125 ;
     RECT  2.16 10.395 15.12 10.665 ;
     RECT  2.16 10.935 15.12 11.205 ;
     RECT  2.16 11.475 15.12 11.745 ;
     RECT  2.16 12.015 15.12 12.285 ;
     RECT  2.16 12.555 15.12 12.825 ;
     RECT  2.16 13.095 15.12 13.365 ;
     RECT  2.16 13.635 15.12 13.905 ;
     RECT  2.16 14.175 15.12 14.445 ;
     RECT  2.16 14.715 15.12 14.985 ;
     RECT  2.16 15.255 15.12 15.525 ;
     RECT  2.16 15.795 15.12 16.065 ;
     RECT  2.16 16.335 15.12 16.605 ;
     RECT  2.16 16.875 15.12 17.145 ;
     RECT  2.16 17.415 15.12 17.685 ;
     RECT  2.16 17.955 15.12 18.225 ;
     RECT  2.16 18.495 15.12 18.765 ;
     RECT  2.16 19.035 15.12 19.305 ;
     RECT  2.16 19.575 15.12 19.845 ;
     RECT  2.16 20.115 15.12 20.385 ;
     RECT  2.16 20.655 15.12 20.925 ;
     RECT  2.16 21.195 15.12 21.465 ;
     RECT  2.16 21.735 15.12 22.005 ;
     RECT  2.16 22.275 15.12 22.545 ;
     RECT  2.16 22.815 15.12 23.085 ;
     RECT  2.16 23.355 15.12 23.625 ;
     RECT  2.16 23.895 15.12 24.165 ;
     RECT  2.16 24.435 15.12 24.705 ;
     RECT  2.16 24.975 15.12 25.245 ;
     RECT  2.16 25.515 15.12 25.785 ;
     RECT  2.16 26.055 15.12 26.325 ;
     RECT  2.16 26.595 15.12 26.865 ;
     RECT  2.16 27.135 15.12 27.405 ;
     RECT  2.16 27.675 15.12 27.945 ;
     RECT  2.16 28.215 15.12 28.485 ;
     RECT  2.16 28.755 15.12 29.025 ;
     RECT  2.16 29.295 15.12 29.565 ;
     RECT  2.16 29.835 15.12 30.105 ;
     RECT  2.16 30.375 15.12 30.645 ;
     RECT  2.16 30.915 15.12 31.185 ;
     RECT  2.16 31.455 15.12 31.725 ;
     RECT  2.16 31.995 15.12 32.265 ;
     RECT  2.16 32.535 15.12 32.805 ;
     RECT  2.16 33.075 15.12 33.345 ;
     RECT  2.16 33.615 15.12 33.885 ;
     RECT  2.16 34.155 15.12 34.425 ;
     RECT  2.16 34.695 15.12 34.965 ;
     RECT  2.16 35.235 15.12 35.505 ;
     RECT  2.16 35.775 15.12 36.045 ;
     RECT  2.16 36.315 15.12 36.585 ;
     RECT  2.16 36.855 15.12 37.125 ;
     RECT  2.16 37.395 15.12 37.665 ;
     RECT  2.16 37.935 15.12 38.205 ;
     RECT  2.16 38.475 15.12 38.745 ;
     RECT  2.16 39.015 15.12 39.285 ;
     RECT  2.16 39.555 15.12 39.825 ;
     RECT  2.16 40.095 15.12 40.365 ;
     RECT  2.16 40.635 15.12 40.905 ;
     RECT  2.16 41.175 15.12 41.445 ;
     RECT  2.16 41.715 15.12 41.985 ;
     RECT  2.16 42.255 15.12 42.525 ;
     RECT  2.16 42.795 15.12 43.065 ;
     RECT  2.16 43.335 15.12 43.605 ;
     RECT  2.16 43.875 15.12 44.145 ;
     RECT  2.16 44.415 15.12 44.685 ;
     RECT  2.16 44.955 15.12 45.225 ;
     RECT  2.16 45.495 15.12 45.765 ;
     RECT  2.16 46.035 15.12 46.305 ;
     RECT  2.16 46.575 15.12 46.845 ;
     RECT  2.16 47.115 15.12 47.385 ;
     RECT  2.16 47.655 15.12 47.925 ;
     RECT  2.16 48.195 15.12 48.465 ;
     RECT  2.16 48.735 15.12 49.005 ;
     RECT  2.16 49.275 15.12 49.545 ;
     RECT  2.16 49.815 15.12 50.085 ;
     RECT  2.16 50.355 15.12 50.625 ;
     RECT  2.16 50.895 15.12 51.165 ;
     RECT  2.16 51.435 15.12 51.705 ;
     RECT  2.16 51.975 15.12 52.245 ;
     RECT  2.16 52.515 15.12 52.785 ;
     RECT  2.16 53.055 15.12 53.325 ;
     RECT  2.16 53.595 15.12 53.865 ;
     RECT  2.16 54.135 15.12 54.405 ;
     RECT  2.16 54.675 15.12 54.945 ;
     RECT  2.16 55.215 15.12 55.485 ;
     RECT  2.16 55.755 15.12 56.025 ;
    LAYER M1 ;
     RECT  2.16 2.151 15.12 56.169 ;
    LAYER M2 ;
     RECT  0.211 32.742 0.247 33.03 ;
     RECT  0.211 23.904 0.311 23.922 ;
     RECT  0.211 38.142 0.311 38.16 ;
     RECT  0.211 45.504 0.311 45.522 ;
     RECT  0.211 48.24 0.311 48.258 ;
     RECT  0.211 50.364 0.311 50.382 ;
     RECT  0.211 55.494 0.311 55.512 ;
     RECT  0.247 8.856 0.347 8.874 ;
     RECT  0.247 15.336 0.347 15.354 ;
     RECT  0.319 23.166 0.419 23.184 ;
     RECT  0.499 12.024 0.535 12.042 ;
     RECT  0.211 29.466 0.535 29.484 ;
     RECT  0.247 32.346 0.535 33.03 ;
     RECT  0.211 54.036 0.535 54.054 ;
     RECT  0.535 6.66 0.571 6.678 ;
     RECT  0.571 6.66 0.671 6.804 ;
     RECT  0.211 16.506 1.147 16.524 ;
     RECT  0.535 22.086 1.147 22.104 ;
     RECT  1.147 21.942 1.175 22.104 ;
     RECT  0.671 6.66 2.16 6.678 ;
     RECT  0.535 7.776 2.16 7.794 ;
     RECT  0.535 9.666 2.16 9.684 ;
     RECT  0.535 11.25 2.16 12.042 ;
     RECT  1.147 16.506 2.16 16.974 ;
     RECT  1.175 21.942 2.16 21.96 ;
     RECT  0.535 27.342 2.16 27.36 ;
     RECT  0.535 28.998 2.16 29.484 ;
     RECT  0.535 31.806 2.16 33.03 ;
     RECT  0.535 47.628 2.16 47.646 ;
     RECT  0.535 48.744 2.16 48.762 ;
     RECT  0.535 52.218 2.16 52.236 ;
     RECT  0.535 53.568 2.16 54.054 ;
     RECT  2.16 2.151 3.379 56.169 ;
     RECT  3.379 2.151 3.739 56.358 ;
     RECT  3.739 2.034 5.575 56.358 ;
     RECT  5.575 2.034 7.015 56.394 ;
     RECT  7.015 2.034 9.599 56.439 ;
     RECT  9.599 2.07 11.579 56.439 ;
     RECT  11.579 2.07 12.703 56.394 ;
     RECT  12.703 2.034 14.495 56.394 ;
     RECT  14.495 2.07 14.711 56.394 ;
     RECT  14.711 2.07 15.12 56.25 ;
     RECT  15.12 2.07 15.431 11.808 ;
     RECT  15.12 12.87 15.431 33.336 ;
     RECT  15.12 34.092 15.431 37.584 ;
     RECT  15.12 38.988 15.431 39.546 ;
     RECT  15.12 40.338 15.431 42.624 ;
     RECT  15.12 43.65 15.431 44.406 ;
     RECT  15.12 45.306 15.431 56.25 ;
     RECT  15.431 6.12 15.467 7.794 ;
     RECT  15.431 9.252 15.467 11.736 ;
     RECT  15.431 19.89 15.467 22.104 ;
     RECT  15.431 22.896 15.467 25.812 ;
     RECT  15.431 38.988 15.467 39.312 ;
     RECT  15.431 42.57 15.467 42.624 ;
     RECT  15.431 45.306 15.467 46.368 ;
     RECT  15.431 48.942 15.467 50.418 ;
     RECT  15.431 51.444 15.467 52.812 ;
     RECT  15.431 56.07 15.467 56.25 ;
     RECT  15.431 40.68 15.503 41.742 ;
     RECT  15.467 20.934 16.007 21.42 ;
     RECT  15.431 26.802 16.007 28.314 ;
     RECT  15.431 30.42 16.007 30.978 ;
     RECT  15.431 36.36 16.007 37.584 ;
     RECT  15.467 52.794 16.007 52.812 ;
     RECT  15.431 53.568 16.007 54.936 ;
     RECT  15.431 2.07 16.547 4.752 ;
     RECT  15.467 6.318 16.547 7.758 ;
     RECT  15.467 9.252 16.547 9.27 ;
     RECT  15.467 10.134 16.547 11.502 ;
     RECT  15.431 14.454 16.547 15.894 ;
     RECT  15.431 16.65 16.547 19.062 ;
     RECT  15.467 19.89 16.547 19.908 ;
     RECT  15.467 22.896 16.547 22.914 ;
     RECT  15.467 23.904 16.547 24.93 ;
     RECT  15.467 25.794 16.547 25.812 ;
     RECT  16.007 26.802 16.547 28.278 ;
     RECT  16.007 30.42 16.547 30.438 ;
     RECT  15.431 32.04 16.547 32.058 ;
     RECT  15.431 34.668 16.547 34.992 ;
     RECT  16.007 36.36 16.547 37.116 ;
     RECT  15.503 41.724 16.547 41.742 ;
     RECT  15.467 42.57 16.547 42.588 ;
     RECT  15.431 43.812 16.547 43.83 ;
     RECT  15.467 45.306 16.547 46.296 ;
     RECT  15.431 47.394 16.547 47.88 ;
     RECT  15.467 48.942 16.547 49.842 ;
     RECT  15.467 51.444 16.547 52.038 ;
     RECT  16.007 54.216 16.547 54.936 ;
     RECT  15.467 56.232 16.547 56.25 ;
     RECT  16.547 2.07 16.583 2.088 ;
     RECT  16.547 3.618 16.583 3.978 ;
     RECT  16.547 6.318 16.583 6.336 ;
     RECT  16.547 14.454 16.583 14.778 ;
     RECT  16.547 17.352 16.583 18.99 ;
     RECT  16.007 20.934 16.583 21.15 ;
     RECT  16.547 28.026 16.583 28.044 ;
     RECT  16.547 15.804 16.619 15.894 ;
     RECT  16.547 34.74 16.619 34.992 ;
     RECT  15.467 39.294 17.059 39.312 ;
     RECT  15.503 40.68 17.059 40.968 ;
     RECT  16.547 47.394 17.059 47.448 ;
     RECT  16.547 54.216 17.059 54.234 ;
     RECT  16.583 3.618 17.159 3.834 ;
     RECT  17.059 5.238 17.159 5.256 ;
     RECT  16.547 7.362 17.159 7.38 ;
     RECT  17.059 8.478 17.159 8.496 ;
     RECT  16.547 10.71 17.159 10.728 ;
     RECT  17.059 13.716 17.159 14.4 ;
     RECT  17.059 16.506 17.159 16.524 ;
     RECT  16.583 17.352 17.159 17.946 ;
     RECT  16.583 18.972 17.159 18.99 ;
     RECT  17.059 20.898 17.159 20.916 ;
     RECT  17.059 23.634 17.159 23.652 ;
     RECT  17.059 25.524 17.159 25.542 ;
     RECT  17.059 30.15 17.159 30.366 ;
     RECT  17.059 31.662 17.159 31.68 ;
     RECT  17.059 35.208 17.159 36.27 ;
     RECT  17.059 37.134 17.159 37.962 ;
     RECT  17.059 38.988 17.159 39.429 ;
     RECT  17.059 40.68 17.159 41.436 ;
     RECT  17.059 42.606 17.159 42.624 ;
     RECT  17.059 44.46 17.159 44.712 ;
     RECT  17.059 46.818 17.159 47.448 ;
     RECT  16.547 49.176 17.159 49.194 ;
     RECT  17.059 50.211 17.159 50.229 ;
     RECT  17.059 52.794 17.159 52.812 ;
     RECT  17.059 53.838 17.159 54.234 ;
     RECT  17.059 55.026 17.159 55.044 ;
    LAYER M3 ;
     RECT  9.576 2.029 9.594 2.065 ;
     RECT  14.472 2.029 14.49 2.101 ;
     RECT  4.608 2.101 4.626 2.143 ;
     RECT  8.208 2.065 8.226 2.143 ;
     RECT  12.708 2.029 12.726 2.143 ;
     RECT  13.824 2.101 14.49 2.143 ;
     RECT  2.415 2.143 2.505 2.191 ;
     RECT  3.744 2.029 3.762 2.191 ;
     RECT  4.608 2.143 5.205 2.191 ;
     RECT  6.624 2.065 6.642 2.219 ;
     RECT  12.708 2.143 14.49 2.219 ;
     RECT  2.304 2.191 5.205 2.237 ;
     RECT  6.444 2.251 6.462 2.291 ;
     RECT  7.815 2.143 8.226 2.299 ;
     RECT  7.416 2.299 8.622 2.335 ;
     RECT  10.515 2.143 10.605 2.335 ;
     RECT  11.628 2.299 11.718 2.335 ;
     RECT  12.708 2.219 13.698 2.335 ;
     RECT  16.56 2.065 16.578 2.347 ;
     RECT  2.304 2.237 4.014 2.381 ;
     RECT  4.896 2.237 5.205 2.413 ;
     RECT  4.896 2.413 5.397 2.461 ;
     RECT  7.38 2.335 8.622 2.491 ;
     RECT  9.576 2.065 9.666 2.491 ;
     RECT  7.38 2.491 9.666 2.539 ;
     RECT  7.236 2.539 9.666 2.569 ;
     RECT  10.515 2.335 11.718 2.569 ;
     RECT  12.564 2.335 13.698 2.569 ;
     RECT  16.524 2.347 16.578 2.573 ;
     RECT  15.408 2.203 15.426 2.635 ;
     RECT  12.492 2.569 13.698 2.759 ;
     RECT  7.236 2.569 11.718 2.875 ;
     RECT  3.492 2.381 4.014 3.001 ;
     RECT  7.236 2.875 11.754 3.019 ;
     RECT  4.896 2.461 6.102 3.029 ;
     RECT  7.2 3.019 11.754 3.073 ;
     RECT  12.492 2.759 13.554 3.073 ;
     RECT  7.2 3.073 13.554 3.109 ;
     RECT  2.304 2.381 2.697 3.145 ;
     RECT  3.492 3.001 4.086 3.145 ;
     RECT  7.092 3.109 13.554 3.149 ;
     RECT  14.832 2.635 15.426 3.173 ;
     RECT  14.832 3.173 14.85 3.197 ;
     RECT  16.524 2.573 16.542 3.259 ;
     RECT  15.984 3.259 16.542 3.407 ;
     RECT  2.304 3.145 4.086 3.415 ;
     RECT  16.524 3.407 16.542 3.595 ;
     RECT  16.524 3.595 17.082 3.613 ;
     RECT  2.304 3.415 4.194 3.787 ;
     RECT  2.268 3.787 4.194 3.811 ;
     RECT  5.115 3.029 6.102 3.839 ;
     RECT  16.524 3.613 17.154 3.869 ;
     RECT  2.268 3.811 4.23 3.883 ;
     RECT  16.524 3.869 16.578 3.983 ;
     RECT  7.272 3.149 13.554 3.991 ;
     RECT  7.272 3.991 14.274 4.027 ;
     RECT  7.272 4.027 14.85 4.117 ;
     RECT  7.164 4.117 14.85 4.123 ;
     RECT  5.115 3.839 5.397 4.219 ;
     RECT  2.268 3.883 4.338 4.253 ;
     RECT  6.408 4.075 6.426 4.261 ;
     RECT  7.164 4.123 15.426 4.261 ;
     RECT  6.408 4.261 15.426 4.445 ;
     RECT  3.744 4.253 4.338 4.496 ;
     RECT  6.408 4.445 11.718 4.523 ;
     RECT  12.492 4.445 15.426 4.523 ;
     RECT  3.816 4.496 4.338 4.559 ;
     RECT  6.804 4.523 11.718 4.649 ;
     RECT  12.564 4.523 15.426 4.721 ;
     RECT  16.524 3.983 16.542 4.757 ;
     RECT  2.268 4.253 2.79 4.801 ;
     RECT  3.96 4.559 4.338 4.801 ;
     RECT  5.076 4.219 5.397 4.801 ;
     RECT  14.616 4.721 15.426 4.919 ;
     RECT  3.96 4.801 5.397 5.099 ;
     RECT  2.196 4.801 2.79 5.117 ;
     RECT  2.304 5.117 2.79 5.233 ;
     RECT  17.064 5.224 17.154 5.261 ;
     RECT  6.804 4.649 11.322 5.269 ;
     RECT  3.96 5.099 4.374 5.305 ;
     RECT  17.064 5.261 17.082 5.309 ;
     RECT  6.156 5.269 11.322 5.459 ;
     RECT  14.832 4.919 15.426 5.603 ;
     RECT  6.804 5.459 11.322 5.611 ;
     RECT  2.304 5.233 2.862 5.701 ;
     RECT  6.804 5.611 11.718 5.737 ;
     RECT  12.564 4.721 13.842 5.737 ;
     RECT  15.408 5.603 15.426 5.8 ;
     RECT  6.804 5.737 13.842 5.837 ;
     RECT  2.304 5.701 3.042 5.851 ;
     RECT  3.924 5.305 4.374 5.881 ;
     RECT  5.115 5.099 5.397 5.881 ;
     RECT  3.924 5.881 5.397 6.043 ;
     RECT  2.304 5.851 3.186 6.079 ;
     RECT  3.924 6.043 6.03 6.079 ;
     RECT  7.2 5.837 13.842 6.091 ;
     RECT  7.2 6.091 13.914 6.139 ;
     RECT  2.304 6.079 6.03 6.269 ;
     RECT  16.524 6.235 16.542 6.313 ;
     RECT  7.2 6.139 14.274 6.427 ;
     RECT  15.408 5.8 15.462 6.427 ;
     RECT  0.396 6.523 0.414 6.619 ;
     RECT  7.2 6.427 15.462 6.619 ;
     RECT  0.288 6.619 0.414 6.655 ;
     RECT  0.288 6.655 0.558 6.749 ;
     RECT  0.54 6.749 0.558 6.763 ;
     RECT  0.54 6.763 0.594 6.781 ;
     RECT  2.304 6.269 5.994 6.809 ;
     RECT  0.54 6.781 0.666 6.845 ;
     RECT  3.96 6.809 5.526 6.845 ;
     RECT  7.128 6.619 15.462 6.845 ;
     RECT  7.128 6.845 13.95 6.859 ;
     RECT  0.54 6.845 0.558 6.893 ;
     RECT  14.832 6.845 15.462 6.893 ;
     RECT  6.804 6.859 13.95 6.989 ;
     RECT  2.304 6.809 2.862 7.051 ;
     RECT  2.268 7.051 2.862 7.259 ;
     RECT  16.524 6.313 16.578 7.339 ;
     RECT  7.2 6.989 13.95 7.385 ;
     RECT  16.524 7.339 17.154 7.385 ;
     RECT  16.524 7.385 17.082 7.421 ;
     RECT  7.416 7.385 13.95 7.663 ;
     RECT  14.832 6.893 14.85 7.663 ;
     RECT  7.416 7.663 14.85 7.723 ;
     RECT  2.304 7.259 2.862 7.735 ;
     RECT  16.524 7.421 16.614 7.763 ;
     RECT  3.96 6.845 5.397 7.771 ;
     RECT  7.416 7.723 15.426 7.771 ;
     RECT  7.416 7.771 15.462 7.853 ;
     RECT  2.304 7.735 2.934 7.889 ;
     RECT  3.924 7.771 5.397 7.901 ;
     RECT  0.54 7.771 0.558 8.045 ;
     RECT  16.56 7.763 16.614 8.045 ;
     RECT  3.924 7.901 4.014 8.155 ;
     RECT  7.416 7.853 15.426 8.275 ;
     RECT  2.304 7.889 2.862 8.339 ;
     RECT  16.596 8.045 16.614 8.443 ;
     RECT  16.596 8.443 17.082 8.473 ;
     RECT  7.2 8.275 15.426 8.477 ;
     RECT  16.596 8.473 17.154 8.525 ;
     RECT  2.415 8.339 2.862 8.671 ;
     RECT  3.744 8.155 4.014 8.671 ;
     RECT  7.344 8.477 15.426 8.699 ;
     RECT  3.744 8.671 4.158 8.731 ;
     RECT  4.896 7.901 5.397 8.731 ;
     RECT  3.744 8.731 5.397 8.743 ;
     RECT  2.415 8.671 2.898 8.779 ;
     RECT  3.744 8.743 5.526 8.779 ;
     RECT  0.252 8.635 0.27 8.827 ;
     RECT  14.832 8.699 15.426 8.843 ;
     RECT  2.415 8.779 5.526 8.852 ;
     RECT  0.252 8.827 0.342 8.879 ;
     RECT  2.415 8.852 5.49 8.879 ;
     RECT  0.252 8.879 0.27 8.909 ;
     RECT  3.744 8.879 5.49 8.969 ;
     RECT  7.344 8.699 14.058 8.969 ;
     RECT  7.344 8.969 13.842 9.005 ;
     RECT  2.415 8.879 2.97 9.163 ;
     RECT  16.596 8.525 16.614 9.163 ;
     RECT  16.524 9.163 16.614 9.275 ;
     RECT  16.596 9.275 16.614 9.341 ;
     RECT  2.304 9.163 2.97 9.419 ;
     RECT  3.744 8.969 5.397 9.533 ;
     RECT  2.304 9.419 2.934 9.581 ;
     RECT  14.832 8.843 14.886 9.595 ;
     RECT  0.54 9.661 0.558 9.725 ;
     RECT  14.832 9.595 15.426 9.823 ;
     RECT  14.832 9.823 15.462 9.869 ;
     RECT  14.832 9.869 15.426 9.916 ;
     RECT  3.744 9.533 4.014 9.931 ;
     RECT  7.38 9.005 13.842 9.931 ;
     RECT  14.796 9.916 15.426 9.931 ;
     RECT  6.84 9.931 15.426 10.229 ;
     RECT  3.708 9.931 4.014 10.291 ;
     RECT  4.824 9.533 5.397 10.291 ;
     RECT  6.84 10.229 11.574 10.363 ;
     RECT  2.304 9.581 2.754 10.411 ;
     RECT  3.708 10.291 5.397 10.411 ;
     RECT  12.456 10.229 15.426 10.661 ;
     RECT  16.524 10.027 16.542 10.696 ;
     RECT  16.524 10.696 17.154 10.733 ;
     RECT  2.304 10.411 5.397 10.741 ;
     RECT  6.336 10.363 11.574 10.769 ;
     RECT  16.524 10.733 17.082 10.781 ;
     RECT  6.804 10.769 11.574 10.973 ;
     RECT  6.876 10.973 11.574 11.011 ;
     RECT  12.456 10.661 14.022 11.011 ;
     RECT  2.268 10.741 5.397 11.083 ;
     RECT  2.268 11.083 5.49 11.281 ;
     RECT  16.524 10.781 16.542 11.507 ;
     RECT  6.876 11.011 14.022 11.551 ;
     RECT  14.796 10.661 15.426 11.551 ;
     RECT  6.876 11.551 15.426 11.669 ;
     RECT  6.876 11.669 14.022 11.704 ;
     RECT  14.832 11.669 15.426 11.707 ;
     RECT  6.804 11.704 14.022 11.741 ;
     RECT  14.832 11.707 15.462 11.747 ;
     RECT  14.832 11.747 15.426 11.813 ;
     RECT  2.268 11.281 5.562 11.899 ;
     RECT  2.232 11.899 5.562 11.939 ;
     RECT  14.832 11.813 15.066 11.975 ;
     RECT  0.54 11.245 0.558 12.019 ;
     RECT  0.504 12.019 0.558 12.029 ;
     RECT  7.308 11.741 14.022 12.029 ;
     RECT  2.304 11.939 5.562 12.055 ;
     RECT  2.304 12.055 5.67 12.091 ;
     RECT  2.304 12.091 6.102 12.209 ;
     RECT  2.304 12.209 5.67 12.353 ;
     RECT  0.504 12.029 0.522 12.557 ;
     RECT  14.832 11.975 14.994 12.763 ;
     RECT  2.304 12.353 5.598 12.797 ;
     RECT  7.308 12.029 13.914 12.859 ;
     RECT  6.804 12.859 13.914 13.019 ;
     RECT  16.524 13.003 16.542 13.133 ;
     RECT  3.708 12.797 5.598 13.135 ;
     RECT  7.236 13.019 13.914 13.135 ;
     RECT  7.236 13.135 14.022 13.171 ;
     RECT  3.708 13.135 5.958 13.289 ;
     RECT  2.304 12.797 2.826 13.531 ;
     RECT  2.196 13.531 2.826 13.613 ;
     RECT  2.304 13.613 2.826 13.627 ;
     RECT  4.212 13.289 5.958 13.631 ;
     RECT  2.304 13.627 3.222 13.667 ;
     RECT  4.572 13.631 5.958 13.667 ;
     RECT  7.236 13.171 14.058 13.703 ;
     RECT  12.708 13.703 14.058 13.711 ;
     RECT  14.832 12.763 15.426 13.711 ;
     RECT  7.236 13.703 11.826 13.801 ;
     RECT  7.164 13.801 11.826 13.819 ;
     RECT  6.804 13.819 11.826 13.867 ;
     RECT  2.304 13.667 3.15 13.901 ;
     RECT  12.708 13.711 15.426 13.901 ;
     RECT  6.732 13.867 11.826 13.937 ;
     RECT  4.572 13.667 5.886 14.099 ;
     RECT  12.708 13.901 14.922 14.189 ;
     RECT  2.304 13.901 3.006 14.207 ;
     RECT  2.304 14.207 2.79 14.237 ;
     RECT  17.064 13.675 17.154 14.251 ;
     RECT  1.152 14.299 1.17 14.347 ;
     RECT  16.524 14.251 17.154 14.429 ;
     RECT  4.572 14.099 5.397 14.44 ;
     RECT  1.152 14.347 1.278 14.477 ;
     RECT  4.5 14.44 5.397 14.477 ;
     RECT  4.14 14.491 4.23 14.521 ;
     RECT  6.804 13.937 11.826 14.521 ;
     RECT  12.708 14.189 13.518 14.521 ;
     RECT  14.832 14.189 14.922 14.635 ;
     RECT  6.804 14.521 13.518 14.639 ;
     RECT  16.524 14.429 16.578 14.783 ;
     RECT  6.804 14.639 13.497 14.819 ;
     RECT  14.832 14.635 14.994 14.875 ;
     RECT  0.288 14.635 0.306 15.019 ;
     RECT  2.304 14.237 2.697 15.019 ;
     RECT  3.744 14.521 4.23 15.019 ;
     RECT  14.832 14.875 15.426 15.053 ;
     RECT  2.304 15.019 4.23 15.061 ;
     RECT  2.268 15.061 4.23 15.197 ;
     RECT  0.252 15.019 0.306 15.307 ;
     RECT  0.252 15.307 0.342 15.359 ;
     RECT  0.252 15.359 0.27 15.389 ;
     RECT  15.408 15.053 15.426 15.403 ;
     RECT  5.04 14.477 5.397 15.421 ;
     RECT  7.236 14.819 13.497 15.421 ;
     RECT  7.236 15.421 13.77 15.493 ;
     RECT  15.408 15.403 15.462 15.521 ;
     RECT  2.304 15.197 4.23 15.529 ;
     RECT  5.04 15.421 5.454 15.529 ;
     RECT  16.524 14.783 16.542 15.595 ;
     RECT  16.524 15.595 16.578 15.739 ;
     RECT  2.304 15.529 5.454 15.791 ;
     RECT  7.236 15.493 14.31 15.835 ;
     RECT  15.408 15.521 15.426 15.835 ;
     RECT  7.236 15.835 15.426 15.979 ;
     RECT  5.115 15.791 5.454 16.069 ;
     RECT  6.228 15.961 6.246 16.069 ;
     RECT  5.115 16.069 6.246 16.339 ;
     RECT  7.092 15.979 15.426 16.339 ;
     RECT  16.524 15.739 16.614 16.459 ;
     RECT  16.524 16.459 17.082 16.501 ;
     RECT  5.115 16.339 15.426 16.529 ;
     RECT  16.524 16.501 17.154 16.541 ;
     RECT  0.216 16.501 0.234 16.589 ;
     RECT  14.832 16.529 15.426 16.601 ;
     RECT  2.304 15.791 4.122 16.651 ;
     RECT  1.152 16.699 1.17 16.747 ;
     RECT  1.152 16.747 1.278 16.877 ;
     RECT  2.304 16.651 4.374 16.987 ;
     RECT  5.115 16.529 14.094 16.987 ;
     RECT  2.304 16.987 14.094 17.069 ;
     RECT  6.804 17.069 14.094 17.105 ;
     RECT  1.152 16.877 1.17 17.117 ;
     RECT  16.524 16.541 16.542 17.323 ;
     RECT  16.524 17.323 17.082 17.347 ;
     RECT  14.832 16.601 14.886 17.383 ;
     RECT  14.328 17.383 14.886 17.419 ;
     RECT  14.328 17.419 15.426 17.491 ;
     RECT  6.804 17.105 13.59 17.519 ;
     RECT  14.328 17.491 15.462 17.645 ;
     RECT  2.304 17.069 2.97 17.803 ;
     RECT  3.96 17.069 5.397 17.879 ;
     RECT  6.84 17.519 13.59 17.947 ;
     RECT  14.328 17.645 15.426 17.947 ;
     RECT  16.524 17.347 17.154 17.951 ;
     RECT  16.524 17.951 17.082 17.981 ;
     RECT  6.84 17.947 15.426 18.032 ;
     RECT  2.268 17.803 2.97 18.059 ;
     RECT  2.304 18.059 2.97 18.301 ;
     RECT  2.304 18.301 3.294 18.661 ;
     RECT  4.032 17.879 5.397 18.661 ;
     RECT  2.304 18.661 5.397 18.689 ;
     RECT  7.236 18.032 15.426 18.797 ;
     RECT  7.236 18.797 13.842 18.841 ;
     RECT  16.524 17.981 16.578 18.955 ;
     RECT  16.524 18.955 17.154 18.995 ;
     RECT  16.524 18.995 17.082 19.037 ;
     RECT  14.616 18.797 15.426 19.229 ;
     RECT  5.115 18.689 5.397 19.273 ;
     RECT  2.304 18.689 4.086 19.409 ;
     RECT  3.744 19.409 4.086 19.471 ;
     RECT  0.396 19.483 0.414 19.579 ;
     RECT  3.744 19.471 4.338 19.579 ;
     RECT  5.115 19.273 5.634 19.579 ;
     RECT  0.288 19.579 0.414 19.613 ;
     RECT  6.84 18.841 13.842 19.643 ;
     RECT  3.744 19.579 5.634 19.771 ;
     RECT  0.288 19.613 0.306 19.805 ;
     RECT  3.744 19.771 6.246 19.877 ;
     RECT  16.524 19.037 16.542 19.913 ;
     RECT  2.304 19.409 2.754 19.915 ;
     RECT  6.984 19.643 13.842 19.949 ;
     RECT  3.744 19.877 5.634 20.075 ;
     RECT  12.564 19.949 13.842 20.155 ;
     RECT  14.832 19.229 15.426 20.155 ;
     RECT  2.268 19.915 2.754 20.191 ;
     RECT  3.744 20.075 5.397 20.191 ;
     RECT  2.232 20.191 2.754 20.237 ;
     RECT  2.268 20.237 2.754 20.281 ;
     RECT  3.492 20.191 5.397 20.281 ;
     RECT  12.564 20.155 13.914 20.309 ;
     RECT  12.564 20.309 13.842 20.381 ;
     RECT  14.832 20.155 15.462 20.453 ;
     RECT  6.984 19.949 11.754 20.587 ;
     RECT  16.524 20.779 16.542 20.875 ;
     RECT  16.524 20.875 17.082 20.893 ;
     RECT  16.524 20.893 17.154 20.957 ;
     RECT  2.268 20.281 5.397 20.993 ;
     RECT  6.804 20.587 11.754 21.001 ;
     RECT  12.564 20.381 13.554 21.001 ;
     RECT  16.524 20.957 16.578 21.155 ;
     RECT  6.804 21.001 13.554 21.163 ;
     RECT  14.832 20.453 14.85 21.163 ;
     RECT  14.616 21.163 14.85 21.211 ;
     RECT  6.804 21.163 13.59 21.235 ;
     RECT  14.616 21.211 14.886 21.259 ;
     RECT  6.804 21.235 13.842 21.361 ;
     RECT  14.616 21.259 14.994 21.389 ;
     RECT  6.156 21.361 13.842 21.437 ;
     RECT  3.672 20.993 5.397 21.499 ;
     RECT  6.156 21.437 6.282 21.499 ;
     RECT  2.268 20.993 2.697 21.629 ;
     RECT  7.272 21.437 13.842 21.677 ;
     RECT  15.984 21.397 16.002 21.677 ;
     RECT  7.416 21.677 13.842 21.691 ;
     RECT  14.724 21.389 14.994 21.835 ;
     RECT  3.672 21.499 6.282 21.929 ;
     RECT  3.672 21.929 3.87 21.937 ;
     RECT  2.304 21.629 2.697 22.009 ;
     RECT  3.456 21.937 3.87 22.009 ;
     RECT  1.152 21.937 1.17 22.081 ;
     RECT  14.724 21.835 15.462 22.109 ;
     RECT  2.304 22.009 3.87 22.199 ;
     RECT  7.416 21.691 13.914 22.199 ;
     RECT  14.724 22.109 15.426 22.235 ;
     RECT  7.416 22.199 13.878 22.459 ;
     RECT  2.304 22.199 3.762 22.469 ;
     RECT  0.54 22.081 1.17 22.651 ;
     RECT  0.54 22.651 1.278 22.781 ;
     RECT  2.304 22.469 3.582 22.781 ;
     RECT  4.608 21.929 6.282 23.017 ;
     RECT  14.832 22.235 15.426 23.08 ;
     RECT  0.468 22.939 0.486 23.083 ;
     RECT  0.252 23.083 0.486 23.117 ;
     RECT  2.304 22.781 3.51 23.117 ;
     RECT  7.164 22.459 13.878 23.125 ;
     RECT  14.832 23.08 15.462 23.125 ;
     RECT  4.608 23.017 6.426 23.131 ;
     RECT  4.428 23.131 6.426 23.161 ;
     RECT  7.164 23.125 15.462 23.161 ;
     RECT  4.428 23.161 15.462 23.165 ;
     RECT  0.252 23.117 0.414 23.189 ;
     RECT  4.428 23.165 5.598 23.189 ;
     RECT  0.252 23.189 0.342 23.213 ;
     RECT  6.984 23.165 15.462 23.261 ;
     RECT  7.128 23.261 15.462 23.279 ;
     RECT  7.128 23.279 14.094 23.309 ;
     RECT  7.2 23.309 14.094 23.315 ;
     RECT  14.832 23.279 15.462 23.351 ;
     RECT  16.524 22.699 16.542 23.611 ;
     RECT  2.304 23.117 2.754 23.629 ;
     RECT  16.524 23.611 17.082 23.629 ;
     RECT  3.492 23.117 3.51 23.659 ;
     RECT  4.428 23.189 5.397 23.659 ;
     RECT  16.524 23.629 17.154 23.693 ;
     RECT  2.268 23.629 2.754 23.741 ;
     RECT  7.236 23.315 13.986 23.819 ;
     RECT  0.252 23.213 0.306 23.884 ;
     RECT  2.304 23.741 2.754 23.899 ;
     RECT  3.492 23.659 5.397 23.899 ;
     RECT  0.216 23.884 0.306 23.981 ;
     RECT  0.216 23.981 0.27 24.029 ;
     RECT  7.236 23.819 13.842 24.097 ;
     RECT  6.516 24.097 13.842 24.173 ;
     RECT  14.832 23.351 15.426 24.233 ;
     RECT  2.304 23.899 5.397 24.241 ;
     RECT  7.092 24.173 13.842 24.269 ;
     RECT  1.152 24.187 1.17 24.331 ;
     RECT  14.832 24.233 14.958 24.367 ;
     RECT  14.796 24.367 14.958 24.403 ;
     RECT  7.308 24.269 13.842 24.413 ;
     RECT  1.152 24.331 1.278 24.461 ;
     RECT  2.304 24.241 5.562 24.503 ;
     RECT  14.724 24.403 14.958 24.509 ;
     RECT  0.252 24.029 0.27 24.797 ;
     RECT  0.396 24.859 0.414 24.989 ;
     RECT  14.796 24.509 14.958 25.003 ;
     RECT  14.796 25.003 15.426 25.007 ;
     RECT  1.152 24.461 1.17 25.085 ;
     RECT  7.452 24.413 13.842 25.177 ;
     RECT  14.832 25.007 15.426 25.195 ;
     RECT  14.832 25.195 15.462 25.313 ;
     RECT  16.524 23.693 16.542 25.483 ;
     RECT  16.524 25.483 17.154 25.547 ;
     RECT  16.524 25.547 17.082 25.565 ;
     RECT  7.308 25.177 13.842 25.675 ;
     RECT  2.304 24.503 5.397 25.709 ;
     RECT  7.272 25.675 13.842 25.789 ;
     RECT  0.252 25.675 0.27 25.805 ;
     RECT  16.524 25.565 16.542 25.817 ;
     RECT  7.272 25.789 13.914 25.979 ;
     RECT  7.272 25.979 13.842 26.285 ;
     RECT  14.832 25.313 15.426 26.321 ;
     RECT  7.272 26.285 13.554 26.347 ;
     RECT  2.304 25.709 4.158 26.428 ;
     RECT  2.268 26.428 4.158 26.519 ;
     RECT  2.304 26.519 4.158 26.587 ;
     RECT  5.115 25.709 5.397 26.587 ;
     RECT  2.304 26.587 5.397 26.599 ;
     RECT  2.304 26.599 6.03 26.635 ;
     RECT  6.804 26.347 13.554 26.635 ;
     RECT  2.304 26.635 13.554 26.861 ;
     RECT  14.832 26.321 14.958 26.905 ;
     RECT  0.252 26.587 0.27 27.005 ;
     RECT  6.804 26.861 13.554 27.031 ;
     RECT  14.364 26.905 14.958 27.031 ;
     RECT  2.304 26.861 5.562 27.059 ;
     RECT  0.54 27.337 0.558 27.389 ;
     RECT  16.02 26.683 16.542 27.409 ;
     RECT  6.804 27.031 14.958 27.547 ;
     RECT  15.984 27.409 16.542 27.547 ;
     RECT  2.304 27.059 5.454 27.599 ;
     RECT  6.804 27.547 16.542 27.691 ;
     RECT  1.152 27.595 1.278 27.725 ;
     RECT  2.304 27.599 5.397 27.743 ;
     RECT  6.408 27.691 16.542 27.751 ;
     RECT  2.304 27.743 4.338 27.779 ;
     RECT  1.152 27.725 1.17 27.821 ;
     RECT  0.396 27.787 0.414 27.917 ;
     RECT  6.336 27.751 16.542 27.917 ;
     RECT  6.84 27.917 16.542 27.979 ;
     RECT  6.84 27.979 16.614 28.013 ;
     RECT  2.304 27.779 4.302 28.123 ;
     RECT  2.268 28.123 4.302 28.256 ;
     RECT  7.128 28.013 16.614 28.349 ;
     RECT  7.272 28.349 16.614 28.637 ;
     RECT  2.268 28.256 4.05 28.679 ;
     RECT  16.524 28.637 16.614 28.733 ;
     RECT  5.115 27.743 5.397 28.843 ;
     RECT  7.272 28.637 15.426 28.949 ;
     RECT  3.852 28.679 4.05 28.985 ;
     RECT  2.268 28.679 3.078 28.987 ;
     RECT  7.272 28.949 11.142 29.021 ;
     RECT  2.196 28.987 3.078 29.027 ;
     RECT  2.304 29.027 3.078 29.069 ;
     RECT  0.54 28.993 0.558 29.083 ;
     RECT  4.86 28.843 5.397 29.101 ;
     RECT  16.524 28.733 16.542 29.165 ;
     RECT  3.888 28.985 4.05 29.191 ;
     RECT  4.86 29.101 5.886 29.191 ;
     RECT  0.54 29.083 1.17 29.213 ;
     RECT  12.528 28.949 15.426 29.219 ;
     RECT  1.152 29.213 1.17 29.261 ;
     RECT  3.888 29.191 5.886 29.335 ;
     RECT  0.216 29.371 0.234 29.489 ;
     RECT  3.888 29.335 5.958 29.561 ;
     RECT  14.616 29.219 15.426 29.561 ;
     RECT  2.304 29.069 2.862 29.669 ;
     RECT  7.272 29.021 11.106 29.707 ;
     RECT  12.528 29.219 13.842 29.731 ;
     RECT  6.984 29.707 11.106 29.851 ;
     RECT  3.888 29.561 4.266 29.875 ;
     RECT  5.115 29.561 5.958 29.875 ;
     RECT  6.984 29.851 11.142 29.875 ;
     RECT  12.384 29.731 13.842 29.875 ;
     RECT  5.115 29.875 13.842 29.933 ;
     RECT  3.744 29.875 4.266 30.029 ;
     RECT  5.115 29.933 5.742 30.029 ;
     RECT  14.796 29.561 15.426 30.029 ;
     RECT  7.02 29.933 13.842 30.035 ;
     RECT  14.832 30.029 15.426 30.101 ;
     RECT  14.832 30.101 14.922 30.137 ;
     RECT  17.136 30.136 17.154 30.145 ;
     RECT  7.2 30.035 13.842 30.221 ;
     RECT  17.064 30.145 17.154 30.283 ;
     RECT  16.524 30.283 17.154 30.371 ;
     RECT  13.104 30.221 13.842 30.379 ;
     RECT  16.524 30.371 17.082 30.413 ;
     RECT  2.304 29.669 2.697 30.427 ;
     RECT  3.996 30.029 4.266 30.443 ;
     RECT  16.524 30.413 16.542 30.443 ;
     RECT  2.304 30.427 2.754 30.541 ;
     RECT  3.996 30.443 4.194 30.569 ;
     RECT  13.104 30.379 13.95 30.569 ;
     RECT  2.304 30.541 2.826 30.613 ;
     RECT  2.304 30.613 3.114 30.907 ;
     RECT  3.996 30.569 4.05 30.907 ;
     RECT  14.832 30.137 14.886 30.907 ;
     RECT  15.984 30.715 16.002 30.907 ;
     RECT  0.252 30.235 0.27 30.941 ;
     RECT  5.115 30.029 5.598 30.955 ;
     RECT  7.2 30.221 12.366 30.955 ;
     RECT  13.104 30.569 13.626 30.955 ;
     RECT  14.832 30.907 16.002 30.991 ;
     RECT  2.304 30.907 4.05 31.019 ;
     RECT  2.304 31.019 2.79 31.037 ;
     RECT  14.616 30.991 16.002 31.181 ;
     RECT  7.2 30.955 13.626 31.351 ;
     RECT  5.115 30.955 6.246 31.387 ;
     RECT  5.115 31.387 6.282 31.483 ;
     RECT  7.2 31.351 13.806 31.483 ;
     RECT  3.528 31.019 4.05 31.531 ;
     RECT  5.115 31.483 13.806 31.531 ;
     RECT  3.528 31.531 13.806 31.621 ;
     RECT  14.616 31.181 15.426 31.621 ;
     RECT  3.528 31.621 15.426 31.649 ;
     RECT  17.064 31.627 17.082 31.657 ;
     RECT  1.26 31.579 1.278 31.675 ;
     RECT  1.152 31.675 1.278 31.709 ;
     RECT  3.528 31.649 5.562 31.709 ;
     RECT  17.064 31.657 17.154 31.709 ;
     RECT  6.768 31.649 15.426 31.721 ;
     RECT  2.304 31.037 2.754 31.771 ;
     RECT  3.528 31.709 4.158 31.771 ;
     RECT  0.252 31.723 0.27 31.801 ;
     RECT  1.152 31.709 1.17 31.801 ;
     RECT  0.252 31.801 1.17 31.805 ;
     RECT  6.768 31.721 14.094 31.829 ;
     RECT  5.04 31.709 5.562 31.919 ;
     RECT  6.804 31.829 14.094 31.919 ;
     RECT  0.252 31.805 0.558 31.949 ;
     RECT  16.524 31.771 16.542 32.063 ;
     RECT  6.804 31.919 11.43 32.369 ;
     RECT  2.304 31.771 4.158 32.431 ;
     RECT  2.304 32.431 4.194 32.467 ;
     RECT  5.04 31.919 5.49 32.467 ;
     RECT  12.276 31.919 14.094 32.575 ;
     RECT  14.832 31.721 15.426 32.575 ;
     RECT  0.252 31.949 0.306 32.635 ;
     RECT  7.128 32.369 11.43 32.737 ;
     RECT  12.276 32.575 15.426 32.737 ;
     RECT  0.216 32.635 0.306 32.78 ;
     RECT  2.304 32.467 5.49 32.881 ;
     RECT  0.216 32.78 0.27 32.909 ;
     RECT  7.128 32.737 15.426 33.035 ;
     RECT  0.216 32.909 0.234 33.101 ;
     RECT  2.304 32.881 5.706 33.151 ;
     RECT  2.304 33.151 6.39 33.241 ;
     RECT  7.128 33.035 11.754 33.241 ;
     RECT  12.564 33.035 15.426 33.341 ;
     RECT  2.304 33.241 11.754 33.539 ;
     RECT  12.564 33.341 15.03 33.539 ;
     RECT  2.304 33.539 4.374 33.581 ;
     RECT  5.115 33.539 11.754 33.647 ;
     RECT  5.115 33.647 6.282 33.809 ;
     RECT  14.832 33.539 15.03 34.075 ;
     RECT  2.304 33.581 4.122 34.079 ;
     RECT  6.264 33.809 6.282 34.109 ;
     RECT  14.832 34.075 15.426 34.115 ;
     RECT  7.236 33.647 11.754 34.357 ;
     RECT  3.996 34.079 4.122 34.411 ;
     RECT  7.236 34.357 11.826 34.501 ;
     RECT  12.564 33.539 14.094 34.501 ;
     RECT  7.236 34.501 14.094 34.591 ;
     RECT  16.524 34.507 16.542 34.699 ;
     RECT  6.408 34.591 14.094 34.771 ;
     RECT  14.832 34.115 14.994 34.771 ;
     RECT  6.408 34.771 14.994 34.781 ;
     RECT  2.304 34.079 3.006 34.861 ;
     RECT  3.996 34.411 4.338 34.861 ;
     RECT  5.115 33.809 5.49 34.861 ;
     RECT  2.304 34.861 5.49 34.933 ;
     RECT  7.056 34.781 14.994 34.933 ;
     RECT  2.304 34.933 6.246 34.961 ;
     RECT  16.524 34.699 16.614 34.997 ;
     RECT  0.252 34.843 0.27 35.021 ;
     RECT  3.636 34.961 6.246 35.267 ;
     RECT  7.056 34.933 15.426 35.312 ;
     RECT  0.288 35.371 0.414 35.501 ;
     RECT  0.288 35.501 0.306 35.597 ;
     RECT  4.284 35.267 6.246 35.609 ;
     RECT  2.304 34.961 2.862 35.611 ;
     RECT  2.232 35.611 2.862 35.699 ;
     RECT  7.344 35.312 15.426 35.699 ;
     RECT  2.304 35.699 2.862 35.707 ;
     RECT  4.284 35.609 5.742 35.995 ;
     RECT  4.248 35.995 5.742 36.043 ;
     RECT  17.064 35.179 17.154 36.091 ;
     RECT  7.344 35.699 13.842 36.187 ;
     RECT  16.524 36.091 17.154 36.275 ;
     RECT  2.304 35.707 3.042 36.283 ;
     RECT  16.524 36.275 17.082 36.317 ;
     RECT  2.304 36.283 3.078 36.331 ;
     RECT  3.816 36.043 5.742 36.331 ;
     RECT  0.252 36.283 0.27 36.461 ;
     RECT  2.304 36.331 5.742 36.509 ;
     RECT  7.128 36.187 13.842 36.553 ;
     RECT  6.84 36.553 13.842 36.661 ;
     RECT  0.288 36.763 0.414 36.893 ;
     RECT  3.744 36.509 5.742 36.895 ;
     RECT  14.832 35.699 15.426 36.923 ;
     RECT  6.84 36.661 13.914 36.959 ;
     RECT  0.288 36.893 0.306 36.989 ;
     RECT  3.744 36.895 5.958 37.049 ;
     RECT  16.524 36.317 16.542 37.099 ;
     RECT  16.524 37.099 17.154 37.121 ;
     RECT  7.236 36.959 13.914 37.165 ;
     RECT  2.304 36.509 2.898 37.291 ;
     RECT  3.744 37.049 5.814 37.319 ;
     RECT  2.268 37.291 2.898 37.327 ;
     RECT  3.744 37.319 5.742 37.327 ;
     RECT  1.152 37.435 1.17 37.483 ;
     RECT  7.236 37.165 14.058 37.561 ;
     RECT  14.832 36.923 14.922 37.561 ;
     RECT  1.152 37.483 1.278 37.613 ;
     RECT  2.268 37.327 5.742 37.613 ;
     RECT  7.236 37.561 14.922 37.705 ;
     RECT  7.2 37.705 14.922 37.709 ;
     RECT  15.984 37.561 16.002 37.709 ;
     RECT  14.688 37.709 14.922 37.733 ;
     RECT  17.064 37.121 17.154 37.967 ;
     RECT  17.064 37.967 17.082 37.997 ;
     RECT  2.268 37.613 5.397 38.039 ;
     RECT  0.252 37.963 0.27 38.137 ;
     RECT  2.304 38.039 5.397 38.201 ;
     RECT  14.832 37.733 14.922 38.251 ;
     RECT  7.2 37.709 13.914 38.371 ;
     RECT  0.216 38.137 0.306 38.381 ;
     RECT  6.948 38.371 13.914 38.395 ;
     RECT  0.288 38.381 0.306 38.429 ;
     RECT  5.04 38.201 5.397 38.443 ;
     RECT  6.84 38.395 13.914 38.635 ;
     RECT  6.516 38.635 13.914 38.669 ;
     RECT  6.516 38.669 6.534 38.683 ;
     RECT  6.444 38.683 6.534 38.705 ;
     RECT  7.308 38.669 13.914 38.705 ;
     RECT  14.832 38.251 14.994 38.731 ;
     RECT  6.444 38.705 6.462 38.741 ;
     RECT  14.832 38.731 15.426 38.923 ;
     RECT  16.524 38.683 16.542 38.971 ;
     RECT  14.832 38.923 15.462 39.011 ;
     RECT  2.304 38.201 4.266 39.055 ;
     RECT  5.04 38.443 5.49 39.055 ;
     RECT  2.304 39.055 5.49 39.163 ;
     RECT  7.416 38.705 13.914 39.245 ;
     RECT  2.268 39.163 5.49 39.253 ;
     RECT  16.524 38.971 17.154 39.317 ;
     RECT  2.268 39.253 5.526 39.341 ;
     RECT  12.312 39.245 13.914 39.361 ;
     RECT  14.832 39.011 15.426 39.361 ;
     RECT  1.26 39.355 1.278 39.403 ;
     RECT  17.064 39.317 17.154 39.437 ;
     RECT  7.416 39.245 11.574 39.451 ;
     RECT  17.064 39.437 17.082 39.485 ;
     RECT  7.128 39.451 11.574 39.487 ;
     RECT  1.152 39.403 1.278 39.533 ;
     RECT  6.264 39.499 6.282 39.551 ;
     RECT  7.02 39.487 11.574 39.883 ;
     RECT  6.552 39.883 11.574 39.991 ;
     RECT  12.312 39.361 15.426 39.991 ;
     RECT  3.96 39.341 5.526 40.063 ;
     RECT  6.552 39.991 15.426 40.091 ;
     RECT  2.304 39.341 3.186 40.099 ;
     RECT  3.96 40.063 5.742 40.099 ;
     RECT  2.304 40.099 5.742 40.109 ;
     RECT  6.552 40.091 14.346 40.297 ;
     RECT  2.304 40.109 5.397 40.325 ;
     RECT  6.372 40.297 14.346 40.349 ;
     RECT  3.996 40.325 5.397 40.397 ;
     RECT  16.596 40.363 16.614 40.411 ;
     RECT  16.524 40.411 16.614 40.651 ;
     RECT  6.372 40.349 14.094 40.835 ;
     RECT  2.304 40.325 3.15 41.071 ;
     RECT  4.032 40.397 5.397 41.071 ;
     RECT  6.372 40.835 6.498 41.071 ;
     RECT  2.304 41.071 3.294 41.083 ;
     RECT  15.408 40.091 15.426 41.131 ;
     RECT  15.408 41.131 15.498 41.243 ;
     RECT  2.268 41.083 3.294 41.251 ;
     RECT  4.032 41.071 6.498 41.251 ;
     RECT  2.268 41.251 6.498 41.279 ;
     RECT  15.408 41.243 15.462 41.413 ;
     RECT  16.524 40.651 17.154 41.453 ;
     RECT  14.832 41.413 15.462 41.513 ;
     RECT  2.304 41.279 6.498 41.549 ;
     RECT  7.344 40.835 14.094 41.611 ;
     RECT  14.832 41.513 15.426 41.611 ;
     RECT  2.304 41.549 5.922 41.639 ;
     RECT  7.344 41.611 15.426 41.647 ;
     RECT  7.272 41.647 15.426 41.719 ;
     RECT  3.672 41.639 5.922 41.747 ;
     RECT  7.02 41.719 15.426 42.053 ;
     RECT  1.152 41.947 1.17 42.125 ;
     RECT  7.02 42.053 14.634 42.421 ;
     RECT  6.984 42.421 14.634 42.475 ;
     RECT  15.408 42.053 15.426 42.52 ;
     RECT  4.32 41.747 5.922 42.523 ;
     RECT  4.176 42.523 5.958 42.529 ;
     RECT  6.912 42.475 14.634 42.529 ;
     RECT  16.524 41.453 16.542 42.571 ;
     RECT  16.524 42.571 17.154 42.593 ;
     RECT  3.816 42.529 5.958 42.629 ;
     RECT  15.408 42.52 15.462 42.629 ;
     RECT  17.064 42.593 17.154 42.629 ;
     RECT  17.064 42.629 17.082 42.653 ;
     RECT  6.84 42.529 14.634 42.691 ;
     RECT  6.264 42.691 14.634 42.797 ;
     RECT  6.984 42.797 14.634 42.827 ;
     RECT  2.304 41.639 2.754 42.871 ;
     RECT  7.344 42.827 14.634 42.907 ;
     RECT  15.408 42.629 15.426 42.907 ;
     RECT  3.816 42.629 5.397 42.989 ;
     RECT  2.304 42.871 2.826 43.051 ;
     RECT  3.816 42.989 3.834 43.051 ;
     RECT  2.304 43.051 3.834 43.061 ;
     RECT  7.344 42.907 15.426 43.061 ;
     RECT  0.396 42.955 0.414 43.085 ;
     RECT  2.304 43.061 3.546 43.259 ;
     RECT  7.344 43.061 13.914 43.645 ;
     RECT  5.076 42.989 5.397 43.681 ;
     RECT  5.076 43.681 5.958 43.799 ;
     RECT  7.236 43.645 13.914 43.835 ;
     RECT  16.524 43.771 16.542 43.835 ;
     RECT  5.076 43.799 5.49 43.879 ;
     RECT  7.416 43.835 13.914 43.915 ;
     RECT  14.832 43.061 15.426 43.915 ;
     RECT  4.896 43.879 5.49 43.951 ;
     RECT  2.304 43.259 3.15 44.041 ;
     RECT  2.304 44.041 3.294 44.093 ;
     RECT  4.716 43.951 5.49 44.155 ;
     RECT  4.212 44.155 5.49 44.185 ;
     RECT  0.252 44.011 0.27 44.189 ;
     RECT  4.14 44.185 5.49 44.311 ;
     RECT  3.924 44.311 5.49 44.339 ;
     RECT  7.416 43.915 15.426 44.339 ;
     RECT  2.304 44.093 2.754 44.381 ;
     RECT  14.832 44.339 15.426 44.411 ;
     RECT  1.152 44.203 1.17 44.429 ;
     RECT  7.416 44.339 13.986 44.635 ;
     RECT  1.26 44.539 1.278 44.669 ;
     RECT  6.804 44.635 13.986 44.717 ;
     RECT  17.064 44.443 17.154 44.717 ;
     RECT  17.064 44.717 17.082 44.765 ;
     RECT  3.924 44.339 5.454 44.789 ;
     RECT  2.412 44.381 2.754 44.851 ;
     RECT  2.412 44.851 2.826 44.875 ;
     RECT  3.924 44.789 5.397 44.875 ;
     RECT  7.128 44.717 13.986 44.879 ;
     RECT  14.832 44.411 14.886 45.211 ;
     RECT  0.252 45.355 0.27 45.484 ;
     RECT  2.412 44.875 5.397 45.491 ;
     RECT  2.412 45.491 2.862 45.595 ;
     RECT  0.216 45.484 0.306 45.725 ;
     RECT  3.708 45.491 5.397 45.725 ;
     RECT  0.288 45.725 0.306 45.773 ;
     RECT  14.832 45.211 14.922 45.787 ;
     RECT  7.128 44.879 13.842 45.841 ;
     RECT  14.832 45.787 15.426 45.841 ;
     RECT  7.128 45.841 15.426 45.883 ;
     RECT  1.26 45.883 1.278 45.931 ;
     RECT  2.304 45.595 2.862 46.013 ;
     RECT  1.152 45.931 1.278 46.061 ;
     RECT  7.128 45.883 15.462 46.069 ;
     RECT  6.624 46.069 15.462 46.111 ;
     RECT  6.552 46.111 15.462 46.139 ;
     RECT  6.552 46.139 13.914 46.157 ;
     RECT  16.524 45.301 16.542 46.301 ;
     RECT  4.032 45.725 5.397 46.309 ;
     RECT  14.832 46.139 15.462 46.373 ;
     RECT  4.032 46.309 5.778 46.499 ;
     RECT  4.032 46.499 5.397 46.507 ;
     RECT  2.304 46.013 2.697 46.777 ;
     RECT  3.42 46.507 5.397 46.777 ;
     RECT  2.304 46.777 5.397 46.849 ;
     RECT  6.588 46.157 13.914 46.921 ;
     RECT  2.268 46.849 5.397 46.973 ;
     RECT  2.304 46.973 5.397 47.039 ;
     RECT  6.588 46.921 13.95 47.083 ;
     RECT  17.064 46.795 17.154 47.131 ;
     RECT  6.588 47.083 14.022 47.155 ;
     RECT  14.832 46.373 15.426 47.183 ;
     RECT  14.832 47.183 14.85 47.309 ;
     RECT  6.12 47.155 14.022 47.345 ;
     RECT  16.524 47.131 17.154 47.371 ;
     RECT  16.488 47.371 17.154 47.417 ;
     RECT  6.804 47.345 13.698 47.453 ;
     RECT  16.524 47.417 17.154 47.453 ;
     RECT  3.708 47.039 5.397 47.461 ;
     RECT  16.524 47.453 17.082 47.501 ;
     RECT  3.708 47.461 6.03 47.579 ;
     RECT  2.304 47.039 2.934 47.849 ;
     RECT  5.115 47.579 6.03 47.885 ;
     RECT  16.524 47.501 16.542 47.885 ;
     RECT  0.54 47.623 0.558 47.933 ;
     RECT  3.708 47.579 4.338 47.965 ;
     RECT  6.84 47.453 13.698 48.139 ;
     RECT  6.84 48.139 13.842 48.163 ;
     RECT  14.868 47.947 14.958 48.187 ;
     RECT  0.252 48.091 0.306 48.22 ;
     RECT  14.868 48.187 15.426 48.226 ;
     RECT  14.832 48.226 15.426 48.263 ;
     RECT  3.42 47.965 4.338 48.361 ;
     RECT  5.115 47.885 5.886 48.361 ;
     RECT  0.216 48.22 0.306 48.365 ;
     RECT  3.42 48.361 5.886 48.389 ;
     RECT  6.84 48.163 13.914 48.389 ;
     RECT  6.84 48.389 11.394 48.475 ;
     RECT  3.42 48.389 5.634 48.569 ;
     RECT  3.42 48.569 5.397 48.704 ;
     RECT  0.252 48.365 0.306 48.739 ;
     RECT  2.304 47.849 2.697 48.739 ;
     RECT  3.42 48.704 3.618 48.739 ;
     RECT  0.252 48.739 0.558 48.749 ;
     RECT  12.24 48.389 13.914 48.811 ;
     RECT  6.804 48.475 11.394 48.839 ;
     RECT  4.392 48.704 5.397 48.929 ;
     RECT  12.24 48.811 13.95 49.045 ;
     RECT  14.832 48.263 14.85 49.045 ;
     RECT  16.524 48.859 16.542 49.147 ;
     RECT  16.524 49.147 17.082 49.171 ;
     RECT  0.54 48.749 0.558 49.181 ;
     RECT  16.524 49.171 17.154 49.229 ;
     RECT  12.24 49.045 14.85 49.277 ;
     RECT  7.308 48.839 11.394 49.351 ;
     RECT  12.24 49.277 14.49 49.351 ;
     RECT  4.464 48.929 5.397 49.517 ;
     RECT  6.12 49.441 6.138 49.585 ;
     RECT  2.304 48.739 3.618 49.621 ;
     RECT  2.304 49.621 3.726 49.711 ;
     RECT  6.12 49.585 6.354 49.747 ;
     RECT  7.308 49.351 14.49 49.747 ;
     RECT  2.304 49.711 4.374 49.805 ;
     RECT  16.524 49.229 16.542 49.847 ;
     RECT  2.304 49.805 4.338 49.856 ;
     RECT  3.6 49.856 4.338 49.883 ;
     RECT  5.115 49.517 5.397 49.891 ;
     RECT  6.12 49.747 14.49 49.891 ;
     RECT  3.744 49.883 4.338 50.009 ;
     RECT  5.115 49.891 14.49 50.045 ;
     RECT  5.115 50.045 13.842 50.081 ;
     RECT  15.408 49.483 15.426 50.107 ;
     RECT  17.064 50.2 17.082 50.206 ;
     RECT  17.064 50.206 17.154 50.237 ;
     RECT  17.136 50.237 17.154 50.285 ;
     RECT  15.408 50.107 15.462 50.299 ;
     RECT  0.252 49.675 0.27 50.359 ;
     RECT  14.832 50.299 15.462 50.423 ;
     RECT  0.216 50.359 0.306 50.429 ;
     RECT  0.216 50.429 0.234 50.477 ;
     RECT  2.304 49.856 2.826 50.635 ;
     RECT  2.304 50.635 3.042 50.791 ;
     RECT  4.032 50.009 4.338 50.791 ;
     RECT  2.304 50.791 4.338 50.861 ;
     RECT  3.996 50.861 4.338 50.863 ;
     RECT  5.115 50.081 11.718 50.863 ;
     RECT  3.996 50.863 11.718 50.875 ;
     RECT  3.996 50.875 11.826 50.927 ;
     RECT  7.344 50.927 11.826 50.971 ;
     RECT  12.564 50.081 13.842 50.971 ;
     RECT  14.832 50.423 15.426 51.197 ;
     RECT  7.344 50.971 13.842 51.367 ;
     RECT  16.524 51.355 16.542 51.451 ;
     RECT  15.984 51.451 16.542 51.539 ;
     RECT  2.304 50.861 3.114 51.601 ;
     RECT  3.996 50.927 6.39 51.601 ;
     RECT  2.304 51.601 6.39 51.629 ;
     RECT  2.304 51.629 5.397 51.673 ;
     RECT  6.12 51.629 6.39 51.809 ;
     RECT  2.196 51.673 5.397 51.821 ;
     RECT  2.304 51.821 5.397 51.899 ;
     RECT  7.344 51.367 14.058 51.907 ;
     RECT  14.832 51.197 14.85 51.943 ;
     RECT  7.02 51.907 14.058 52.027 ;
     RECT  14.832 51.943 14.922 52.027 ;
     RECT  16.524 51.539 16.542 52.043 ;
     RECT  7.02 52.027 14.922 52.123 ;
     RECT  2.304 51.899 4.158 52.448 ;
     RECT  4.932 51.899 5.397 52.507 ;
     RECT  6.12 51.809 6.246 52.507 ;
     RECT  7.02 52.123 15.426 52.507 ;
     RECT  0.54 52.213 0.558 52.555 ;
     RECT  0.54 52.555 0.666 52.589 ;
     RECT  7.02 52.507 15.462 52.589 ;
     RECT  0.648 52.589 0.666 52.685 ;
     RECT  14.508 52.589 15.462 52.789 ;
     RECT  17.064 52.747 17.082 52.789 ;
     RECT  17.064 52.789 17.154 52.817 ;
     RECT  17.136 52.817 17.154 52.829 ;
     RECT  4.932 52.507 6.246 52.861 ;
     RECT  4.896 52.861 6.246 52.939 ;
     RECT  7.02 52.589 13.734 52.939 ;
     RECT  4.896 52.939 13.734 52.987 ;
     RECT  2.304 52.448 4.014 53.221 ;
     RECT  4.752 52.987 13.734 53.221 ;
     RECT  2.304 53.221 13.734 53.285 ;
     RECT  2.304 53.285 6.282 53.309 ;
     RECT  7.128 53.285 13.734 53.323 ;
     RECT  14.508 52.789 16.002 53.323 ;
     RECT  0.252 53.467 0.27 53.563 ;
     RECT  0.252 53.563 0.558 53.645 ;
     RECT  7.128 53.323 16.002 53.645 ;
     RECT  14.724 53.645 16.002 53.741 ;
     RECT  17.064 53.803 17.082 53.833 ;
     RECT  2.304 53.309 6.246 54.059 ;
     RECT  4.932 54.059 6.246 54.067 ;
     RECT  14.724 53.741 15.426 54.131 ;
     RECT  4.932 54.067 6.318 54.139 ;
     RECT  7.128 53.645 13.914 54.139 ;
     RECT  4.932 54.139 13.914 54.173 ;
     RECT  17.064 53.833 17.154 54.211 ;
     RECT  16.524 54.211 17.154 54.239 ;
     RECT  0.216 54.031 0.234 54.269 ;
     RECT  16.524 54.239 17.082 54.269 ;
     RECT  5.004 54.173 13.914 54.409 ;
     RECT  14.724 54.131 14.85 54.409 ;
     RECT  5.004 54.409 14.85 54.599 ;
     RECT  16.524 54.269 16.578 54.941 ;
     RECT  14.832 54.599 14.85 54.955 ;
     RECT  2.304 54.059 4.014 55.003 ;
     RECT  5.004 54.599 14.058 55.003 ;
     RECT  17.064 55.003 17.154 55.049 ;
     RECT  17.064 55.049 17.082 55.085 ;
     RECT  2.304 55.003 14.058 55.181 ;
     RECT  2.304 55.181 13.842 55.211 ;
     RECT  5.004 55.211 5.67 55.283 ;
     RECT  0.252 54.379 0.27 55.489 ;
     RECT  14.832 54.955 15.426 55.819 ;
     RECT  0.216 55.489 0.306 55.915 ;
     RECT  6.408 55.211 13.842 55.993 ;
     RECT  14.832 55.819 15.462 55.993 ;
     RECT  6.408 55.993 15.462 56.021 ;
     RECT  0.216 55.915 0.414 56.045 ;
     RECT  6.408 56.021 14.706 56.093 ;
     RECT  15.444 56.021 15.462 56.093 ;
     RECT  2.304 55.211 4.122 56.101 ;
     RECT  5.115 55.283 5.67 56.101 ;
     RECT  6.408 56.093 7.905 56.101 ;
     RECT  2.304 56.101 7.905 56.129 ;
     RECT  2.304 56.129 2.505 56.141 ;
     RECT  2.415 56.141 2.505 56.177 ;
     RECT  3.384 56.129 7.905 56.177 ;
     RECT  9.036 56.093 14.706 56.177 ;
     RECT  3.384 56.177 7.434 56.219 ;
     RECT  13.68 56.177 14.706 56.219 ;
     RECT  5.004 56.219 7.434 56.255 ;
     RECT  9.036 56.177 10.242 56.255 ;
     RECT  16.524 56.107 16.542 56.255 ;
     RECT  0.216 56.045 0.234 56.285 ;
     RECT  3.384 56.219 3.942 56.291 ;
     RECT  10.98 56.177 12.582 56.291 ;
     RECT  6.408 56.255 7.434 56.327 ;
     RECT  9.072 56.255 10.242 56.327 ;
     RECT  3.384 56.291 3.402 56.363 ;
     RECT  5.004 56.255 5.598 56.363 ;
     RECT  6.408 56.327 7.362 56.363 ;
     RECT  9.072 56.327 9.09 56.363 ;
     RECT  9.864 56.327 10.242 56.363 ;
     RECT  14.148 56.219 14.706 56.363 ;
     RECT  5.58 56.363 5.598 56.399 ;
     RECT  10.224 56.363 10.242 56.399 ;
     RECT  10.98 56.291 11.574 56.399 ;
     RECT  14.688 56.363 14.706 56.399 ;
     RECT  6.408 56.363 7.038 56.444 ;
     RECT  11.556 56.399 11.574 56.444 ;
     RECT  6.408 56.444 6.426 58.253 ;
    LAYER M4 ;
     RECT  0.192 2.208 0.205 2.232 ;
     RECT  0.156 2.232 0.205 2.352 ;
     RECT  0.192 2.352 0.205 2.376 ;
     RECT  0.156 2.376 0.205 2.448 ;
     RECT  0.192 2.448 0.205 2.472 ;
     RECT  0.156 2.472 0.205 2.544 ;
     RECT  0.192 2.544 0.205 2.568 ;
     RECT  0.156 2.568 0.205 2.64 ;
     RECT  0.192 2.64 0.205 2.664 ;
     RECT  0.156 2.664 0.205 2.736 ;
     RECT  0.192 2.736 0.205 2.76 ;
     RECT  0.156 2.76 0.205 2.88 ;
     RECT  0.192 2.88 0.205 2.904 ;
     RECT  0.156 2.904 0.205 2.976 ;
     RECT  0.192 2.976 0.205 3 ;
     RECT  0.156 3 0.205 3.072 ;
     RECT  0.192 3.072 0.205 3.096 ;
     RECT  0.156 3.096 0.205 3.168 ;
     RECT  0.192 3.168 0.205 3.192 ;
     RECT  0.156 3.192 0.205 3.264 ;
     RECT  0.192 3.264 0.205 3.288 ;
     RECT  0.156 3.288 0.205 3.36 ;
     RECT  0.192 3.36 0.205 3.384 ;
     RECT  0.156 3.384 0.205 3.504 ;
     RECT  0.192 3.504 0.205 3.528 ;
     RECT  0.156 3.528 0.205 3.6 ;
     RECT  0.192 3.6 0.205 3.624 ;
     RECT  0.156 3.624 0.205 3.696 ;
     RECT  0.192 3.696 0.205 3.72 ;
     RECT  0.156 3.72 0.205 3.792 ;
     RECT  0.192 3.792 0.205 3.816 ;
     RECT  0.156 3.816 0.205 3.888 ;
     RECT  0.192 3.888 0.205 3.912 ;
     RECT  0.156 3.912 0.205 4.032 ;
     RECT  0.192 4.032 0.205 4.056 ;
     RECT  0.156 4.056 0.205 4.128 ;
     RECT  0.192 4.128 0.205 4.152 ;
     RECT  0.156 4.152 0.205 4.224 ;
     RECT  0.192 4.224 0.205 4.248 ;
     RECT  0.156 4.248 0.205 4.32 ;
     RECT  0.192 4.32 0.205 4.344 ;
     RECT  0.156 4.344 0.205 4.416 ;
     RECT  0.192 4.416 0.205 4.44 ;
     RECT  0.156 4.44 0.205 4.56 ;
     RECT  0.192 4.56 0.205 4.584 ;
     RECT  0.156 4.584 0.205 4.656 ;
     RECT  0.192 4.656 0.205 4.68 ;
     RECT  0.156 4.68 0.205 4.752 ;
     RECT  0.192 4.752 0.205 4.776 ;
     RECT  0.156 4.776 0.205 4.848 ;
     RECT  0.192 4.848 0.205 4.872 ;
     RECT  0.156 4.872 0.205 4.944 ;
     RECT  0.192 4.944 0.205 4.968 ;
     RECT  0.156 4.968 0.205 5.088 ;
     RECT  0.192 5.088 0.205 5.112 ;
     RECT  0.156 5.112 0.205 5.184 ;
     RECT  0.192 5.184 0.205 5.208 ;
     RECT  0.156 5.208 0.205 5.28 ;
     RECT  0.192 5.28 0.205 5.304 ;
     RECT  0.156 5.304 0.205 5.376 ;
     RECT  0.192 5.376 0.205 5.4 ;
     RECT  0.156 5.4 0.205 5.472 ;
     RECT  0.192 5.472 0.205 5.496 ;
     RECT  0.156 5.496 0.205 5.616 ;
     RECT  0.192 5.616 0.205 5.64 ;
     RECT  0.156 5.64 0.205 5.712 ;
     RECT  0.192 5.712 0.205 5.736 ;
     RECT  0.156 5.736 0.205 5.808 ;
     RECT  0.192 5.808 0.205 5.832 ;
     RECT  0.156 5.832 0.205 5.904 ;
     RECT  0.192 5.904 0.205 5.928 ;
     RECT  0.156 5.928 0.205 6 ;
     RECT  0.192 6 0.205 6.024 ;
     RECT  0.156 6.024 0.205 6.096 ;
     RECT  0.192 6.096 0.205 6.12 ;
     RECT  0.156 6.12 0.205 6.24 ;
     RECT  0.192 6.24 0.205 6.264 ;
     RECT  0.156 6.264 0.205 6.336 ;
     RECT  0.192 6.336 0.205 6.36 ;
     RECT  0.156 6.36 0.205 6.432 ;
     RECT  0.192 6.432 0.205 6.456 ;
     RECT  0.156 6.456 0.205 6.528 ;
     RECT  0.192 6.528 0.205 6.552 ;
     RECT  0.156 6.552 0.205 6.624 ;
     RECT  0.192 6.624 0.205 6.648 ;
     RECT  0.156 6.648 0.205 6.768 ;
     RECT  0.192 6.768 0.205 6.792 ;
     RECT  0.156 6.792 0.205 6.864 ;
     RECT  0.192 6.864 0.205 6.888 ;
     RECT  0.156 6.888 0.205 6.96 ;
     RECT  0.192 6.96 0.205 6.984 ;
     RECT  0.156 6.984 0.205 7.056 ;
     RECT  0.192 7.056 0.205 7.08 ;
     RECT  0.156 7.08 0.205 7.152 ;
     RECT  0.192 7.152 0.205 7.176 ;
     RECT  0.156 7.176 0.205 7.296 ;
     RECT  0.192 7.296 0.205 7.32 ;
     RECT  0.156 7.32 0.205 7.392 ;
     RECT  0.192 7.392 0.205 7.416 ;
     RECT  0.156 7.416 0.205 7.488 ;
     RECT  0.192 7.488 0.205 7.512 ;
     RECT  0.156 7.512 0.205 7.584 ;
     RECT  0.192 7.584 0.205 7.608 ;
     RECT  0.156 7.608 0.205 7.68 ;
     RECT  0.192 7.68 0.205 7.704 ;
     RECT  0.156 7.704 0.205 7.824 ;
     RECT  0.192 7.824 0.205 7.848 ;
     RECT  0.156 7.848 0.205 7.92 ;
     RECT  0.192 7.92 0.205 7.944 ;
     RECT  0.156 7.944 0.205 8.016 ;
     RECT  0.192 8.016 0.205 8.04 ;
     RECT  0.156 8.04 0.205 8.112 ;
     RECT  0.192 8.112 0.205 8.136 ;
     RECT  0.156 8.136 0.205 8.208 ;
     RECT  0.192 8.208 0.205 8.232 ;
     RECT  0.156 8.232 0.205 8.352 ;
     RECT  0.192 8.352 0.205 8.376 ;
     RECT  0.156 8.376 0.205 8.448 ;
     RECT  0.192 8.448 0.205 8.472 ;
     RECT  0.156 8.472 0.205 8.544 ;
     RECT  0.192 8.544 0.205 8.568 ;
     RECT  0.156 8.568 0.205 8.64 ;
     RECT  0.192 8.64 0.205 8.664 ;
     RECT  0.156 8.664 0.205 8.736 ;
     RECT  0.192 8.736 0.205 8.76 ;
     RECT  0.156 8.76 0.205 8.88 ;
     RECT  0.192 8.88 0.205 8.904 ;
     RECT  0.156 8.904 0.205 8.976 ;
     RECT  0.192 8.976 0.205 9 ;
     RECT  0.156 9 0.205 9.072 ;
     RECT  0.192 9.072 0.205 9.096 ;
     RECT  0.156 9.096 0.205 9.168 ;
     RECT  0.192 9.168 0.205 9.192 ;
     RECT  0.156 9.192 0.205 9.264 ;
     RECT  0.192 9.264 0.205 9.288 ;
     RECT  0.156 9.288 0.205 9.36 ;
     RECT  0.192 9.36 0.205 9.384 ;
     RECT  0.156 9.384 0.205 9.504 ;
     RECT  0.192 9.504 0.205 9.528 ;
     RECT  0.156 9.528 0.205 9.6 ;
     RECT  0.192 9.6 0.205 9.624 ;
     RECT  0.156 9.624 0.205 9.696 ;
     RECT  0.192 9.696 0.205 9.72 ;
     RECT  0.156 9.72 0.205 9.792 ;
     RECT  0.192 9.792 0.205 9.816 ;
     RECT  0.156 9.816 0.205 9.888 ;
     RECT  0.192 9.888 0.205 9.912 ;
     RECT  0.156 9.912 0.205 10.032 ;
     RECT  0.192 10.032 0.205 10.056 ;
     RECT  0.156 10.056 0.205 10.128 ;
     RECT  0.192 10.128 0.205 10.152 ;
     RECT  0.156 10.152 0.205 10.224 ;
     RECT  0.192 10.224 0.205 10.248 ;
     RECT  0.156 10.248 0.205 10.32 ;
     RECT  0.192 10.32 0.205 10.344 ;
     RECT  0.156 10.344 0.205 10.416 ;
     RECT  0.192 10.416 0.205 10.44 ;
     RECT  0.156 10.44 0.205 10.56 ;
     RECT  0.192 10.56 0.205 10.584 ;
     RECT  0.156 10.584 0.205 10.656 ;
     RECT  0.192 10.656 0.205 10.68 ;
     RECT  0.156 10.68 0.205 10.752 ;
     RECT  0.192 10.752 0.205 10.776 ;
     RECT  0.156 10.776 0.205 10.848 ;
     RECT  0.192 10.848 0.205 10.872 ;
     RECT  0.156 10.872 0.205 10.944 ;
     RECT  0.192 10.944 0.205 10.968 ;
     RECT  0.156 10.968 0.205 11.088 ;
     RECT  0.192 11.088 0.205 11.112 ;
     RECT  0.156 11.112 0.205 11.184 ;
     RECT  0.192 11.184 0.205 11.208 ;
     RECT  0.156 11.208 0.205 11.28 ;
     RECT  0.192 11.28 0.205 11.304 ;
     RECT  0.156 11.304 0.205 11.376 ;
     RECT  0.192 11.376 0.205 11.4 ;
     RECT  0.156 11.4 0.205 11.472 ;
     RECT  0.192 11.472 0.205 11.496 ;
     RECT  0.156 11.496 0.205 11.616 ;
     RECT  0.192 11.616 0.205 11.64 ;
     RECT  0.156 11.64 0.205 11.712 ;
     RECT  0.192 11.712 0.205 11.736 ;
     RECT  0.156 11.736 0.205 11.808 ;
     RECT  0.192 11.808 0.205 11.832 ;
     RECT  0.156 11.832 0.205 11.904 ;
     RECT  0.192 11.904 0.205 11.928 ;
     RECT  0.156 11.928 0.205 12 ;
     RECT  0.192 12 0.205 12.024 ;
     RECT  0.156 12.024 0.205 12.096 ;
     RECT  0.192 12.096 0.205 12.12 ;
     RECT  0.156 12.12 0.205 12.24 ;
     RECT  0.192 12.24 0.205 12.264 ;
     RECT  0.156 12.264 0.205 12.336 ;
     RECT  0.192 12.336 0.205 12.36 ;
     RECT  0.156 12.36 0.205 12.432 ;
     RECT  0.192 12.432 0.205 12.456 ;
     RECT  0.156 12.456 0.205 12.528 ;
     RECT  0.192 12.528 0.205 12.552 ;
     RECT  0.156 12.552 0.205 12.624 ;
     RECT  0.192 12.624 0.205 12.648 ;
     RECT  0.156 12.648 0.205 12.768 ;
     RECT  0.192 12.768 0.205 12.792 ;
     RECT  0.156 12.792 0.205 12.864 ;
     RECT  0.192 12.864 0.205 12.888 ;
     RECT  0.156 12.888 0.205 12.96 ;
     RECT  0.192 12.96 0.205 12.984 ;
     RECT  0.156 12.984 0.205 13.056 ;
     RECT  0.192 13.056 0.205 13.08 ;
     RECT  0.156 13.08 0.205 13.152 ;
     RECT  0.192 13.152 0.205 13.176 ;
     RECT  0.156 13.176 0.205 13.296 ;
     RECT  0.192 13.296 0.205 13.32 ;
     RECT  0.156 13.32 0.205 13.392 ;
     RECT  0.192 13.392 0.205 13.416 ;
     RECT  0.156 13.416 0.205 13.488 ;
     RECT  0.192 13.488 0.205 13.512 ;
     RECT  0.156 13.512 0.205 13.584 ;
     RECT  0.192 13.584 0.205 13.608 ;
     RECT  0.156 13.608 0.205 13.68 ;
     RECT  0.192 13.68 0.205 13.704 ;
     RECT  0.156 13.704 0.205 13.824 ;
     RECT  0.192 13.824 0.205 13.848 ;
     RECT  0.156 13.848 0.205 13.92 ;
     RECT  0.192 13.92 0.205 13.944 ;
     RECT  0.156 13.944 0.205 14.016 ;
     RECT  0.192 14.016 0.205 14.04 ;
     RECT  0.156 14.04 0.205 14.112 ;
     RECT  0.192 14.112 0.205 14.136 ;
     RECT  0.156 14.136 0.205 14.208 ;
     RECT  0.192 14.208 0.205 14.232 ;
     RECT  0.156 14.232 0.205 14.352 ;
     RECT  0.192 14.352 0.205 14.376 ;
     RECT  0.156 14.376 0.205 14.448 ;
     RECT  0.192 14.448 0.205 14.472 ;
     RECT  0.156 14.472 0.205 14.544 ;
     RECT  0.192 14.544 0.205 14.568 ;
     RECT  0.156 14.568 0.205 14.64 ;
     RECT  0.192 14.64 0.205 14.664 ;
     RECT  0.156 14.664 0.205 14.736 ;
     RECT  0.192 14.736 0.205 14.76 ;
     RECT  0.156 14.76 0.205 14.88 ;
     RECT  0.192 14.88 0.205 14.904 ;
     RECT  0.156 14.904 0.205 14.976 ;
     RECT  0.192 14.976 0.205 15 ;
     RECT  0.156 15 0.205 15.072 ;
     RECT  0.192 15.072 0.205 15.096 ;
     RECT  0.156 15.096 0.205 15.168 ;
     RECT  0.192 15.168 0.205 15.192 ;
     RECT  0.156 15.192 0.205 15.264 ;
     RECT  0.192 15.264 0.205 15.288 ;
     RECT  0.156 15.288 0.205 15.36 ;
     RECT  0.192 15.36 0.205 15.384 ;
     RECT  0.156 15.384 0.205 15.504 ;
     RECT  0.192 15.504 0.205 15.528 ;
     RECT  0.156 15.528 0.205 15.6 ;
     RECT  0.192 15.6 0.205 15.624 ;
     RECT  0.156 15.624 0.205 15.696 ;
     RECT  0.192 15.696 0.205 15.72 ;
     RECT  0.156 15.72 0.205 15.792 ;
     RECT  0.192 15.792 0.205 15.816 ;
     RECT  0.156 15.816 0.205 15.888 ;
     RECT  0.192 15.888 0.205 15.912 ;
     RECT  0.156 15.912 0.205 16.032 ;
     RECT  0.192 16.032 0.205 16.056 ;
     RECT  0.156 16.056 0.205 16.128 ;
     RECT  0.192 16.128 0.205 16.152 ;
     RECT  0.156 16.152 0.205 16.224 ;
     RECT  0.192 16.224 0.205 16.248 ;
     RECT  0.156 16.248 0.205 16.32 ;
     RECT  0.192 16.32 0.205 16.344 ;
     RECT  0.156 16.344 0.205 16.416 ;
     RECT  0.192 16.416 0.205 16.44 ;
     RECT  0.156 16.44 0.205 16.56 ;
     RECT  0.192 16.56 0.205 16.584 ;
     RECT  0.156 16.584 0.205 16.656 ;
     RECT  0.192 16.656 0.205 16.68 ;
     RECT  0.156 16.68 0.205 16.752 ;
     RECT  0.192 16.752 0.205 16.776 ;
     RECT  0.156 16.776 0.205 16.848 ;
     RECT  0.192 16.848 0.205 16.872 ;
     RECT  0.156 16.872 0.205 16.944 ;
     RECT  0.192 16.944 0.205 16.968 ;
     RECT  0.156 16.968 0.205 17.088 ;
     RECT  0.192 17.088 0.205 17.112 ;
     RECT  0.156 17.112 0.205 17.184 ;
     RECT  0.192 17.184 0.205 17.208 ;
     RECT  0.156 17.208 0.205 17.28 ;
     RECT  0.192 17.28 0.205 17.304 ;
     RECT  0.156 17.304 0.205 17.376 ;
     RECT  0.192 17.376 0.205 17.4 ;
     RECT  0.156 17.4 0.205 17.472 ;
     RECT  0.192 17.472 0.205 17.496 ;
     RECT  0.156 17.496 0.205 17.616 ;
     RECT  0.192 17.616 0.205 17.64 ;
     RECT  0.156 17.64 0.205 17.712 ;
     RECT  0.192 17.712 0.205 17.736 ;
     RECT  0.156 17.736 0.205 17.808 ;
     RECT  0.192 17.808 0.205 17.832 ;
     RECT  0.156 17.832 0.205 17.904 ;
     RECT  0.192 17.904 0.205 17.928 ;
     RECT  0.156 17.928 0.205 18 ;
     RECT  0.192 18 0.205 18.024 ;
     RECT  0.156 18.024 0.205 18.096 ;
     RECT  0.192 18.096 0.205 18.12 ;
     RECT  0.156 18.12 0.205 18.24 ;
     RECT  0.192 18.24 0.205 18.264 ;
     RECT  0.156 18.264 0.205 18.336 ;
     RECT  0.192 18.336 0.205 18.36 ;
     RECT  0.156 18.36 0.205 18.432 ;
     RECT  0.192 18.432 0.205 18.456 ;
     RECT  0.156 18.456 0.205 18.528 ;
     RECT  0.192 18.528 0.205 18.552 ;
     RECT  0.156 18.552 0.205 18.624 ;
     RECT  0.192 18.624 0.205 18.648 ;
     RECT  0.156 18.648 0.205 18.768 ;
     RECT  0.192 18.768 0.205 18.792 ;
     RECT  0.156 18.792 0.205 18.864 ;
     RECT  0.192 18.864 0.205 18.888 ;
     RECT  0.156 18.888 0.205 18.96 ;
     RECT  0.192 18.96 0.205 18.984 ;
     RECT  0.156 18.984 0.205 19.056 ;
     RECT  0.192 19.056 0.205 19.08 ;
     RECT  0.156 19.08 0.205 19.152 ;
     RECT  0.192 19.152 0.205 19.176 ;
     RECT  0.156 19.176 0.205 19.296 ;
     RECT  0.192 19.296 0.205 19.32 ;
     RECT  0.156 19.32 0.205 19.392 ;
     RECT  0.192 19.392 0.205 19.416 ;
     RECT  0.156 19.416 0.205 19.488 ;
     RECT  0.192 19.488 0.205 19.512 ;
     RECT  0.156 19.512 0.205 19.584 ;
     RECT  0.192 19.584 0.205 19.608 ;
     RECT  0.156 19.608 0.205 19.68 ;
     RECT  0.192 19.68 0.205 19.704 ;
     RECT  0.156 19.704 0.205 19.824 ;
     RECT  0.192 19.824 0.205 19.848 ;
     RECT  0.156 19.848 0.205 19.92 ;
     RECT  0.192 19.92 0.205 19.944 ;
     RECT  0.156 19.944 0.205 20.016 ;
     RECT  0.192 20.016 0.205 20.04 ;
     RECT  0.156 20.04 0.205 20.112 ;
     RECT  0.192 20.112 0.205 20.136 ;
     RECT  0.156 20.136 0.205 20.208 ;
     RECT  0.192 20.208 0.205 20.232 ;
     RECT  0.156 20.232 0.205 20.352 ;
     RECT  0.192 20.352 0.205 20.376 ;
     RECT  0.156 20.376 0.205 20.448 ;
     RECT  0.192 20.448 0.205 20.472 ;
     RECT  0.156 20.472 0.205 20.544 ;
     RECT  0.192 20.544 0.205 20.568 ;
     RECT  0.156 20.568 0.205 20.64 ;
     RECT  0.192 20.64 0.205 20.664 ;
     RECT  0.156 20.664 0.205 20.736 ;
     RECT  0.192 20.736 0.205 20.76 ;
     RECT  0.156 20.76 0.205 20.88 ;
     RECT  0.192 20.88 0.205 20.904 ;
     RECT  0.156 20.904 0.205 20.976 ;
     RECT  0.192 20.976 0.205 21 ;
     RECT  0.156 21 0.205 21.072 ;
     RECT  0.192 21.072 0.205 21.096 ;
     RECT  0.156 21.096 0.205 21.168 ;
     RECT  0.192 21.168 0.205 21.192 ;
     RECT  0.156 21.192 0.205 21.264 ;
     RECT  0.192 21.264 0.205 21.288 ;
     RECT  0.156 21.288 0.205 21.36 ;
     RECT  0.192 21.36 0.205 21.384 ;
     RECT  0.156 21.384 0.205 21.504 ;
     RECT  0.192 21.504 0.205 21.528 ;
     RECT  0.156 21.528 0.205 21.6 ;
     RECT  0.192 21.6 0.205 21.624 ;
     RECT  0.156 21.624 0.205 21.696 ;
     RECT  0.192 21.696 0.205 21.72 ;
     RECT  0.156 21.72 0.205 21.792 ;
     RECT  0.192 21.792 0.205 21.816 ;
     RECT  0.156 21.816 0.205 21.888 ;
     RECT  0.192 21.888 0.205 21.912 ;
     RECT  0.156 21.912 0.205 22.032 ;
     RECT  0.192 22.032 0.205 22.056 ;
     RECT  0.156 22.056 0.205 22.128 ;
     RECT  0.192 22.128 0.205 22.152 ;
     RECT  0.156 22.152 0.205 22.224 ;
     RECT  0.192 22.224 0.205 22.248 ;
     RECT  0.156 22.248 0.205 22.32 ;
     RECT  0.192 22.32 0.205 22.344 ;
     RECT  0.156 22.344 0.205 22.416 ;
     RECT  0.192 22.416 0.205 22.44 ;
     RECT  0.156 22.44 0.205 22.56 ;
     RECT  0.192 22.56 0.205 22.584 ;
     RECT  0.156 22.584 0.205 22.656 ;
     RECT  0.192 22.656 0.205 22.68 ;
     RECT  0.156 22.68 0.205 22.752 ;
     RECT  0.192 22.752 0.205 22.776 ;
     RECT  0.156 22.776 0.205 22.848 ;
     RECT  0.192 22.848 0.205 22.872 ;
     RECT  0.156 22.872 0.205 22.944 ;
     RECT  0.192 22.944 0.205 22.968 ;
     RECT  0.156 22.968 0.205 23.088 ;
     RECT  0.192 23.088 0.205 23.112 ;
     RECT  0.156 23.112 0.205 23.184 ;
     RECT  0.192 23.184 0.205 23.208 ;
     RECT  0.156 23.208 0.205 23.28 ;
     RECT  0.192 23.28 0.205 23.304 ;
     RECT  0.156 23.304 0.205 23.376 ;
     RECT  0.192 23.376 0.205 23.4 ;
     RECT  0.156 23.4 0.205 23.472 ;
     RECT  0.192 23.472 0.205 23.496 ;
     RECT  0.156 23.496 0.205 23.616 ;
     RECT  0.192 23.616 0.205 23.64 ;
     RECT  0.156 23.64 0.205 23.712 ;
     RECT  0.192 23.712 0.205 23.736 ;
     RECT  0.156 23.736 0.205 23.808 ;
     RECT  0.192 23.808 0.205 23.832 ;
     RECT  0.156 23.832 0.205 23.904 ;
     RECT  0.192 23.904 0.205 23.928 ;
     RECT  0.156 23.928 0.205 24 ;
     RECT  0.192 24 0.205 24.024 ;
     RECT  0.156 24.024 0.205 24.096 ;
     RECT  0.192 24.096 0.205 24.12 ;
     RECT  0.156 24.12 0.205 24.24 ;
     RECT  0.192 24.24 0.205 24.264 ;
     RECT  0.156 24.264 0.205 24.336 ;
     RECT  0.192 24.336 0.205 24.36 ;
     RECT  0.156 24.36 0.205 24.432 ;
     RECT  0.192 24.432 0.205 24.456 ;
     RECT  0.156 24.456 0.205 24.528 ;
     RECT  0.192 24.528 0.205 24.552 ;
     RECT  0.156 24.552 0.205 24.624 ;
     RECT  0.192 24.624 0.205 24.648 ;
     RECT  0.156 24.648 0.205 24.768 ;
     RECT  0.192 24.768 0.205 24.792 ;
     RECT  0.156 24.792 0.205 24.864 ;
     RECT  0.192 24.864 0.205 24.888 ;
     RECT  0.156 24.888 0.205 24.96 ;
     RECT  0.192 24.96 0.205 24.984 ;
     RECT  0.156 24.984 0.205 25.056 ;
     RECT  0.192 25.056 0.205 25.08 ;
     RECT  0.156 25.08 0.205 25.152 ;
     RECT  0.192 25.152 0.205 25.176 ;
     RECT  0.156 25.176 0.205 25.296 ;
     RECT  0.192 25.296 0.205 25.32 ;
     RECT  0.156 25.32 0.205 25.392 ;
     RECT  0.192 25.392 0.205 25.416 ;
     RECT  0.156 25.416 0.205 25.488 ;
     RECT  0.192 25.488 0.205 25.512 ;
     RECT  0.156 25.512 0.205 25.584 ;
     RECT  0.192 25.584 0.205 25.608 ;
     RECT  0.156 25.608 0.205 25.68 ;
     RECT  0.192 25.68 0.205 25.704 ;
     RECT  0.156 25.704 0.205 25.824 ;
     RECT  0.192 25.824 0.205 25.848 ;
     RECT  0.156 25.848 0.205 25.92 ;
     RECT  0.192 25.92 0.205 25.944 ;
     RECT  0.156 25.944 0.205 26.016 ;
     RECT  0.192 26.016 0.205 26.04 ;
     RECT  0.156 26.04 0.205 26.112 ;
     RECT  0.192 26.112 0.205 26.136 ;
     RECT  0.156 26.136 0.205 26.208 ;
     RECT  0.192 26.208 0.205 26.232 ;
     RECT  0.156 26.232 0.205 26.352 ;
     RECT  0.192 26.352 0.205 26.376 ;
     RECT  0.156 26.376 0.205 26.448 ;
     RECT  0.192 26.448 0.205 26.472 ;
     RECT  0.156 26.472 0.205 26.544 ;
     RECT  0.192 26.544 0.205 26.568 ;
     RECT  0.156 26.568 0.205 26.64 ;
     RECT  0.192 26.64 0.205 26.664 ;
     RECT  0.156 26.664 0.205 26.736 ;
     RECT  0.192 26.736 0.205 26.76 ;
     RECT  0.156 26.76 0.205 26.88 ;
     RECT  0.192 26.88 0.205 26.904 ;
     RECT  0.156 26.904 0.205 26.976 ;
     RECT  0.192 26.976 0.205 27 ;
     RECT  0.156 27 0.205 27.072 ;
     RECT  0.192 27.072 0.205 27.096 ;
     RECT  0.156 27.096 0.205 27.168 ;
     RECT  0.192 27.168 0.205 27.192 ;
     RECT  0.156 27.192 0.205 27.264 ;
     RECT  0.192 27.264 0.205 27.288 ;
     RECT  0.156 27.288 0.205 27.36 ;
     RECT  0.192 27.36 0.205 27.384 ;
     RECT  0.156 27.384 0.205 27.504 ;
     RECT  0.192 27.504 0.205 27.528 ;
     RECT  0.156 27.528 0.205 27.6 ;
     RECT  0.192 27.6 0.205 27.624 ;
     RECT  0.156 27.624 0.205 27.696 ;
     RECT  0.192 27.696 0.205 27.72 ;
     RECT  0.156 27.72 0.205 27.792 ;
     RECT  0.192 27.792 0.205 27.816 ;
     RECT  0.156 27.816 0.205 27.888 ;
     RECT  0.192 27.888 0.205 27.912 ;
     RECT  0.156 27.912 0.205 28.032 ;
     RECT  0.192 28.032 0.205 28.056 ;
     RECT  0.156 28.056 0.205 28.128 ;
     RECT  0.192 28.128 0.205 28.152 ;
     RECT  0.156 28.152 0.205 28.224 ;
     RECT  0.192 28.224 0.205 28.248 ;
     RECT  0.156 28.248 0.205 28.32 ;
     RECT  0.192 28.32 0.205 28.344 ;
     RECT  0.156 28.344 0.205 28.416 ;
     RECT  0.192 28.416 0.205 28.44 ;
     RECT  0.156 28.44 0.205 28.56 ;
     RECT  0.192 28.56 0.205 28.584 ;
     RECT  0.156 28.584 0.205 28.656 ;
     RECT  0.192 28.656 0.205 28.68 ;
     RECT  0.156 28.68 0.205 28.752 ;
     RECT  0.192 28.752 0.205 28.776 ;
     RECT  0.156 28.776 0.205 28.848 ;
     RECT  0.192 28.848 0.205 28.872 ;
     RECT  0.156 28.872 0.205 28.944 ;
     RECT  0.192 28.944 0.205 28.968 ;
     RECT  0.156 28.968 0.205 29.088 ;
     RECT  0.192 29.088 0.205 29.112 ;
     RECT  0.156 29.112 0.205 29.184 ;
     RECT  0.192 29.184 0.205 29.208 ;
     RECT  0.156 29.208 0.205 29.28 ;
     RECT  0.192 29.28 0.205 29.304 ;
     RECT  0.156 29.304 0.205 29.376 ;
     RECT  0.192 29.376 0.205 29.4 ;
     RECT  0.156 29.4 0.205 29.472 ;
     RECT  0.192 29.472 0.205 29.496 ;
     RECT  0.156 29.496 0.205 29.616 ;
     RECT  0.192 29.616 0.205 29.64 ;
     RECT  0.156 29.64 0.205 29.712 ;
     RECT  0.192 29.712 0.205 29.736 ;
     RECT  0.156 29.736 0.205 29.808 ;
     RECT  0.192 29.808 0.205 29.832 ;
     RECT  0.156 29.832 0.205 29.904 ;
     RECT  0.192 29.904 0.205 29.928 ;
     RECT  0.156 29.928 0.205 30 ;
     RECT  0.192 30 0.205 30.024 ;
     RECT  0.156 30.024 0.205 30.096 ;
     RECT  0.192 30.096 0.205 30.12 ;
     RECT  0.156 30.12 0.205 30.24 ;
     RECT  0.192 30.24 0.205 30.264 ;
     RECT  0.156 30.264 0.205 30.336 ;
     RECT  0.192 30.336 0.205 30.36 ;
     RECT  0.156 30.36 0.205 30.432 ;
     RECT  0.192 30.432 0.205 30.456 ;
     RECT  0.156 30.456 0.205 30.528 ;
     RECT  0.192 30.528 0.205 30.552 ;
     RECT  0.156 30.552 0.205 30.624 ;
     RECT  0.192 30.624 0.205 30.648 ;
     RECT  0.156 30.648 0.205 30.768 ;
     RECT  0.192 30.768 0.205 30.792 ;
     RECT  0.156 30.792 0.205 30.864 ;
     RECT  0.192 30.864 0.205 30.888 ;
     RECT  0.156 30.888 0.205 30.96 ;
     RECT  0.192 30.96 0.205 30.984 ;
     RECT  0.156 30.984 0.205 31.056 ;
     RECT  0.192 31.056 0.205 31.08 ;
     RECT  0.156 31.08 0.205 31.152 ;
     RECT  0.192 31.152 0.205 31.176 ;
     RECT  0.156 31.176 0.205 31.296 ;
     RECT  0.192 31.296 0.205 31.32 ;
     RECT  0.156 31.32 0.205 31.392 ;
     RECT  0.192 31.392 0.205 31.416 ;
     RECT  0.156 31.416 0.205 31.488 ;
     RECT  0.192 31.488 0.205 31.512 ;
     RECT  0.156 31.512 0.205 31.584 ;
     RECT  0.192 31.584 0.205 31.608 ;
     RECT  0.156 31.608 0.205 31.68 ;
     RECT  0.192 31.68 0.205 31.704 ;
     RECT  0.156 31.704 0.205 31.824 ;
     RECT  0.192 31.824 0.205 31.848 ;
     RECT  0.156 31.848 0.205 31.92 ;
     RECT  0.192 31.92 0.205 31.944 ;
     RECT  0.156 31.944 0.205 32.016 ;
     RECT  0.192 32.016 0.205 32.04 ;
     RECT  0.156 32.04 0.205 32.112 ;
     RECT  0.192 32.112 0.205 32.136 ;
     RECT  0.156 32.136 0.205 32.208 ;
     RECT  0.192 32.208 0.205 32.232 ;
     RECT  0.156 32.232 0.205 32.352 ;
     RECT  0.192 32.352 0.205 32.376 ;
     RECT  0.156 32.376 0.205 32.448 ;
     RECT  0.192 32.448 0.205 32.472 ;
     RECT  0.156 32.472 0.205 32.544 ;
     RECT  0.192 32.544 0.205 32.568 ;
     RECT  0.156 32.568 0.205 32.64 ;
     RECT  0.192 32.64 0.205 32.664 ;
     RECT  0.156 32.664 0.205 32.736 ;
     RECT  0.192 32.736 0.205 32.76 ;
     RECT  0.156 32.76 0.205 32.88 ;
     RECT  0.192 32.88 0.205 32.904 ;
     RECT  0.156 32.904 0.205 32.976 ;
     RECT  0.192 32.976 0.205 33 ;
     RECT  0.156 33 0.205 33.072 ;
     RECT  0.192 33.072 0.205 33.096 ;
     RECT  0.156 33.096 0.205 33.168 ;
     RECT  0.192 33.168 0.205 33.192 ;
     RECT  0.156 33.192 0.205 33.264 ;
     RECT  0.192 33.264 0.205 33.288 ;
     RECT  0.156 33.288 0.205 33.36 ;
     RECT  0.192 33.36 0.205 33.384 ;
     RECT  0.156 33.384 0.205 33.504 ;
     RECT  0.192 33.504 0.205 33.528 ;
     RECT  0.156 33.528 0.205 33.6 ;
     RECT  0.192 33.6 0.205 33.624 ;
     RECT  0.156 33.624 0.205 33.696 ;
     RECT  0.192 33.696 0.205 33.72 ;
     RECT  0.156 33.72 0.205 33.792 ;
     RECT  0.192 33.792 0.205 33.816 ;
     RECT  0.156 33.816 0.205 33.888 ;
     RECT  0.192 33.888 0.205 33.912 ;
     RECT  0.156 33.912 0.205 34.032 ;
     RECT  0.192 34.032 0.205 34.056 ;
     RECT  0.156 34.056 0.205 34.128 ;
     RECT  0.192 34.128 0.205 34.152 ;
     RECT  0.156 34.152 0.205 34.224 ;
     RECT  0.192 34.224 0.205 34.248 ;
     RECT  0.156 34.248 0.205 34.32 ;
     RECT  0.192 34.32 0.205 34.344 ;
     RECT  0.156 34.344 0.205 34.416 ;
     RECT  0.192 34.416 0.205 34.44 ;
     RECT  0.156 34.44 0.205 34.56 ;
     RECT  0.192 34.56 0.205 34.584 ;
     RECT  0.156 34.584 0.205 34.656 ;
     RECT  0.192 34.656 0.205 34.68 ;
     RECT  0.156 34.68 0.205 34.752 ;
     RECT  0.192 34.752 0.205 34.776 ;
     RECT  0.156 34.776 0.205 34.848 ;
     RECT  0.192 34.848 0.205 34.872 ;
     RECT  0.156 34.872 0.205 34.944 ;
     RECT  0.192 34.944 0.205 34.968 ;
     RECT  0.156 34.968 0.205 35.088 ;
     RECT  0.192 35.088 0.205 35.112 ;
     RECT  0.156 35.112 0.205 35.184 ;
     RECT  0.192 35.184 0.205 35.208 ;
     RECT  0.156 35.208 0.205 35.28 ;
     RECT  0.192 35.28 0.205 35.304 ;
     RECT  0.156 35.304 0.205 35.376 ;
     RECT  0.192 35.376 0.205 35.4 ;
     RECT  0.156 35.4 0.205 35.472 ;
     RECT  0.192 35.472 0.205 35.496 ;
     RECT  0.156 35.496 0.205 35.616 ;
     RECT  0.192 35.616 0.205 35.64 ;
     RECT  0.156 35.64 0.205 35.712 ;
     RECT  0.192 35.712 0.205 35.736 ;
     RECT  0.156 35.736 0.205 35.808 ;
     RECT  0.192 35.808 0.205 35.832 ;
     RECT  0.156 35.832 0.205 35.904 ;
     RECT  0.192 35.904 0.205 35.928 ;
     RECT  0.156 35.928 0.205 36 ;
     RECT  0.192 36 0.205 36.024 ;
     RECT  0.156 36.024 0.205 36.096 ;
     RECT  0.192 36.096 0.205 36.12 ;
     RECT  0.156 36.12 0.205 36.24 ;
     RECT  0.192 36.24 0.205 36.264 ;
     RECT  0.156 36.264 0.205 36.336 ;
     RECT  0.192 36.336 0.205 36.36 ;
     RECT  0.156 36.36 0.205 36.432 ;
     RECT  0.192 36.432 0.205 36.456 ;
     RECT  0.156 36.456 0.205 36.528 ;
     RECT  0.192 36.528 0.205 36.552 ;
     RECT  0.156 36.552 0.205 36.624 ;
     RECT  0.192 36.624 0.205 36.648 ;
     RECT  0.156 36.648 0.205 36.768 ;
     RECT  0.192 36.768 0.205 36.792 ;
     RECT  0.156 36.792 0.205 36.864 ;
     RECT  0.192 36.864 0.205 36.888 ;
     RECT  0.156 36.888 0.205 36.96 ;
     RECT  0.192 36.96 0.205 36.984 ;
     RECT  0.156 36.984 0.205 37.056 ;
     RECT  0.192 37.056 0.205 37.08 ;
     RECT  0.156 37.08 0.205 37.152 ;
     RECT  0.192 37.152 0.205 37.176 ;
     RECT  0.156 37.176 0.205 37.296 ;
     RECT  0.192 37.296 0.205 37.32 ;
     RECT  0.156 37.32 0.205 37.392 ;
     RECT  0.192 37.392 0.205 37.416 ;
     RECT  0.156 37.416 0.205 37.488 ;
     RECT  0.192 37.488 0.205 37.512 ;
     RECT  0.156 37.512 0.205 37.584 ;
     RECT  0.192 37.584 0.205 37.608 ;
     RECT  0.156 37.608 0.205 37.68 ;
     RECT  0.192 37.68 0.205 37.704 ;
     RECT  0.156 37.704 0.205 37.824 ;
     RECT  0.192 37.824 0.205 37.848 ;
     RECT  0.156 37.848 0.205 37.92 ;
     RECT  0.192 37.92 0.205 37.944 ;
     RECT  0.156 37.944 0.205 38.016 ;
     RECT  0.192 38.016 0.205 38.04 ;
     RECT  0.156 38.04 0.205 38.112 ;
     RECT  0.192 38.112 0.205 38.136 ;
     RECT  0.156 38.136 0.205 38.208 ;
     RECT  0.192 38.208 0.205 38.232 ;
     RECT  0.156 38.232 0.205 38.352 ;
     RECT  0.192 38.352 0.205 38.376 ;
     RECT  0.156 38.376 0.205 38.448 ;
     RECT  0.192 38.448 0.205 38.472 ;
     RECT  0.156 38.472 0.205 38.544 ;
     RECT  0.192 38.544 0.205 38.568 ;
     RECT  0.156 38.568 0.205 38.64 ;
     RECT  0.192 38.64 0.205 38.664 ;
     RECT  0.156 38.664 0.205 38.736 ;
     RECT  0.192 38.736 0.205 38.76 ;
     RECT  0.156 38.76 0.205 38.88 ;
     RECT  0.192 38.88 0.205 38.904 ;
     RECT  0.156 38.904 0.205 38.976 ;
     RECT  0.192 38.976 0.205 39 ;
     RECT  0.156 39 0.205 39.072 ;
     RECT  0.192 39.072 0.205 39.096 ;
     RECT  0.156 39.096 0.205 39.168 ;
     RECT  0.192 39.168 0.205 39.192 ;
     RECT  0.156 39.192 0.205 39.264 ;
     RECT  0.192 39.264 0.205 39.288 ;
     RECT  0.156 39.288 0.205 39.36 ;
     RECT  0.192 39.36 0.205 39.384 ;
     RECT  0.156 39.384 0.205 39.504 ;
     RECT  0.192 39.504 0.205 39.528 ;
     RECT  0.156 39.528 0.205 39.6 ;
     RECT  0.192 39.6 0.205 39.624 ;
     RECT  0.156 39.624 0.205 39.696 ;
     RECT  0.192 39.696 0.205 39.72 ;
     RECT  0.156 39.72 0.205 39.792 ;
     RECT  0.192 39.792 0.205 39.816 ;
     RECT  0.156 39.816 0.205 39.888 ;
     RECT  0.192 39.888 0.205 39.912 ;
     RECT  0.156 39.912 0.205 40.032 ;
     RECT  0.192 40.032 0.205 40.056 ;
     RECT  0.156 40.056 0.205 40.128 ;
     RECT  0.192 40.128 0.205 40.152 ;
     RECT  0.156 40.152 0.205 40.224 ;
     RECT  0.192 40.224 0.205 40.248 ;
     RECT  0.156 40.248 0.205 40.32 ;
     RECT  0.192 40.32 0.205 40.344 ;
     RECT  0.156 40.344 0.205 40.416 ;
     RECT  0.192 40.416 0.205 40.44 ;
     RECT  0.156 40.44 0.205 40.56 ;
     RECT  0.192 40.56 0.205 40.584 ;
     RECT  0.156 40.584 0.205 40.656 ;
     RECT  0.192 40.656 0.205 40.68 ;
     RECT  0.156 40.68 0.205 40.752 ;
     RECT  0.192 40.752 0.205 40.776 ;
     RECT  0.156 40.776 0.205 40.848 ;
     RECT  0.192 40.848 0.205 40.872 ;
     RECT  0.156 40.872 0.205 40.944 ;
     RECT  0.192 40.944 0.205 40.968 ;
     RECT  0.156 40.968 0.205 41.088 ;
     RECT  0.192 41.088 0.205 41.112 ;
     RECT  0.156 41.112 0.205 41.184 ;
     RECT  0.192 41.184 0.205 41.208 ;
     RECT  0.156 41.208 0.205 41.28 ;
     RECT  0.192 41.28 0.205 41.304 ;
     RECT  0.156 41.304 0.205 41.376 ;
     RECT  0.192 41.376 0.205 41.4 ;
     RECT  0.156 41.4 0.205 41.472 ;
     RECT  0.192 41.472 0.205 41.496 ;
     RECT  0.156 41.496 0.205 41.616 ;
     RECT  0.192 41.616 0.205 41.64 ;
     RECT  0.156 41.64 0.205 41.712 ;
     RECT  0.192 41.712 0.205 41.736 ;
     RECT  0.156 41.736 0.205 41.808 ;
     RECT  0.192 41.808 0.205 41.832 ;
     RECT  0.156 41.832 0.205 41.904 ;
     RECT  0.192 41.904 0.205 41.928 ;
     RECT  0.156 41.928 0.205 42 ;
     RECT  0.192 42 0.205 42.024 ;
     RECT  0.156 42.024 0.205 42.096 ;
     RECT  0.192 42.096 0.205 42.12 ;
     RECT  0.156 42.12 0.205 42.24 ;
     RECT  0.192 42.24 0.205 42.264 ;
     RECT  0.156 42.264 0.205 42.336 ;
     RECT  0.192 42.336 0.205 42.36 ;
     RECT  0.156 42.36 0.205 42.432 ;
     RECT  0.192 42.432 0.205 42.456 ;
     RECT  0.156 42.456 0.205 42.528 ;
     RECT  0.192 42.528 0.205 42.552 ;
     RECT  0.156 42.552 0.205 42.624 ;
     RECT  0.192 42.624 0.205 42.648 ;
     RECT  0.156 42.648 0.205 42.768 ;
     RECT  0.192 42.768 0.205 42.792 ;
     RECT  0.156 42.792 0.205 42.864 ;
     RECT  0.192 42.864 0.205 42.888 ;
     RECT  0.156 42.888 0.205 42.96 ;
     RECT  0.192 42.96 0.205 42.984 ;
     RECT  0.156 42.984 0.205 43.056 ;
     RECT  0.192 43.056 0.205 43.08 ;
     RECT  0.156 43.08 0.205 43.152 ;
     RECT  0.192 43.152 0.205 43.176 ;
     RECT  0.156 43.176 0.205 43.296 ;
     RECT  0.192 43.296 0.205 43.32 ;
     RECT  0.156 43.32 0.205 43.392 ;
     RECT  0.192 43.392 0.205 43.416 ;
     RECT  0.156 43.416 0.205 43.488 ;
     RECT  0.192 43.488 0.205 43.512 ;
     RECT  0.156 43.512 0.205 43.584 ;
     RECT  0.192 43.584 0.205 43.608 ;
     RECT  0.156 43.608 0.205 43.68 ;
     RECT  0.192 43.68 0.205 43.704 ;
     RECT  0.156 43.704 0.205 43.824 ;
     RECT  0.192 43.824 0.205 43.848 ;
     RECT  0.156 43.848 0.205 43.92 ;
     RECT  0.192 43.92 0.205 43.944 ;
     RECT  0.156 43.944 0.205 44.016 ;
     RECT  0.192 44.016 0.205 44.04 ;
     RECT  0.156 44.04 0.205 44.112 ;
     RECT  0.192 44.112 0.205 44.136 ;
     RECT  0.156 44.136 0.205 44.208 ;
     RECT  0.192 44.208 0.205 44.232 ;
     RECT  0.156 44.232 0.205 44.352 ;
     RECT  0.192 44.352 0.205 44.376 ;
     RECT  0.156 44.376 0.205 44.448 ;
     RECT  0.192 44.448 0.205 44.472 ;
     RECT  0.156 44.472 0.205 44.544 ;
     RECT  0.192 44.544 0.205 44.568 ;
     RECT  0.156 44.568 0.205 44.64 ;
     RECT  0.192 44.64 0.205 44.664 ;
     RECT  0.156 44.664 0.205 44.736 ;
     RECT  0.192 44.736 0.205 44.76 ;
     RECT  0.156 44.76 0.205 44.88 ;
     RECT  0.192 44.88 0.205 44.904 ;
     RECT  0.156 44.904 0.205 44.976 ;
     RECT  0.192 44.976 0.205 45 ;
     RECT  0.156 45 0.205 45.072 ;
     RECT  0.192 45.072 0.205 45.096 ;
     RECT  0.156 45.096 0.205 45.168 ;
     RECT  0.192 45.168 0.205 45.192 ;
     RECT  0.156 45.192 0.205 45.264 ;
     RECT  0.192 45.264 0.205 45.288 ;
     RECT  0.156 45.288 0.205 45.36 ;
     RECT  0.192 45.36 0.205 45.384 ;
     RECT  0.156 45.384 0.205 45.504 ;
     RECT  0.192 45.504 0.205 45.528 ;
     RECT  0.156 45.528 0.205 45.6 ;
     RECT  0.192 45.6 0.205 45.624 ;
     RECT  0.156 45.624 0.205 45.696 ;
     RECT  0.192 45.696 0.205 45.72 ;
     RECT  0.156 45.72 0.205 45.792 ;
     RECT  0.192 45.792 0.205 45.816 ;
     RECT  0.156 45.816 0.205 45.888 ;
     RECT  0.192 45.888 0.205 45.912 ;
     RECT  0.156 45.912 0.205 46.032 ;
     RECT  0.192 46.032 0.205 46.056 ;
     RECT  0.156 46.056 0.205 46.128 ;
     RECT  0.192 46.128 0.205 46.152 ;
     RECT  0.156 46.152 0.205 46.224 ;
     RECT  0.192 46.224 0.205 46.248 ;
     RECT  0.156 46.248 0.205 46.32 ;
     RECT  0.192 46.32 0.205 46.344 ;
     RECT  0.156 46.344 0.205 46.416 ;
     RECT  0.192 46.416 0.205 46.44 ;
     RECT  0.156 46.44 0.205 46.56 ;
     RECT  0.192 46.56 0.205 46.584 ;
     RECT  0.156 46.584 0.205 46.656 ;
     RECT  0.192 46.656 0.205 46.68 ;
     RECT  0.156 46.68 0.205 46.752 ;
     RECT  0.192 46.752 0.205 46.776 ;
     RECT  0.156 46.776 0.205 46.848 ;
     RECT  0.192 46.848 0.205 46.872 ;
     RECT  0.156 46.872 0.205 46.944 ;
     RECT  0.192 46.944 0.205 46.968 ;
     RECT  0.156 46.968 0.205 47.088 ;
     RECT  0.192 47.088 0.205 47.112 ;
     RECT  0.156 47.112 0.205 47.184 ;
     RECT  0.192 47.184 0.205 47.208 ;
     RECT  0.156 47.208 0.205 47.28 ;
     RECT  0.192 47.28 0.205 47.304 ;
     RECT  0.156 47.304 0.205 47.376 ;
     RECT  0.192 47.376 0.205 47.4 ;
     RECT  0.156 47.4 0.205 47.472 ;
     RECT  0.192 47.472 0.205 47.496 ;
     RECT  0.156 47.496 0.205 47.616 ;
     RECT  0.192 47.616 0.205 47.64 ;
     RECT  0.156 47.64 0.205 47.712 ;
     RECT  0.192 47.712 0.205 47.736 ;
     RECT  0.156 47.736 0.205 47.808 ;
     RECT  0.192 47.808 0.205 47.832 ;
     RECT  0.156 47.832 0.205 47.904 ;
     RECT  0.192 47.904 0.205 47.928 ;
     RECT  0.156 47.928 0.205 48 ;
     RECT  0.192 48 0.205 48.024 ;
     RECT  0.156 48.024 0.205 48.096 ;
     RECT  0.192 48.096 0.205 48.12 ;
     RECT  0.156 48.12 0.205 48.24 ;
     RECT  0.192 48.24 0.205 48.264 ;
     RECT  0.156 48.264 0.205 48.336 ;
     RECT  0.192 48.336 0.205 48.36 ;
     RECT  0.156 48.36 0.205 48.432 ;
     RECT  0.192 48.432 0.205 48.456 ;
     RECT  0.156 48.456 0.205 48.528 ;
     RECT  0.192 48.528 0.205 48.552 ;
     RECT  0.156 48.552 0.205 48.624 ;
     RECT  0.192 48.624 0.205 48.648 ;
     RECT  0.156 48.648 0.205 48.768 ;
     RECT  0.192 48.768 0.205 48.792 ;
     RECT  0.156 48.792 0.205 48.864 ;
     RECT  0.192 48.864 0.205 48.888 ;
     RECT  0.156 48.888 0.205 48.96 ;
     RECT  0.192 48.96 0.205 48.984 ;
     RECT  0.156 48.984 0.205 49.056 ;
     RECT  0.192 49.056 0.205 49.08 ;
     RECT  0.156 49.08 0.205 49.152 ;
     RECT  0.192 49.152 0.205 49.176 ;
     RECT  0.156 49.176 0.205 49.296 ;
     RECT  0.192 49.296 0.205 49.32 ;
     RECT  0.156 49.32 0.205 49.392 ;
     RECT  0.192 49.392 0.205 49.416 ;
     RECT  0.156 49.416 0.205 49.488 ;
     RECT  0.192 49.488 0.205 49.512 ;
     RECT  0.156 49.512 0.205 49.584 ;
     RECT  0.192 49.584 0.205 49.608 ;
     RECT  0.156 49.608 0.205 49.68 ;
     RECT  0.192 49.68 0.205 49.704 ;
     RECT  0.156 49.704 0.205 49.824 ;
     RECT  0.192 49.824 0.205 49.848 ;
     RECT  0.156 49.848 0.205 49.92 ;
     RECT  0.192 49.92 0.205 49.944 ;
     RECT  0.156 49.944 0.205 50.016 ;
     RECT  0.192 50.016 0.205 50.04 ;
     RECT  0.156 50.04 0.205 50.112 ;
     RECT  0.192 50.112 0.205 50.136 ;
     RECT  0.156 50.136 0.205 50.208 ;
     RECT  0.192 50.208 0.205 50.232 ;
     RECT  0.156 50.232 0.205 50.352 ;
     RECT  0.192 50.352 0.205 50.376 ;
     RECT  0.156 50.376 0.205 50.448 ;
     RECT  0.192 50.448 0.205 50.472 ;
     RECT  0.156 50.472 0.205 50.544 ;
     RECT  0.192 50.544 0.205 50.568 ;
     RECT  0.156 50.568 0.205 50.64 ;
     RECT  0.192 50.64 0.205 50.664 ;
     RECT  0.156 50.664 0.205 50.736 ;
     RECT  0.192 50.736 0.205 50.76 ;
     RECT  0.156 50.76 0.205 50.88 ;
     RECT  0.192 50.88 0.205 50.904 ;
     RECT  0.156 50.904 0.205 50.976 ;
     RECT  0.192 50.976 0.205 51 ;
     RECT  0.156 51 0.205 51.072 ;
     RECT  0.192 51.072 0.205 51.096 ;
     RECT  0.156 51.096 0.205 51.168 ;
     RECT  0.192 51.168 0.205 51.192 ;
     RECT  0.156 51.192 0.205 51.264 ;
     RECT  0.192 51.264 0.205 51.288 ;
     RECT  0.156 51.288 0.205 51.36 ;
     RECT  0.192 51.36 0.205 51.384 ;
     RECT  0.156 51.384 0.205 51.504 ;
     RECT  0.192 51.504 0.205 51.528 ;
     RECT  0.156 51.528 0.205 51.6 ;
     RECT  0.192 51.6 0.205 51.624 ;
     RECT  0.156 51.624 0.205 51.696 ;
     RECT  0.192 51.696 0.205 51.72 ;
     RECT  0.156 51.72 0.205 51.792 ;
     RECT  0.192 51.792 0.205 51.816 ;
     RECT  0.156 51.816 0.205 51.888 ;
     RECT  0.192 51.888 0.205 51.912 ;
     RECT  0.156 51.912 0.205 52.032 ;
     RECT  0.192 52.032 0.205 52.056 ;
     RECT  0.156 52.056 0.205 52.128 ;
     RECT  0.192 52.128 0.205 52.152 ;
     RECT  0.156 52.152 0.205 52.224 ;
     RECT  0.192 52.224 0.205 52.248 ;
     RECT  0.156 52.248 0.205 52.32 ;
     RECT  0.192 52.32 0.205 52.344 ;
     RECT  0.156 52.344 0.205 52.416 ;
     RECT  0.192 52.416 0.205 52.44 ;
     RECT  0.156 52.44 0.205 52.56 ;
     RECT  0.192 52.56 0.205 52.584 ;
     RECT  0.156 52.584 0.205 52.656 ;
     RECT  0.192 52.656 0.205 52.68 ;
     RECT  0.156 52.68 0.205 52.752 ;
     RECT  0.192 52.752 0.205 52.776 ;
     RECT  0.156 52.776 0.205 52.848 ;
     RECT  0.192 52.848 0.205 52.872 ;
     RECT  0.156 52.872 0.205 52.944 ;
     RECT  0.192 52.944 0.205 52.968 ;
     RECT  0.156 52.968 0.205 53.088 ;
     RECT  0.192 53.088 0.205 53.112 ;
     RECT  0.156 53.112 0.205 53.184 ;
     RECT  0.192 53.184 0.205 53.208 ;
     RECT  0.156 53.208 0.205 53.28 ;
     RECT  0.192 53.28 0.205 53.304 ;
     RECT  0.156 53.304 0.205 53.376 ;
     RECT  0.192 53.376 0.205 53.4 ;
     RECT  0.156 53.4 0.205 53.472 ;
     RECT  0.192 53.472 0.205 53.496 ;
     RECT  0.156 53.496 0.205 53.616 ;
     RECT  0.192 53.616 0.205 53.64 ;
     RECT  0.156 53.64 0.205 53.712 ;
     RECT  0.192 53.712 0.205 53.736 ;
     RECT  0.156 53.736 0.205 53.808 ;
     RECT  0.192 53.808 0.205 53.832 ;
     RECT  0.156 53.832 0.205 53.904 ;
     RECT  0.192 53.904 0.205 53.928 ;
     RECT  0.156 53.928 0.205 54 ;
     RECT  0.192 54 0.205 54.024 ;
     RECT  0.156 54.024 0.205 54.096 ;
     RECT  0.192 54.096 0.205 54.12 ;
     RECT  0.156 54.12 0.205 54.24 ;
     RECT  0.192 54.24 0.205 54.264 ;
     RECT  0.156 54.264 0.205 54.336 ;
     RECT  0.192 54.336 0.205 54.36 ;
     RECT  0.156 54.36 0.205 54.432 ;
     RECT  0.192 54.432 0.205 54.456 ;
     RECT  0.156 54.456 0.205 54.528 ;
     RECT  0.192 54.528 0.205 54.552 ;
     RECT  0.156 54.552 0.205 54.624 ;
     RECT  0.192 54.624 0.205 54.648 ;
     RECT  0.156 54.648 0.205 54.768 ;
     RECT  0.192 54.768 0.205 54.792 ;
     RECT  0.156 54.792 0.205 54.864 ;
     RECT  0.192 54.864 0.205 54.888 ;
     RECT  0.156 54.888 0.205 54.96 ;
     RECT  0.192 54.96 0.205 54.984 ;
     RECT  0.156 54.984 0.205 55.056 ;
     RECT  0.192 55.056 0.205 55.08 ;
     RECT  0.156 55.08 0.205 55.152 ;
     RECT  0.192 55.152 0.205 55.176 ;
     RECT  0.156 55.176 0.205 55.296 ;
     RECT  0.192 55.296 0.205 55.32 ;
     RECT  0.156 55.32 0.205 55.392 ;
     RECT  0.192 55.392 0.205 55.416 ;
     RECT  0.156 55.416 0.205 55.488 ;
     RECT  0.192 55.488 0.205 55.512 ;
     RECT  0.156 55.512 0.205 55.584 ;
     RECT  0.192 55.584 0.205 55.608 ;
     RECT  0.156 55.608 0.205 55.68 ;
     RECT  0.192 55.68 0.205 55.704 ;
     RECT  0.156 55.704 0.205 55.824 ;
     RECT  0.192 55.824 0.205 55.848 ;
     RECT  0.156 55.848 0.205 55.92 ;
     RECT  0.192 55.92 0.205 55.944 ;
     RECT  0.156 55.944 0.205 56.016 ;
     RECT  0.192 56.016 0.205 56.04 ;
     RECT  0.156 56.04 0.205 56.112 ;
     RECT  0.192 56.112 0.205 56.136 ;
     RECT  0.205 2.208 2.408 56.28 ;
     RECT  2.408 2.148 2.512 56.28 ;
     RECT  2.512 2.208 3.413 56.28 ;
     RECT  3.413 2.208 3.593 56.04 ;
     RECT  3.593 2.208 5.108 55.896 ;
     RECT  5.108 2.148 5.212 56.172 ;
     RECT  5.212 2.418 5.404 55.902 ;
     RECT  5.389 57.6 5.603 57.624 ;
     RECT  5.404 9.792 6.38 29.064 ;
     RECT  5.404 30.576 6.38 33.096 ;
     RECT  6.38 9.792 6.397 33.096 ;
     RECT  5.404 34.08 6.397 37.992 ;
     RECT  5.404 2.592 6.433 8.808 ;
     RECT  6.397 9.792 6.433 37.992 ;
     RECT  5.404 39.024 6.433 46.536 ;
     RECT  6.433 9.792 6.577 46.536 ;
     RECT  5.404 47.664 6.577 55.8 ;
     RECT  6.433 2.256 7.333 8.808 ;
     RECT  6.577 9.792 7.333 55.8 ;
     RECT  7.333 2.256 7.441 55.8 ;
     RECT  7.441 2.256 7.657 56.04 ;
     RECT  7.657 2.256 7.808 56.088 ;
     RECT  7.808 2.148 7.912 56.172 ;
     RECT  7.912 2.304 9.061 56.088 ;
     RECT  9.061 2.304 10.001 56.28 ;
     RECT  10.001 2.304 10.508 56.172 ;
     RECT  10.508 2.148 10.612 56.172 ;
     RECT  10.612 2.304 10.804 55.902 ;
     RECT  6.397 58.224 11.413 58.248 ;
     RECT  11.413 58.08 11.459 58.248 ;
     RECT  10.804 2.304 11.729 55.848 ;
     RECT  11.459 58.08 11.891 58.104 ;
     RECT  11.729 2.736 13.208 55.8 ;
     RECT  13.208 2.148 13.312 56.172 ;
     RECT  13.312 2.418 13.504 55.902 ;
     RECT  13.504 2.784 14.461 55.902 ;
     RECT  14.461 2.784 14.821 56.04 ;
     RECT  14.821 2.64 15.397 56.04 ;
     RECT  15.397 2.208 16.513 56.04 ;
     RECT  16.513 2.208 17.088 2.232 ;
     RECT  16.513 2.232 17.1 2.352 ;
     RECT  16.513 2.352 17.088 2.376 ;
     RECT  16.513 2.376 17.1 2.448 ;
     RECT  16.513 2.448 17.088 2.472 ;
     RECT  16.513 2.472 17.1 2.544 ;
     RECT  16.513 2.544 17.088 2.568 ;
     RECT  16.513 2.568 17.1 2.64 ;
     RECT  16.513 2.64 17.088 2.664 ;
     RECT  16.513 2.664 17.1 2.736 ;
     RECT  16.513 2.736 17.088 2.76 ;
     RECT  16.513 2.76 17.1 2.88 ;
     RECT  16.513 2.88 17.088 2.904 ;
     RECT  16.513 2.904 17.1 2.976 ;
     RECT  16.513 2.976 17.088 3 ;
     RECT  16.513 3 17.1 3.072 ;
     RECT  16.513 3.072 17.088 3.096 ;
     RECT  16.513 3.096 17.1 3.168 ;
     RECT  16.513 3.168 17.088 3.192 ;
     RECT  16.513 3.192 17.1 3.264 ;
     RECT  16.513 3.264 17.088 3.288 ;
     RECT  16.513 3.288 17.1 3.408 ;
     RECT  16.513 3.408 17.088 3.432 ;
     RECT  16.513 3.432 17.1 3.504 ;
     RECT  16.513 3.504 17.088 3.528 ;
     RECT  16.513 3.528 17.1 3.6 ;
     RECT  16.513 3.6 17.088 3.624 ;
     RECT  16.513 3.624 17.1 3.696 ;
     RECT  16.513 3.696 17.088 3.72 ;
     RECT  16.513 3.72 17.1 3.792 ;
     RECT  16.513 3.792 17.088 3.816 ;
     RECT  16.513 3.816 17.1 3.936 ;
     RECT  16.513 3.936 17.088 3.96 ;
     RECT  16.513 3.96 17.1 4.032 ;
     RECT  16.513 4.032 17.088 4.056 ;
     RECT  16.513 4.056 17.1 4.128 ;
     RECT  16.513 4.128 17.088 4.152 ;
     RECT  16.513 4.152 17.1 4.224 ;
     RECT  16.513 4.224 17.088 4.248 ;
     RECT  16.513 4.248 17.1 4.32 ;
     RECT  16.513 4.32 17.088 4.344 ;
     RECT  16.513 4.344 17.1 4.416 ;
     RECT  16.513 4.416 17.088 4.44 ;
     RECT  16.513 4.44 17.1 4.56 ;
     RECT  16.513 4.56 17.088 4.584 ;
     RECT  16.513 4.584 17.1 4.656 ;
     RECT  16.513 4.656 17.088 4.68 ;
     RECT  16.513 4.68 17.1 4.752 ;
     RECT  16.513 4.752 17.088 4.776 ;
     RECT  16.513 4.776 17.1 4.848 ;
     RECT  16.513 4.848 17.088 4.872 ;
     RECT  16.513 4.872 17.1 4.944 ;
     RECT  16.513 4.944 17.088 4.968 ;
     RECT  16.513 4.968 17.1 5.088 ;
     RECT  16.513 5.088 17.088 5.112 ;
     RECT  16.513 5.112 17.1 5.184 ;
     RECT  16.513 5.184 17.088 5.208 ;
     RECT  16.513 5.208 17.1 5.28 ;
     RECT  16.513 5.28 17.088 5.304 ;
     RECT  16.513 5.304 17.1 5.376 ;
     RECT  16.513 5.376 17.088 5.4 ;
     RECT  16.513 5.4 17.1 5.472 ;
     RECT  16.513 5.472 17.088 5.496 ;
     RECT  16.513 5.496 17.1 5.616 ;
     RECT  16.513 5.616 17.088 5.64 ;
     RECT  16.513 5.64 17.1 5.712 ;
     RECT  16.513 5.712 17.088 5.736 ;
     RECT  16.513 5.736 17.1 5.808 ;
     RECT  16.513 5.808 17.088 5.832 ;
     RECT  16.513 5.832 17.1 5.904 ;
     RECT  16.513 5.904 17.088 5.928 ;
     RECT  16.513 5.928 17.1 6 ;
     RECT  16.513 6 17.088 6.024 ;
     RECT  16.513 6.024 17.1 6.144 ;
     RECT  16.513 6.144 17.088 6.168 ;
     RECT  16.513 6.168 17.1 6.24 ;
     RECT  16.513 6.24 17.088 6.264 ;
     RECT  16.513 6.264 17.1 6.336 ;
     RECT  16.513 6.336 17.088 6.36 ;
     RECT  16.513 6.36 17.1 6.432 ;
     RECT  16.513 6.432 17.088 6.456 ;
     RECT  16.513 6.456 17.1 6.528 ;
     RECT  16.513 6.528 17.088 6.552 ;
     RECT  16.513 6.552 17.1 6.672 ;
     RECT  16.513 6.672 17.088 6.696 ;
     RECT  16.513 6.696 17.1 6.768 ;
     RECT  16.513 6.768 17.088 6.792 ;
     RECT  16.513 6.792 17.1 6.864 ;
     RECT  16.513 6.864 17.088 6.888 ;
     RECT  16.513 6.888 17.1 6.96 ;
     RECT  16.513 6.96 17.088 6.984 ;
     RECT  16.513 6.984 17.1 7.056 ;
     RECT  16.513 7.056 17.088 7.08 ;
     RECT  16.513 7.08 17.1 7.2 ;
     RECT  16.513 7.2 17.088 7.224 ;
     RECT  16.513 7.224 17.1 7.296 ;
     RECT  16.513 7.296 17.088 7.32 ;
     RECT  16.513 7.32 17.1 7.392 ;
     RECT  16.513 7.392 17.088 7.416 ;
     RECT  16.513 7.416 17.1 7.488 ;
     RECT  16.513 7.488 17.088 7.512 ;
     RECT  16.513 7.512 17.1 7.584 ;
     RECT  16.513 7.584 17.088 7.608 ;
     RECT  16.513 7.608 17.1 7.728 ;
     RECT  16.513 7.728 17.088 7.752 ;
     RECT  16.513 7.752 17.1 7.824 ;
     RECT  16.513 7.824 17.088 7.848 ;
     RECT  16.513 7.848 17.1 7.92 ;
     RECT  16.513 7.92 17.088 7.944 ;
     RECT  16.513 7.944 17.1 8.016 ;
     RECT  16.513 8.016 17.088 8.04 ;
     RECT  16.513 8.04 17.1 8.112 ;
     RECT  16.513 8.112 17.088 8.136 ;
     RECT  16.513 8.136 17.1 8.256 ;
     RECT  16.513 8.256 17.088 8.28 ;
     RECT  16.513 8.28 17.1 8.352 ;
     RECT  16.513 8.352 17.088 8.376 ;
     RECT  16.513 8.376 17.1 8.448 ;
     RECT  16.513 8.448 17.088 8.472 ;
     RECT  16.513 8.472 17.1 8.544 ;
     RECT  16.513 8.544 17.088 8.568 ;
     RECT  16.513 8.568 17.1 8.64 ;
     RECT  16.513 8.64 17.088 8.664 ;
     RECT  16.513 8.664 17.1 8.784 ;
     RECT  16.513 8.784 17.088 8.808 ;
     RECT  16.513 8.808 17.1 8.88 ;
     RECT  16.513 8.88 17.088 8.904 ;
     RECT  16.513 8.904 17.1 8.976 ;
     RECT  16.513 8.976 17.088 9 ;
     RECT  16.513 9 17.1 9.072 ;
     RECT  16.513 9.072 17.088 9.096 ;
     RECT  16.513 9.096 17.1 9.168 ;
     RECT  16.513 9.168 17.088 9.192 ;
     RECT  16.513 9.192 17.1 9.312 ;
     RECT  16.513 9.312 17.088 9.336 ;
     RECT  16.513 9.336 17.1 9.408 ;
     RECT  16.513 9.408 17.088 9.432 ;
     RECT  16.513 9.432 17.1 9.504 ;
     RECT  16.513 9.504 17.088 9.528 ;
     RECT  16.513 9.528 17.1 9.6 ;
     RECT  16.513 9.6 17.088 9.624 ;
     RECT  16.513 9.624 17.1 9.696 ;
     RECT  16.513 9.696 17.088 9.72 ;
     RECT  16.513 9.72 17.1 9.84 ;
     RECT  16.513 9.84 17.088 9.864 ;
     RECT  16.513 9.864 17.1 9.936 ;
     RECT  16.513 9.936 17.088 9.96 ;
     RECT  16.513 9.96 17.1 10.032 ;
     RECT  16.513 10.032 17.088 10.056 ;
     RECT  16.513 10.056 17.1 10.128 ;
     RECT  16.513 10.128 17.088 10.152 ;
     RECT  16.513 10.152 17.1 10.224 ;
     RECT  16.513 10.224 17.088 10.248 ;
     RECT  16.513 10.248 17.1 10.368 ;
     RECT  16.513 10.368 17.088 10.392 ;
     RECT  16.513 10.392 17.1 10.464 ;
     RECT  16.513 10.464 17.088 10.488 ;
     RECT  16.513 10.488 17.1 10.56 ;
     RECT  16.513 10.56 17.088 10.584 ;
     RECT  16.513 10.584 17.1 10.656 ;
     RECT  16.513 10.656 17.088 10.68 ;
     RECT  16.513 10.68 17.1 10.752 ;
     RECT  16.513 10.752 17.088 10.776 ;
     RECT  16.513 10.776 17.1 10.896 ;
     RECT  16.513 10.896 17.088 10.92 ;
     RECT  16.513 10.92 17.1 10.992 ;
     RECT  16.513 10.992 17.088 11.016 ;
     RECT  16.513 11.016 17.1 11.088 ;
     RECT  16.513 11.088 17.088 11.112 ;
     RECT  16.513 11.112 17.1 11.184 ;
     RECT  16.513 11.184 17.088 11.208 ;
     RECT  16.513 11.208 17.1 11.28 ;
     RECT  16.513 11.28 17.088 11.304 ;
     RECT  16.513 11.304 17.1 11.424 ;
     RECT  16.513 11.424 17.088 11.448 ;
     RECT  16.513 11.448 17.1 11.52 ;
     RECT  16.513 11.52 17.088 11.544 ;
     RECT  16.513 11.544 17.1 11.616 ;
     RECT  16.513 11.616 17.088 11.64 ;
     RECT  16.513 11.64 17.1 11.712 ;
     RECT  16.513 11.712 17.088 11.736 ;
     RECT  16.513 11.736 17.1 11.808 ;
     RECT  16.513 11.808 17.088 11.832 ;
     RECT  16.513 11.832 17.1 11.904 ;
     RECT  16.513 11.904 17.088 11.928 ;
     RECT  16.513 11.928 17.1 12.048 ;
     RECT  16.513 12.048 17.088 12.072 ;
     RECT  16.513 12.072 17.1 12.144 ;
     RECT  16.513 12.144 17.088 12.168 ;
     RECT  16.513 12.168 17.1 12.24 ;
     RECT  16.513 12.24 17.088 12.264 ;
     RECT  16.513 12.264 17.1 12.336 ;
     RECT  16.513 12.336 17.088 12.36 ;
     RECT  16.513 12.36 17.1 12.432 ;
     RECT  16.513 12.432 17.088 12.456 ;
     RECT  16.513 12.456 17.1 12.576 ;
     RECT  16.513 12.576 17.088 12.6 ;
     RECT  16.513 12.6 17.1 12.672 ;
     RECT  16.513 12.672 17.088 12.696 ;
     RECT  16.513 12.696 17.1 12.768 ;
     RECT  16.513 12.768 17.088 12.792 ;
     RECT  16.513 12.792 17.1 12.864 ;
     RECT  16.513 12.864 17.088 12.888 ;
     RECT  16.513 12.888 17.1 12.96 ;
     RECT  16.513 12.96 17.088 12.984 ;
     RECT  16.513 12.984 17.1 13.104 ;
     RECT  16.513 13.104 17.088 13.128 ;
     RECT  16.513 13.128 17.1 13.2 ;
     RECT  16.513 13.2 17.088 13.224 ;
     RECT  16.513 13.224 17.1 13.296 ;
     RECT  16.513 13.296 17.088 13.32 ;
     RECT  16.513 13.32 17.1 13.392 ;
     RECT  16.513 13.392 17.088 13.416 ;
     RECT  16.513 13.416 17.1 13.488 ;
     RECT  16.513 13.488 17.088 13.512 ;
     RECT  16.513 13.512 17.1 13.632 ;
     RECT  16.513 13.632 17.088 13.656 ;
     RECT  16.513 13.656 17.1 13.728 ;
     RECT  16.513 13.728 17.088 13.752 ;
     RECT  16.513 13.752 17.1 13.824 ;
     RECT  16.513 13.824 17.088 13.848 ;
     RECT  16.513 13.848 17.1 13.92 ;
     RECT  16.513 13.92 17.088 13.944 ;
     RECT  16.513 13.944 17.1 14.016 ;
     RECT  16.513 14.016 17.088 14.04 ;
     RECT  16.513 14.04 17.1 14.16 ;
     RECT  16.513 14.16 17.088 14.184 ;
     RECT  16.513 14.184 17.1 14.256 ;
     RECT  16.513 14.256 17.088 14.28 ;
     RECT  16.513 14.28 17.1 14.352 ;
     RECT  16.513 14.352 17.088 14.376 ;
     RECT  16.513 14.376 17.1 14.448 ;
     RECT  16.513 14.448 17.088 14.472 ;
     RECT  16.513 14.472 17.1 14.544 ;
     RECT  16.513 14.544 17.088 14.568 ;
     RECT  16.513 14.568 17.1 14.688 ;
     RECT  16.513 14.688 17.088 14.712 ;
     RECT  16.513 14.712 17.1 14.784 ;
     RECT  16.513 14.784 17.088 14.808 ;
     RECT  16.513 14.808 17.1 14.88 ;
     RECT  16.513 14.88 17.088 14.904 ;
     RECT  16.513 14.904 17.1 14.976 ;
     RECT  16.513 14.976 17.088 15 ;
     RECT  16.513 15 17.1 15.072 ;
     RECT  16.513 15.072 17.088 15.096 ;
     RECT  16.513 15.096 17.1 15.216 ;
     RECT  16.513 15.216 17.088 15.24 ;
     RECT  16.513 15.24 17.1 15.312 ;
     RECT  16.513 15.312 17.088 15.336 ;
     RECT  16.513 15.336 17.1 15.408 ;
     RECT  16.513 15.408 17.088 15.432 ;
     RECT  16.513 15.432 17.1 15.504 ;
     RECT  16.513 15.504 17.088 15.528 ;
     RECT  16.513 15.528 17.1 15.6 ;
     RECT  16.513 15.6 17.088 15.624 ;
     RECT  16.513 15.624 17.1 15.744 ;
     RECT  16.513 15.744 17.088 15.768 ;
     RECT  16.513 15.768 17.1 15.84 ;
     RECT  16.513 15.84 17.088 15.864 ;
     RECT  16.513 15.864 17.1 15.936 ;
     RECT  16.513 15.936 17.088 15.96 ;
     RECT  16.513 15.96 17.1 16.032 ;
     RECT  16.513 16.032 17.088 16.056 ;
     RECT  16.513 16.056 17.1 16.128 ;
     RECT  16.513 16.128 17.088 16.152 ;
     RECT  16.513 16.152 17.1 16.272 ;
     RECT  16.513 16.272 17.088 16.296 ;
     RECT  16.513 16.296 17.1 16.368 ;
     RECT  16.513 16.368 17.088 16.392 ;
     RECT  16.513 16.392 17.1 16.464 ;
     RECT  16.513 16.464 17.088 16.488 ;
     RECT  16.513 16.488 17.1 16.56 ;
     RECT  16.513 16.56 17.088 16.584 ;
     RECT  16.513 16.584 17.1 16.656 ;
     RECT  16.513 16.656 17.088 16.68 ;
     RECT  16.513 16.68 17.1 16.8 ;
     RECT  16.513 16.8 17.088 16.824 ;
     RECT  16.513 16.824 17.1 16.896 ;
     RECT  16.513 16.896 17.088 16.92 ;
     RECT  16.513 16.92 17.1 16.992 ;
     RECT  16.513 16.992 17.088 17.016 ;
     RECT  16.513 17.016 17.1 17.088 ;
     RECT  16.513 17.088 17.088 17.112 ;
     RECT  16.513 17.112 17.1 17.184 ;
     RECT  16.513 17.184 17.088 17.208 ;
     RECT  16.513 17.208 17.1 17.328 ;
     RECT  16.513 17.328 17.088 17.352 ;
     RECT  16.513 17.352 17.1 17.424 ;
     RECT  16.513 17.424 17.088 17.448 ;
     RECT  16.513 17.448 17.1 17.52 ;
     RECT  16.513 17.52 17.088 17.544 ;
     RECT  16.513 17.544 17.1 17.616 ;
     RECT  16.513 17.616 17.088 17.64 ;
     RECT  16.513 17.64 17.1 17.712 ;
     RECT  16.513 17.712 17.088 17.736 ;
     RECT  16.513 17.736 17.1 17.856 ;
     RECT  16.513 17.856 17.088 17.88 ;
     RECT  16.513 17.88 17.1 17.952 ;
     RECT  16.513 17.952 17.088 17.976 ;
     RECT  16.513 17.976 17.1 18.048 ;
     RECT  16.513 18.048 17.088 18.072 ;
     RECT  16.513 18.072 17.1 18.144 ;
     RECT  16.513 18.144 17.088 18.168 ;
     RECT  16.513 18.168 17.1 18.24 ;
     RECT  16.513 18.24 17.088 18.264 ;
     RECT  16.513 18.264 17.1 18.384 ;
     RECT  16.513 18.384 17.088 18.408 ;
     RECT  16.513 18.408 17.1 18.48 ;
     RECT  16.513 18.48 17.088 18.504 ;
     RECT  16.513 18.504 17.1 18.576 ;
     RECT  16.513 18.576 17.088 18.6 ;
     RECT  16.513 18.6 17.1 18.672 ;
     RECT  16.513 18.672 17.088 18.696 ;
     RECT  16.513 18.696 17.1 18.768 ;
     RECT  16.513 18.768 17.088 18.792 ;
     RECT  16.513 18.792 17.1 18.912 ;
     RECT  16.513 18.912 17.088 18.936 ;
     RECT  16.513 18.936 17.1 19.008 ;
     RECT  16.513 19.008 17.088 19.032 ;
     RECT  16.513 19.032 17.1 19.104 ;
     RECT  16.513 19.104 17.088 19.128 ;
     RECT  16.513 19.128 17.1 19.2 ;
     RECT  16.513 19.2 17.088 19.224 ;
     RECT  16.513 19.224 17.1 19.296 ;
     RECT  16.513 19.296 17.088 19.32 ;
     RECT  16.513 19.32 17.1 19.44 ;
     RECT  16.513 19.44 17.088 19.464 ;
     RECT  16.513 19.464 17.1 19.536 ;
     RECT  16.513 19.536 17.088 19.56 ;
     RECT  16.513 19.56 17.1 19.632 ;
     RECT  16.513 19.632 17.088 19.656 ;
     RECT  16.513 19.656 17.1 19.728 ;
     RECT  16.513 19.728 17.088 19.752 ;
     RECT  16.513 19.752 17.1 19.824 ;
     RECT  16.513 19.824 17.088 19.848 ;
     RECT  16.513 19.848 17.1 19.92 ;
     RECT  16.513 19.92 17.088 19.944 ;
     RECT  16.513 19.944 17.1 20.064 ;
     RECT  16.513 20.064 17.088 20.088 ;
     RECT  16.513 20.088 17.1 20.16 ;
     RECT  16.513 20.16 17.088 20.184 ;
     RECT  16.513 20.184 17.1 20.256 ;
     RECT  16.513 20.256 17.088 20.28 ;
     RECT  16.513 20.28 17.1 20.352 ;
     RECT  16.513 20.352 17.088 20.376 ;
     RECT  16.513 20.376 17.1 20.448 ;
     RECT  16.513 20.448 17.088 20.472 ;
     RECT  16.513 20.472 17.1 20.592 ;
     RECT  16.513 20.592 17.088 20.616 ;
     RECT  16.513 20.616 17.1 20.688 ;
     RECT  16.513 20.688 17.088 20.712 ;
     RECT  16.513 20.712 17.1 20.784 ;
     RECT  16.513 20.784 17.088 20.808 ;
     RECT  16.513 20.808 17.1 20.88 ;
     RECT  16.513 20.88 17.088 20.904 ;
     RECT  16.513 20.904 17.1 20.976 ;
     RECT  16.513 20.976 17.088 21 ;
     RECT  16.513 21 17.1 21.12 ;
     RECT  16.513 21.12 17.088 21.144 ;
     RECT  16.513 21.144 17.1 21.216 ;
     RECT  16.513 21.216 17.088 21.24 ;
     RECT  16.513 21.24 17.1 21.312 ;
     RECT  16.513 21.312 17.088 21.336 ;
     RECT  16.513 21.336 17.1 21.408 ;
     RECT  16.513 21.408 17.088 21.432 ;
     RECT  16.513 21.432 17.1 21.504 ;
     RECT  16.513 21.504 17.088 21.528 ;
     RECT  16.513 21.528 17.1 21.648 ;
     RECT  16.513 21.648 17.088 21.672 ;
     RECT  16.513 21.672 17.1 21.744 ;
     RECT  16.513 21.744 17.088 21.768 ;
     RECT  16.513 21.768 17.1 21.84 ;
     RECT  16.513 21.84 17.088 21.864 ;
     RECT  16.513 21.864 17.1 21.936 ;
     RECT  16.513 21.936 17.088 21.96 ;
     RECT  16.513 21.96 17.1 22.032 ;
     RECT  16.513 22.032 17.088 22.056 ;
     RECT  16.513 22.056 17.1 22.176 ;
     RECT  16.513 22.176 17.088 22.2 ;
     RECT  16.513 22.2 17.1 22.272 ;
     RECT  16.513 22.272 17.088 22.296 ;
     RECT  16.513 22.296 17.1 22.368 ;
     RECT  16.513 22.368 17.088 22.392 ;
     RECT  16.513 22.392 17.1 22.464 ;
     RECT  16.513 22.464 17.088 22.488 ;
     RECT  16.513 22.488 17.1 22.56 ;
     RECT  16.513 22.56 17.088 22.584 ;
     RECT  16.513 22.584 17.1 22.704 ;
     RECT  16.513 22.704 17.088 22.728 ;
     RECT  16.513 22.728 17.1 22.8 ;
     RECT  16.513 22.8 17.088 22.824 ;
     RECT  16.513 22.824 17.1 22.896 ;
     RECT  16.513 22.896 17.088 22.92 ;
     RECT  16.513 22.92 17.1 22.992 ;
     RECT  16.513 22.992 17.088 23.016 ;
     RECT  16.513 23.016 17.1 23.088 ;
     RECT  16.513 23.088 17.088 23.112 ;
     RECT  16.513 23.112 17.1 23.232 ;
     RECT  16.513 23.232 17.088 23.256 ;
     RECT  16.513 23.256 17.1 23.328 ;
     RECT  16.513 23.328 17.088 23.352 ;
     RECT  16.513 23.352 17.1 23.424 ;
     RECT  16.513 23.424 17.088 23.448 ;
     RECT  16.513 23.448 17.1 23.52 ;
     RECT  16.513 23.52 17.088 23.544 ;
     RECT  16.513 23.544 17.1 23.616 ;
     RECT  16.513 23.616 17.088 23.64 ;
     RECT  16.513 23.64 17.1 23.76 ;
     RECT  16.513 23.76 17.088 23.784 ;
     RECT  16.513 23.784 17.1 23.856 ;
     RECT  16.513 23.856 17.088 23.88 ;
     RECT  16.513 23.88 17.1 23.952 ;
     RECT  16.513 23.952 17.088 23.976 ;
     RECT  16.513 23.976 17.1 24.048 ;
     RECT  16.513 24.048 17.088 24.072 ;
     RECT  16.513 24.072 17.1 24.144 ;
     RECT  16.513 24.144 17.088 24.168 ;
     RECT  16.513 24.168 17.1 24.288 ;
     RECT  16.513 24.288 17.088 24.312 ;
     RECT  16.513 24.312 17.1 24.384 ;
     RECT  16.513 24.384 17.088 24.408 ;
     RECT  16.513 24.408 17.1 24.48 ;
     RECT  16.513 24.48 17.088 24.504 ;
     RECT  16.513 24.504 17.1 24.576 ;
     RECT  16.513 24.576 17.088 24.6 ;
     RECT  16.513 24.6 17.1 24.672 ;
     RECT  16.513 24.672 17.088 24.696 ;
     RECT  16.513 24.696 17.1 24.816 ;
     RECT  16.513 24.816 17.088 24.84 ;
     RECT  16.513 24.84 17.1 24.912 ;
     RECT  16.513 24.912 17.088 24.936 ;
     RECT  16.513 24.936 17.1 25.008 ;
     RECT  16.513 25.008 17.088 25.032 ;
     RECT  16.513 25.032 17.1 25.104 ;
     RECT  16.513 25.104 17.088 25.128 ;
     RECT  16.513 25.128 17.1 25.2 ;
     RECT  16.513 25.2 17.088 25.224 ;
     RECT  16.513 25.224 17.1 25.344 ;
     RECT  16.513 25.344 17.088 25.368 ;
     RECT  16.513 25.368 17.1 25.44 ;
     RECT  16.513 25.44 17.088 25.464 ;
     RECT  16.513 25.464 17.1 25.536 ;
     RECT  16.513 25.536 17.088 25.56 ;
     RECT  16.513 25.56 17.1 25.632 ;
     RECT  16.513 25.632 17.088 25.656 ;
     RECT  16.513 25.656 17.1 25.728 ;
     RECT  16.513 25.728 17.088 25.752 ;
     RECT  16.513 25.752 17.1 25.872 ;
     RECT  16.513 25.872 17.088 25.896 ;
     RECT  16.513 25.896 17.1 25.968 ;
     RECT  16.513 25.968 17.088 25.992 ;
     RECT  16.513 25.992 17.1 26.064 ;
     RECT  16.513 26.064 17.088 26.088 ;
     RECT  16.513 26.088 17.1 26.16 ;
     RECT  16.513 26.16 17.088 26.184 ;
     RECT  16.513 26.184 17.1 26.256 ;
     RECT  16.513 26.256 17.088 26.28 ;
     RECT  16.513 26.28 17.1 26.4 ;
     RECT  16.513 26.4 17.088 26.424 ;
     RECT  16.513 26.424 17.1 26.496 ;
     RECT  16.513 26.496 17.088 26.52 ;
     RECT  16.513 26.52 17.1 26.592 ;
     RECT  16.513 26.592 17.088 26.616 ;
     RECT  16.513 26.616 17.1 26.688 ;
     RECT  16.513 26.688 17.088 26.712 ;
     RECT  16.513 26.712 17.1 26.784 ;
     RECT  16.513 26.784 17.088 26.808 ;
     RECT  16.513 26.808 17.1 26.928 ;
     RECT  16.513 26.928 17.088 26.952 ;
     RECT  16.513 26.952 17.1 27.024 ;
     RECT  16.513 27.024 17.088 27.048 ;
     RECT  16.513 27.048 17.1 27.12 ;
     RECT  16.513 27.12 17.088 27.144 ;
     RECT  16.513 27.144 17.1 27.216 ;
     RECT  16.513 27.216 17.088 27.24 ;
     RECT  16.513 27.24 17.1 27.312 ;
     RECT  16.513 27.312 17.088 27.336 ;
     RECT  16.513 27.336 17.1 27.408 ;
     RECT  16.513 27.408 17.088 27.432 ;
     RECT  16.513 27.432 17.1 27.552 ;
     RECT  16.513 27.552 17.088 27.576 ;
     RECT  16.513 27.576 17.1 27.648 ;
     RECT  16.513 27.648 17.088 27.672 ;
     RECT  16.513 27.672 17.1 27.744 ;
     RECT  16.513 27.744 17.088 27.768 ;
     RECT  16.513 27.768 17.1 27.84 ;
     RECT  16.513 27.84 17.088 27.864 ;
     RECT  16.513 27.864 17.1 27.936 ;
     RECT  16.513 27.936 17.088 27.96 ;
     RECT  16.513 27.96 17.1 28.08 ;
     RECT  16.513 28.08 17.088 28.104 ;
     RECT  16.513 28.104 17.1 28.176 ;
     RECT  16.513 28.176 17.088 28.2 ;
     RECT  16.513 28.2 17.1 28.272 ;
     RECT  16.513 28.272 17.088 28.296 ;
     RECT  16.513 28.296 17.1 28.368 ;
     RECT  16.513 28.368 17.088 28.392 ;
     RECT  16.513 28.392 17.1 28.464 ;
     RECT  16.513 28.464 17.088 28.488 ;
     RECT  16.513 28.488 17.1 28.608 ;
     RECT  16.513 28.608 17.088 28.632 ;
     RECT  16.513 28.632 17.1 28.704 ;
     RECT  16.513 28.704 17.088 28.728 ;
     RECT  16.513 28.728 17.1 28.8 ;
     RECT  16.513 28.8 17.088 28.824 ;
     RECT  16.513 28.824 17.1 28.896 ;
     RECT  16.513 28.896 17.088 28.92 ;
     RECT  16.513 28.92 17.1 28.992 ;
     RECT  16.513 28.992 17.088 29.016 ;
     RECT  16.513 29.016 17.1 29.136 ;
     RECT  16.513 29.136 17.088 29.16 ;
     RECT  16.513 29.16 17.1 29.232 ;
     RECT  16.513 29.232 17.088 29.256 ;
     RECT  16.513 29.256 17.1 29.328 ;
     RECT  16.513 29.328 17.088 29.352 ;
     RECT  16.513 29.352 17.1 29.424 ;
     RECT  16.513 29.424 17.088 29.448 ;
     RECT  16.513 29.448 17.1 29.52 ;
     RECT  16.513 29.52 17.088 29.544 ;
     RECT  16.513 29.544 17.1 29.664 ;
     RECT  16.513 29.664 17.088 29.688 ;
     RECT  16.513 29.688 17.1 29.76 ;
     RECT  16.513 29.76 17.088 29.784 ;
     RECT  16.513 29.784 17.1 29.856 ;
     RECT  16.513 29.856 17.088 29.88 ;
     RECT  16.513 29.88 17.1 29.952 ;
     RECT  16.513 29.952 17.088 29.976 ;
     RECT  16.513 29.976 17.1 30.048 ;
     RECT  16.513 30.048 17.088 30.072 ;
     RECT  16.513 30.072 17.1 30.192 ;
     RECT  16.513 30.192 17.088 30.216 ;
     RECT  16.513 30.216 17.1 30.288 ;
     RECT  16.513 30.288 17.088 30.312 ;
     RECT  16.513 30.312 17.1 30.384 ;
     RECT  16.513 30.384 17.088 30.408 ;
     RECT  16.513 30.408 17.1 30.48 ;
     RECT  16.513 30.48 17.088 30.504 ;
     RECT  16.513 30.504 17.1 30.576 ;
     RECT  16.513 30.576 17.088 30.6 ;
     RECT  16.513 30.6 17.1 30.72 ;
     RECT  16.513 30.72 17.088 30.744 ;
     RECT  16.513 30.744 17.1 30.816 ;
     RECT  16.513 30.816 17.088 30.84 ;
     RECT  16.513 30.84 17.1 30.912 ;
     RECT  16.513 30.912 17.088 30.936 ;
     RECT  16.513 30.936 17.1 31.008 ;
     RECT  16.513 31.008 17.088 31.032 ;
     RECT  16.513 31.032 17.1 31.104 ;
     RECT  16.513 31.104 17.088 31.128 ;
     RECT  16.513 31.128 17.1 31.248 ;
     RECT  16.513 31.248 17.088 31.272 ;
     RECT  16.513 31.272 17.1 31.344 ;
     RECT  16.513 31.344 17.088 31.368 ;
     RECT  16.513 31.368 17.1 31.44 ;
     RECT  16.513 31.44 17.088 31.464 ;
     RECT  16.513 31.464 17.1 31.536 ;
     RECT  16.513 31.536 17.088 31.56 ;
     RECT  16.513 31.56 17.1 31.632 ;
     RECT  16.513 31.632 17.088 31.656 ;
     RECT  16.513 31.656 17.1 31.776 ;
     RECT  16.513 31.776 17.088 31.8 ;
     RECT  16.513 31.8 17.1 31.872 ;
     RECT  16.513 31.872 17.088 31.896 ;
     RECT  16.513 31.896 17.1 31.968 ;
     RECT  16.513 31.968 17.088 31.992 ;
     RECT  16.513 31.992 17.1 32.064 ;
     RECT  16.513 32.064 17.088 32.088 ;
     RECT  16.513 32.088 17.1 32.16 ;
     RECT  16.513 32.16 17.088 32.184 ;
     RECT  16.513 32.184 17.1 32.304 ;
     RECT  16.513 32.304 17.088 32.328 ;
     RECT  16.513 32.328 17.1 32.4 ;
     RECT  16.513 32.4 17.088 32.424 ;
     RECT  16.513 32.424 17.1 32.496 ;
     RECT  16.513 32.496 17.088 32.52 ;
     RECT  16.513 32.52 17.1 32.592 ;
     RECT  16.513 32.592 17.088 32.616 ;
     RECT  16.513 32.616 17.1 32.688 ;
     RECT  16.513 32.688 17.088 32.712 ;
     RECT  16.513 32.712 17.1 32.832 ;
     RECT  16.513 32.832 17.088 32.856 ;
     RECT  16.513 32.856 17.1 32.928 ;
     RECT  16.513 32.928 17.088 32.952 ;
     RECT  16.513 32.952 17.1 33.024 ;
     RECT  16.513 33.024 17.088 33.048 ;
     RECT  16.513 33.048 17.1 33.12 ;
     RECT  16.513 33.12 17.088 33.144 ;
     RECT  16.513 33.144 17.1 33.216 ;
     RECT  16.513 33.216 17.088 33.24 ;
     RECT  16.513 33.24 17.1 33.36 ;
     RECT  16.513 33.36 17.088 33.384 ;
     RECT  16.513 33.384 17.1 33.456 ;
     RECT  16.513 33.456 17.088 33.48 ;
     RECT  16.513 33.48 17.1 33.552 ;
     RECT  16.513 33.552 17.088 33.576 ;
     RECT  16.513 33.576 17.1 33.648 ;
     RECT  16.513 33.648 17.088 33.672 ;
     RECT  16.513 33.672 17.1 33.744 ;
     RECT  16.513 33.744 17.088 33.768 ;
     RECT  16.513 33.768 17.1 33.888 ;
     RECT  16.513 33.888 17.088 33.912 ;
     RECT  16.513 33.912 17.1 33.984 ;
     RECT  16.513 33.984 17.088 34.008 ;
     RECT  16.513 34.008 17.1 34.08 ;
     RECT  16.513 34.08 17.088 34.104 ;
     RECT  16.513 34.104 17.1 34.176 ;
     RECT  16.513 34.176 17.088 34.2 ;
     RECT  16.513 34.2 17.1 34.272 ;
     RECT  16.513 34.272 17.088 34.296 ;
     RECT  16.513 34.296 17.1 34.416 ;
     RECT  16.513 34.416 17.088 34.44 ;
     RECT  16.513 34.44 17.1 34.512 ;
     RECT  16.513 34.512 17.088 34.536 ;
     RECT  16.513 34.536 17.1 34.608 ;
     RECT  16.513 34.608 17.088 34.632 ;
     RECT  16.513 34.632 17.1 34.704 ;
     RECT  16.513 34.704 17.088 34.728 ;
     RECT  16.513 34.728 17.1 34.8 ;
     RECT  16.513 34.8 17.088 34.824 ;
     RECT  16.513 34.824 17.1 34.944 ;
     RECT  16.513 34.944 17.088 34.968 ;
     RECT  16.513 34.968 17.1 35.04 ;
     RECT  16.513 35.04 17.088 35.064 ;
     RECT  16.513 35.064 17.1 35.136 ;
     RECT  16.513 35.136 17.088 35.16 ;
     RECT  16.513 35.16 17.1 35.232 ;
     RECT  16.513 35.232 17.088 35.256 ;
     RECT  16.513 35.256 17.1 35.328 ;
     RECT  16.513 35.328 17.088 35.352 ;
     RECT  16.513 35.352 17.1 35.424 ;
     RECT  16.513 35.424 17.088 35.448 ;
     RECT  16.513 35.448 17.1 35.568 ;
     RECT  16.513 35.568 17.088 35.592 ;
     RECT  16.513 35.592 17.1 35.664 ;
     RECT  16.513 35.664 17.088 35.688 ;
     RECT  16.513 35.688 17.1 35.76 ;
     RECT  16.513 35.76 17.088 35.784 ;
     RECT  16.513 35.784 17.1 35.856 ;
     RECT  16.513 35.856 17.088 35.88 ;
     RECT  16.513 35.88 17.1 35.952 ;
     RECT  16.513 35.952 17.088 35.976 ;
     RECT  16.513 35.976 17.1 36.096 ;
     RECT  16.513 36.096 17.088 36.12 ;
     RECT  16.513 36.12 17.1 36.192 ;
     RECT  16.513 36.192 17.088 36.216 ;
     RECT  16.513 36.216 17.1 36.288 ;
     RECT  16.513 36.288 17.088 36.312 ;
     RECT  16.513 36.312 17.1 36.384 ;
     RECT  16.513 36.384 17.088 36.408 ;
     RECT  16.513 36.408 17.1 36.48 ;
     RECT  16.513 36.48 17.088 36.504 ;
     RECT  16.513 36.504 17.1 36.624 ;
     RECT  16.513 36.624 17.088 36.648 ;
     RECT  16.513 36.648 17.1 36.72 ;
     RECT  16.513 36.72 17.088 36.744 ;
     RECT  16.513 36.744 17.1 36.816 ;
     RECT  16.513 36.816 17.088 36.84 ;
     RECT  16.513 36.84 17.1 36.912 ;
     RECT  16.513 36.912 17.088 36.936 ;
     RECT  16.513 36.936 17.1 37.008 ;
     RECT  16.513 37.008 17.088 37.032 ;
     RECT  16.513 37.032 17.1 37.152 ;
     RECT  16.513 37.152 17.088 37.176 ;
     RECT  16.513 37.176 17.1 37.248 ;
     RECT  16.513 37.248 17.088 37.272 ;
     RECT  16.513 37.272 17.1 37.344 ;
     RECT  16.513 37.344 17.088 37.368 ;
     RECT  16.513 37.368 17.1 37.44 ;
     RECT  16.513 37.44 17.088 37.464 ;
     RECT  16.513 37.464 17.1 37.536 ;
     RECT  16.513 37.536 17.088 37.56 ;
     RECT  16.513 37.56 17.1 37.68 ;
     RECT  16.513 37.68 17.088 37.704 ;
     RECT  16.513 37.704 17.1 37.776 ;
     RECT  16.513 37.776 17.088 37.8 ;
     RECT  16.513 37.8 17.1 37.872 ;
     RECT  16.513 37.872 17.088 37.896 ;
     RECT  16.513 37.896 17.1 37.968 ;
     RECT  16.513 37.968 17.088 37.992 ;
     RECT  16.513 37.992 17.1 38.064 ;
     RECT  16.513 38.064 17.088 38.088 ;
     RECT  16.513 38.088 17.1 38.208 ;
     RECT  16.513 38.208 17.088 38.232 ;
     RECT  16.513 38.232 17.1 38.304 ;
     RECT  16.513 38.304 17.088 38.328 ;
     RECT  16.513 38.328 17.1 38.4 ;
     RECT  16.513 38.4 17.088 38.424 ;
     RECT  16.513 38.424 17.1 38.496 ;
     RECT  16.513 38.496 17.088 38.52 ;
     RECT  16.513 38.52 17.1 38.592 ;
     RECT  16.513 38.592 17.088 38.616 ;
     RECT  16.513 38.616 17.1 38.736 ;
     RECT  16.513 38.736 17.088 38.76 ;
     RECT  16.513 38.76 17.1 38.832 ;
     RECT  16.513 38.832 17.088 38.856 ;
     RECT  16.513 38.856 17.1 38.928 ;
     RECT  16.513 38.928 17.088 38.952 ;
     RECT  16.513 38.952 17.1 39.024 ;
     RECT  16.513 39.024 17.088 39.048 ;
     RECT  16.513 39.048 17.1 39.12 ;
     RECT  16.513 39.12 17.088 39.144 ;
     RECT  16.513 39.144 17.1 39.264 ;
     RECT  16.513 39.264 17.088 39.288 ;
     RECT  16.513 39.288 17.1 39.36 ;
     RECT  16.513 39.36 17.088 39.384 ;
     RECT  16.513 39.384 17.1 39.456 ;
     RECT  16.513 39.456 17.088 39.48 ;
     RECT  16.513 39.48 17.1 39.552 ;
     RECT  16.513 39.552 17.088 39.576 ;
     RECT  16.513 39.576 17.1 39.648 ;
     RECT  16.513 39.648 17.088 39.672 ;
     RECT  16.513 39.672 17.1 39.792 ;
     RECT  16.513 39.792 17.088 39.816 ;
     RECT  16.513 39.816 17.1 39.888 ;
     RECT  16.513 39.888 17.088 39.912 ;
     RECT  16.513 39.912 17.1 39.984 ;
     RECT  16.513 39.984 17.088 40.008 ;
     RECT  16.513 40.008 17.1 40.08 ;
     RECT  16.513 40.08 17.088 40.104 ;
     RECT  16.513 40.104 17.1 40.176 ;
     RECT  16.513 40.176 17.088 40.2 ;
     RECT  16.513 40.2 17.1 40.32 ;
     RECT  16.513 40.32 17.088 40.344 ;
     RECT  16.513 40.344 17.1 40.416 ;
     RECT  16.513 40.416 17.088 40.44 ;
     RECT  16.513 40.44 17.1 40.512 ;
     RECT  16.513 40.512 17.088 40.536 ;
     RECT  16.513 40.536 17.1 40.608 ;
     RECT  16.513 40.608 17.088 40.632 ;
     RECT  16.513 40.632 17.1 40.704 ;
     RECT  16.513 40.704 17.088 40.728 ;
     RECT  16.513 40.728 17.1 40.848 ;
     RECT  16.513 40.848 17.088 40.872 ;
     RECT  16.513 40.872 17.1 40.944 ;
     RECT  16.513 40.944 17.088 40.968 ;
     RECT  16.513 40.968 17.1 41.04 ;
     RECT  16.513 41.04 17.088 41.064 ;
     RECT  16.513 41.064 17.1 41.136 ;
     RECT  16.513 41.136 17.088 41.16 ;
     RECT  16.513 41.16 17.1 41.232 ;
     RECT  16.513 41.232 17.088 41.256 ;
     RECT  16.513 41.256 17.1 41.376 ;
     RECT  16.513 41.376 17.088 41.4 ;
     RECT  16.513 41.4 17.1 41.472 ;
     RECT  16.513 41.472 17.088 41.496 ;
     RECT  16.513 41.496 17.1 41.568 ;
     RECT  16.513 41.568 17.088 41.592 ;
     RECT  16.513 41.592 17.1 41.664 ;
     RECT  16.513 41.664 17.088 41.688 ;
     RECT  16.513 41.688 17.1 41.76 ;
     RECT  16.513 41.76 17.088 41.784 ;
     RECT  16.513 41.784 17.1 41.904 ;
     RECT  16.513 41.904 17.088 41.928 ;
     RECT  16.513 41.928 17.1 42 ;
     RECT  16.513 42 17.088 42.024 ;
     RECT  16.513 42.024 17.1 42.096 ;
     RECT  16.513 42.096 17.088 42.12 ;
     RECT  16.513 42.12 17.1 42.192 ;
     RECT  16.513 42.192 17.088 42.216 ;
     RECT  16.513 42.216 17.1 42.288 ;
     RECT  16.513 42.288 17.088 42.312 ;
     RECT  16.513 42.312 17.1 42.432 ;
     RECT  16.513 42.432 17.088 42.456 ;
     RECT  16.513 42.456 17.1 42.528 ;
     RECT  16.513 42.528 17.088 42.552 ;
     RECT  16.513 42.552 17.1 42.624 ;
     RECT  16.513 42.624 17.088 42.648 ;
     RECT  16.513 42.648 17.1 42.72 ;
     RECT  16.513 42.72 17.088 42.744 ;
     RECT  16.513 42.744 17.1 42.816 ;
     RECT  16.513 42.816 17.088 42.84 ;
     RECT  16.513 42.84 17.1 42.912 ;
     RECT  16.513 42.912 17.088 42.936 ;
     RECT  16.513 42.936 17.1 43.056 ;
     RECT  16.513 43.056 17.088 43.08 ;
     RECT  16.513 43.08 17.1 43.152 ;
     RECT  16.513 43.152 17.088 43.176 ;
     RECT  16.513 43.176 17.1 43.248 ;
     RECT  16.513 43.248 17.088 43.272 ;
     RECT  16.513 43.272 17.1 43.344 ;
     RECT  16.513 43.344 17.088 43.368 ;
     RECT  16.513 43.368 17.1 43.44 ;
     RECT  16.513 43.44 17.088 43.464 ;
     RECT  16.513 43.464 17.1 43.584 ;
     RECT  16.513 43.584 17.088 43.608 ;
     RECT  16.513 43.608 17.1 43.68 ;
     RECT  16.513 43.68 17.088 43.704 ;
     RECT  16.513 43.704 17.1 43.776 ;
     RECT  16.513 43.776 17.088 43.8 ;
     RECT  16.513 43.8 17.1 43.872 ;
     RECT  16.513 43.872 17.088 43.896 ;
     RECT  16.513 43.896 17.1 43.968 ;
     RECT  16.513 43.968 17.088 43.992 ;
     RECT  16.513 43.992 17.1 44.112 ;
     RECT  16.513 44.112 17.088 44.136 ;
     RECT  16.513 44.136 17.1 44.208 ;
     RECT  16.513 44.208 17.088 44.232 ;
     RECT  16.513 44.232 17.1 44.304 ;
     RECT  16.513 44.304 17.088 44.328 ;
     RECT  16.513 44.328 17.1 44.4 ;
     RECT  16.513 44.4 17.088 44.424 ;
     RECT  16.513 44.424 17.1 44.496 ;
     RECT  16.513 44.496 17.088 44.52 ;
     RECT  16.513 44.52 17.1 44.64 ;
     RECT  16.513 44.64 17.088 44.664 ;
     RECT  16.513 44.664 17.1 44.736 ;
     RECT  16.513 44.736 17.088 44.76 ;
     RECT  16.513 44.76 17.1 44.832 ;
     RECT  16.513 44.832 17.088 44.856 ;
     RECT  16.513 44.856 17.1 44.928 ;
     RECT  16.513 44.928 17.088 44.952 ;
     RECT  16.513 44.952 17.1 45.024 ;
     RECT  16.513 45.024 17.088 45.048 ;
     RECT  16.513 45.048 17.1 45.168 ;
     RECT  16.513 45.168 17.088 45.192 ;
     RECT  16.513 45.192 17.1 45.264 ;
     RECT  16.513 45.264 17.088 45.288 ;
     RECT  16.513 45.288 17.1 45.36 ;
     RECT  16.513 45.36 17.088 45.384 ;
     RECT  16.513 45.384 17.1 45.456 ;
     RECT  16.513 45.456 17.088 45.48 ;
     RECT  16.513 45.48 17.1 45.552 ;
     RECT  16.513 45.552 17.088 45.576 ;
     RECT  16.513 45.576 17.1 45.696 ;
     RECT  16.513 45.696 17.088 45.72 ;
     RECT  16.513 45.72 17.1 45.792 ;
     RECT  16.513 45.792 17.088 45.816 ;
     RECT  16.513 45.816 17.1 45.888 ;
     RECT  16.513 45.888 17.088 45.912 ;
     RECT  16.513 45.912 17.1 45.984 ;
     RECT  16.513 45.984 17.088 46.008 ;
     RECT  16.513 46.008 17.1 46.08 ;
     RECT  16.513 46.08 17.088 46.104 ;
     RECT  16.513 46.104 17.1 46.224 ;
     RECT  16.513 46.224 17.088 46.248 ;
     RECT  16.513 46.248 17.1 46.32 ;
     RECT  16.513 46.32 17.088 46.344 ;
     RECT  16.513 46.344 17.1 46.416 ;
     RECT  16.513 46.416 17.088 46.44 ;
     RECT  16.513 46.44 17.1 46.512 ;
     RECT  16.513 46.512 17.088 46.536 ;
     RECT  16.513 46.536 17.1 46.608 ;
     RECT  16.513 46.608 17.088 46.632 ;
     RECT  16.513 46.632 17.1 46.752 ;
     RECT  16.513 46.752 17.088 46.776 ;
     RECT  16.513 46.776 17.1 46.848 ;
     RECT  16.513 46.848 17.088 46.872 ;
     RECT  16.513 46.872 17.1 46.944 ;
     RECT  16.513 46.944 17.088 46.968 ;
     RECT  16.513 46.968 17.1 47.04 ;
     RECT  16.513 47.04 17.088 47.064 ;
     RECT  16.513 47.064 17.1 47.136 ;
     RECT  16.513 47.136 17.088 47.16 ;
     RECT  16.513 47.16 17.1 47.28 ;
     RECT  16.513 47.28 17.088 47.304 ;
     RECT  16.513 47.304 17.1 47.376 ;
     RECT  16.513 47.376 17.088 47.4 ;
     RECT  16.513 47.4 17.1 47.472 ;
     RECT  16.513 47.472 17.088 47.496 ;
     RECT  16.513 47.496 17.1 47.568 ;
     RECT  16.513 47.568 17.088 47.592 ;
     RECT  16.513 47.592 17.1 47.664 ;
     RECT  16.513 47.664 17.088 47.688 ;
     RECT  16.513 47.688 17.1 47.808 ;
     RECT  16.513 47.808 17.088 47.832 ;
     RECT  16.513 47.832 17.1 47.904 ;
     RECT  16.513 47.904 17.088 47.928 ;
     RECT  16.513 47.928 17.1 48 ;
     RECT  16.513 48 17.088 48.024 ;
     RECT  16.513 48.024 17.1 48.096 ;
     RECT  16.513 48.096 17.088 48.12 ;
     RECT  16.513 48.12 17.1 48.192 ;
     RECT  16.513 48.192 17.088 48.216 ;
     RECT  16.513 48.216 17.1 48.336 ;
     RECT  16.513 48.336 17.088 48.36 ;
     RECT  16.513 48.36 17.1 48.432 ;
     RECT  16.513 48.432 17.088 48.456 ;
     RECT  16.513 48.456 17.1 48.528 ;
     RECT  16.513 48.528 17.088 48.552 ;
     RECT  16.513 48.552 17.1 48.624 ;
     RECT  16.513 48.624 17.088 48.648 ;
     RECT  16.513 48.648 17.1 48.72 ;
     RECT  16.513 48.72 17.088 48.744 ;
     RECT  16.513 48.744 17.1 48.864 ;
     RECT  16.513 48.864 17.088 48.888 ;
     RECT  16.513 48.888 17.1 48.96 ;
     RECT  16.513 48.96 17.088 48.984 ;
     RECT  16.513 48.984 17.1 49.056 ;
     RECT  16.513 49.056 17.088 49.08 ;
     RECT  16.513 49.08 17.1 49.152 ;
     RECT  16.513 49.152 17.088 49.176 ;
     RECT  16.513 49.176 17.1 49.248 ;
     RECT  16.513 49.248 17.088 49.272 ;
     RECT  16.513 49.272 17.1 49.392 ;
     RECT  16.513 49.392 17.088 49.416 ;
     RECT  16.513 49.416 17.1 49.488 ;
     RECT  16.513 49.488 17.088 49.512 ;
     RECT  16.513 49.512 17.1 49.584 ;
     RECT  16.513 49.584 17.088 49.608 ;
     RECT  16.513 49.608 17.1 49.68 ;
     RECT  16.513 49.68 17.088 49.704 ;
     RECT  16.513 49.704 17.1 49.776 ;
     RECT  16.513 49.776 17.088 49.8 ;
     RECT  16.513 49.8 17.1 49.92 ;
     RECT  16.513 49.92 17.088 49.944 ;
     RECT  16.513 49.944 17.1 50.016 ;
     RECT  16.513 50.016 17.088 50.04 ;
     RECT  16.513 50.04 17.1 50.112 ;
     RECT  16.513 50.112 17.088 50.136 ;
     RECT  16.513 50.136 17.1 50.208 ;
     RECT  16.513 50.208 17.088 50.232 ;
     RECT  16.513 50.232 17.1 50.304 ;
     RECT  16.513 50.304 17.088 50.328 ;
     RECT  16.513 50.328 17.1 50.4 ;
     RECT  16.513 50.4 17.088 50.424 ;
     RECT  16.513 50.424 17.1 50.544 ;
     RECT  16.513 50.544 17.088 50.568 ;
     RECT  16.513 50.568 17.1 50.64 ;
     RECT  16.513 50.64 17.088 50.664 ;
     RECT  16.513 50.664 17.1 50.736 ;
     RECT  16.513 50.736 17.088 50.76 ;
     RECT  16.513 50.76 17.1 50.832 ;
     RECT  16.513 50.832 17.088 50.856 ;
     RECT  16.513 50.856 17.1 50.928 ;
     RECT  16.513 50.928 17.088 50.952 ;
     RECT  16.513 50.952 17.1 51.072 ;
     RECT  16.513 51.072 17.088 51.096 ;
     RECT  16.513 51.096 17.1 51.168 ;
     RECT  16.513 51.168 17.088 51.192 ;
     RECT  16.513 51.192 17.1 51.264 ;
     RECT  16.513 51.264 17.088 51.288 ;
     RECT  16.513 51.288 17.1 51.36 ;
     RECT  16.513 51.36 17.088 51.384 ;
     RECT  16.513 51.384 17.1 51.456 ;
     RECT  16.513 51.456 17.088 51.48 ;
     RECT  16.513 51.48 17.1 51.6 ;
     RECT  16.513 51.6 17.088 51.624 ;
     RECT  16.513 51.624 17.1 51.696 ;
     RECT  16.513 51.696 17.088 51.72 ;
     RECT  16.513 51.72 17.1 51.792 ;
     RECT  16.513 51.792 17.088 51.816 ;
     RECT  16.513 51.816 17.1 51.888 ;
     RECT  16.513 51.888 17.088 51.912 ;
     RECT  16.513 51.912 17.1 51.984 ;
     RECT  16.513 51.984 17.088 52.008 ;
     RECT  16.513 52.008 17.1 52.128 ;
     RECT  16.513 52.128 17.088 52.152 ;
     RECT  16.513 52.152 17.1 52.224 ;
     RECT  16.513 52.224 17.088 52.248 ;
     RECT  16.513 52.248 17.1 52.32 ;
     RECT  16.513 52.32 17.088 52.344 ;
     RECT  16.513 52.344 17.1 52.416 ;
     RECT  16.513 52.416 17.088 52.44 ;
     RECT  16.513 52.44 17.1 52.512 ;
     RECT  16.513 52.512 17.088 52.536 ;
     RECT  16.513 52.536 17.1 52.656 ;
     RECT  16.513 52.656 17.088 52.68 ;
     RECT  16.513 52.68 17.1 52.752 ;
     RECT  16.513 52.752 17.088 52.776 ;
     RECT  16.513 52.776 17.1 52.848 ;
     RECT  16.513 52.848 17.088 52.872 ;
     RECT  16.513 52.872 17.1 52.944 ;
     RECT  16.513 52.944 17.088 52.968 ;
     RECT  16.513 52.968 17.1 53.04 ;
     RECT  16.513 53.04 17.088 53.064 ;
     RECT  16.513 53.064 17.1 53.184 ;
     RECT  16.513 53.184 17.088 53.208 ;
     RECT  16.513 53.208 17.1 53.28 ;
     RECT  16.513 53.28 17.088 53.304 ;
     RECT  16.513 53.304 17.1 53.376 ;
     RECT  16.513 53.376 17.088 53.4 ;
     RECT  16.513 53.4 17.1 53.472 ;
     RECT  16.513 53.472 17.088 53.496 ;
     RECT  16.513 53.496 17.1 53.568 ;
     RECT  16.513 53.568 17.088 53.592 ;
     RECT  16.513 53.592 17.1 53.712 ;
     RECT  16.513 53.712 17.088 53.736 ;
     RECT  16.513 53.736 17.1 53.808 ;
     RECT  16.513 53.808 17.088 53.832 ;
     RECT  16.513 53.832 17.1 53.904 ;
     RECT  16.513 53.904 17.088 53.928 ;
     RECT  16.513 53.928 17.1 54 ;
     RECT  16.513 54 17.088 54.024 ;
     RECT  16.513 54.024 17.1 54.096 ;
     RECT  16.513 54.096 17.088 54.12 ;
     RECT  16.513 54.12 17.1 54.24 ;
     RECT  16.513 54.24 17.088 54.264 ;
     RECT  16.513 54.264 17.1 54.336 ;
     RECT  16.513 54.336 17.088 54.36 ;
     RECT  16.513 54.36 17.1 54.432 ;
     RECT  16.513 54.432 17.088 54.456 ;
     RECT  16.513 54.456 17.1 54.528 ;
     RECT  16.513 54.528 17.088 54.552 ;
     RECT  16.513 54.552 17.1 54.624 ;
     RECT  16.513 54.624 17.088 54.648 ;
     RECT  16.513 54.648 17.1 54.768 ;
     RECT  16.513 54.768 17.088 54.792 ;
     RECT  16.513 54.792 17.1 54.864 ;
     RECT  16.513 54.864 17.088 54.888 ;
     RECT  16.513 54.888 17.1 54.96 ;
     RECT  16.513 54.96 17.088 54.984 ;
     RECT  16.513 54.984 17.1 55.056 ;
     RECT  16.513 55.056 17.088 55.08 ;
     RECT  16.513 55.08 17.1 55.152 ;
     RECT  16.513 55.152 17.088 55.176 ;
     RECT  16.513 55.176 17.1 55.296 ;
     RECT  16.513 55.296 17.088 55.32 ;
     RECT  16.513 55.32 17.1 55.392 ;
     RECT  16.513 55.392 17.088 55.416 ;
     RECT  16.513 55.416 17.1 55.488 ;
     RECT  16.513 55.488 17.088 55.512 ;
     RECT  16.513 55.512 17.1 55.584 ;
     RECT  16.513 55.584 17.088 55.608 ;
     RECT  16.513 55.608 17.1 55.68 ;
     RECT  16.513 55.68 17.088 55.704 ;
     RECT  16.513 55.704 17.1 55.824 ;
     RECT  16.513 55.824 17.088 55.848 ;
     RECT  16.513 55.848 17.1 55.92 ;
     RECT  16.513 55.92 17.088 55.944 ;
     RECT  16.513 55.944 17.1 56.016 ;
     RECT  16.513 56.016 17.088 56.04 ;
     RECT  16.513 56.04 17.1 56.112 ;
     RECT  16.513 56.112 17.088 56.136 ;
     RECT  17.1 3.648 17.165 3.696 ;
     RECT  17.1 3.72 17.165 3.792 ;
     RECT  17.1 3.816 17.165 3.864 ;
     RECT  17.1 5.232 17.165 5.256 ;
     RECT  17.1 7.344 17.165 7.368 ;
     RECT  17.1 8.496 17.165 8.52 ;
     RECT  17.1 10.704 17.165 10.728 ;
     RECT  17.1 13.68 17.165 13.728 ;
     RECT  17.1 13.752 17.165 13.824 ;
     RECT  17.1 13.848 17.165 13.92 ;
     RECT  17.1 13.944 17.165 14.016 ;
     RECT  17.1 14.04 17.165 14.16 ;
     RECT  17.1 14.184 17.165 14.256 ;
     RECT  17.1 14.28 17.165 14.352 ;
     RECT  17.1 14.376 17.165 14.424 ;
     RECT  17.1 16.512 17.165 16.56 ;
     RECT  17.1 16.584 17.165 16.656 ;
     RECT  17.1 16.68 17.165 16.8 ;
     RECT  17.1 16.824 17.165 16.896 ;
     RECT  17.1 16.92 17.165 16.992 ;
     RECT  17.1 17.016 17.165 17.088 ;
     RECT  17.1 17.112 17.165 17.184 ;
     RECT  17.1 17.208 17.165 17.328 ;
     RECT  17.1 17.352 17.165 17.424 ;
     RECT  17.1 17.448 17.165 17.52 ;
     RECT  17.1 17.544 17.165 17.616 ;
     RECT  17.1 17.64 17.165 17.712 ;
     RECT  17.1 17.736 17.165 17.856 ;
     RECT  17.1 17.88 17.165 17.928 ;
     RECT  17.1 18.96 17.165 18.984 ;
     RECT  17.1 20.928 17.165 20.952 ;
     RECT  17.1 23.664 17.165 23.688 ;
     RECT  17.1 25.488 17.165 25.512 ;
     RECT  17.1 30.144 17.165 30.192 ;
     RECT  17.1 30.216 17.165 30.288 ;
     RECT  17.1 30.312 17.165 30.36 ;
     RECT  17.1 31.68 17.165 31.704 ;
     RECT  17.1 35.184 17.165 35.232 ;
     RECT  17.1 35.256 17.165 35.328 ;
     RECT  17.1 35.352 17.165 35.424 ;
     RECT  17.1 35.448 17.165 35.568 ;
     RECT  17.1 35.592 17.165 35.664 ;
     RECT  17.1 35.688 17.165 35.76 ;
     RECT  17.1 35.784 17.165 35.856 ;
     RECT  17.1 35.88 17.165 35.952 ;
     RECT  17.1 35.976 17.165 36.096 ;
     RECT  17.1 36.12 17.165 36.192 ;
     RECT  17.1 36.216 17.165 36.288 ;
     RECT  17.1 36.312 17.165 36.384 ;
     RECT  17.1 36.408 17.165 36.48 ;
     RECT  17.1 36.504 17.165 36.624 ;
     RECT  17.1 36.648 17.165 36.72 ;
     RECT  17.1 36.744 17.165 36.816 ;
     RECT  17.1 36.84 17.165 36.912 ;
     RECT  17.1 36.936 17.165 37.008 ;
     RECT  17.1 37.032 17.165 37.152 ;
     RECT  17.1 37.176 17.165 37.248 ;
     RECT  17.1 37.272 17.165 37.344 ;
     RECT  17.1 37.368 17.165 37.44 ;
     RECT  17.1 37.464 17.165 37.536 ;
     RECT  17.1 37.56 17.165 37.68 ;
     RECT  17.1 37.704 17.165 37.776 ;
     RECT  17.1 37.8 17.165 37.872 ;
     RECT  17.1 37.896 17.165 37.944 ;
     RECT  17.1 38.976 17.165 39.024 ;
     RECT  17.1 39.048 17.165 39.12 ;
     RECT  17.1 39.144 17.165 39.264 ;
     RECT  17.1 39.288 17.165 39.36 ;
     RECT  17.1 39.384 17.165 39.432 ;
     RECT  17.1 40.656 17.165 40.704 ;
     RECT  17.1 40.728 17.165 40.848 ;
     RECT  17.1 40.872 17.165 40.944 ;
     RECT  17.1 40.968 17.165 41.04 ;
     RECT  17.1 41.064 17.165 41.136 ;
     RECT  17.1 41.16 17.165 41.232 ;
     RECT  17.1 41.256 17.165 41.376 ;
     RECT  17.1 41.4 17.165 41.448 ;
     RECT  17.1 42.576 17.165 42.6 ;
     RECT  17.1 44.448 17.165 44.496 ;
     RECT  17.1 44.52 17.165 44.64 ;
     RECT  17.1 44.664 17.165 44.712 ;
     RECT  17.1 46.8 17.165 46.848 ;
     RECT  17.1 46.872 17.165 46.944 ;
     RECT  17.1 46.968 17.165 47.04 ;
     RECT  17.1 47.064 17.165 47.136 ;
     RECT  17.1 47.16 17.165 47.28 ;
     RECT  17.1 47.304 17.165 47.376 ;
     RECT  17.1 47.4 17.165 47.448 ;
     RECT  17.1 49.2 17.165 49.224 ;
     RECT  17.1 50.256 17.165 50.28 ;
     RECT  17.1 52.8 17.165 52.824 ;
     RECT  17.1 53.856 17.165 53.904 ;
     RECT  17.1 53.928 17.165 54 ;
     RECT  17.1 54.024 17.165 54.096 ;
     RECT  17.1 54.12 17.165 54.24 ;
     RECT  17.1 54.264 17.165 54.336 ;
     RECT  17.1 54.36 17.165 54.432 ;
     RECT  17.1 54.456 17.165 54.528 ;
     RECT  17.1 54.552 17.165 54.624 ;
     RECT  17.1 54.648 17.165 54.768 ;
     RECT  17.1 54.792 17.165 54.864 ;
     RECT  17.1 54.888 17.165 54.96 ;
     RECT  17.1 54.984 17.165 55.032 ;
    LAYER M5 ;
     RECT  2.4 2.137 2.52 2.151 ;
     RECT  5.1 2.137 5.22 2.151 ;
     RECT  7.8 2.137 7.92 2.151 ;
     RECT  10.5 2.137 10.62 2.151 ;
     RECT  13.2 2.137 13.32 2.151 ;
     RECT  7.8 2.151 8.112 2.245 ;
     RECT  2.4 2.151 2.712 2.581 ;
     RECT  2.304 2.581 2.712 2.771 ;
     RECT  6.816 2.245 8.112 2.821 ;
     RECT  6.816 2.821 8.52 3.491 ;
     RECT  6.816 3.491 8.112 4.115 ;
     RECT  12.048 4.309 12.072 4.451 ;
     RECT  13.2 2.151 13.512 4.741 ;
     RECT  13.2 4.741 13.944 5.027 ;
     RECT  13.2 5.027 13.512 7.381 ;
     RECT  13.104 7.381 13.512 7.523 ;
     RECT  10.5 2.151 10.812 7.957 ;
     RECT  7.8 4.115 8.112 8.389 ;
     RECT  9.168 6.757 9.192 8.389 ;
     RECT  7.8 8.389 9.192 9.541 ;
     RECT  10.368 7.957 10.812 9.541 ;
     RECT  7.8 9.541 10.812 9.683 ;
     RECT  7.8 9.683 8.232 10.883 ;
     RECT  14.832 11.749 14.856 11.939 ;
     RECT  7.8 10.883 8.112 13.381 ;
     RECT  9.456 9.683 10.812 13.381 ;
     RECT  7.8 13.381 10.812 13.669 ;
     RECT  7.8 13.669 11.64 13.861 ;
     RECT  7.8 13.861 11.736 14.147 ;
     RECT  0.192 14.485 0.216 14.771 ;
     RECT  7.8 14.147 10.812 15.059 ;
     RECT  7.8 15.059 8.112 15.301 ;
     RECT  7.68 15.301 8.112 16.069 ;
     RECT  9.12 15.059 10.812 16.069 ;
     RECT  7.68 16.069 10.812 16.739 ;
     RECT  7.68 16.739 8.112 17.939 ;
     RECT  9.888 16.739 10.812 18.275 ;
     RECT  9.936 18.275 10.812 19.285 ;
     RECT  9.936 19.285 11.016 19.429 ;
     RECT  7.8 17.939 8.112 19.957 ;
     RECT  9.792 19.429 11.016 19.957 ;
     RECT  2.4 2.771 2.712 20.053 ;
     RECT  13.2 7.523 13.512 20.101 ;
     RECT  2.304 20.053 2.712 20.195 ;
     RECT  13.2 20.101 13.944 20.339 ;
     RECT  13.2 20.339 13.512 20.389 ;
     RECT  7.8 19.957 11.016 20.579 ;
     RECT  7.8 20.579 10.812 20.771 ;
     RECT  12.576 20.389 13.512 21.779 ;
     RECT  9.12 20.771 10.812 21.827 ;
     RECT  9.792 21.827 10.812 23.509 ;
     RECT  2.4 20.195 2.712 23.653 ;
     RECT  9.12 23.509 10.812 23.699 ;
     RECT  2.256 23.653 2.712 23.843 ;
     RECT  9.648 23.699 10.812 24.611 ;
     RECT  0.288 24.709 0.312 24.995 ;
     RECT  12.048 26.005 12.072 26.195 ;
     RECT  7.8 20.771 8.112 26.437 ;
     RECT  14.832 25.909 14.856 26.723 ;
     RECT  7.8 26.437 8.232 26.771 ;
     RECT  6.528 23.029 6.552 27.685 ;
     RECT  7.8 26.771 8.112 27.685 ;
     RECT  6.528 27.685 8.112 27.731 ;
     RECT  0.288 27.733 0.312 27.923 ;
     RECT  7.296 27.731 8.112 28.021 ;
     RECT  9.792 24.611 10.812 28.021 ;
     RECT  5.1 2.151 5.412 28.501 ;
     RECT  7.296 28.021 10.812 28.547 ;
     RECT  7.296 28.547 9.144 28.691 ;
     RECT  7.68 28.691 9.144 28.883 ;
     RECT  9.12 28.883 9.144 29.075 ;
     RECT  5.1 28.501 5.592 29.893 ;
     RECT  7.68 28.883 8.112 29.939 ;
     RECT  15.984 30.997 16.008 31.187 ;
     RECT  10.128 28.547 10.812 33.013 ;
     RECT  7.8 29.939 8.112 33.349 ;
     RECT  9.36 33.013 10.812 33.349 ;
     RECT  14.832 34.645 14.856 34.787 ;
     RECT  13.2 21.779 13.512 35.269 ;
     RECT  12.528 35.269 13.512 35.461 ;
     RECT  12.048 35.461 13.512 35.747 ;
     RECT  7.8 33.349 10.812 36.421 ;
     RECT  12.528 35.747 13.512 36.563 ;
     RECT  7.8 36.421 11.064 36.947 ;
     RECT  0.192 36.805 0.216 36.995 ;
     RECT  9.312 36.947 11.064 37.669 ;
     RECT  9.312 37.669 11.16 37.955 ;
     RECT  12.576 36.563 13.512 38.147 ;
     RECT  7.8 36.947 8.112 38.149 ;
     RECT  7.68 38.149 8.112 39.731 ;
     RECT  5.1 29.893 6.456 40.213 ;
     RECT  5.1 40.213 6.792 40.259 ;
     RECT  9.312 37.955 10.812 40.501 ;
     RECT  9.12 40.501 10.812 40.691 ;
     RECT  7.8 39.731 8.112 41.653 ;
     RECT  7.8 41.653 8.232 41.891 ;
     RECT  13.2 38.147 13.512 42.517 ;
     RECT  13.104 42.517 13.512 42.659 ;
     RECT  9.6 40.691 10.812 42.851 ;
     RECT  0.288 42.901 0.312 43.091 ;
     RECT  7.8 41.891 8.112 43.189 ;
     RECT  14.832 43.093 14.856 43.331 ;
     RECT  7.8 43.189 8.616 43.475 ;
     RECT  1.152 44.629 1.176 44.963 ;
     RECT  9.648 42.851 10.812 45.923 ;
     RECT  9.984 45.923 10.812 46.309 ;
     RECT  9.984 46.309 11.64 46.643 ;
     RECT  13.2 42.659 13.512 46.645 ;
     RECT  9.984 46.643 10.812 46.885 ;
     RECT  9.216 46.885 10.812 47.317 ;
     RECT  9.12 47.317 10.812 47.843 ;
     RECT  12.576 46.645 13.512 47.845 ;
     RECT  12 47.845 13.512 47.939 ;
     RECT  12 47.939 12.024 48.515 ;
     RECT  7.8 43.475 8.112 49.333 ;
     RECT  6.768 40.259 6.792 49.573 ;
     RECT  7.8 49.333 8.376 49.573 ;
     RECT  6.768 49.573 8.376 50.819 ;
     RECT  7.8 50.819 8.376 50.917 ;
     RECT  9.984 47.843 10.812 50.917 ;
     RECT  13.2 47.939 13.512 51.013 ;
     RECT  7.8 50.917 10.812 51.203 ;
     RECT  13.056 51.013 13.512 51.251 ;
     RECT  9.984 51.203 10.812 52.021 ;
     RECT  7.8 51.203 8.376 52.165 ;
     RECT  9.984 52.021 11.64 52.165 ;
     RECT  7.8 52.165 11.64 52.451 ;
     RECT  7.8 52.451 10.812 52.499 ;
     RECT  6.768 50.819 6.792 53.075 ;
     RECT  13.2 51.251 13.512 53.077 ;
     RECT  7.8 52.499 9.144 53.125 ;
     RECT  13.2 53.077 14.04 53.315 ;
     RECT  6.816 53.125 9.144 53.363 ;
     RECT  13.2 53.315 13.944 53.363 ;
     RECT  5.1 40.259 5.592 54.133 ;
     RECT  6.816 53.363 8.376 54.179 ;
     RECT  6.816 54.179 8.112 55.427 ;
     RECT  4.8 54.133 5.592 55.907 ;
     RECT  2.4 23.843 2.712 56.169 ;
     RECT  7.8 55.427 8.112 56.169 ;
     RECT  10.5 52.499 10.812 56.169 ;
     RECT  13.2 53.363 13.512 56.169 ;
     RECT  2.4 56.169 2.52 56.183 ;
     RECT  5.1 55.907 5.592 56.183 ;
     RECT  7.8 56.169 7.92 56.183 ;
     RECT  10.5 56.169 10.62 56.183 ;
     RECT  13.2 56.169 13.32 56.183 ;
     RECT  5.568 56.183 5.592 57.635 ;
     RECT  11.424 58.192 11.448 58.259 ;
     RECT  5.412 2.245 6.816 4.115 ;
     RECT  10.812 4.309 12.048 4.451 ;
     RECT  12.072 4.309 13.2 4.451 ;
     RECT  8.112 6.757 9.168 8.389 ;
     RECT  9.192 6.757 10.5 7.957 ;
     RECT  9.192 7.957 10.368 9.541 ;
     RECT  8.232 9.683 9.456 10.883 ;
     RECT  8.112 10.883 9.456 13.381 ;
     RECT  13.512 11.749 14.832 11.939 ;
     RECT  11.736 13.861 13.2 14.147 ;
     RECT  8.112 15.059 9.12 16.069 ;
     RECT  9.888 18.275 9.936 19.429 ;
     RECT  8.112 20.771 9.12 21.827 ;
     RECT  5.412 23.029 6.528 27.731 ;
     RECT  6.552 23.029 7.8 27.685 ;
     RECT  8.112 23.509 9.12 23.699 ;
     RECT  13.512 25.909 14.832 26.723 ;
     RECT  10.812 26.005 12.048 26.195 ;
     RECT  12.072 26.005 13.2 26.195 ;
     RECT  8.112 26.771 8.232 28.021 ;
     RECT  5.412 27.731 5.592 28.501 ;
     RECT  9.144 28.547 10.128 29.075 ;
     RECT  7.296 28.691 7.68 29.893 ;
     RECT  8.112 28.883 9.12 29.075 ;
     RECT  6.456 29.893 7.68 29.939 ;
     RECT  6.456 29.939 7.8 38.149 ;
     RECT  8.112 33.013 9.36 33.349 ;
     RECT  13.512 34.645 14.832 34.787 ;
     RECT  10.812 35.461 12.048 35.747 ;
     RECT  10.812 35.747 12.528 36.421 ;
     RECT  11.064 36.421 12.528 36.563 ;
     RECT  11.064 36.563 12.576 37.669 ;
     RECT  8.112 36.947 9.312 40.501 ;
     RECT  11.16 37.669 12.576 37.955 ;
     RECT  6.456 38.149 7.68 39.731 ;
     RECT  6.456 39.731 7.8 40.213 ;
     RECT  6.792 40.213 7.8 49.573 ;
     RECT  5.592 40.259 6.768 53.075 ;
     RECT  8.112 40.501 9.12 40.691 ;
     RECT  8.112 40.691 9.6 41.653 ;
     RECT  8.232 41.653 9.6 41.891 ;
     RECT  8.112 41.891 9.6 42.851 ;
     RECT  8.112 42.851 9.648 43.189 ;
     RECT  13.512 43.093 14.832 43.331 ;
     RECT  8.616 43.189 9.648 43.475 ;
     RECT  1.176 44.629 2.4 44.963 ;
     RECT  9.648 45.923 9.984 46.885 ;
     RECT  10.812 46.643 11.64 46.645 ;
     RECT  10.812 46.645 12.576 47.845 ;
     RECT  8.112 46.885 9.216 47.317 ;
     RECT  8.112 47.317 9.12 47.843 ;
     RECT  8.112 47.843 8.376 49.333 ;
     RECT  10.812 47.845 12 48.515 ;
     RECT  12.024 47.939 13.2 48.515 ;
     RECT  6.792 50.819 7.8 53.075 ;
     RECT  8.376 51.203 9.984 52.165 ;
     RECT  9.144 52.499 10.5 53.363 ;
     RECT  5.592 53.075 7.8 53.125 ;
     RECT  5.592 53.125 6.816 55.427 ;
  END
END dsfd_dvrly_512_EW
END LIBRARY
